VERSION 5.8 ;
BUSBITCHARS "[]" ;
DIVIDERCHAR "/" ;
UNITS
    DATABASE MICRONS 1000 ;
END UNITS

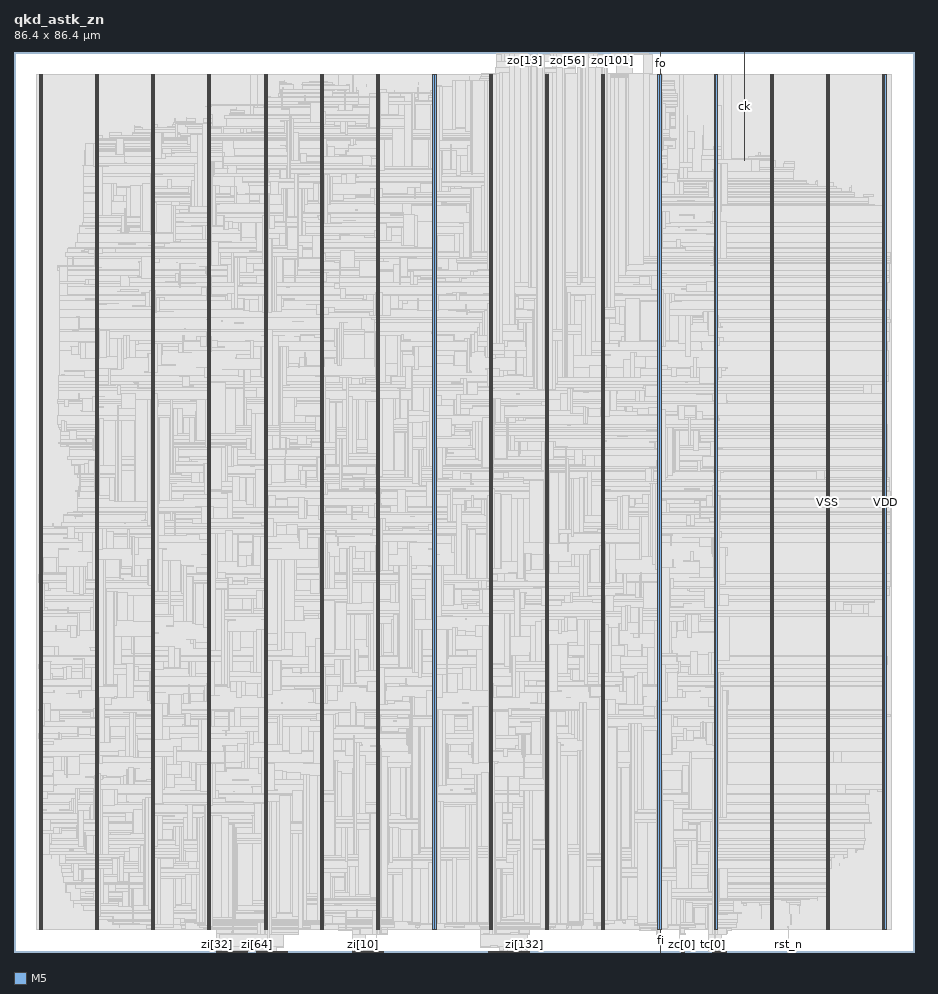
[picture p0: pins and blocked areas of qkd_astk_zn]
MACRO qkd_astk_zn
  FOREIGN qkd_astk_zn 0 0 ;
  CLASS BLOCK ;
  SIZE 86.4 BY 86.4 ;
  PIN ck
    DIRECTION INPUT ;
    USE SIGNAL ;
    PORT
      LAYER M5 ;
        RECT  70.128 86.316 70.152 86.4 ;
    END
    PORT
      LAYER M5 ;
        RECT  70.128 75.971 70.152 86.352 ;
    END
  END ck
  PIN fi
    DIRECTION INPUT ;
    USE SIGNAL ;
    PORT
      LAYER M5 ;
        RECT  62.064 0 62.088 0.084 ;
    END
    PORT
      LAYER M5 ;
        RECT  62.064 0.016 62.088 2.137 ;
    END
  END fi
  PIN fo
    DIRECTION OUTPUT ;
    USE SIGNAL ;
    PORT
      LAYER M5 ;
        RECT  62.064 86.316 62.088 86.4 ;
    END
    PORT
      LAYER M5 ;
        RECT  62.064 84.263 62.088 86.352 ;
    END
  END fo
  PIN rst_n
    DIRECTION INPUT ;
    USE SIGNAL ;
    PORT
      LAYER M5 ;
        RECT  74.352 0 74.376 0.084 ;
    END
    PORT
      LAYER M5 ;
        RECT  74.352 0.016 74.376 0.611 ;
    END
  END rst_n
  PIN tc[0]
    DIRECTION INPUT ;
    USE SIGNAL ;
    PORT
      LAYER M5 ;
        RECT  67.056 0 67.08 0.084 ;
    END
  END tc[0]
  PIN tc[10]
    DIRECTION INPUT ;
    USE SIGNAL ;
    PORT
      LAYER M5 ;
        RECT  68.016 0 68.04 0.084 ;
    END
  END tc[10]
  PIN tc[11]
    DIRECTION INPUT ;
    USE SIGNAL ;
    PORT
      LAYER M5 ;
        RECT  68.112 0 68.136 0.084 ;
    END
  END tc[11]
  PIN tc[12]
    DIRECTION INPUT ;
    USE SIGNAL ;
    PORT
      LAYER M5 ;
        RECT  68.208 0 68.232 0.084 ;
    END
  END tc[12]
  PIN tc[13]
    DIRECTION INPUT ;
    USE SIGNAL ;
    PORT
      LAYER M5 ;
        RECT  68.304 0 68.328 0.084 ;
    END
  END tc[13]
  PIN tc[14]
    DIRECTION INPUT ;
    USE SIGNAL ;
    PORT
      LAYER M5 ;
        RECT  68.4 0 68.424 0.084 ;
    END
  END tc[14]
  PIN tc[1]
    DIRECTION INPUT ;
    USE SIGNAL ;
    PORT
      LAYER M5 ;
        RECT  67.152 0 67.176 0.084 ;
    END
  END tc[1]
  PIN tc[2]
    DIRECTION INPUT ;
    USE SIGNAL ;
    PORT
      LAYER M5 ;
        RECT  67.248 0 67.272 0.084 ;
    END
  END tc[2]
  PIN tc[3]
    DIRECTION INPUT ;
    USE SIGNAL ;
    PORT
      LAYER M5 ;
        RECT  67.344 0 67.368 0.084 ;
    END
  END tc[3]
  PIN tc[4]
    DIRECTION INPUT ;
    USE SIGNAL ;
    PORT
      LAYER M5 ;
        RECT  67.44 0 67.464 0.084 ;
    END
  END tc[4]
  PIN tc[5]
    DIRECTION INPUT ;
    USE SIGNAL ;
    PORT
      LAYER M5 ;
        RECT  67.536 0 67.56 0.084 ;
    END
  END tc[5]
  PIN tc[6]
    DIRECTION INPUT ;
    USE SIGNAL ;
    PORT
      LAYER M5 ;
        RECT  67.632 0 67.656 0.084 ;
    END
  END tc[6]
  PIN tc[7]
    DIRECTION INPUT ;
    USE SIGNAL ;
    PORT
      LAYER M5 ;
        RECT  67.728 0 67.752 0.084 ;
    END
  END tc[7]
  PIN tc[8]
    DIRECTION INPUT ;
    USE SIGNAL ;
    PORT
      LAYER M5 ;
        RECT  67.824 0 67.848 0.084 ;
    END
  END tc[8]
  PIN tc[9]
    DIRECTION INPUT ;
    USE SIGNAL ;
    PORT
      LAYER M5 ;
        RECT  67.92 0 67.944 0.084 ;
    END
  END tc[9]
  PIN zc[0]
    DIRECTION INPUT ;
    USE SIGNAL ;
    PORT
      LAYER M5 ;
        RECT  64.08 0 64.104 0.084 ;
    END
  END zc[0]
  PIN zc[1]
    DIRECTION INPUT ;
    USE SIGNAL ;
    PORT
      LAYER M5 ;
        RECT  64.176 0 64.2 0.084 ;
    END
  END zc[1]
  PIN zc[2]
    DIRECTION INPUT ;
    USE SIGNAL ;
    PORT
      LAYER M5 ;
        RECT  64.272 0 64.296 0.084 ;
    END
  END zc[2]
  PIN zc[3]
    DIRECTION INPUT ;
    USE SIGNAL ;
    PORT
      LAYER M5 ;
        RECT  64.368 0 64.392 0.084 ;
    END
  END zc[3]
  PIN zi[0]
    DIRECTION INPUT ;
    USE SIGNAL ;
    PORT
      LAYER M5 ;
        RECT  32.496 0 32.52 0.084 ;
    END
  END zi[0]
  PIN zi[100]
    DIRECTION INPUT ;
    USE SIGNAL ;
    PORT
      LAYER M5 ;
        RECT  45.936 0 45.96 0.084 ;
    END
  END zi[100]
  PIN zi[101]
    DIRECTION INPUT ;
    USE SIGNAL ;
    PORT
      LAYER M5 ;
        RECT  46.032 0 46.056 0.084 ;
    END
  END zi[101]
  PIN zi[102]
    DIRECTION INPUT ;
    USE SIGNAL ;
    PORT
      LAYER M5 ;
        RECT  46.128 0 46.152 0.084 ;
    END
  END zi[102]
  PIN zi[103]
    DIRECTION INPUT ;
    USE SIGNAL ;
    PORT
      LAYER M5 ;
        RECT  46.224 0 46.248 0.084 ;
    END
  END zi[103]
  PIN zi[104]
    DIRECTION INPUT ;
    USE SIGNAL ;
    PORT
      LAYER M5 ;
        RECT  46.32 0 46.344 0.084 ;
    END
  END zi[104]
  PIN zi[105]
    DIRECTION INPUT ;
    USE SIGNAL ;
    PORT
      LAYER M5 ;
        RECT  46.416 0 46.44 0.084 ;
    END
  END zi[105]
  PIN zi[106]
    DIRECTION INPUT ;
    USE SIGNAL ;
    PORT
      LAYER M5 ;
        RECT  46.512 0 46.536 0.084 ;
    END
  END zi[106]
  PIN zi[107]
    DIRECTION INPUT ;
    USE SIGNAL ;
    PORT
      LAYER M5 ;
        RECT  46.608 0 46.632 0.084 ;
    END
  END zi[107]
  PIN zi[108]
    DIRECTION INPUT ;
    USE SIGNAL ;
    PORT
      LAYER M5 ;
        RECT  46.704 0 46.728 0.084 ;
    END
  END zi[108]
  PIN zi[109]
    DIRECTION INPUT ;
    USE SIGNAL ;
    PORT
      LAYER M5 ;
        RECT  46.8 0 46.824 0.084 ;
    END
  END zi[109]
  PIN zi[10]
    DIRECTION INPUT ;
    USE SIGNAL ;
    PORT
      LAYER M5 ;
        RECT  33.456 0 33.48 0.084 ;
    END
  END zi[10]
  PIN zi[110]
    DIRECTION INPUT ;
    USE SIGNAL ;
    PORT
      LAYER M5 ;
        RECT  46.896 0 46.92 0.084 ;
    END
  END zi[110]
  PIN zi[111]
    DIRECTION INPUT ;
    USE SIGNAL ;
    PORT
      LAYER M5 ;
        RECT  46.992 0 47.016 0.084 ;
    END
  END zi[111]
  PIN zi[112]
    DIRECTION INPUT ;
    USE SIGNAL ;
    PORT
      LAYER M5 ;
        RECT  47.088 0 47.112 0.084 ;
    END
  END zi[112]
  PIN zi[113]
    DIRECTION INPUT ;
    USE SIGNAL ;
    PORT
      LAYER M5 ;
        RECT  47.184 0 47.208 0.084 ;
    END
  END zi[113]
  PIN zi[114]
    DIRECTION INPUT ;
    USE SIGNAL ;
    PORT
      LAYER M5 ;
        RECT  47.28 0 47.304 0.084 ;
    END
  END zi[114]
  PIN zi[115]
    DIRECTION INPUT ;
    USE SIGNAL ;
    PORT
      LAYER M5 ;
        RECT  47.376 0 47.4 0.084 ;
    END
  END zi[115]
  PIN zi[116]
    DIRECTION INPUT ;
    USE SIGNAL ;
    PORT
      LAYER M5 ;
        RECT  47.472 0 47.496 0.084 ;
    END
  END zi[116]
  PIN zi[117]
    DIRECTION INPUT ;
    USE SIGNAL ;
    PORT
      LAYER M5 ;
        RECT  47.568 0 47.592 0.084 ;
    END
  END zi[117]
  PIN zi[118]
    DIRECTION INPUT ;
    USE SIGNAL ;
    PORT
      LAYER M5 ;
        RECT  47.664 0 47.688 0.084 ;
    END
  END zi[118]
  PIN zi[119]
    DIRECTION INPUT ;
    USE SIGNAL ;
    PORT
      LAYER M5 ;
        RECT  47.76 0 47.784 0.084 ;
    END
  END zi[119]
  PIN zi[11]
    DIRECTION INPUT ;
    USE SIGNAL ;
    PORT
      LAYER M5 ;
        RECT  33.552 0 33.576 0.084 ;
    END
  END zi[11]
  PIN zi[120]
    DIRECTION INPUT ;
    USE SIGNAL ;
    PORT
      LAYER M5 ;
        RECT  47.856 0 47.88 0.084 ;
    END
  END zi[120]
  PIN zi[121]
    DIRECTION INPUT ;
    USE SIGNAL ;
    PORT
      LAYER M5 ;
        RECT  47.952 0 47.976 0.084 ;
    END
  END zi[121]
  PIN zi[122]
    DIRECTION INPUT ;
    USE SIGNAL ;
    PORT
      LAYER M5 ;
        RECT  48.048 0 48.072 0.084 ;
    END
  END zi[122]
  PIN zi[123]
    DIRECTION INPUT ;
    USE SIGNAL ;
    PORT
      LAYER M5 ;
        RECT  48.144 0 48.168 0.084 ;
    END
  END zi[123]
  PIN zi[124]
    DIRECTION INPUT ;
    USE SIGNAL ;
    PORT
      LAYER M5 ;
        RECT  48.24 0 48.264 0.084 ;
    END
  END zi[124]
  PIN zi[125]
    DIRECTION INPUT ;
    USE SIGNAL ;
    PORT
      LAYER M5 ;
        RECT  48.336 0 48.36 0.084 ;
    END
  END zi[125]
  PIN zi[126]
    DIRECTION INPUT ;
    USE SIGNAL ;
    PORT
      LAYER M5 ;
        RECT  48.432 0 48.456 0.084 ;
    END
  END zi[126]
  PIN zi[127]
    DIRECTION INPUT ;
    USE SIGNAL ;
    PORT
      LAYER M5 ;
        RECT  48.528 0 48.552 0.084 ;
    END
  END zi[127]
  PIN zi[128]
    DIRECTION INPUT ;
    USE SIGNAL ;
    PORT
      LAYER M5 ;
        RECT  48.624 0 48.648 0.084 ;
    END
  END zi[128]
  PIN zi[129]
    DIRECTION INPUT ;
    USE SIGNAL ;
    PORT
      LAYER M5 ;
        RECT  48.72 0 48.744 0.084 ;
    END
  END zi[129]
  PIN zi[12]
    DIRECTION INPUT ;
    USE SIGNAL ;
    PORT
      LAYER M5 ;
        RECT  33.648 0 33.672 0.084 ;
    END
  END zi[12]
  PIN zi[130]
    DIRECTION INPUT ;
    USE SIGNAL ;
    PORT
      LAYER M5 ;
        RECT  48.816 0 48.84 0.084 ;
    END
  END zi[130]
  PIN zi[131]
    DIRECTION INPUT ;
    USE SIGNAL ;
    PORT
      LAYER M5 ;
        RECT  48.912 0 48.936 0.084 ;
    END
  END zi[131]
  PIN zi[132]
    DIRECTION INPUT ;
    USE SIGNAL ;
    PORT
      LAYER M5 ;
        RECT  49.008 0 49.032 0.084 ;
    END
  END zi[132]
  PIN zi[133]
    DIRECTION INPUT ;
    USE SIGNAL ;
    PORT
      LAYER M5 ;
        RECT  49.104 0 49.128 0.084 ;
    END
  END zi[133]
  PIN zi[134]
    DIRECTION INPUT ;
    USE SIGNAL ;
    PORT
      LAYER M5 ;
        RECT  49.2 0 49.224 0.084 ;
    END
  END zi[134]
  PIN zi[135]
    DIRECTION INPUT ;
    USE SIGNAL ;
    PORT
      LAYER M5 ;
        RECT  49.296 0 49.32 0.084 ;
    END
  END zi[135]
  PIN zi[136]
    DIRECTION INPUT ;
    USE SIGNAL ;
    PORT
      LAYER M5 ;
        RECT  49.392 0 49.416 0.084 ;
    END
  END zi[136]
  PIN zi[137]
    DIRECTION INPUT ;
    USE SIGNAL ;
    PORT
      LAYER M5 ;
        RECT  49.488 0 49.512 0.084 ;
    END
  END zi[137]
  PIN zi[13]
    DIRECTION INPUT ;
    USE SIGNAL ;
    PORT
      LAYER M5 ;
        RECT  33.744 0 33.768 0.084 ;
    END
  END zi[13]
  PIN zi[14]
    DIRECTION INPUT ;
    USE SIGNAL ;
    PORT
      LAYER M5 ;
        RECT  33.84 0 33.864 0.084 ;
    END
  END zi[14]
  PIN zi[15]
    DIRECTION INPUT ;
    USE SIGNAL ;
    PORT
      LAYER M5 ;
        RECT  33.936 0 33.96 0.084 ;
    END
  END zi[15]
  PIN zi[16]
    DIRECTION INPUT ;
    USE SIGNAL ;
    PORT
      LAYER M5 ;
        RECT  34.032 0 34.056 0.084 ;
    END
  END zi[16]
  PIN zi[17]
    DIRECTION INPUT ;
    USE SIGNAL ;
    PORT
      LAYER M5 ;
        RECT  34.128 0 34.152 0.084 ;
    END
  END zi[17]
  PIN zi[18]
    DIRECTION INPUT ;
    USE SIGNAL ;
    PORT
      LAYER M5 ;
        RECT  34.224 0 34.248 0.084 ;
    END
  END zi[18]
  PIN zi[19]
    DIRECTION INPUT ;
    USE SIGNAL ;
    PORT
      LAYER M5 ;
        RECT  34.32 0 34.344 0.084 ;
    END
  END zi[19]
  PIN zi[1]
    DIRECTION INPUT ;
    USE SIGNAL ;
    PORT
      LAYER M5 ;
        RECT  32.592 0 32.616 0.084 ;
    END
  END zi[1]
  PIN zi[20]
    DIRECTION INPUT ;
    USE SIGNAL ;
    PORT
      LAYER M5 ;
        RECT  34.416 0 34.44 0.084 ;
    END
  END zi[20]
  PIN zi[21]
    DIRECTION INPUT ;
    USE SIGNAL ;
    PORT
      LAYER M5 ;
        RECT  34.512 0 34.536 0.084 ;
    END
  END zi[21]
  PIN zi[22]
    DIRECTION INPUT ;
    USE SIGNAL ;
    PORT
      LAYER M5 ;
        RECT  34.608 0 34.632 0.084 ;
    END
  END zi[22]
  PIN zi[23]
    DIRECTION INPUT ;
    USE SIGNAL ;
    PORT
      LAYER M5 ;
        RECT  34.704 0 34.728 0.084 ;
    END
  END zi[23]
  PIN zi[24]
    DIRECTION INPUT ;
    USE SIGNAL ;
    PORT
      LAYER M5 ;
        RECT  34.8 0 34.824 0.084 ;
    END
  END zi[24]
  PIN zi[25]
    DIRECTION INPUT ;
    USE SIGNAL ;
    PORT
      LAYER M5 ;
        RECT  34.896 0 34.92 0.084 ;
    END
  END zi[25]
  PIN zi[26]
    DIRECTION INPUT ;
    USE SIGNAL ;
    PORT
      LAYER M5 ;
        RECT  34.992 0 35.016 0.084 ;
    END
  END zi[26]
  PIN zi[27]
    DIRECTION INPUT ;
    USE SIGNAL ;
    PORT
      LAYER M5 ;
        RECT  35.088 0 35.112 0.084 ;
    END
  END zi[27]
  PIN zi[28]
    DIRECTION INPUT ;
    USE SIGNAL ;
    PORT
      LAYER M5 ;
        RECT  35.184 0 35.208 0.084 ;
    END
  END zi[28]
  PIN zi[29]
    DIRECTION INPUT ;
    USE SIGNAL ;
    PORT
      LAYER M5 ;
        RECT  35.28 0 35.304 0.084 ;
    END
  END zi[29]
  PIN zi[2]
    DIRECTION INPUT ;
    USE SIGNAL ;
    PORT
      LAYER M5 ;
        RECT  32.688 0 32.712 0.084 ;
    END
  END zi[2]
  PIN zi[30]
    DIRECTION INPUT ;
    USE SIGNAL ;
    PORT
      LAYER M5 ;
        RECT  35.376 0 35.4 0.084 ;
    END
  END zi[30]
  PIN zi[31]
    DIRECTION INPUT ;
    USE SIGNAL ;
    PORT
      LAYER M5 ;
        RECT  35.472 0 35.496 0.084 ;
    END
  END zi[31]
  PIN zi[32]
    DIRECTION INPUT ;
    USE SIGNAL ;
    PORT
      LAYER M5 ;
        RECT  19.44 0 19.464 0.084 ;
    END
  END zi[32]
  PIN zi[33]
    DIRECTION INPUT ;
    USE SIGNAL ;
    PORT
      LAYER M5 ;
        RECT  19.536 0 19.56 0.084 ;
    END
  END zi[33]
  PIN zi[34]
    DIRECTION INPUT ;
    USE SIGNAL ;
    PORT
      LAYER M5 ;
        RECT  19.632 0 19.656 0.084 ;
    END
  END zi[34]
  PIN zi[35]
    DIRECTION INPUT ;
    USE SIGNAL ;
    PORT
      LAYER M5 ;
        RECT  19.728 0 19.752 0.084 ;
    END
  END zi[35]
  PIN zi[36]
    DIRECTION INPUT ;
    USE SIGNAL ;
    PORT
      LAYER M5 ;
        RECT  19.824 0 19.848 0.084 ;
    END
  END zi[36]
  PIN zi[37]
    DIRECTION INPUT ;
    USE SIGNAL ;
    PORT
      LAYER M5 ;
        RECT  19.92 0 19.944 0.084 ;
    END
  END zi[37]
  PIN zi[38]
    DIRECTION INPUT ;
    USE SIGNAL ;
    PORT
      LAYER M5 ;
        RECT  20.016 0 20.04 0.084 ;
    END
  END zi[38]
  PIN zi[39]
    DIRECTION INPUT ;
    USE SIGNAL ;
    PORT
      LAYER M5 ;
        RECT  20.112 0 20.136 0.084 ;
    END
  END zi[39]
  PIN zi[3]
    DIRECTION INPUT ;
    USE SIGNAL ;
    PORT
      LAYER M5 ;
        RECT  32.784 0 32.808 0.084 ;
    END
  END zi[3]
  PIN zi[40]
    DIRECTION INPUT ;
    USE SIGNAL ;
    PORT
      LAYER M5 ;
        RECT  20.208 0 20.232 0.084 ;
    END
  END zi[40]
  PIN zi[41]
    DIRECTION INPUT ;
    USE SIGNAL ;
    PORT
      LAYER M5 ;
        RECT  20.304 0 20.328 0.084 ;
    END
  END zi[41]
  PIN zi[42]
    DIRECTION INPUT ;
    USE SIGNAL ;
    PORT
      LAYER M5 ;
        RECT  20.4 0 20.424 0.084 ;
    END
  END zi[42]
  PIN zi[43]
    DIRECTION INPUT ;
    USE SIGNAL ;
    PORT
      LAYER M5 ;
        RECT  20.496 0 20.52 0.084 ;
    END
  END zi[43]
  PIN zi[44]
    DIRECTION INPUT ;
    USE SIGNAL ;
    PORT
      LAYER M5 ;
        RECT  20.592 0 20.616 0.084 ;
    END
  END zi[44]
  PIN zi[45]
    DIRECTION INPUT ;
    USE SIGNAL ;
    PORT
      LAYER M5 ;
        RECT  20.688 0 20.712 0.084 ;
    END
  END zi[45]
  PIN zi[46]
    DIRECTION INPUT ;
    USE SIGNAL ;
    PORT
      LAYER M5 ;
        RECT  20.784 0 20.808 0.084 ;
    END
  END zi[46]
  PIN zi[47]
    DIRECTION INPUT ;
    USE SIGNAL ;
    PORT
      LAYER M5 ;
        RECT  20.88 0 20.904 0.084 ;
    END
  END zi[47]
  PIN zi[48]
    DIRECTION INPUT ;
    USE SIGNAL ;
    PORT
      LAYER M5 ;
        RECT  20.976 0 21 0.084 ;
    END
  END zi[48]
  PIN zi[49]
    DIRECTION INPUT ;
    USE SIGNAL ;
    PORT
      LAYER M5 ;
        RECT  21.072 0 21.096 0.084 ;
    END
  END zi[49]
  PIN zi[4]
    DIRECTION INPUT ;
    USE SIGNAL ;
    PORT
      LAYER M5 ;
        RECT  32.88 0 32.904 0.084 ;
    END
  END zi[4]
  PIN zi[50]
    DIRECTION INPUT ;
    USE SIGNAL ;
    PORT
      LAYER M5 ;
        RECT  21.168 0 21.192 0.084 ;
    END
  END zi[50]
  PIN zi[51]
    DIRECTION INPUT ;
    USE SIGNAL ;
    PORT
      LAYER M5 ;
        RECT  21.264 0 21.288 0.084 ;
    END
  END zi[51]
  PIN zi[52]
    DIRECTION INPUT ;
    USE SIGNAL ;
    PORT
      LAYER M5 ;
        RECT  21.36 0 21.384 0.084 ;
    END
  END zi[52]
  PIN zi[53]
    DIRECTION INPUT ;
    USE SIGNAL ;
    PORT
      LAYER M5 ;
        RECT  21.456 0 21.48 0.084 ;
    END
  END zi[53]
  PIN zi[54]
    DIRECTION INPUT ;
    USE SIGNAL ;
    PORT
      LAYER M5 ;
        RECT  21.552 0 21.576 0.084 ;
    END
  END zi[54]
  PIN zi[55]
    DIRECTION INPUT ;
    USE SIGNAL ;
    PORT
      LAYER M5 ;
        RECT  21.648 0 21.672 0.084 ;
    END
  END zi[55]
  PIN zi[56]
    DIRECTION INPUT ;
    USE SIGNAL ;
    PORT
      LAYER M5 ;
        RECT  21.744 0 21.768 0.084 ;
    END
  END zi[56]
  PIN zi[57]
    DIRECTION INPUT ;
    USE SIGNAL ;
    PORT
      LAYER M5 ;
        RECT  21.84 0 21.864 0.084 ;
    END
  END zi[57]
  PIN zi[58]
    DIRECTION INPUT ;
    USE SIGNAL ;
    PORT
      LAYER M5 ;
        RECT  21.936 0 21.96 0.084 ;
    END
  END zi[58]
  PIN zi[59]
    DIRECTION INPUT ;
    USE SIGNAL ;
    PORT
      LAYER M5 ;
        RECT  22.032 0 22.056 0.084 ;
    END
  END zi[59]
  PIN zi[5]
    DIRECTION INPUT ;
    USE SIGNAL ;
    PORT
      LAYER M5 ;
        RECT  32.976 0 33 0.084 ;
    END
  END zi[5]
  PIN zi[60]
    DIRECTION INPUT ;
    USE SIGNAL ;
    PORT
      LAYER M5 ;
        RECT  22.128 0 22.152 0.084 ;
    END
  END zi[60]
  PIN zi[61]
    DIRECTION INPUT ;
    USE SIGNAL ;
    PORT
      LAYER M5 ;
        RECT  22.224 0 22.248 0.084 ;
    END
  END zi[61]
  PIN zi[62]
    DIRECTION INPUT ;
    USE SIGNAL ;
    PORT
      LAYER M5 ;
        RECT  22.32 0 22.344 0.084 ;
    END
  END zi[62]
  PIN zi[63]
    DIRECTION INPUT ;
    USE SIGNAL ;
    PORT
      LAYER M5 ;
        RECT  22.416 0 22.44 0.084 ;
    END
  END zi[63]
  PIN zi[64]
    DIRECTION INPUT ;
    USE SIGNAL ;
    PORT
      LAYER M5 ;
        RECT  23.28 0 23.304 0.084 ;
    END
  END zi[64]
  PIN zi[65]
    DIRECTION INPUT ;
    USE SIGNAL ;
    PORT
      LAYER M5 ;
        RECT  23.376 0 23.4 0.084 ;
    END
  END zi[65]
  PIN zi[66]
    DIRECTION INPUT ;
    USE SIGNAL ;
    PORT
      LAYER M5 ;
        RECT  23.472 0 23.496 0.084 ;
    END
  END zi[66]
  PIN zi[67]
    DIRECTION INPUT ;
    USE SIGNAL ;
    PORT
      LAYER M5 ;
        RECT  23.568 0 23.592 0.084 ;
    END
  END zi[67]
  PIN zi[68]
    DIRECTION INPUT ;
    USE SIGNAL ;
    PORT
      LAYER M5 ;
        RECT  23.664 0 23.688 0.084 ;
    END
  END zi[68]
  PIN zi[69]
    DIRECTION INPUT ;
    USE SIGNAL ;
    PORT
      LAYER M5 ;
        RECT  23.76 0 23.784 0.084 ;
    END
  END zi[69]
  PIN zi[6]
    DIRECTION INPUT ;
    USE SIGNAL ;
    PORT
      LAYER M5 ;
        RECT  33.072 0 33.096 0.084 ;
    END
  END zi[6]
  PIN zi[70]
    DIRECTION INPUT ;
    USE SIGNAL ;
    PORT
      LAYER M5 ;
        RECT  23.856 0 23.88 0.084 ;
    END
  END zi[70]
  PIN zi[71]
    DIRECTION INPUT ;
    USE SIGNAL ;
    PORT
      LAYER M5 ;
        RECT  23.952 0 23.976 0.084 ;
    END
  END zi[71]
  PIN zi[72]
    DIRECTION INPUT ;
    USE SIGNAL ;
    PORT
      LAYER M5 ;
        RECT  24.048 0 24.072 0.084 ;
    END
  END zi[72]
  PIN zi[73]
    DIRECTION INPUT ;
    USE SIGNAL ;
    PORT
      LAYER M5 ;
        RECT  24.144 0 24.168 0.084 ;
    END
  END zi[73]
  PIN zi[74]
    DIRECTION INPUT ;
    USE SIGNAL ;
    PORT
      LAYER M5 ;
        RECT  24.24 0 24.264 0.084 ;
    END
  END zi[74]
  PIN zi[75]
    DIRECTION INPUT ;
    USE SIGNAL ;
    PORT
      LAYER M5 ;
        RECT  24.336 0 24.36 0.084 ;
    END
  END zi[75]
  PIN zi[76]
    DIRECTION INPUT ;
    USE SIGNAL ;
    PORT
      LAYER M5 ;
        RECT  24.432 0 24.456 0.084 ;
    END
  END zi[76]
  PIN zi[77]
    DIRECTION INPUT ;
    USE SIGNAL ;
    PORT
      LAYER M5 ;
        RECT  24.528 0 24.552 0.084 ;
    END
  END zi[77]
  PIN zi[78]
    DIRECTION INPUT ;
    USE SIGNAL ;
    PORT
      LAYER M5 ;
        RECT  24.624 0 24.648 0.084 ;
    END
  END zi[78]
  PIN zi[79]
    DIRECTION INPUT ;
    USE SIGNAL ;
    PORT
      LAYER M5 ;
        RECT  24.72 0 24.744 0.084 ;
    END
  END zi[79]
  PIN zi[7]
    DIRECTION INPUT ;
    USE SIGNAL ;
    PORT
      LAYER M5 ;
        RECT  33.168 0 33.192 0.084 ;
    END
  END zi[7]
  PIN zi[80]
    DIRECTION INPUT ;
    USE SIGNAL ;
    PORT
      LAYER M5 ;
        RECT  24.816 0 24.84 0.084 ;
    END
  END zi[80]
  PIN zi[81]
    DIRECTION INPUT ;
    USE SIGNAL ;
    PORT
      LAYER M5 ;
        RECT  24.912 0 24.936 0.084 ;
    END
  END zi[81]
  PIN zi[82]
    DIRECTION INPUT ;
    USE SIGNAL ;
    PORT
      LAYER M5 ;
        RECT  25.008 0 25.032 0.084 ;
    END
  END zi[82]
  PIN zi[83]
    DIRECTION INPUT ;
    USE SIGNAL ;
    PORT
      LAYER M5 ;
        RECT  25.104 0 25.128 0.084 ;
    END
  END zi[83]
  PIN zi[84]
    DIRECTION INPUT ;
    USE SIGNAL ;
    PORT
      LAYER M5 ;
        RECT  25.2 0 25.224 0.084 ;
    END
  END zi[84]
  PIN zi[85]
    DIRECTION INPUT ;
    USE SIGNAL ;
    PORT
      LAYER M5 ;
        RECT  25.296 0 25.32 0.084 ;
    END
  END zi[85]
  PIN zi[86]
    DIRECTION INPUT ;
    USE SIGNAL ;
    PORT
      LAYER M5 ;
        RECT  25.392 0 25.416 0.084 ;
    END
  END zi[86]
  PIN zi[87]
    DIRECTION INPUT ;
    USE SIGNAL ;
    PORT
      LAYER M5 ;
        RECT  25.488 0 25.512 0.084 ;
    END
  END zi[87]
  PIN zi[88]
    DIRECTION INPUT ;
    USE SIGNAL ;
    PORT
      LAYER M5 ;
        RECT  25.584 0 25.608 0.084 ;
    END
  END zi[88]
  PIN zi[89]
    DIRECTION INPUT ;
    USE SIGNAL ;
    PORT
      LAYER M5 ;
        RECT  25.68 0 25.704 0.084 ;
    END
  END zi[89]
  PIN zi[8]
    DIRECTION INPUT ;
    USE SIGNAL ;
    PORT
      LAYER M5 ;
        RECT  33.264 0 33.288 0.084 ;
    END
  END zi[8]
  PIN zi[90]
    DIRECTION INPUT ;
    USE SIGNAL ;
    PORT
      LAYER M5 ;
        RECT  25.776 0 25.8 0.084 ;
    END
  END zi[90]
  PIN zi[91]
    DIRECTION INPUT ;
    USE SIGNAL ;
    PORT
      LAYER M5 ;
        RECT  25.872 0 25.896 0.084 ;
    END
  END zi[91]
  PIN zi[92]
    DIRECTION INPUT ;
    USE SIGNAL ;
    PORT
      LAYER M5 ;
        RECT  25.968 0 25.992 0.084 ;
    END
  END zi[92]
  PIN zi[93]
    DIRECTION INPUT ;
    USE SIGNAL ;
    PORT
      LAYER M5 ;
        RECT  26.064 0 26.088 0.084 ;
    END
  END zi[93]
  PIN zi[94]
    DIRECTION INPUT ;
    USE SIGNAL ;
    PORT
      LAYER M5 ;
        RECT  26.16 0 26.184 0.084 ;
    END
  END zi[94]
  PIN zi[95]
    DIRECTION INPUT ;
    USE SIGNAL ;
    PORT
      LAYER M5 ;
        RECT  26.256 0 26.28 0.084 ;
    END
  END zi[95]
  PIN zi[96]
    DIRECTION INPUT ;
    USE SIGNAL ;
    PORT
      LAYER M5 ;
        RECT  45.552 0 45.576 0.084 ;
    END
  END zi[96]
  PIN zi[97]
    DIRECTION INPUT ;
    USE SIGNAL ;
    PORT
      LAYER M5 ;
        RECT  45.648 0 45.672 0.084 ;
    END
  END zi[97]
  PIN zi[98]
    DIRECTION INPUT ;
    USE SIGNAL ;
    PORT
      LAYER M5 ;
        RECT  45.744 0 45.768 0.084 ;
    END
  END zi[98]
  PIN zi[99]
    DIRECTION INPUT ;
    USE SIGNAL ;
    PORT
      LAYER M5 ;
        RECT  45.84 0 45.864 0.084 ;
    END
  END zi[99]
  PIN zi[9]
    DIRECTION INPUT ;
    USE SIGNAL ;
    PORT
      LAYER M5 ;
        RECT  33.36 0 33.384 0.084 ;
    END
  END zi[9]
  PIN zo[0]
    DIRECTION OUTPUT ;
    USE SIGNAL ;
    PORT
      LAYER M5 ;
        RECT  47.76 86.316 47.784 86.4 ;
    END
  END zo[0]
  PIN zo[100]
    DIRECTION OUTPUT ;
    USE SIGNAL ;
    PORT
      LAYER M5 ;
        RECT  57.36 86.316 57.384 86.4 ;
    END
  END zo[100]
  PIN zo[101]
    DIRECTION OUTPUT ;
    USE SIGNAL ;
    PORT
      LAYER M5 ;
        RECT  57.456 86.316 57.48 86.4 ;
    END
  END zo[101]
  PIN zo[102]
    DIRECTION OUTPUT ;
    USE SIGNAL ;
    PORT
      LAYER M5 ;
        RECT  57.552 86.316 57.576 86.4 ;
    END
  END zo[102]
  PIN zo[103]
    DIRECTION OUTPUT ;
    USE SIGNAL ;
    PORT
      LAYER M5 ;
        RECT  57.648 86.316 57.672 86.4 ;
    END
  END zo[103]
  PIN zo[104]
    DIRECTION OUTPUT ;
    USE SIGNAL ;
    PORT
      LAYER M5 ;
        RECT  57.744 86.316 57.768 86.4 ;
    END
  END zo[104]
  PIN zo[105]
    DIRECTION OUTPUT ;
    USE SIGNAL ;
    PORT
      LAYER M5 ;
        RECT  57.84 86.316 57.864 86.4 ;
    END
  END zo[105]
  PIN zo[106]
    DIRECTION OUTPUT ;
    USE SIGNAL ;
    PORT
      LAYER M5 ;
        RECT  57.936 86.316 57.96 86.4 ;
    END
  END zo[106]
  PIN zo[107]
    DIRECTION OUTPUT ;
    USE SIGNAL ;
    PORT
      LAYER M5 ;
        RECT  58.032 86.316 58.056 86.4 ;
    END
  END zo[107]
  PIN zo[108]
    DIRECTION OUTPUT ;
    USE SIGNAL ;
    PORT
      LAYER M5 ;
        RECT  58.128 86.316 58.152 86.4 ;
    END
  END zo[108]
  PIN zo[109]
    DIRECTION OUTPUT ;
    USE SIGNAL ;
    PORT
      LAYER M5 ;
        RECT  58.224 86.316 58.248 86.4 ;
    END
  END zo[109]
  PIN zo[10]
    DIRECTION OUTPUT ;
    USE SIGNAL ;
    PORT
      LAYER M5 ;
        RECT  48.72 86.316 48.744 86.4 ;
    END
  END zo[10]
  PIN zo[110]
    DIRECTION OUTPUT ;
    USE SIGNAL ;
    PORT
      LAYER M5 ;
        RECT  58.32 86.316 58.344 86.4 ;
    END
  END zo[110]
  PIN zo[111]
    DIRECTION OUTPUT ;
    USE SIGNAL ;
    PORT
      LAYER M5 ;
        RECT  58.416 86.316 58.44 86.4 ;
    END
  END zo[111]
  PIN zo[112]
    DIRECTION OUTPUT ;
    USE SIGNAL ;
    PORT
      LAYER M5 ;
        RECT  58.512 86.316 58.536 86.4 ;
    END
  END zo[112]
  PIN zo[113]
    DIRECTION OUTPUT ;
    USE SIGNAL ;
    PORT
      LAYER M5 ;
        RECT  58.608 86.316 58.632 86.4 ;
    END
  END zo[113]
  PIN zo[114]
    DIRECTION OUTPUT ;
    USE SIGNAL ;
    PORT
      LAYER M5 ;
        RECT  58.704 86.316 58.728 86.4 ;
    END
  END zo[114]
  PIN zo[115]
    DIRECTION OUTPUT ;
    USE SIGNAL ;
    PORT
      LAYER M5 ;
        RECT  58.8 86.316 58.824 86.4 ;
    END
  END zo[115]
  PIN zo[116]
    DIRECTION OUTPUT ;
    USE SIGNAL ;
    PORT
      LAYER M5 ;
        RECT  58.896 86.316 58.92 86.4 ;
    END
  END zo[116]
  PIN zo[117]
    DIRECTION OUTPUT ;
    USE SIGNAL ;
    PORT
      LAYER M5 ;
        RECT  58.992 86.316 59.016 86.4 ;
    END
  END zo[117]
  PIN zo[118]
    DIRECTION OUTPUT ;
    USE SIGNAL ;
    PORT
      LAYER M5 ;
        RECT  59.088 86.316 59.112 86.4 ;
    END
  END zo[118]
  PIN zo[119]
    DIRECTION OUTPUT ;
    USE SIGNAL ;
    PORT
      LAYER M5 ;
        RECT  59.184 86.316 59.208 86.4 ;
    END
  END zo[119]
  PIN zo[11]
    DIRECTION OUTPUT ;
    USE SIGNAL ;
    PORT
      LAYER M5 ;
        RECT  48.816 86.316 48.84 86.4 ;
    END
  END zo[11]
  PIN zo[120]
    DIRECTION OUTPUT ;
    USE SIGNAL ;
    PORT
      LAYER M5 ;
        RECT  59.28 86.316 59.304 86.4 ;
    END
  END zo[120]
  PIN zo[121]
    DIRECTION OUTPUT ;
    USE SIGNAL ;
    PORT
      LAYER M5 ;
        RECT  59.376 86.316 59.4 86.4 ;
    END
  END zo[121]
  PIN zo[122]
    DIRECTION OUTPUT ;
    USE SIGNAL ;
    PORT
      LAYER M5 ;
        RECT  59.472 86.316 59.496 86.4 ;
    END
  END zo[122]
  PIN zo[123]
    DIRECTION OUTPUT ;
    USE SIGNAL ;
    PORT
      LAYER M5 ;
        RECT  59.568 86.316 59.592 86.4 ;
    END
  END zo[123]
  PIN zo[124]
    DIRECTION OUTPUT ;
    USE SIGNAL ;
    PORT
      LAYER M5 ;
        RECT  59.664 86.316 59.688 86.4 ;
    END
  END zo[124]
  PIN zo[125]
    DIRECTION OUTPUT ;
    USE SIGNAL ;
    PORT
      LAYER M5 ;
        RECT  59.76 86.316 59.784 86.4 ;
    END
  END zo[125]
  PIN zo[126]
    DIRECTION OUTPUT ;
    USE SIGNAL ;
    PORT
      LAYER M5 ;
        RECT  59.856 86.316 59.88 86.4 ;
    END
  END zo[126]
  PIN zo[127]
    DIRECTION OUTPUT ;
    USE SIGNAL ;
    PORT
      LAYER M5 ;
        RECT  59.952 86.316 59.976 86.4 ;
    END
  END zo[127]
  PIN zo[128]
    DIRECTION OUTPUT ;
    USE SIGNAL ;
    PORT
      LAYER M5 ;
        RECT  46.8 86.316 46.824 86.4 ;
    END
  END zo[128]
  PIN zo[129]
    DIRECTION OUTPUT ;
    USE SIGNAL ;
    PORT
      LAYER M5 ;
        RECT  46.896 86.316 46.92 86.4 ;
    END
  END zo[129]
  PIN zo[12]
    DIRECTION OUTPUT ;
    USE SIGNAL ;
    PORT
      LAYER M5 ;
        RECT  48.912 86.316 48.936 86.4 ;
    END
  END zo[12]
  PIN zo[130]
    DIRECTION OUTPUT ;
    USE SIGNAL ;
    PORT
      LAYER M5 ;
        RECT  46.992 86.316 47.016 86.4 ;
    END
  END zo[130]
  PIN zo[131]
    DIRECTION OUTPUT ;
    USE SIGNAL ;
    PORT
      LAYER M5 ;
        RECT  47.088 86.316 47.112 86.4 ;
    END
  END zo[131]
  PIN zo[132]
    DIRECTION OUTPUT ;
    USE SIGNAL ;
    PORT
      LAYER M5 ;
        RECT  47.184 86.316 47.208 86.4 ;
    END
  END zo[132]
  PIN zo[133]
    DIRECTION OUTPUT ;
    USE SIGNAL ;
    PORT
      LAYER M5 ;
        RECT  47.28 86.316 47.304 86.4 ;
    END
  END zo[133]
  PIN zo[134]
    DIRECTION OUTPUT ;
    USE SIGNAL ;
    PORT
      LAYER M5 ;
        RECT  47.376 86.316 47.4 86.4 ;
    END
  END zo[134]
  PIN zo[135]
    DIRECTION OUTPUT ;
    USE SIGNAL ;
    PORT
      LAYER M5 ;
        RECT  47.472 86.316 47.496 86.4 ;
    END
  END zo[135]
  PIN zo[136]
    DIRECTION OUTPUT ;
    USE SIGNAL ;
    PORT
      LAYER M5 ;
        RECT  47.568 86.316 47.592 86.4 ;
    END
  END zo[136]
  PIN zo[137]
    DIRECTION OUTPUT ;
    USE SIGNAL ;
    PORT
      LAYER M5 ;
        RECT  47.664 86.316 47.688 86.4 ;
    END
  END zo[137]
  PIN zo[13]
    DIRECTION OUTPUT ;
    USE SIGNAL ;
    PORT
      LAYER M5 ;
        RECT  49.008 86.316 49.032 86.4 ;
    END
  END zo[13]
  PIN zo[14]
    DIRECTION OUTPUT ;
    USE SIGNAL ;
    PORT
      LAYER M5 ;
        RECT  49.104 86.316 49.128 86.4 ;
    END
  END zo[14]
  PIN zo[15]
    DIRECTION OUTPUT ;
    USE SIGNAL ;
    PORT
      LAYER M5 ;
        RECT  49.2 86.316 49.224 86.4 ;
    END
  END zo[15]
  PIN zo[16]
    DIRECTION OUTPUT ;
    USE SIGNAL ;
    PORT
      LAYER M5 ;
        RECT  49.296 86.316 49.32 86.4 ;
    END
  END zo[16]
  PIN zo[17]
    DIRECTION OUTPUT ;
    USE SIGNAL ;
    PORT
      LAYER M5 ;
        RECT  49.392 86.316 49.416 86.4 ;
    END
  END zo[17]
  PIN zo[18]
    DIRECTION OUTPUT ;
    USE SIGNAL ;
    PORT
      LAYER M5 ;
        RECT  49.488 86.316 49.512 86.4 ;
    END
  END zo[18]
  PIN zo[19]
    DIRECTION OUTPUT ;
    USE SIGNAL ;
    PORT
      LAYER M5 ;
        RECT  49.584 86.316 49.608 86.4 ;
    END
  END zo[19]
  PIN zo[1]
    DIRECTION OUTPUT ;
    USE SIGNAL ;
    PORT
      LAYER M5 ;
        RECT  47.856 86.316 47.88 86.4 ;
    END
  END zo[1]
  PIN zo[20]
    DIRECTION OUTPUT ;
    USE SIGNAL ;
    PORT
      LAYER M5 ;
        RECT  49.68 86.316 49.704 86.4 ;
    END
  END zo[20]
  PIN zo[21]
    DIRECTION OUTPUT ;
    USE SIGNAL ;
    PORT
      LAYER M5 ;
        RECT  49.776 86.316 49.8 86.4 ;
    END
  END zo[21]
  PIN zo[22]
    DIRECTION OUTPUT ;
    USE SIGNAL ;
    PORT
      LAYER M5 ;
        RECT  49.872 86.316 49.896 86.4 ;
    END
  END zo[22]
  PIN zo[23]
    DIRECTION OUTPUT ;
    USE SIGNAL ;
    PORT
      LAYER M5 ;
        RECT  49.968 86.316 49.992 86.4 ;
    END
  END zo[23]
  PIN zo[24]
    DIRECTION OUTPUT ;
    USE SIGNAL ;
    PORT
      LAYER M5 ;
        RECT  50.064 86.316 50.088 86.4 ;
    END
  END zo[24]
  PIN zo[25]
    DIRECTION OUTPUT ;
    USE SIGNAL ;
    PORT
      LAYER M5 ;
        RECT  50.16 86.316 50.184 86.4 ;
    END
  END zo[25]
  PIN zo[26]
    DIRECTION OUTPUT ;
    USE SIGNAL ;
    PORT
      LAYER M5 ;
        RECT  50.256 86.316 50.28 86.4 ;
    END
  END zo[26]
  PIN zo[27]
    DIRECTION OUTPUT ;
    USE SIGNAL ;
    PORT
      LAYER M5 ;
        RECT  50.352 86.316 50.376 86.4 ;
    END
  END zo[27]
  PIN zo[28]
    DIRECTION OUTPUT ;
    USE SIGNAL ;
    PORT
      LAYER M5 ;
        RECT  50.448 86.316 50.472 86.4 ;
    END
  END zo[28]
  PIN zo[29]
    DIRECTION OUTPUT ;
    USE SIGNAL ;
    PORT
      LAYER M5 ;
        RECT  50.544 86.316 50.568 86.4 ;
    END
  END zo[29]
  PIN zo[2]
    DIRECTION OUTPUT ;
    USE SIGNAL ;
    PORT
      LAYER M5 ;
        RECT  47.952 86.316 47.976 86.4 ;
    END
  END zo[2]
  PIN zo[30]
    DIRECTION OUTPUT ;
    USE SIGNAL ;
    PORT
      LAYER M5 ;
        RECT  50.64 86.316 50.664 86.4 ;
    END
  END zo[30]
  PIN zo[31]
    DIRECTION OUTPUT ;
    USE SIGNAL ;
    PORT
      LAYER M5 ;
        RECT  50.736 86.316 50.76 86.4 ;
    END
  END zo[31]
  PIN zo[32]
    DIRECTION OUTPUT ;
    USE SIGNAL ;
    PORT
      LAYER M5 ;
        RECT  50.832 86.316 50.856 86.4 ;
    END
  END zo[32]
  PIN zo[33]
    DIRECTION OUTPUT ;
    USE SIGNAL ;
    PORT
      LAYER M5 ;
        RECT  50.928 86.316 50.952 86.4 ;
    END
  END zo[33]
  PIN zo[34]
    DIRECTION OUTPUT ;
    USE SIGNAL ;
    PORT
      LAYER M5 ;
        RECT  51.024 86.316 51.048 86.4 ;
    END
  END zo[34]
  PIN zo[35]
    DIRECTION OUTPUT ;
    USE SIGNAL ;
    PORT
      LAYER M5 ;
        RECT  51.12 86.316 51.144 86.4 ;
    END
  END zo[35]
  PIN zo[36]
    DIRECTION OUTPUT ;
    USE SIGNAL ;
    PORT
      LAYER M5 ;
        RECT  51.216 86.316 51.24 86.4 ;
    END
  END zo[36]
  PIN zo[37]
    DIRECTION OUTPUT ;
    USE SIGNAL ;
    PORT
      LAYER M5 ;
        RECT  51.312 86.316 51.336 86.4 ;
    END
  END zo[37]
  PIN zo[38]
    DIRECTION OUTPUT ;
    USE SIGNAL ;
    PORT
      LAYER M5 ;
        RECT  51.408 86.316 51.432 86.4 ;
    END
  END zo[38]
  PIN zo[39]
    DIRECTION OUTPUT ;
    USE SIGNAL ;
    PORT
      LAYER M5 ;
        RECT  51.504 86.316 51.528 86.4 ;
    END
  END zo[39]
  PIN zo[3]
    DIRECTION OUTPUT ;
    USE SIGNAL ;
    PORT
      LAYER M5 ;
        RECT  48.048 86.316 48.072 86.4 ;
    END
  END zo[3]
  PIN zo[40]
    DIRECTION OUTPUT ;
    USE SIGNAL ;
    PORT
      LAYER M5 ;
        RECT  51.6 86.316 51.624 86.4 ;
    END
  END zo[40]
  PIN zo[41]
    DIRECTION OUTPUT ;
    USE SIGNAL ;
    PORT
      LAYER M5 ;
        RECT  51.696 86.316 51.72 86.4 ;
    END
  END zo[41]
  PIN zo[42]
    DIRECTION OUTPUT ;
    USE SIGNAL ;
    PORT
      LAYER M5 ;
        RECT  51.792 86.316 51.816 86.4 ;
    END
  END zo[42]
  PIN zo[43]
    DIRECTION OUTPUT ;
    USE SIGNAL ;
    PORT
      LAYER M5 ;
        RECT  51.888 86.316 51.912 86.4 ;
    END
  END zo[43]
  PIN zo[44]
    DIRECTION OUTPUT ;
    USE SIGNAL ;
    PORT
      LAYER M5 ;
        RECT  51.984 86.316 52.008 86.4 ;
    END
  END zo[44]
  PIN zo[45]
    DIRECTION OUTPUT ;
    USE SIGNAL ;
    PORT
      LAYER M5 ;
        RECT  52.08 86.316 52.104 86.4 ;
    END
  END zo[45]
  PIN zo[46]
    DIRECTION OUTPUT ;
    USE SIGNAL ;
    PORT
      LAYER M5 ;
        RECT  52.176 86.316 52.2 86.4 ;
    END
  END zo[46]
  PIN zo[47]
    DIRECTION OUTPUT ;
    USE SIGNAL ;
    PORT
      LAYER M5 ;
        RECT  52.272 86.316 52.296 86.4 ;
    END
  END zo[47]
  PIN zo[48]
    DIRECTION OUTPUT ;
    USE SIGNAL ;
    PORT
      LAYER M5 ;
        RECT  52.368 86.316 52.392 86.4 ;
    END
  END zo[48]
  PIN zo[49]
    DIRECTION OUTPUT ;
    USE SIGNAL ;
    PORT
      LAYER M5 ;
        RECT  52.464 86.316 52.488 86.4 ;
    END
  END zo[49]
  PIN zo[4]
    DIRECTION OUTPUT ;
    USE SIGNAL ;
    PORT
      LAYER M5 ;
        RECT  48.144 86.316 48.168 86.4 ;
    END
  END zo[4]
  PIN zo[50]
    DIRECTION OUTPUT ;
    USE SIGNAL ;
    PORT
      LAYER M5 ;
        RECT  52.56 86.316 52.584 86.4 ;
    END
  END zo[50]
  PIN zo[51]
    DIRECTION OUTPUT ;
    USE SIGNAL ;
    PORT
      LAYER M5 ;
        RECT  52.656 86.316 52.68 86.4 ;
    END
  END zo[51]
  PIN zo[52]
    DIRECTION OUTPUT ;
    USE SIGNAL ;
    PORT
      LAYER M5 ;
        RECT  52.752 86.316 52.776 86.4 ;
    END
  END zo[52]
  PIN zo[53]
    DIRECTION OUTPUT ;
    USE SIGNAL ;
    PORT
      LAYER M5 ;
        RECT  52.848 86.316 52.872 86.4 ;
    END
  END zo[53]
  PIN zo[54]
    DIRECTION OUTPUT ;
    USE SIGNAL ;
    PORT
      LAYER M5 ;
        RECT  52.944 86.316 52.968 86.4 ;
    END
  END zo[54]
  PIN zo[55]
    DIRECTION OUTPUT ;
    USE SIGNAL ;
    PORT
      LAYER M5 ;
        RECT  53.04 86.316 53.064 86.4 ;
    END
  END zo[55]
  PIN zo[56]
    DIRECTION OUTPUT ;
    USE SIGNAL ;
    PORT
      LAYER M5 ;
        RECT  53.136 86.316 53.16 86.4 ;
    END
  END zo[56]
  PIN zo[57]
    DIRECTION OUTPUT ;
    USE SIGNAL ;
    PORT
      LAYER M5 ;
        RECT  53.232 86.316 53.256 86.4 ;
    END
  END zo[57]
  PIN zo[58]
    DIRECTION OUTPUT ;
    USE SIGNAL ;
    PORT
      LAYER M5 ;
        RECT  53.328 86.316 53.352 86.4 ;
    END
  END zo[58]
  PIN zo[59]
    DIRECTION OUTPUT ;
    USE SIGNAL ;
    PORT
      LAYER M5 ;
        RECT  53.424 86.316 53.448 86.4 ;
    END
  END zo[59]
  PIN zo[5]
    DIRECTION OUTPUT ;
    USE SIGNAL ;
    PORT
      LAYER M5 ;
        RECT  48.24 86.316 48.264 86.4 ;
    END
  END zo[5]
  PIN zo[60]
    DIRECTION OUTPUT ;
    USE SIGNAL ;
    PORT
      LAYER M5 ;
        RECT  53.52 86.316 53.544 86.4 ;
    END
  END zo[60]
  PIN zo[61]
    DIRECTION OUTPUT ;
    USE SIGNAL ;
    PORT
      LAYER M5 ;
        RECT  53.616 86.316 53.64 86.4 ;
    END
  END zo[61]
  PIN zo[62]
    DIRECTION OUTPUT ;
    USE SIGNAL ;
    PORT
      LAYER M5 ;
        RECT  53.712 86.316 53.736 86.4 ;
    END
  END zo[62]
  PIN zo[63]
    DIRECTION OUTPUT ;
    USE SIGNAL ;
    PORT
      LAYER M5 ;
        RECT  53.808 86.316 53.832 86.4 ;
    END
  END zo[63]
  PIN zo[64]
    DIRECTION OUTPUT ;
    USE SIGNAL ;
    PORT
      LAYER M5 ;
        RECT  53.904 86.316 53.928 86.4 ;
    END
  END zo[64]
  PIN zo[65]
    DIRECTION OUTPUT ;
    USE SIGNAL ;
    PORT
      LAYER M5 ;
        RECT  54 86.316 54.024 86.4 ;
    END
  END zo[65]
  PIN zo[66]
    DIRECTION OUTPUT ;
    USE SIGNAL ;
    PORT
      LAYER M5 ;
        RECT  54.096 86.316 54.12 86.4 ;
    END
  END zo[66]
  PIN zo[67]
    DIRECTION OUTPUT ;
    USE SIGNAL ;
    PORT
      LAYER M5 ;
        RECT  54.192 86.316 54.216 86.4 ;
    END
  END zo[67]
  PIN zo[68]
    DIRECTION OUTPUT ;
    USE SIGNAL ;
    PORT
      LAYER M5 ;
        RECT  54.288 86.316 54.312 86.4 ;
    END
  END zo[68]
  PIN zo[69]
    DIRECTION OUTPUT ;
    USE SIGNAL ;
    PORT
      LAYER M5 ;
        RECT  54.384 86.316 54.408 86.4 ;
    END
  END zo[69]
  PIN zo[6]
    DIRECTION OUTPUT ;
    USE SIGNAL ;
    PORT
      LAYER M5 ;
        RECT  48.336 86.316 48.36 86.4 ;
    END
  END zo[6]
  PIN zo[70]
    DIRECTION OUTPUT ;
    USE SIGNAL ;
    PORT
      LAYER M5 ;
        RECT  54.48 86.316 54.504 86.4 ;
    END
  END zo[70]
  PIN zo[71]
    DIRECTION OUTPUT ;
    USE SIGNAL ;
    PORT
      LAYER M5 ;
        RECT  54.576 86.316 54.6 86.4 ;
    END
  END zo[71]
  PIN zo[72]
    DIRECTION OUTPUT ;
    USE SIGNAL ;
    PORT
      LAYER M5 ;
        RECT  54.672 86.316 54.696 86.4 ;
    END
  END zo[72]
  PIN zo[73]
    DIRECTION OUTPUT ;
    USE SIGNAL ;
    PORT
      LAYER M5 ;
        RECT  54.768 86.316 54.792 86.4 ;
    END
  END zo[73]
  PIN zo[74]
    DIRECTION OUTPUT ;
    USE SIGNAL ;
    PORT
      LAYER M5 ;
        RECT  54.864 86.316 54.888 86.4 ;
    END
  END zo[74]
  PIN zo[75]
    DIRECTION OUTPUT ;
    USE SIGNAL ;
    PORT
      LAYER M5 ;
        RECT  54.96 86.316 54.984 86.4 ;
    END
  END zo[75]
  PIN zo[76]
    DIRECTION OUTPUT ;
    USE SIGNAL ;
    PORT
      LAYER M5 ;
        RECT  55.056 86.316 55.08 86.4 ;
    END
  END zo[76]
  PIN zo[77]
    DIRECTION OUTPUT ;
    USE SIGNAL ;
    PORT
      LAYER M5 ;
        RECT  55.152 86.316 55.176 86.4 ;
    END
  END zo[77]
  PIN zo[78]
    DIRECTION OUTPUT ;
    USE SIGNAL ;
    PORT
      LAYER M5 ;
        RECT  55.248 86.316 55.272 86.4 ;
    END
  END zo[78]
  PIN zo[79]
    DIRECTION OUTPUT ;
    USE SIGNAL ;
    PORT
      LAYER M5 ;
        RECT  55.344 86.316 55.368 86.4 ;
    END
  END zo[79]
  PIN zo[7]
    DIRECTION OUTPUT ;
    USE SIGNAL ;
    PORT
      LAYER M5 ;
        RECT  48.432 86.316 48.456 86.4 ;
    END
  END zo[7]
  PIN zo[80]
    DIRECTION OUTPUT ;
    USE SIGNAL ;
    PORT
      LAYER M5 ;
        RECT  55.44 86.316 55.464 86.4 ;
    END
  END zo[80]
  PIN zo[81]
    DIRECTION OUTPUT ;
    USE SIGNAL ;
    PORT
      LAYER M5 ;
        RECT  55.536 86.316 55.56 86.4 ;
    END
  END zo[81]
  PIN zo[82]
    DIRECTION OUTPUT ;
    USE SIGNAL ;
    PORT
      LAYER M5 ;
        RECT  55.632 86.316 55.656 86.4 ;
    END
  END zo[82]
  PIN zo[83]
    DIRECTION OUTPUT ;
    USE SIGNAL ;
    PORT
      LAYER M5 ;
        RECT  55.728 86.316 55.752 86.4 ;
    END
  END zo[83]
  PIN zo[84]
    DIRECTION OUTPUT ;
    USE SIGNAL ;
    PORT
      LAYER M5 ;
        RECT  55.824 86.316 55.848 86.4 ;
    END
  END zo[84]
  PIN zo[85]
    DIRECTION OUTPUT ;
    USE SIGNAL ;
    PORT
      LAYER M5 ;
        RECT  55.92 86.316 55.944 86.4 ;
    END
  END zo[85]
  PIN zo[86]
    DIRECTION OUTPUT ;
    USE SIGNAL ;
    PORT
      LAYER M5 ;
        RECT  56.016 86.316 56.04 86.4 ;
    END
  END zo[86]
  PIN zo[87]
    DIRECTION OUTPUT ;
    USE SIGNAL ;
    PORT
      LAYER M5 ;
        RECT  56.112 86.316 56.136 86.4 ;
    END
  END zo[87]
  PIN zo[88]
    DIRECTION OUTPUT ;
    USE SIGNAL ;
    PORT
      LAYER M5 ;
        RECT  56.208 86.316 56.232 86.4 ;
    END
  END zo[88]
  PIN zo[89]
    DIRECTION OUTPUT ;
    USE SIGNAL ;
    PORT
      LAYER M5 ;
        RECT  56.304 86.316 56.328 86.4 ;
    END
  END zo[89]
  PIN zo[8]
    DIRECTION OUTPUT ;
    USE SIGNAL ;
    PORT
      LAYER M5 ;
        RECT  48.528 86.316 48.552 86.4 ;
    END
  END zo[8]
  PIN zo[90]
    DIRECTION OUTPUT ;
    USE SIGNAL ;
    PORT
      LAYER M5 ;
        RECT  56.4 86.316 56.424 86.4 ;
    END
  END zo[90]
  PIN zo[91]
    DIRECTION OUTPUT ;
    USE SIGNAL ;
    PORT
      LAYER M5 ;
        RECT  56.496 86.316 56.52 86.4 ;
    END
  END zo[91]
  PIN zo[92]
    DIRECTION OUTPUT ;
    USE SIGNAL ;
    PORT
      LAYER M5 ;
        RECT  56.592 86.316 56.616 86.4 ;
    END
  END zo[92]
  PIN zo[93]
    DIRECTION OUTPUT ;
    USE SIGNAL ;
    PORT
      LAYER M5 ;
        RECT  56.688 86.316 56.712 86.4 ;
    END
  END zo[93]
  PIN zo[94]
    DIRECTION OUTPUT ;
    USE SIGNAL ;
    PORT
      LAYER M5 ;
        RECT  56.784 86.316 56.808 86.4 ;
    END
  END zo[94]
  PIN zo[95]
    DIRECTION OUTPUT ;
    USE SIGNAL ;
    PORT
      LAYER M5 ;
        RECT  56.88 86.316 56.904 86.4 ;
    END
  END zo[95]
  PIN zo[96]
    DIRECTION OUTPUT ;
    USE SIGNAL ;
    PORT
      LAYER M5 ;
        RECT  56.976 86.316 57 86.4 ;
    END
  END zo[96]
  PIN zo[97]
    DIRECTION OUTPUT ;
    USE SIGNAL ;
    PORT
      LAYER M5 ;
        RECT  57.072 86.316 57.096 86.4 ;
    END
  END zo[97]
  PIN zo[98]
    DIRECTION OUTPUT ;
    USE SIGNAL ;
    PORT
      LAYER M5 ;
        RECT  57.168 86.316 57.192 86.4 ;
    END
  END zo[98]
  PIN zo[99]
    DIRECTION OUTPUT ;
    USE SIGNAL ;
    PORT
      LAYER M5 ;
        RECT  57.264 86.316 57.288 86.4 ;
    END
  END zo[99]
  PIN zo[9]
    DIRECTION OUTPUT ;
    USE SIGNAL ;
    PORT
      LAYER M5 ;
        RECT  48.624 86.316 48.648 86.4 ;
    END
  END zo[9]
  PIN VDD
    DIRECTION INOUT ;
    USE POWER ;
    PORT
      LAYER M5 ;
        RECT  83.592 2.151 83.712 84.249 ;
        RECT  78.192 2.151 78.312 84.249 ;
        RECT  72.792 2.151 72.912 84.249 ;
        RECT  67.392 2.151 67.512 84.249 ;
        RECT  61.992 2.151 62.112 84.249 ;
        RECT  56.592 2.151 56.712 84.249 ;
        RECT  51.192 2.151 51.312 84.249 ;
        RECT  45.792 2.151 45.912 84.249 ;
        RECT  40.392 2.151 40.512 84.249 ;
        RECT  34.992 2.151 35.112 84.249 ;
        RECT  29.592 2.151 29.712 84.249 ;
        RECT  24.192 2.151 24.312 84.249 ;
        RECT  18.792 2.151 18.912 84.249 ;
        RECT  13.392 2.151 13.512 84.249 ;
        RECT  7.992 2.151 8.112 84.249 ;
        RECT  2.592 2.151 2.712 84.249 ;
    END
  END VDD
  PIN VSS
    DIRECTION INOUT ;
    USE GROUND ;
    PORT
      LAYER M5 ;
        RECT  83.4 2.137 83.52 84.263 ;
        RECT  78 2.137 78.12 84.263 ;
        RECT  72.6 2.137 72.72 84.263 ;
        RECT  67.2 2.137 67.32 84.263 ;
        RECT  61.8 2.137 61.92 84.263 ;
        RECT  56.4 2.137 56.52 84.263 ;
        RECT  51 2.137 51.12 84.263 ;
        RECT  45.6 2.137 45.72 84.263 ;
        RECT  40.2 2.137 40.32 84.263 ;
        RECT  34.8 2.137 34.92 84.263 ;
        RECT  29.4 2.137 29.52 84.263 ;
        RECT  24 2.137 24.12 84.263 ;
        RECT  18.6 2.137 18.72 84.263 ;
        RECT  13.2 2.137 13.32 84.263 ;
        RECT  7.8 2.137 7.92 84.263 ;
        RECT  2.4 2.137 2.52 84.263 ;
    END
  END VSS
  # OT_OBS_CLOSED layer=M5 d_um=1.536 added=495
  OBS
    LAYER RVTN ;
     RECT  2.16 2.16 84.24 2.295 ;
     RECT  2.16 2.565 84.24 2.835 ;
     RECT  2.16 3.105 84.24 3.375 ;
     RECT  2.16 3.645 84.24 3.915 ;
     RECT  2.16 4.185 84.24 4.455 ;
     RECT  2.16 4.725 84.24 4.995 ;
     RECT  2.16 5.265 84.24 5.535 ;
     RECT  2.16 5.805 84.24 6.075 ;
     RECT  2.16 6.345 84.24 6.615 ;
     RECT  2.16 6.885 84.24 7.155 ;
     RECT  2.16 7.425 84.24 7.695 ;
     RECT  2.16 7.965 84.24 8.235 ;
     RECT  2.16 8.505 84.24 8.775 ;
     RECT  2.16 9.045 84.24 9.315 ;
     RECT  2.16 9.585 84.24 9.855 ;
     RECT  2.16 10.125 84.24 10.395 ;
     RECT  2.16 10.665 84.24 10.935 ;
     RECT  2.16 11.205 84.24 11.475 ;
     RECT  2.16 11.745 84.24 12.015 ;
     RECT  2.16 12.285 84.24 12.555 ;
     RECT  2.16 12.825 84.24 13.095 ;
     RECT  2.16 13.365 84.24 13.635 ;
     RECT  2.16 13.905 84.24 14.175 ;
     RECT  2.16 14.445 84.24 14.715 ;
     RECT  2.16 14.985 84.24 15.255 ;
     RECT  2.16 15.525 84.24 15.795 ;
     RECT  2.16 16.065 84.24 16.335 ;
     RECT  2.16 16.605 84.24 16.875 ;
     RECT  2.16 17.145 84.24 17.415 ;
     RECT  2.16 17.685 84.24 17.955 ;
     RECT  2.16 18.225 84.24 18.495 ;
     RECT  2.16 18.765 84.24 19.035 ;
     RECT  2.16 19.305 84.24 19.575 ;
     RECT  2.16 19.845 84.24 20.115 ;
     RECT  2.16 20.385 84.24 20.655 ;
     RECT  2.16 20.925 84.24 21.195 ;
     RECT  2.16 21.465 84.24 21.735 ;
     RECT  2.16 22.005 84.24 22.275 ;
     RECT  2.16 22.545 84.24 22.815 ;
     RECT  2.16 23.085 84.24 23.355 ;
     RECT  2.16 23.625 84.24 23.895 ;
     RECT  2.16 24.165 84.24 24.435 ;
     RECT  2.16 24.705 84.24 24.975 ;
     RECT  2.16 25.245 84.24 25.515 ;
     RECT  2.16 25.785 84.24 26.055 ;
     RECT  2.16 26.325 84.24 26.595 ;
     RECT  2.16 26.865 84.24 27.135 ;
     RECT  2.16 27.405 84.24 27.675 ;
     RECT  2.16 27.945 84.24 28.215 ;
     RECT  2.16 28.485 84.24 28.755 ;
     RECT  2.16 29.025 84.24 29.295 ;
     RECT  2.16 29.565 84.24 29.835 ;
     RECT  2.16 30.105 84.24 30.375 ;
     RECT  2.16 30.645 84.24 30.915 ;
     RECT  2.16 31.185 84.24 31.455 ;
     RECT  2.16 31.725 84.24 31.995 ;
     RECT  2.16 32.265 84.24 32.535 ;
     RECT  2.16 32.805 84.24 33.075 ;
     RECT  2.16 33.345 84.24 33.615 ;
     RECT  2.16 33.885 84.24 34.155 ;
     RECT  2.16 34.425 84.24 34.695 ;
     RECT  2.16 34.965 84.24 35.235 ;
     RECT  2.16 35.505 84.24 35.775 ;
     RECT  2.16 36.045 84.24 36.315 ;
     RECT  2.16 36.585 84.24 36.855 ;
     RECT  2.16 37.125 84.24 37.395 ;
     RECT  2.16 37.665 84.24 37.935 ;
     RECT  2.16 38.205 84.24 38.475 ;
     RECT  2.16 38.745 84.24 39.015 ;
     RECT  2.16 39.285 84.24 39.555 ;
     RECT  2.16 39.825 84.24 40.095 ;
     RECT  2.16 40.365 84.24 40.635 ;
     RECT  2.16 40.905 84.24 41.175 ;
     RECT  2.16 41.445 84.24 41.715 ;
     RECT  2.16 41.985 84.24 42.255 ;
     RECT  2.16 42.525 84.24 42.795 ;
     RECT  2.16 43.065 84.24 43.335 ;
     RECT  2.16 43.605 84.24 43.875 ;
     RECT  2.16 44.145 84.24 44.415 ;
     RECT  2.16 44.685 84.24 44.955 ;
     RECT  2.16 45.225 84.24 45.495 ;
     RECT  2.16 45.765 84.24 46.035 ;
     RECT  2.16 46.305 84.24 46.575 ;
     RECT  2.16 46.845 84.24 47.115 ;
     RECT  2.16 47.385 84.24 47.655 ;
     RECT  2.16 47.925 84.24 48.195 ;
     RECT  2.16 48.465 84.24 48.735 ;
     RECT  2.16 49.005 84.24 49.275 ;
     RECT  2.16 49.545 84.24 49.815 ;
     RECT  2.16 50.085 84.24 50.355 ;
     RECT  2.16 50.625 84.24 50.895 ;
     RECT  2.16 51.165 84.24 51.435 ;
     RECT  2.16 51.705 84.24 51.975 ;
     RECT  2.16 52.245 84.24 52.515 ;
     RECT  2.16 52.785 84.24 53.055 ;
     RECT  2.16 53.325 84.24 53.595 ;
     RECT  2.16 53.865 84.24 54.135 ;
     RECT  2.16 54.405 84.24 54.675 ;
     RECT  2.16 54.945 84.24 55.215 ;
     RECT  2.16 55.485 84.24 55.755 ;
     RECT  2.16 56.025 84.24 56.295 ;
     RECT  2.16 56.565 84.24 56.835 ;
     RECT  2.16 57.105 84.24 57.375 ;
     RECT  2.16 57.645 84.24 57.915 ;
     RECT  2.16 58.185 84.24 58.455 ;
     RECT  2.16 58.725 84.24 58.995 ;
     RECT  2.16 59.265 84.24 59.535 ;
     RECT  2.16 59.805 84.24 60.075 ;
     RECT  2.16 60.345 84.24 60.615 ;
     RECT  2.16 60.885 84.24 61.155 ;
     RECT  2.16 61.425 84.24 61.695 ;
     RECT  2.16 61.965 84.24 62.235 ;
     RECT  2.16 62.505 84.24 62.775 ;
     RECT  2.16 63.045 84.24 63.315 ;
     RECT  2.16 63.585 84.24 63.855 ;
     RECT  2.16 64.125 84.24 64.395 ;
     RECT  2.16 64.665 84.24 64.935 ;
     RECT  2.16 65.205 84.24 65.475 ;
     RECT  2.16 65.745 84.24 66.015 ;
     RECT  2.16 66.285 84.24 66.555 ;
     RECT  2.16 66.825 84.24 67.095 ;
     RECT  2.16 67.365 84.24 67.635 ;
     RECT  2.16 67.905 84.24 68.175 ;
     RECT  2.16 68.445 84.24 68.715 ;
     RECT  2.16 68.985 84.24 69.255 ;
     RECT  2.16 69.525 84.24 69.795 ;
     RECT  2.16 70.065 84.24 70.335 ;
     RECT  2.16 70.605 84.24 70.875 ;
     RECT  2.16 71.145 84.24 71.415 ;
     RECT  2.16 71.685 84.24 71.955 ;
     RECT  2.16 72.225 84.24 72.495 ;
     RECT  2.16 72.765 84.24 73.035 ;
     RECT  2.16 73.305 84.24 73.575 ;
     RECT  2.16 73.845 84.24 74.115 ;
     RECT  2.16 74.385 84.24 74.655 ;
     RECT  2.16 74.925 84.24 75.195 ;
     RECT  2.16 75.465 84.24 75.735 ;
     RECT  2.16 76.005 84.24 76.275 ;
     RECT  2.16 76.545 84.24 76.815 ;
     RECT  2.16 77.085 84.24 77.355 ;
     RECT  2.16 77.625 84.24 77.895 ;
     RECT  2.16 78.165 84.24 78.435 ;
     RECT  2.16 78.705 84.24 78.975 ;
     RECT  2.16 79.245 84.24 79.515 ;
     RECT  2.16 79.785 84.24 80.055 ;
     RECT  2.16 80.325 84.24 80.595 ;
     RECT  2.16 80.865 84.24 81.135 ;
     RECT  2.16 81.405 84.24 81.675 ;
     RECT  2.16 81.945 84.24 82.215 ;
     RECT  2.16 82.485 84.24 82.755 ;
     RECT  2.16 83.025 84.24 83.295 ;
     RECT  2.16 83.565 84.24 83.835 ;
     RECT  2.16 84.105 84.24 84.24 ;
    LAYER RVTP ;
     RECT  2.16 2.295 84.24 2.565 ;
     RECT  2.16 2.835 84.24 3.105 ;
     RECT  2.16 3.375 84.24 3.645 ;
     RECT  2.16 3.915 84.24 4.185 ;
     RECT  2.16 4.455 84.24 4.725 ;
     RECT  2.16 4.995 84.24 5.265 ;
     RECT  2.16 5.535 84.24 5.805 ;
     RECT  2.16 6.075 84.24 6.345 ;
     RECT  2.16 6.615 84.24 6.885 ;
     RECT  2.16 7.155 84.24 7.425 ;
     RECT  2.16 7.695 84.24 7.965 ;
     RECT  2.16 8.235 84.24 8.505 ;
     RECT  2.16 8.775 84.24 9.045 ;
     RECT  2.16 9.315 84.24 9.585 ;
     RECT  2.16 9.855 84.24 10.125 ;
     RECT  2.16 10.395 84.24 10.665 ;
     RECT  2.16 10.935 84.24 11.205 ;
     RECT  2.16 11.475 84.24 11.745 ;
     RECT  2.16 12.015 84.24 12.285 ;
     RECT  2.16 12.555 84.24 12.825 ;
     RECT  2.16 13.095 84.24 13.365 ;
     RECT  2.16 13.635 84.24 13.905 ;
     RECT  2.16 14.175 84.24 14.445 ;
     RECT  2.16 14.715 84.24 14.985 ;
     RECT  2.16 15.255 84.24 15.525 ;
     RECT  2.16 15.795 84.24 16.065 ;
     RECT  2.16 16.335 84.24 16.605 ;
     RECT  2.16 16.875 84.24 17.145 ;
     RECT  2.16 17.415 84.24 17.685 ;
     RECT  2.16 17.955 84.24 18.225 ;
     RECT  2.16 18.495 84.24 18.765 ;
     RECT  2.16 19.035 84.24 19.305 ;
     RECT  2.16 19.575 84.24 19.845 ;
     RECT  2.16 20.115 84.24 20.385 ;
     RECT  2.16 20.655 84.24 20.925 ;
     RECT  2.16 21.195 84.24 21.465 ;
     RECT  2.16 21.735 84.24 22.005 ;
     RECT  2.16 22.275 84.24 22.545 ;
     RECT  2.16 22.815 84.24 23.085 ;
     RECT  2.16 23.355 84.24 23.625 ;
     RECT  2.16 23.895 84.24 24.165 ;
     RECT  2.16 24.435 84.24 24.705 ;
     RECT  2.16 24.975 84.24 25.245 ;
     RECT  2.16 25.515 84.24 25.785 ;
     RECT  2.16 26.055 84.24 26.325 ;
     RECT  2.16 26.595 84.24 26.865 ;
     RECT  2.16 27.135 84.24 27.405 ;
     RECT  2.16 27.675 84.24 27.945 ;
     RECT  2.16 28.215 84.24 28.485 ;
     RECT  2.16 28.755 84.24 29.025 ;
     RECT  2.16 29.295 84.24 29.565 ;
     RECT  2.16 29.835 84.24 30.105 ;
     RECT  2.16 30.375 84.24 30.645 ;
     RECT  2.16 30.915 84.24 31.185 ;
     RECT  2.16 31.455 84.24 31.725 ;
     RECT  2.16 31.995 84.24 32.265 ;
     RECT  2.16 32.535 84.24 32.805 ;
     RECT  2.16 33.075 84.24 33.345 ;
     RECT  2.16 33.615 84.24 33.885 ;
     RECT  2.16 34.155 84.24 34.425 ;
     RECT  2.16 34.695 84.24 34.965 ;
     RECT  2.16 35.235 84.24 35.505 ;
     RECT  2.16 35.775 84.24 36.045 ;
     RECT  2.16 36.315 84.24 36.585 ;
     RECT  2.16 36.855 84.24 37.125 ;
     RECT  2.16 37.395 84.24 37.665 ;
     RECT  2.16 37.935 84.24 38.205 ;
     RECT  2.16 38.475 84.24 38.745 ;
     RECT  2.16 39.015 84.24 39.285 ;
     RECT  2.16 39.555 84.24 39.825 ;
     RECT  2.16 40.095 84.24 40.365 ;
     RECT  2.16 40.635 84.24 40.905 ;
     RECT  2.16 41.175 84.24 41.445 ;
     RECT  2.16 41.715 84.24 41.985 ;
     RECT  2.16 42.255 84.24 42.525 ;
     RECT  2.16 42.795 84.24 43.065 ;
     RECT  2.16 43.335 84.24 43.605 ;
     RECT  2.16 43.875 84.24 44.145 ;
     RECT  2.16 44.415 84.24 44.685 ;
     RECT  2.16 44.955 84.24 45.225 ;
     RECT  2.16 45.495 84.24 45.765 ;
     RECT  2.16 46.035 84.24 46.305 ;
     RECT  2.16 46.575 84.24 46.845 ;
     RECT  2.16 47.115 84.24 47.385 ;
     RECT  2.16 47.655 84.24 47.925 ;
     RECT  2.16 48.195 84.24 48.465 ;
     RECT  2.16 48.735 84.24 49.005 ;
     RECT  2.16 49.275 84.24 49.545 ;
     RECT  2.16 49.815 84.24 50.085 ;
     RECT  2.16 50.355 84.24 50.625 ;
     RECT  2.16 50.895 84.24 51.165 ;
     RECT  2.16 51.435 84.24 51.705 ;
     RECT  2.16 51.975 84.24 52.245 ;
     RECT  2.16 52.515 84.24 52.785 ;
     RECT  2.16 53.055 84.24 53.325 ;
     RECT  2.16 53.595 84.24 53.865 ;
     RECT  2.16 54.135 84.24 54.405 ;
     RECT  2.16 54.675 84.24 54.945 ;
     RECT  2.16 55.215 84.24 55.485 ;
     RECT  2.16 55.755 84.24 56.025 ;
     RECT  2.16 56.295 84.24 56.565 ;
     RECT  2.16 56.835 84.24 57.105 ;
     RECT  2.16 57.375 84.24 57.645 ;
     RECT  2.16 57.915 84.24 58.185 ;
     RECT  2.16 58.455 84.24 58.725 ;
     RECT  2.16 58.995 84.24 59.265 ;
     RECT  2.16 59.535 84.24 59.805 ;
     RECT  2.16 60.075 84.24 60.345 ;
     RECT  2.16 60.615 84.24 60.885 ;
     RECT  2.16 61.155 84.24 61.425 ;
     RECT  2.16 61.695 84.24 61.965 ;
     RECT  2.16 62.235 84.24 62.505 ;
     RECT  2.16 62.775 84.24 63.045 ;
     RECT  2.16 63.315 84.24 63.585 ;
     RECT  2.16 63.855 84.24 64.125 ;
     RECT  2.16 64.395 84.24 64.665 ;
     RECT  2.16 64.935 84.24 65.205 ;
     RECT  2.16 65.475 84.24 65.745 ;
     RECT  2.16 66.015 84.24 66.285 ;
     RECT  2.16 66.555 84.24 66.825 ;
     RECT  2.16 67.095 84.24 67.365 ;
     RECT  2.16 67.635 84.24 67.905 ;
     RECT  2.16 68.175 84.24 68.445 ;
     RECT  2.16 68.715 84.24 68.985 ;
     RECT  2.16 69.255 84.24 69.525 ;
     RECT  2.16 69.795 84.24 70.065 ;
     RECT  2.16 70.335 84.24 70.605 ;
     RECT  2.16 70.875 84.24 71.145 ;
     RECT  2.16 71.415 84.24 71.685 ;
     RECT  2.16 71.955 84.24 72.225 ;
     RECT  2.16 72.495 84.24 72.765 ;
     RECT  2.16 73.035 84.24 73.305 ;
     RECT  2.16 73.575 84.24 73.845 ;
     RECT  2.16 74.115 84.24 74.385 ;
     RECT  2.16 74.655 84.24 74.925 ;
     RECT  2.16 75.195 84.24 75.465 ;
     RECT  2.16 75.735 84.24 76.005 ;
     RECT  2.16 76.275 84.24 76.545 ;
     RECT  2.16 76.815 84.24 77.085 ;
     RECT  2.16 77.355 84.24 77.625 ;
     RECT  2.16 77.895 84.24 78.165 ;
     RECT  2.16 78.435 84.24 78.705 ;
     RECT  2.16 78.975 84.24 79.245 ;
     RECT  2.16 79.515 84.24 79.785 ;
     RECT  2.16 80.055 84.24 80.325 ;
     RECT  2.16 80.595 84.24 80.865 ;
     RECT  2.16 81.135 84.24 81.405 ;
     RECT  2.16 81.675 84.24 81.945 ;
     RECT  2.16 82.215 84.24 82.485 ;
     RECT  2.16 82.755 84.24 83.025 ;
     RECT  2.16 83.295 84.24 83.565 ;
     RECT  2.16 83.835 84.24 84.105 ;
    LAYER M1 ;
     RECT  2.16 2.151 84.24 84.249 ;
    LAYER M2 ;
     RECT  19.687 1.152 20.039 1.17 ;
     RECT  2.16 2.151 22.711 84.249 ;
     RECT  22.711 2.106 23.387 84.249 ;
     RECT  23.935 1.152 24.179 1.17 ;
     RECT  25.699 1.152 25.835 1.17 ;
     RECT  23.387 2.151 31.135 84.249 ;
     RECT  31.135 2.034 32.495 84.249 ;
     RECT  32.495 2.106 32.567 84.249 ;
     RECT  32.567 2.151 44.923 84.249 ;
     RECT  44.923 2.151 45.859 84.366 ;
     RECT  45.859 2.106 46.219 84.366 ;
     RECT  46.219 2.106 46.319 84.906 ;
     RECT  46.319 2.106 47.335 84.366 ;
     RECT  47.335 2.106 47.399 84.906 ;
     RECT  47.399 2.151 47.507 84.906 ;
     RECT  49.171 1.224 49.207 1.242 ;
     RECT  49.207 1.152 49.307 1.242 ;
     RECT  47.507 2.151 50.719 84.249 ;
     RECT  50.719 2.151 50.827 84.294 ;
     RECT  50.827 2.151 51.755 84.906 ;
     RECT  51.755 2.151 53.131 84.249 ;
     RECT  53.131 2.151 53.519 84.906 ;
     RECT  53.519 2.151 55.939 84.249 ;
     RECT  55.939 2.151 56.039 84.906 ;
     RECT  56.039 2.151 60.079 84.249 ;
     RECT  60.079 2.106 61.223 84.249 ;
     RECT  61.223 2.151 63.931 84.249 ;
     RECT  63.931 2.106 64.283 84.249 ;
     RECT  64.283 2.151 68.143 84.249 ;
     RECT  68.143 2.106 68.855 84.249 ;
     RECT  68.855 2.151 84.24 84.249 ;
    LAYER M3 ;
     RECT  32.58 0.091 33.03 0.139 ;
     RECT  49.176 0.091 49.194 0.139 ;
     RECT  66.672 0.091 66.69 0.139 ;
     RECT  67.5 0.091 67.95 0.139 ;
     RECT  20.808 0.091 22.842 0.187 ;
     RECT  49.068 0.139 49.194 0.187 ;
     RECT  66.672 0.139 67.95 0.221 ;
     RECT  19.476 0.091 19.89 0.427 ;
     RECT  24.66 0.091 25.182 0.475 ;
     RECT  44.784 0.427 44.802 0.475 ;
     RECT  24.66 0.475 25.83 0.523 ;
     RECT  44.784 0.475 45.522 0.523 ;
     RECT  46.656 0.139 46.674 0.523 ;
     RECT  47.448 0.091 48.186 0.523 ;
     RECT  19.476 0.427 20.07 0.571 ;
     RECT  20.808 0.187 22.878 0.571 ;
     RECT  23.94 0.523 25.83 0.571 ;
     RECT  32.58 0.139 33.642 0.571 ;
     RECT  44.784 0.523 45.594 0.571 ;
     RECT  46.656 0.523 48.186 0.571 ;
     RECT  49.068 0.187 49.302 0.571 ;
     RECT  32.544 0.571 33.714 0.619 ;
     RECT  66.672 0.221 67.122 1.099 ;
     RECT  67.932 0.221 67.95 1.099 ;
     RECT  32.472 0.619 33.714 1.723 ;
     RECT  34.776 0.571 34.794 1.723 ;
     RECT  44.784 0.571 49.302 1.723 ;
     RECT  63.864 0.571 63.882 1.723 ;
     RECT  66.672 1.099 67.95 1.723 ;
     RECT  19.476 0.571 25.83 1.771 ;
     RECT  66.672 1.723 68.382 1.771 ;
     RECT  19.476 1.771 26.226 1.819 ;
     RECT  27.252 1.723 27.27 1.819 ;
     RECT  31.14 2.029 31.158 2.101 ;
     RECT  61.704 1.723 61.722 2.101 ;
     RECT  66.672 1.771 68.454 2.101 ;
     RECT  61.2 2.101 61.722 2.143 ;
     RECT  18.615 2.143 18.705 2.191 ;
     RECT  19.476 1.819 27.27 2.191 ;
     RECT  31.14 2.101 31.518 2.191 ;
     RECT  32.472 1.723 35.838 2.191 ;
     RECT  44.784 1.723 49.518 2.191 ;
     RECT  61.2 2.143 61.905 2.191 ;
     RECT  13.215 2.143 13.305 2.227 ;
     RECT  19.44 2.191 27.27 2.227 ;
     RECT  60.084 2.101 60.102 2.227 ;
     RECT  61.2 2.191 62.298 2.227 ;
     RECT  13.215 2.227 13.374 2.251 ;
     RECT  44.748 2.191 50.058 2.251 ;
     RECT  51.015 2.143 51.105 2.251 ;
     RECT  66.672 2.101 68.85 2.251 ;
     RECT  16.056 2.227 16.074 2.263 ;
     RECT  18.18 2.191 18.705 2.263 ;
     RECT  19.44 2.227 27.702 2.263 ;
     RECT  28.44 2.191 28.458 2.263 ;
     RECT  63.864 1.723 64.386 2.263 ;
     RECT  16.056 2.263 16.398 2.299 ;
     RECT  44.748 2.251 51.105 2.299 ;
     RECT  60.084 2.227 62.298 2.299 ;
     RECT  53.064 2.263 53.082 2.335 ;
     RECT  54.468 2.191 54.486 2.335 ;
     RECT  60.084 2.299 62.766 2.335 ;
     RECT  12.708 2.251 13.374 2.371 ;
     RECT  15.264 2.335 15.282 2.371 ;
     RECT  18.18 2.263 28.458 2.371 ;
     RECT  31.14 2.191 35.838 2.371 ;
     RECT  38.7 2.263 38.718 2.371 ;
     RECT  42.156 2.335 42.174 2.371 ;
     RECT  44.748 2.299 51.498 2.371 ;
     RECT  63.864 2.263 64.782 2.371 ;
     RECT  66.384 2.251 68.85 2.371 ;
     RECT  74.34 0.571 74.358 2.371 ;
     RECT  2.415 2.143 2.505 2.413 ;
     RECT  7.815 2.143 7.905 2.413 ;
     RECT  29.415 2.143 29.505 2.413 ;
     RECT  40.215 2.143 40.305 2.413 ;
     RECT  56.415 2.143 56.505 2.413 ;
     RECT  72.615 2.143 72.705 2.413 ;
     RECT  78.015 2.143 78.105 2.413 ;
     RECT  83.415 2.143 83.505 2.413 ;
     RECT  41.364 2.371 41.382 2.461 ;
     RECT  42.156 2.371 43.254 2.461 ;
     RECT  44.748 2.371 52.002 2.461 ;
     RECT  74.268 2.371 74.358 2.489 ;
     RECT  53.064 2.335 53.226 2.497 ;
     RECT  54.432 2.335 54.486 2.497 ;
     RECT  56.415 2.413 56.697 2.497 ;
     RECT  60.084 2.335 62.838 2.497 ;
     RECT  63.864 2.371 65.394 2.497 ;
     RECT  16.056 2.299 16.47 2.533 ;
     RECT  17.82 2.371 28.458 2.533 ;
     RECT  29.415 2.413 29.697 2.569 ;
     RECT  38.592 2.371 38.97 2.569 ;
     RECT  53.064 2.497 54.486 2.569 ;
     RECT  10.116 2.371 10.134 2.605 ;
     RECT  12.708 2.371 15.282 2.605 ;
     RECT  17.64 2.533 28.458 2.605 ;
     RECT  29.415 2.569 29.898 2.605 ;
     RECT  31.14 2.371 36.486 2.605 ;
     RECT  38.592 2.569 39.006 2.605 ;
     RECT  44.64 2.461 52.002 2.605 ;
     RECT  53.064 2.569 54.594 2.605 ;
     RECT  55.656 2.497 56.697 2.605 ;
     RECT  9.54 2.605 10.134 2.641 ;
     RECT  12.06 2.605 15.282 2.641 ;
     RECT  16.02 2.533 16.47 2.641 ;
     RECT  17.64 2.605 29.898 2.641 ;
     RECT  30.924 2.605 36.486 2.641 ;
     RECT  38.052 2.605 39.006 2.641 ;
     RECT  40.215 2.413 40.497 2.641 ;
     RECT  41.364 2.461 43.254 2.641 ;
     RECT  43.992 2.605 54.594 2.641 ;
     RECT  55.656 2.605 57.006 2.641 ;
     RECT  59.544 2.497 65.394 2.641 ;
     RECT  66.384 2.371 69.39 2.641 ;
     RECT  37.836 2.641 40.497 2.711 ;
     RECT  17.64 2.641 36.486 2.731 ;
     RECT  37.836 2.711 40.554 2.731 ;
     RECT  41.364 2.641 54.63 2.731 ;
     RECT  55.656 2.641 57.078 2.731 ;
     RECT  55.656 2.731 57.114 2.767 ;
     RECT  58.5 2.767 58.662 2.803 ;
     RECT  17.316 2.731 36.486 2.827 ;
     RECT  17.28 2.827 36.486 2.875 ;
     RECT  37.836 2.731 54.702 2.875 ;
     RECT  59.544 2.641 69.39 2.875 ;
     RECT  9.54 2.641 16.47 2.911 ;
     RECT  17.208 2.875 36.486 2.911 ;
     RECT  9.036 2.911 36.846 3.001 ;
     RECT  37.8 2.875 54.702 3.037 ;
     RECT  55.656 2.767 57.654 3.064 ;
     RECT  58.428 2.803 58.734 3.064 ;
     RECT  55.656 3.064 58.734 3.073 ;
     RECT  59.544 2.875 69.462 3.073 ;
     RECT  7.815 2.413 8.097 3.109 ;
     RECT  8.928 3.001 36.846 3.109 ;
     RECT  37.62 3.037 54.702 3.109 ;
     RECT  55.656 3.073 69.462 3.109 ;
     RECT  74.592 2.641 74.61 3.569 ;
     RECT  7.815 3.109 69.462 3.685 ;
     RECT  74.448 3.685 74.466 3.691 ;
     RECT  7.815 3.685 69.858 3.839 ;
     RECT  6.66 3.955 6.678 3.991 ;
     RECT  7.815 3.839 69.03 3.991 ;
     RECT  75.384 3.721 75.402 4.423 ;
     RECT  6.66 3.991 69.03 4.459 ;
     RECT  75.384 4.423 75.51 4.459 ;
     RECT  70.056 4.459 70.074 4.495 ;
     RECT  71.712 3.181 71.73 4.495 ;
     RECT  71.532 4.495 71.73 4.531 ;
     RECT  72.615 2.413 72.897 4.531 ;
     RECT  74.412 3.691 74.466 4.531 ;
     RECT  75.24 4.459 75.51 4.531 ;
     RECT  5.688 4.261 5.706 4.621 ;
     RECT  6.516 4.459 69.03 4.621 ;
     RECT  70.056 4.495 70.362 4.651 ;
     RECT  69.804 4.651 70.362 4.765 ;
     RECT  71.532 4.531 72.897 4.765 ;
     RECT  74.412 4.531 75.51 4.765 ;
     RECT  5.688 4.621 69.03 4.927 ;
     RECT  69.804 4.765 72.897 4.927 ;
     RECT  5.4 4.927 72.897 4.955 ;
     RECT  74.124 4.765 75.51 4.963 ;
     RECT  73.656 4.963 75.51 4.999 ;
     RECT  6.408 4.955 72.897 5.071 ;
     RECT  73.656 4.999 76.338 5.071 ;
     RECT  6.408 5.071 76.338 5.179 ;
     RECT  77.112 4.927 77.13 5.179 ;
     RECT  6.408 5.179 77.13 5.341 ;
     RECT  78.015 2.413 78.297 5.341 ;
     RECT  5.4 4.955 5.418 5.701 ;
     RECT  6.408 5.341 78.297 5.701 ;
     RECT  4.968 5.701 5.418 5.729 ;
     RECT  6.336 5.701 78.297 6.115 ;
     RECT  4.968 5.729 5.058 6.511 ;
     RECT  5.904 6.115 78.297 6.511 ;
     RECT  4.968 6.511 78.297 6.619 ;
     RECT  4.896 6.619 78.297 6.655 ;
     RECT  4.824 6.655 78.297 6.691 ;
     RECT  4.716 6.691 78.297 7.231 ;
     RECT  4.68 7.231 78.297 7.663 ;
     RECT  4.608 7.663 78.297 7.969 ;
     RECT  4.572 7.969 78.297 7.997 ;
     RECT  17.532 7.997 78.297 8.041 ;
     RECT  4.572 7.997 16.758 8.275 ;
     RECT  79.236 8.311 79.254 8.501 ;
     RECT  4.356 8.275 16.758 8.525 ;
     RECT  4.572 8.525 16.758 8.779 ;
     RECT  17.532 8.041 78.462 8.779 ;
     RECT  4.572 8.779 78.462 8.851 ;
     RECT  4.572 8.851 78.498 9.049 ;
     RECT  79.668 8.941 79.686 9.049 ;
     RECT  79.668 9.049 79.758 9.085 ;
     RECT  3.564 8.977 3.582 9.352 ;
     RECT  3.42 9.352 3.582 9.391 ;
     RECT  4.572 9.049 78.786 9.391 ;
     RECT  79.668 9.085 79.974 9.391 ;
     RECT  2.415 2.413 2.697 9.643 ;
     RECT  3.42 9.391 79.974 9.643 ;
     RECT  80.82 9.553 80.838 9.787 ;
     RECT  80.82 9.787 80.982 9.823 ;
     RECT  80.82 9.823 81.522 9.859 ;
     RECT  2.415 9.643 79.974 9.895 ;
     RECT  80.784 9.859 81.558 9.895 ;
     RECT  2.415 9.895 81.558 10.327 ;
     RECT  2.415 10.327 81.666 10.741 ;
     RECT  2.415 10.741 81.738 10.931 ;
     RECT  2.415 10.931 81.666 11.705 ;
     RECT  3.528 11.705 81.666 12.325 ;
     RECT  3.528 12.325 82.278 12.451 ;
     RECT  3.492 12.451 82.278 12.479 ;
     RECT  2.415 11.705 2.697 12.757 ;
     RECT  3.492 12.479 82.17 12.757 ;
     RECT  2.415 12.757 82.17 13.325 ;
     RECT  2.415 13.325 82.134 13.397 ;
     RECT  2.415 13.397 82.062 14.135 ;
     RECT  2.415 14.135 81.774 14.171 ;
     RECT  2.415 14.171 81.738 14.369 ;
     RECT  2.415 14.369 81.702 15.151 ;
     RECT  2.415 15.151 82.17 15.251 ;
     RECT  83.415 2.413 83.697 15.421 ;
     RECT  79.848 15.251 82.17 15.565 ;
     RECT  82.908 15.421 83.697 15.565 ;
     RECT  79.848 15.565 83.697 16.033 ;
     RECT  2.415 15.251 79.002 16.105 ;
     RECT  79.812 16.033 83.697 16.105 ;
     RECT  2.415 16.105 83.697 18.221 ;
     RECT  2.415 18.221 78.678 19.201 ;
     RECT  79.416 18.221 83.697 19.201 ;
     RECT  2.415 19.201 83.697 20.461 ;
     RECT  2.376 20.461 83.697 20.993 ;
     RECT  2.415 20.993 83.697 21.659 ;
     RECT  2.415 21.659 8.19 22.441 ;
     RECT  8.928 21.659 83.697 22.441 ;
     RECT  2.415 22.441 83.697 22.621 ;
     RECT  2.415 22.621 84.114 22.811 ;
     RECT  2.415 22.811 83.697 23.161 ;
     RECT  2.376 23.161 83.697 23.315 ;
     RECT  2.415 23.315 83.697 25.519 ;
     RECT  2.415 25.519 83.754 25.619 ;
     RECT  50.148 25.619 83.754 25.979 ;
     RECT  2.415 25.619 49.374 26.401 ;
     RECT  50.148 25.979 83.697 26.401 ;
     RECT  2.415 26.401 83.697 27.211 ;
     RECT  2.376 27.211 83.697 27.571 ;
     RECT  2.376 27.571 83.862 27.635 ;
     RECT  2.415 27.635 83.862 28.409 ;
     RECT  2.415 28.409 83.754 28.445 ;
     RECT  2.415 28.445 83.697 32.225 ;
     RECT  2.415 32.225 82.062 32.495 ;
     RECT  2.415 32.495 80.442 32.801 ;
     RECT  79.596 32.801 80.442 33.385 ;
     RECT  81.576 32.495 82.062 33.385 ;
     RECT  79.596 33.385 82.062 33.547 ;
     RECT  2.415 32.801 78.822 33.643 ;
     RECT  79.596 33.547 82.566 33.643 ;
     RECT  2.415 33.643 82.566 33.853 ;
     RECT  83.415 32.225 83.697 33.853 ;
     RECT  2.415 33.853 83.697 34.231 ;
     RECT  2.415 34.231 84.042 34.925 ;
     RECT  45.324 34.925 84.042 35.041 ;
     RECT  2.415 34.925 44.55 35.509 ;
     RECT  45.324 35.041 84.114 35.609 ;
     RECT  2.376 35.509 44.55 35.671 ;
     RECT  45.324 35.609 46.386 35.671 ;
     RECT  2.376 35.671 46.386 36.275 ;
     RECT  2.415 36.275 46.386 36.355 ;
     RECT  47.124 35.609 84.114 36.355 ;
     RECT  2.415 36.355 84.114 39.341 ;
     RECT  2.415 39.341 52.398 40.099 ;
     RECT  2.415 40.099 52.47 40.171 ;
     RECT  53.208 39.341 84.114 40.171 ;
     RECT  2.415 40.171 84.114 40.685 ;
     RECT  2.415 40.685 2.97 40.829 ;
     RECT  2.415 40.829 2.826 40.835 ;
     RECT  3.708 40.685 84.114 40.865 ;
     RECT  3.708 40.865 3.798 41.099 ;
     RECT  3.708 41.099 3.726 41.135 ;
     RECT  4.572 40.865 84.114 41.207 ;
     RECT  4.752 41.207 84.114 42.017 ;
     RECT  5.148 42.017 84.114 42.179 ;
     RECT  5.724 42.179 84.114 42.251 ;
     RECT  6.084 42.251 84.114 42.719 ;
     RECT  59.148 42.719 84.114 43.483 ;
     RECT  6.084 42.719 58.194 43.573 ;
     RECT  59.076 43.483 84.114 43.573 ;
     RECT  6.084 43.573 84.114 44.221 ;
     RECT  5.94 44.221 84.114 44.249 ;
     RECT  5.94 44.249 84.078 44.285 ;
     RECT  6.192 44.285 84.078 44.717 ;
     RECT  6.3 44.717 84.078 45.185 ;
     RECT  6.3 45.185 60.606 45.329 ;
     RECT  61.38 45.185 84.078 45.329 ;
     RECT  77.832 45.329 84.078 45.527 ;
     RECT  6.3 45.329 42.138 45.571 ;
     RECT  6.084 45.571 42.138 45.797 ;
     RECT  6.084 45.797 33.858 45.841 ;
     RECT  5.796 45.841 33.858 45.959 ;
     RECT  42.912 45.329 60.606 46.111 ;
     RECT  61.38 45.329 77.022 46.111 ;
     RECT  34.668 45.797 42.138 46.201 ;
     RECT  42.912 46.111 60.642 46.201 ;
     RECT  61.38 46.111 77.058 46.201 ;
     RECT  77.832 45.527 83.898 46.201 ;
     RECT  34.668 46.201 60.642 46.381 ;
     RECT  61.38 46.201 83.898 46.381 ;
     RECT  34.668 46.381 83.898 46.571 ;
     RECT  27.684 45.959 33.858 46.651 ;
     RECT  34.668 46.571 54.882 46.651 ;
     RECT  5.796 45.959 26.802 46.741 ;
     RECT  5.508 46.741 26.802 46.747 ;
     RECT  27.684 46.651 54.882 46.747 ;
     RECT  5.508 46.747 54.882 46.805 ;
     RECT  5.508 46.805 53.802 47.281 ;
     RECT  54.54 46.805 54.882 47.309 ;
     RECT  5.112 47.281 53.802 47.615 ;
     RECT  54.612 47.309 54.882 47.623 ;
     RECT  54.612 47.623 54.954 47.695 ;
     RECT  55.764 46.571 83.898 47.695 ;
     RECT  5.364 47.615 53.802 48.199 ;
     RECT  5.364 48.199 53.874 48.271 ;
     RECT  54.612 47.695 83.898 48.271 ;
     RECT  5.364 48.271 83.898 48.425 ;
     RECT  5.364 48.425 28.566 48.505 ;
     RECT  4.824 48.505 28.566 48.541 ;
     RECT  4.5 48.541 28.566 48.703 ;
     RECT  4.464 48.703 28.566 48.767 ;
     RECT  4.464 48.767 27.234 48.811 ;
     RECT  4.284 48.811 27.234 48.929 ;
     RECT  4.464 48.929 27.234 49.235 ;
     RECT  28.044 48.767 28.566 49.315 ;
     RECT  29.415 48.425 83.898 49.315 ;
     RECT  4.5 49.235 27.234 49.549 ;
     RECT  28.044 49.315 83.898 49.549 ;
     RECT  4.5 49.549 83.898 50.008 ;
     RECT  4.428 50.008 83.898 50.161 ;
     RECT  4.356 50.161 83.898 50.323 ;
     RECT  4.248 50.323 83.898 50.621 ;
     RECT  4.248 50.621 83.79 50.665 ;
     RECT  4.176 50.665 83.79 51.539 ;
     RECT  4.248 51.539 83.79 52.681 ;
     RECT  4.14 52.681 83.79 52.889 ;
     RECT  4.14 52.889 59.706 53.015 ;
     RECT  60.516 52.889 83.697 53.663 ;
     RECT  4.284 53.015 59.706 53.869 ;
     RECT  60.516 53.663 81.558 53.869 ;
     RECT  4.284 53.869 81.558 54.211 ;
     RECT  4.248 54.211 81.558 54.445 ;
     RECT  82.296 53.663 83.697 54.445 ;
     RECT  4.248 54.445 83.697 54.473 ;
     RECT  4.284 54.473 83.697 54.751 ;
     RECT  4.284 54.751 83.934 55.319 ;
     RECT  4.32 55.319 83.934 57.713 ;
     RECT  4.32 57.713 83.862 58.621 ;
     RECT  4.32 58.621 84.078 59.603 ;
     RECT  4.32 59.603 33.678 59.729 ;
     RECT  34.56 59.603 84.078 60.385 ;
     RECT  34.56 60.385 84.114 60.683 ;
     RECT  34.56 60.683 84.078 60.691 ;
     RECT  4.32 59.729 33.318 60.889 ;
     RECT  34.344 60.691 84.078 60.889 ;
     RECT  4.32 60.889 84.078 61.727 ;
     RECT  4.32 61.727 83.79 62.581 ;
     RECT  4.32 62.581 83.898 63.005 ;
     RECT  5.112 63.005 83.898 63.113 ;
     RECT  5.148 63.113 83.898 63.887 ;
     RECT  4.32 63.005 4.374 64.201 ;
     RECT  5.148 63.887 10.242 64.201 ;
     RECT  11.052 63.887 83.898 64.291 ;
     RECT  4.32 64.201 10.242 64.355 ;
     RECT  11.052 64.291 84.042 64.705 ;
     RECT  5.148 64.355 10.242 64.903 ;
     RECT  10.98 64.705 84.042 64.903 ;
     RECT  4.32 64.355 4.374 65.407 ;
     RECT  5.148 64.903 84.042 65.435 ;
     RECT  5.148 65.435 41.706 65.551 ;
     RECT  4.212 65.407 4.374 65.669 ;
     RECT  4.212 65.669 4.23 65.885 ;
     RECT  42.552 65.435 84.042 66.091 ;
     RECT  42.552 66.091 84.114 66.217 ;
     RECT  42.516 66.217 84.114 66.361 ;
     RECT  5.112 65.551 41.706 66.595 ;
     RECT  42.48 66.361 84.114 66.595 ;
     RECT  5.112 66.595 84.114 66.793 ;
     RECT  4.896 66.793 84.114 67.163 ;
     RECT  5.148 67.163 83.697 67.559 ;
     RECT  5.256 67.559 83.697 67.667 ;
     RECT  5.868 67.667 83.697 68.135 ;
     RECT  6.12 68.135 83.697 68.945 ;
     RECT  6.3 68.945 83.697 69.629 ;
     RECT  6.3 69.629 12.294 69.755 ;
     RECT  13.032 69.629 83.697 70.025 ;
     RECT  6.588 69.755 12.294 70.061 ;
     RECT  6.66 70.061 12.294 70.501 ;
     RECT  13.032 70.025 37.386 70.501 ;
     RECT  6.66 70.501 37.386 70.871 ;
     RECT  15.876 70.871 37.386 70.979 ;
     RECT  38.124 70.025 83.697 71.645 ;
     RECT  38.124 71.645 82.602 71.789 ;
     RECT  15.876 70.979 37.278 71.887 ;
     RECT  38.124 71.789 82.062 71.887 ;
     RECT  6.66 70.871 15.138 72.031 ;
     RECT  15.876 71.887 82.062 72.031 ;
     RECT  6.66 72.031 82.062 72.059 ;
     RECT  11.448 72.059 82.062 72.413 ;
     RECT  11.448 72.413 80.694 72.527 ;
     RECT  81.54 72.413 82.062 72.571 ;
     RECT  25.344 72.527 80.694 72.689 ;
     RECT  81.54 72.571 82.494 72.689 ;
     RECT  11.448 72.527 24.606 72.725 ;
     RECT  6.66 72.059 10.494 72.805 ;
     RECT  11.448 72.725 21.438 72.805 ;
     RECT  22.248 72.725 24.606 72.833 ;
     RECT  6.66 72.805 21.438 72.959 ;
     RECT  64.296 72.689 80.694 72.959 ;
     RECT  64.296 72.959 80.37 72.995 ;
     RECT  64.296 72.995 79.434 73.277 ;
     RECT  64.296 73.277 78.966 73.301 ;
     RECT  80.208 72.995 80.37 73.373 ;
     RECT  64.296 73.301 78.93 73.499 ;
     RECT  6.66 72.959 21.366 73.535 ;
     RECT  64.296 73.499 78.642 73.535 ;
     RECT  80.352 73.373 80.37 73.571 ;
     RECT  22.608 72.833 24.606 73.615 ;
     RECT  64.296 73.535 77.094 73.679 ;
     RECT  64.296 73.679 76.23 73.769 ;
     RECT  22.536 73.615 24.606 73.885 ;
     RECT  25.344 72.689 63.378 73.913 ;
     RECT  78.015 73.535 78.642 73.913 ;
     RECT  21.96 73.885 24.606 73.921 ;
     RECT  25.344 73.913 62.766 73.921 ;
     RECT  64.296 73.769 76.122 73.921 ;
     RECT  76.968 73.679 77.094 73.949 ;
     RECT  77.076 73.949 77.094 74.039 ;
     RECT  63.648 73.921 76.122 74.045 ;
     RECT  63.648 74.045 75.402 74.075 ;
     RECT  63.648 74.075 74.826 74.219 ;
     RECT  6.66 73.535 21.186 74.461 ;
     RECT  21.96 73.921 62.766 74.461 ;
     RECT  6.66 74.461 62.766 74.731 ;
     RECT  63.648 74.219 63.774 74.731 ;
     RECT  6.66 74.731 63.774 74.759 ;
     RECT  64.656 74.219 74.826 74.885 ;
     RECT  71.532 74.885 74.826 74.929 ;
     RECT  71.532 74.929 74.862 75.127 ;
     RECT  21.384 74.759 63.774 75.155 ;
     RECT  21.384 75.155 62.766 75.227 ;
     RECT  64.656 74.885 65.178 75.271 ;
     RECT  71.532 75.127 74.898 75.299 ;
     RECT  6.66 74.759 20.538 75.496 ;
     RECT  6.624 75.496 20.538 75.533 ;
     RECT  21.384 75.227 42.534 75.533 ;
     RECT  6.84 75.533 20.538 75.541 ;
     RECT  21.384 75.533 33.462 75.541 ;
     RECT  73.872 75.299 74.898 75.659 ;
     RECT  6.84 75.541 33.462 75.695 ;
     RECT  63.864 75.271 65.178 75.767 ;
     RECT  73.98 75.659 74.898 75.929 ;
     RECT  71.532 75.299 73.134 76.001 ;
     RECT  66.024 74.885 70.794 76.045 ;
     RECT  71.532 76.001 72.897 76.045 ;
     RECT  66.024 76.045 72.897 76.073 ;
     RECT  63.864 75.767 63.882 76.109 ;
     RECT  68.904 76.073 72.897 76.199 ;
     RECT  34.344 75.533 42.534 76.219 ;
     RECT  43.272 75.227 62.766 76.219 ;
     RECT  6.84 75.695 33.426 76.343 ;
     RECT  70.524 76.199 72.897 76.343 ;
     RECT  34.344 76.219 62.766 76.351 ;
     RECT  6.84 76.343 14.238 76.363 ;
     RECT  15.12 76.343 33.426 76.397 ;
     RECT  21.132 76.397 33.426 76.441 ;
     RECT  34.236 76.351 62.766 76.441 ;
     RECT  71.172 76.343 72.897 76.469 ;
     RECT  66.024 76.073 67.878 76.505 ;
     RECT  71.172 76.469 71.622 76.505 ;
     RECT  15.12 76.397 20.178 76.739 ;
     RECT  71.46 76.505 71.622 76.739 ;
     RECT  71.604 76.739 71.622 76.775 ;
     RECT  6.804 76.363 14.238 76.855 ;
     RECT  68.904 76.199 68.922 76.883 ;
     RECT  6.732 76.855 14.238 76.925 ;
     RECT  15.12 76.739 20.034 76.973 ;
     RECT  6.912 76.925 14.238 77.009 ;
     RECT  66.132 76.505 67.878 77.045 ;
     RECT  7.668 77.009 14.238 77.089 ;
     RECT  21.132 76.441 62.766 77.125 ;
     RECT  21.096 77.125 62.766 77.131 ;
     RECT  7.668 77.089 14.346 77.161 ;
     RECT  15.12 76.973 19.998 77.161 ;
     RECT  21.096 77.131 62.802 77.161 ;
     RECT  64.656 75.767 65.178 77.161 ;
     RECT  7.668 77.161 19.998 77.315 ;
     RECT  67.176 77.045 67.878 77.315 ;
     RECT  7.74 77.315 19.998 77.585 ;
     RECT  6.912 77.009 6.93 77.597 ;
     RECT  7.815 77.585 19.998 77.899 ;
     RECT  21.096 77.161 63.522 77.899 ;
     RECT  7.815 77.899 63.522 77.971 ;
     RECT  7.815 77.971 63.594 78.089 ;
     RECT  7.815 78.089 63.018 78.125 ;
     RECT  9.216 78.125 63.018 78.233 ;
     RECT  9.216 78.233 62.91 78.359 ;
     RECT  66.132 77.045 66.186 78.359 ;
     RECT  7.815 78.125 8.478 78.395 ;
     RECT  11.376 78.359 62.91 78.539 ;
     RECT  9.216 78.359 10.35 78.629 ;
     RECT  11.376 78.539 15.858 78.629 ;
     RECT  9.216 78.629 9.234 78.665 ;
     RECT  11.376 78.629 15.714 78.665 ;
     RECT  64.656 77.161 65.286 78.737 ;
     RECT  11.52 78.665 15.642 79.007 ;
     RECT  16.632 78.539 62.91 79.015 ;
     RECT  16.632 79.015 62.982 79.051 ;
     RECT  11.52 79.007 12.366 79.169 ;
     RECT  13.215 79.007 15.642 79.169 ;
     RECT  14.724 79.169 15.642 79.205 ;
     RECT  16.632 79.051 63.522 79.229 ;
     RECT  11.52 79.169 12.114 79.241 ;
     RECT  16.632 79.229 63.486 79.277 ;
     RECT  16.632 79.277 19.098 79.285 ;
     RECT  11.52 79.241 11.538 79.349 ;
     RECT  66.168 78.359 66.186 79.349 ;
     RECT  13.215 79.169 13.806 79.439 ;
     RECT  15.264 79.205 15.642 79.439 ;
     RECT  13.215 79.439 13.59 79.475 ;
     RECT  16.452 79.285 19.098 79.517 ;
     RECT  15.336 79.439 15.642 79.591 ;
     RECT  16.452 79.517 17.406 79.591 ;
     RECT  15.336 79.591 17.406 79.619 ;
     RECT  18.18 79.517 19.098 79.619 ;
     RECT  15.444 79.619 17.406 79.709 ;
     RECT  16.524 79.709 17.406 79.979 ;
     RECT  18.18 79.619 19.026 79.979 ;
     RECT  15.444 79.709 15.462 80.015 ;
     RECT  17.388 79.979 17.406 80.015 ;
     RECT  20.376 79.277 63.486 80.023 ;
     RECT  18.576 79.979 19.026 80.051 ;
     RECT  16.524 79.979 16.542 80.159 ;
     RECT  64.656 78.737 64.674 80.285 ;
     RECT  20.16 80.023 63.486 80.321 ;
     RECT  18.615 80.051 19.026 80.357 ;
     RECT  20.664 80.321 63.486 80.357 ;
     RECT  20.664 80.357 22.23 80.429 ;
     RECT  20.664 80.429 22.158 80.519 ;
     RECT  20.772 80.519 22.158 80.591 ;
     RECT  20.772 80.591 22.086 80.825 ;
     RECT  20.772 80.825 21.402 80.897 ;
     RECT  21.384 80.897 21.402 81.059 ;
     RECT  23.04 80.357 63.486 81.059 ;
     RECT  18.615 80.357 18.897 81.163 ;
     RECT  23.94 81.059 63.486 81.175 ;
     RECT  23.04 81.059 23.058 81.203 ;
     RECT  67.215 77.315 67.878 81.239 ;
     RECT  18.615 81.163 18.99 81.341 ;
     RECT  23.94 81.175 63.702 81.341 ;
     RECT  24.015 81.341 63.702 81.677 ;
     RECT  38.268 81.677 63.702 81.707 ;
     RECT  38.484 81.707 63.702 81.743 ;
     RECT  38.484 81.743 38.79 81.869 ;
     RECT  24.015 81.677 37.53 82.013 ;
     RECT  38.592 81.869 38.79 82.013 ;
     RECT  39.744 81.743 63.702 82.049 ;
     RECT  24.015 82.013 24.606 82.139 ;
     RECT  25.344 82.013 37.53 82.139 ;
     RECT  24.015 82.139 24.462 82.175 ;
     RECT  25.344 82.139 37.134 82.175 ;
     RECT  39.78 82.049 63.702 82.247 ;
     RECT  34.092 82.175 37.134 82.409 ;
     RECT  39.996 82.247 63.702 82.409 ;
     RECT  25.38 82.175 33.066 82.445 ;
     RECT  25.524 82.445 33.066 82.481 ;
     RECT  34.776 82.409 36.558 82.553 ;
     RECT  32.904 82.481 33.066 82.679 ;
     RECT  39.996 82.409 63.522 82.679 ;
     RECT  36.54 82.553 36.558 82.715 ;
     RECT  25.524 82.481 32.166 82.787 ;
     RECT  34.815 82.553 35.802 82.787 ;
     RECT  42.084 82.679 63.522 82.823 ;
     RECT  32.904 82.679 32.922 82.985 ;
     RECT  38.772 82.013 38.79 82.985 ;
     RECT  42.084 82.823 63.414 83.213 ;
     RECT  27.648 82.787 32.166 83.219 ;
     RECT  40.215 82.679 41.022 83.219 ;
     RECT  42.66 83.213 63.414 83.219 ;
     RECT  25.524 82.787 26.874 83.255 ;
     RECT  27.648 83.219 30.762 83.255 ;
     RECT  31.932 83.219 32.166 83.255 ;
     RECT  32.148 83.255 32.166 83.291 ;
     RECT  25.524 83.255 26.766 83.327 ;
     RECT  33.804 83.101 33.822 83.327 ;
     RECT  25.524 83.327 26.622 83.363 ;
     RECT  42.912 83.219 63.414 83.399 ;
     RECT  25.524 83.363 26.154 83.489 ;
     RECT  27.648 83.255 30.546 83.489 ;
     RECT  38.808 83.263 38.826 83.489 ;
     RECT  42.912 83.399 42.93 83.489 ;
     RECT  25.524 83.489 26.01 83.525 ;
     RECT  28.368 83.489 30.114 83.525 ;
     RECT  25.596 83.525 25.938 83.561 ;
     RECT  28.584 83.525 28.602 83.561 ;
     RECT  29.415 83.525 30.114 83.561 ;
     RECT  43.74 83.399 63.414 83.561 ;
     RECT  25.92 83.561 25.938 83.633 ;
     RECT  44.64 83.561 63.414 83.669 ;
     RECT  44.64 83.669 62.298 83.867 ;
     RECT  2.415 40.835 2.697 83.987 ;
     RECT  7.815 78.395 8.097 83.987 ;
     RECT  13.215 79.475 13.497 83.987 ;
     RECT  18.615 81.341 18.897 83.987 ;
     RECT  24.015 82.175 24.297 83.987 ;
     RECT  29.415 83.561 29.697 83.987 ;
     RECT  34.815 82.787 35.097 83.987 ;
     RECT  40.215 83.219 40.497 83.987 ;
     RECT  67.215 81.239 67.497 83.987 ;
     RECT  72.615 76.469 72.897 83.987 ;
     RECT  78.015 73.913 78.297 83.987 ;
     RECT  83.415 71.645 83.697 83.987 ;
     RECT  43.74 83.561 43.758 84.029 ;
     RECT  44.748 83.867 62.298 84.035 ;
     RECT  44.748 84.035 55.17 84.065 ;
     RECT  56.016 84.035 62.298 84.065 ;
     RECT  44.928 84.065 55.17 84.077 ;
     RECT  50.724 84.077 55.17 84.173 ;
     RECT  56.016 84.065 62.262 84.173 ;
     RECT  50.724 84.173 55.134 84.209 ;
     RECT  54.684 84.209 55.134 84.221 ;
     RECT  2.415 83.987 2.505 84.257 ;
     RECT  7.815 83.987 7.905 84.257 ;
     RECT  13.215 83.987 13.305 84.257 ;
     RECT  18.615 83.987 18.705 84.257 ;
     RECT  24.015 83.987 24.105 84.257 ;
     RECT  29.415 83.987 29.505 84.257 ;
     RECT  34.815 83.987 34.905 84.257 ;
     RECT  40.215 83.987 40.305 84.257 ;
     RECT  44.928 84.077 49.734 84.257 ;
     RECT  56.016 84.173 62.118 84.257 ;
     RECT  67.215 83.987 67.305 84.257 ;
     RECT  72.615 83.987 72.705 84.257 ;
     RECT  78.015 83.987 78.105 84.257 ;
     RECT  83.415 83.987 83.505 84.257 ;
     RECT  44.928 84.257 45.09 84.299 ;
     RECT  56.988 84.257 61.29 84.317 ;
     RECT  56.988 84.317 59.382 84.365 ;
     RECT  62.1 84.257 62.118 84.365 ;
     RECT  44.928 84.299 44.946 84.371 ;
     RECT  50.724 84.209 53.91 84.859 ;
     RECT  56.016 84.257 56.034 84.883 ;
     RECT  46.224 84.257 49.734 84.911 ;
     RECT  50.544 84.859 53.91 84.911 ;
     RECT  55.944 84.883 56.034 84.911 ;
     RECT  51.732 84.911 53.91 84.941 ;
     RECT  50.544 84.911 50.922 84.989 ;
     RECT  46.296 84.911 49.734 85.517 ;
     RECT  51.732 84.941 52.074 85.517 ;
     RECT  55.116 84.221 55.134 85.517 ;
     RECT  50.724 84.989 50.922 85.565 ;
     RECT  50.724 85.565 50.742 85.613 ;
     RECT  49.284 85.517 49.734 85.963 ;
     RECT  52.056 85.517 52.074 85.963 ;
     RECT  53.064 84.941 53.91 85.963 ;
     RECT  52.056 85.963 53.91 86.059 ;
     RECT  55.944 84.911 55.962 86.059 ;
     RECT  57.852 84.365 59.382 86.093 ;
     RECT  46.296 85.517 47.358 86.141 ;
     RECT  46.296 86.141 47.322 86.189 ;
     RECT  49.284 85.963 50.382 86.189 ;
     RECT  60.48 84.317 61.29 86.189 ;
     RECT  46.296 86.189 46.314 86.237 ;
     RECT  52.056 86.059 54.09 86.237 ;
     RECT  60.48 86.189 60.93 86.237 ;
     RECT  47.124 86.189 47.322 86.285 ;
     RECT  48.132 85.517 48.51 86.285 ;
     RECT  49.284 86.189 49.302 86.285 ;
     RECT  50.364 86.189 50.382 86.285 ;
     RECT  52.056 86.237 53.082 86.285 ;
     RECT  53.892 86.237 54.09 86.285 ;
     RECT  55.692 86.059 55.962 86.285 ;
     RECT  57.996 86.093 58.014 86.285 ;
     RECT  59.076 86.093 59.382 86.285 ;
     RECT  60.48 86.237 60.498 86.285 ;
    LAYER M4 ;
     RECT  2.408 2.148 2.512 84.252 ;
     RECT  2.512 2.418 2.704 83.982 ;
     RECT  2.704 36.336 2.819 37.896 ;
     RECT  2.704 21.792 2.909 23.88 ;
     RECT  2.704 32.832 2.917 35.352 ;
     RECT  2.704 13.632 3.148 13.656 ;
     RECT  2.704 14.784 3.197 15.432 ;
     RECT  2.917 32.832 3.197 33.096 ;
     RECT  2.917 34.704 3.305 35.352 ;
     RECT  2.704 9.36 3.449 11.4 ;
     RECT  3.305 34.704 3.521 34.92 ;
     RECT  2.909 22.176 3.539 23.88 ;
     RECT  2.704 26.208 3.539 27.912 ;
     RECT  3.539 27.888 3.557 27.912 ;
     RECT  3.449 10.416 3.629 11.4 ;
     RECT  3.539 26.208 3.737 26.76 ;
     RECT  2.704 16.896 3.74 16.92 ;
     RECT  3.629 11.376 3.769 11.4 ;
     RECT  3.74 16.896 3.781 17.112 ;
     RECT  2.704 24.912 3.781 24.936 ;
     RECT  3.197 15.408 3.805 15.432 ;
     RECT  3.781 16.896 3.805 17.688 ;
     RECT  2.704 18.72 3.805 18.744 ;
     RECT  3.805 15.408 3.809 18.744 ;
     RECT  2.704 19.968 3.809 20.184 ;
     RECT  3.809 17.088 3.827 18.744 ;
     RECT  3.781 24.912 3.845 25.08 ;
     RECT  2.704 40.656 3.845 40.824 ;
     RECT  3.845 25.056 3.868 25.08 ;
     RECT  2.704 29.328 3.913 29.352 ;
     RECT  2.704 30.768 3.973 30.792 ;
     RECT  2.819 36.48 4.057 37.896 ;
     RECT  3.809 15.984 4.061 16.008 ;
     RECT  3.973 30.768 4.061 31.368 ;
     RECT  4.057 36.432 4.261 37.896 ;
     RECT  3.913 28.464 4.277 29.352 ;
     RECT  4.261 36.432 4.307 38.712 ;
     RECT  3.877 20.4 4.309 20.424 ;
     RECT  3.449 9.36 4.345 9.384 ;
     RECT  3.769 11.376 4.385 11.976 ;
     RECT  3.539 22.176 4.385 23.16 ;
     RECT  4.309 20.4 4.393 21.096 ;
     RECT  3.827 17.424 4.525 18.744 ;
     RECT  4.417 50.016 4.525 50.04 ;
     RECT  4.393 20.4 4.529 20.952 ;
     RECT  4.385 11.376 4.565 11.928 ;
     RECT  3.737 26.208 4.777 26.28 ;
     RECT  4.669 27.312 4.777 27.336 ;
     RECT  4.385 22.176 4.817 22.2 ;
     RECT  4.561 55.44 4.817 55.464 ;
     RECT  4.525 17.424 4.885 18.792 ;
     RECT  4.813 52.416 4.885 52.44 ;
     RECT  4.525 50.016 4.889 51 ;
     RECT  4.345 8.496 4.961 9.384 ;
     RECT  3.521 34.896 4.993 34.92 ;
     RECT  4.307 36.432 4.993 37.032 ;
     RECT  4.885 17.088 5.029 18.792 ;
     RECT  4.993 34.896 5.029 37.032 ;
     RECT  4.889 50.016 5.033 50.904 ;
     RECT  4.777 26.208 5.065 27.336 ;
     RECT  5.065 26.208 5.069 27.384 ;
     RECT  4.061 30.768 5.101 30.936 ;
     RECT  3.197 32.832 5.101 32.856 ;
     RECT  4.777 39.744 5.137 39.768 ;
     RECT  3.845 40.8 5.137 40.824 ;
     RECT  5.029 16.752 5.141 18.792 ;
     RECT  5.101 32.592 5.213 33.096 ;
     RECT  4.885 52.416 5.213 53.016 ;
     RECT  4.307 38.688 5.249 38.712 ;
     RECT  5.029 48.672 5.249 48.696 ;
     RECT  4.345 13.632 5.281 13.656 ;
     RECT  5.033 50.016 5.353 50.04 ;
     RECT  5.101 30.768 5.389 31.32 ;
     RECT  4.277 28.464 5.465 28.488 ;
     RECT  5.464 58.128 5.509 58.152 ;
     RECT  4.961 8.496 5.533 8.52 ;
     RECT  5.281 13.632 5.533 14.472 ;
     RECT  5.509 57.552 5.533 58.152 ;
     RECT  5.069 26.256 5.537 27.384 ;
     RECT  4.201 65.856 5.569 65.88 ;
     RECT  5.533 7.776 5.677 8.52 ;
     RECT  5.029 34.608 5.677 37.032 ;
     RECT  5.569 65.856 5.681 66.696 ;
     RECT  5.533 13.632 5.713 14.712 ;
     RECT  5.317 9.792 5.753 9.816 ;
     RECT  5.213 52.992 5.785 53.016 ;
     RECT  4.777 41.904 5.821 41.928 ;
     RECT  5.137 39.744 5.825 40.824 ;
     RECT  5.713 13.344 5.857 14.712 ;
     RECT  5.821 41.808 5.857 41.928 ;
     RECT  5.857 41.616 5.941 41.928 ;
     RECT  5.353 49.248 5.969 50.04 ;
     RECT  4.565 11.904 5.996 11.928 ;
     RECT  5.389 30.192 6.005 31.32 ;
     RECT  5.893 10.896 6.037 10.92 ;
     RECT  5.996 11.904 6.037 12.168 ;
     RECT  6.037 10.896 6.073 12.168 ;
     RECT  5.857 13.344 6.073 15.672 ;
     RECT  6.005 30.384 6.073 31.32 ;
     RECT  5.213 32.592 6.073 32.616 ;
     RECT  6.073 10.896 6.077 15.672 ;
     RECT  4.529 20.736 6.109 20.952 ;
     RECT  6.077 10.896 6.145 13.608 ;
     RECT  4.993 24.816 6.145 24.84 ;
     RECT  5.497 46.752 6.145 46.776 ;
     RECT  6.109 20.736 6.149 21.672 ;
     RECT  5.825 39.744 6.181 40.296 ;
     RECT  5.785 52.992 6.181 53.064 ;
     RECT  5.569 59.712 6.185 59.736 ;
     RECT  6.149 20.928 6.193 21.672 ;
     RECT  6.037 61.008 6.217 61.032 ;
     RECT  5.677 6.864 6.221 8.52 ;
     RECT  5.533 57.408 6.229 58.152 ;
     RECT  5.929 44.256 6.236 44.28 ;
     RECT  5.677 34.416 6.253 37.032 ;
     RECT  6.145 45.984 6.253 46.776 ;
     RECT  6.217 59.808 6.257 61.032 ;
     RECT  5.141 17.04 6.289 18.792 ;
     RECT  6.145 24.816 6.289 25.128 ;
     RECT  6.077 14.688 6.293 15.672 ;
     RECT  6.289 17.04 6.293 18.984 ;
     RECT  6.257 59.808 6.301 60.456 ;
     RECT  6.236 43.728 6.323 44.28 ;
     RECT  6.323 44.208 6.325 44.28 ;
     RECT  6.253 45.6 6.325 46.776 ;
     RECT  6.073 30.384 6.329 32.616 ;
     RECT  6.181 52.992 6.329 53.592 ;
     RECT  6.325 44.208 6.337 46.776 ;
     RECT  6.229 57.408 6.361 58.488 ;
     RECT  6.361 51.984 6.433 52.008 ;
     RECT  6.289 24.432 6.437 25.128 ;
     RECT  6.221 6.864 6.469 7.944 ;
     RECT  5.317 23.28 6.577 23.304 ;
     RECT  5.537 26.256 6.577 26.904 ;
     RECT  5.677 28.128 6.577 28.152 ;
     RECT  6.217 38.448 6.577 38.472 ;
     RECT  6.181 39.504 6.577 40.296 ;
     RECT  5.941 41.808 6.577 41.928 ;
     RECT  6.433 51.936 6.613 52.008 ;
     RECT  6.329 52.992 6.613 53.112 ;
     RECT  6.469 6.768 6.617 7.944 ;
     RECT  6.577 23.04 6.617 23.304 ;
     RECT  6.577 41.808 6.617 42.168 ;
     RECT  6.617 6.864 6.653 7.944 ;
     RECT  6.253 34.32 6.653 37.032 ;
     RECT  6.145 10.128 6.707 13.608 ;
     RECT  6.707 10.128 6.721 11.448 ;
     RECT  6.337 45.984 6.721 46.776 ;
     RECT  6.577 26.256 6.761 28.152 ;
     RECT  6.613 75.504 6.792 75.528 ;
     RECT  6.721 76.896 6.792 76.92 ;
     RECT  4.885 55.776 6.793 55.8 ;
     RECT  6.505 67.296 6.793 67.32 ;
     RECT  6.661 5.712 6.829 5.736 ;
     RECT  6.757 64.128 6.829 64.152 ;
     RECT  6.721 9.888 6.833 11.448 ;
     RECT  6.653 34.464 6.833 37.032 ;
     RECT  6.361 56.976 6.833 58.488 ;
     RECT  6.829 5.712 6.865 5.832 ;
     RECT  5.969 49.248 6.901 49.272 ;
     RECT  6.792 75.504 6.901 76.92 ;
     RECT  6.833 9.888 6.937 11.16 ;
     RECT  6.901 49.104 6.973 49.272 ;
     RECT  6.833 35.808 7.045 37.032 ;
     RECT  6.721 45.984 7.117 46.92 ;
     RECT  6.829 64.128 7.117 64.584 ;
     RECT  6.793 67.296 7.189 67.464 ;
     RECT  6.707 12.768 7.225 13.608 ;
     RECT  7.225 12.768 7.297 13.896 ;
     RECT  6.193 20.928 7.297 21.528 ;
     RECT  7.261 29.232 7.333 29.256 ;
     RECT  6.617 23.04 7.369 23.064 ;
     RECT  6.329 30.912 7.369 32.616 ;
     RECT  6.437 25.104 7.477 25.128 ;
     RECT  6.761 26.256 7.477 27.336 ;
     RECT  6.973 48.96 7.549 49.272 ;
     RECT  6.613 51.936 7.549 53.112 ;
     RECT  7.045 35.808 7.573 37.368 ;
     RECT  6.577 38.448 7.573 40.296 ;
     RECT  7.369 22.512 7.585 23.064 ;
     RECT  6.833 34.464 7.621 34.776 ;
     RECT  7.549 48.24 7.621 49.272 ;
     RECT  6.901 75.504 7.621 77.592 ;
     RECT  6.865 5.616 7.628 5.832 ;
     RECT  7.628 5.088 7.657 5.832 ;
     RECT  7.297 12.768 7.657 14.184 ;
     RECT  6.293 15.408 7.657 15.672 ;
     RECT  6.865 16.8 7.657 16.824 ;
     RECT  6.937 9.504 7.669 11.16 ;
     RECT  7.369 30.912 7.669 33.048 ;
     RECT  7.621 34.128 7.669 34.776 ;
     RECT  7.657 12.768 7.693 15.672 ;
     RECT  7.657 16.656 7.693 16.824 ;
     RECT  7.621 48.144 7.729 49.272 ;
     RECT  7.693 12.768 7.765 16.824 ;
     RECT  6.337 44.208 7.765 44.712 ;
     RECT  7.117 45.984 7.765 47.16 ;
     RECT  5.681 65.856 7.765 65.88 ;
     RECT  7.189 67.056 7.765 67.464 ;
     RECT  7.765 44.208 7.801 47.16 ;
     RECT  7.765 65.856 7.801 67.464 ;
     RECT  7.657 4.944 7.808 5.832 ;
     RECT  6.653 7.056 7.808 7.944 ;
     RECT  7.669 9.36 7.808 11.16 ;
     RECT  7.765 12.768 7.808 16.92 ;
     RECT  6.293 18.096 7.808 18.984 ;
     RECT  7.297 20.784 7.808 21.528 ;
     RECT  7.585 22.512 7.808 23.352 ;
     RECT  7.477 25.104 7.808 27.336 ;
     RECT  7.333 28.992 7.808 29.256 ;
     RECT  7.669 30.912 7.808 34.776 ;
     RECT  7.573 35.808 7.808 40.296 ;
     RECT  6.617 42 7.808 42.168 ;
     RECT  7.801 43.92 7.808 47.16 ;
     RECT  7.729 48.144 7.808 49.56 ;
     RECT  7.549 51.936 7.808 53.352 ;
     RECT  6.793 55.2 7.808 55.8 ;
     RECT  6.833 57.024 7.808 58.488 ;
     RECT  6.301 59.808 7.808 59.832 ;
     RECT  6.865 62.688 7.808 62.712 ;
     RECT  7.117 64.08 7.808 64.584 ;
     RECT  7.801 65.712 7.808 67.464 ;
     RECT  6.853 69.456 7.808 69.48 ;
     RECT  7.009 72.816 7.808 72.84 ;
     RECT  7.621 75.408 7.808 77.592 ;
     RECT  7.808 2.148 7.912 84.252 ;
     RECT  7.912 2.418 8.104 83.982 ;
     RECT  8.104 43.872 8.237 51.24 ;
     RECT  8.104 57.024 8.237 59.832 ;
     RECT  8.104 18.144 8.243 24.408 ;
     RECT  8.104 9.36 8.273 17.16 ;
     RECT  8.104 3.408 8.281 7.992 ;
     RECT  8.104 77.52 8.309 77.592 ;
     RECT  8.273 9.36 8.345 16.92 ;
     RECT  8.104 65.712 8.381 65.736 ;
     RECT  8.345 16.56 8.453 16.92 ;
     RECT  8.104 38.688 8.483 40.68 ;
     RECT  8.104 70.704 8.489 75.432 ;
     RECT  8.104 67.104 8.525 67.56 ;
     RECT  8.345 9.36 8.531 15.576 ;
     RECT  8.243 18.144 8.531 18.84 ;
     RECT  8.489 75.12 8.531 75.432 ;
     RECT  8.104 25.536 8.561 37.656 ;
     RECT  8.281 4.656 8.579 7.992 ;
     RECT  8.453 16.656 8.597 16.92 ;
     RECT  8.237 46.704 8.597 51.24 ;
     RECT  8.104 52.32 8.633 52.344 ;
     RECT  8.243 20.16 8.705 24.408 ;
     RECT  8.104 53.328 8.705 53.352 ;
     RECT  8.561 25.728 8.819 37.656 ;
     RECT  8.819 25.728 8.867 34.824 ;
     RECT  8.237 57.12 8.867 59.64 ;
     RECT  8.104 62.208 8.885 62.28 ;
     RECT  8.597 16.8 8.921 16.92 ;
     RECT  8.483 38.736 8.921 40.68 ;
     RECT  8.531 9.36 9.029 13.032 ;
     RECT  8.531 75.408 9.029 75.432 ;
     RECT  8.104 54.432 9.097 54.456 ;
     RECT  8.104 56.016 9.097 56.04 ;
     RECT  8.579 4.656 9.101 6.456 ;
     RECT  9.029 9.36 9.101 10.152 ;
     RECT  8.237 43.872 9.133 45.576 ;
     RECT  8.705 20.16 9.137 22.536 ;
     RECT  8.867 57.168 9.173 59.64 ;
     RECT  9.101 10.128 9.209 10.152 ;
     RECT  9.137 20.16 9.245 21.672 ;
     RECT  9.029 11.328 9.281 11.496 ;
     RECT  9.097 54.432 9.281 56.04 ;
     RECT  8.489 70.704 9.317 73.8 ;
     RECT  8.705 23.808 9.353 24.408 ;
     RECT  8.579 7.44 9.421 7.992 ;
     RECT  9.313 8.976 9.421 9 ;
     RECT  8.281 3.408 9.465 3.432 ;
     RECT  9.317 72.192 9.533 73.8 ;
     RECT  9.465 2.688 9.539 3.432 ;
     RECT  8.867 25.728 9.569 34.632 ;
     RECT  8.921 38.736 9.569 40.344 ;
     RECT  9.133 43.392 9.601 45.576 ;
     RECT  8.531 14.112 9.605 15.576 ;
     RECT  9.353 24.384 9.673 24.408 ;
     RECT  9.569 27.648 9.683 34.632 ;
     RECT  9.601 43.296 9.709 45.576 ;
     RECT  8.597 46.704 9.709 51.048 ;
     RECT  9.101 5.808 9.713 6.456 ;
     RECT  8.309 77.52 9.781 77.544 ;
     RECT  9.281 54.432 9.785 54.456 ;
     RECT  8.525 67.152 9.785 67.56 ;
     RECT  9.781 76.56 9.817 77.544 ;
     RECT  9.683 31.344 9.821 34.632 ;
     RECT  9.533 72.672 9.821 73.8 ;
     RECT  9.673 24.384 9.857 24.504 ;
     RECT  9.709 43.296 9.889 51.048 ;
     RECT  9.281 55.968 9.889 56.04 ;
     RECT  9.173 57.168 9.889 58.92 ;
     RECT  9.857 24.48 9.925 24.504 ;
     RECT  9.569 25.728 9.925 26.664 ;
     RECT  9.889 43.296 9.925 51.96 ;
     RECT  9.605 14.16 9.929 15.576 ;
     RECT  9.421 7.44 9.961 9 ;
     RECT  9.929 14.16 9.965 15.096 ;
     RECT  9.821 31.872 9.965 34.632 ;
     RECT  8.531 18.816 9.997 18.84 ;
     RECT  9.925 43.296 10.001 52.488 ;
     RECT  8.885 62.256 10.001 62.28 ;
     RECT  9.101 4.656 10.069 4.824 ;
     RECT  9.961 6.816 10.105 9 ;
     RECT  8.819 36 10.141 37.656 ;
     RECT  9.961 69.264 10.177 69.288 ;
     RECT  8.921 16.8 10.213 16.824 ;
     RECT  10.141 35.856 10.217 37.656 ;
     RECT  9.925 63.408 10.249 63.432 ;
     RECT  10.177 69.072 10.249 69.288 ;
     RECT  9.925 53.568 10.259 54.36 ;
     RECT  10.001 52.224 10.285 52.488 ;
     RECT  10.259 53.568 10.285 53.592 ;
     RECT  9.683 27.648 10.289 30.264 ;
     RECT  10.249 69.072 10.321 69.432 ;
     RECT  9.317 70.704 10.321 70.728 ;
     RECT  10.217 36.864 10.325 37.656 ;
     RECT  10.001 43.296 10.325 51.048 ;
     RECT  9.889 55.968 10.361 58.92 ;
     RECT  10.217 35.856 10.393 35.88 ;
     RECT  10.069 4.416 10.429 4.824 ;
     RECT  9.713 5.808 10.429 5.832 ;
     RECT  10.361 56.064 10.465 58.92 ;
     RECT  10.105 6.816 10.469 9.144 ;
     RECT  10.213 16.08 10.501 16.824 ;
     RECT  10.393 35.76 10.505 35.88 ;
     RECT  10.465 56.064 10.505 59.16 ;
     RECT  10.505 35.856 10.541 35.88 ;
     RECT  9.817 76.56 10.541 78.12 ;
     RECT  10.469 8.736 10.573 9.144 ;
     RECT  10.541 76.56 10.573 77.544 ;
     RECT  10.573 75.696 10.577 77.544 ;
     RECT  10.577 75.696 10.613 76.584 ;
     RECT  10.321 69.072 10.645 70.728 ;
     RECT  9.029 12.528 10.681 13.032 ;
     RECT  10.645 69.072 10.681 71.4 ;
     RECT  10.573 41.184 10.685 41.208 ;
     RECT  9.997 18.816 10.748 19.368 ;
     RECT  9.245 20.688 10.748 21.672 ;
     RECT  9.925 24.48 10.753 26.664 ;
     RECT  10.289 27.648 10.753 27.672 ;
     RECT  10.505 57.024 10.757 59.16 ;
     RECT  10.681 69.024 10.757 71.4 ;
     RECT  10.501 16.08 10.789 16.92 ;
     RECT  10.757 70.608 10.789 71.4 ;
     RECT  9.821 72.672 10.789 73.416 ;
     RECT  9.965 14.4 10.828 15.096 ;
     RECT  10.613 75.696 10.829 75.816 ;
     RECT  9.569 38.736 10.861 39.864 ;
     RECT  10.829 75.696 10.865 75.72 ;
     RECT  9.965 31.872 10.901 34.488 ;
     RECT  10.757 69.024 10.901 69.576 ;
     RECT  10.789 16.08 10.937 17.496 ;
     RECT  10.937 16.128 10.969 17.496 ;
     RECT  10.901 69.072 10.973 69.576 ;
     RECT  10.429 4.416 11.005 5.832 ;
     RECT  10.469 6.816 11.005 7.656 ;
     RECT  10.828 14.4 11.009 14.472 ;
     RECT  10.757 57.072 11.045 59.16 ;
     RECT  10.973 69.216 11.045 69.576 ;
     RECT  10.573 8.736 11.077 9.672 ;
     RECT  10.748 18.816 11.077 21.672 ;
     RECT  10.465 22.992 11.077 23.016 ;
     RECT  10.861 38.736 11.081 40.584 ;
     RECT  9.817 42.192 11.081 42.216 ;
     RECT  11.005 4.416 11.117 7.656 ;
     RECT  11.081 38.736 11.117 40.488 ;
     RECT  10.789 70.608 11.149 73.416 ;
     RECT  9.281 11.328 11.189 11.448 ;
     RECT  9.539 2.688 11.257 2.712 ;
     RECT  10.289 29.088 11.257 30.264 ;
     RECT  10.325 36.864 11.257 37.032 ;
     RECT  11.117 38.736 11.257 39.864 ;
     RECT  11.117 4.416 11.324 6.072 ;
     RECT  11.189 11.376 11.329 11.448 ;
     RECT  10.681 12.528 11.329 13.368 ;
     RECT  11.257 2.688 11.365 2.76 ;
     RECT  11.324 4.272 11.365 6.072 ;
     RECT  11.257 36.096 11.401 37.032 ;
     RECT  11.257 38.16 11.401 39.864 ;
     RECT  11.329 11.376 11.437 13.368 ;
     RECT  10.753 24.48 11.437 27.672 ;
     RECT  11.257 28.656 11.437 30.264 ;
     RECT  11.437 24.48 11.441 30.264 ;
     RECT  10.969 16.128 11.477 17.736 ;
     RECT  11.077 18.816 11.509 23.016 ;
     RECT  10.901 31.872 11.509 34.248 ;
     RECT  11.365 2.688 11.513 6.072 ;
     RECT  11.401 36.096 11.548 39.864 ;
     RECT  11.477 16.128 11.549 17.64 ;
     RECT  11.441 26.112 11.549 30.264 ;
     RECT  11.548 38.16 11.549 39.864 ;
     RECT  11.509 54.672 11.581 54.696 ;
     RECT  11.513 2.688 11.585 2.76 ;
     RECT  10.325 43.296 11.612 46.248 ;
     RECT  10.325 47.616 11.612 51.048 ;
     RECT  11.509 18.72 11.621 23.016 ;
     RECT  10.285 52.224 11.621 53.592 ;
     RECT  10.069 67.968 11.621 67.992 ;
     RECT  11.549 16.416 11.657 17.64 ;
     RECT  11.612 43.296 11.689 51.048 ;
     RECT  11.621 52.224 11.689 53.016 ;
     RECT  11.621 22.512 11.693 23.016 ;
     RECT  11.045 57.072 11.693 58.68 ;
     RECT  11.693 22.752 11.765 23.016 ;
     RECT  11.621 18.72 11.837 20.808 ;
     RECT  11.581 54.624 11.869 54.696 ;
     RECT  11.117 7.632 11.905 7.656 ;
     RECT  11.077 8.736 11.905 10.056 ;
     RECT  11.549 26.112 11.945 27.432 ;
     RECT  11.549 38.16 11.945 39.768 ;
     RECT  11.869 54.144 11.945 54.696 ;
     RECT  11.837 18.72 11.981 19.368 ;
     RECT  11.945 26.112 11.981 27.336 ;
     RECT  11.693 58.368 11.981 58.68 ;
     RECT  10.249 63.408 11.981 63.624 ;
     RECT  11.657 17.616 12.017 17.64 ;
     RECT  11.869 64.896 12.085 64.92 ;
     RECT  11.905 66.24 12.085 66.264 ;
     RECT  11.585 2.688 12.089 2.712 ;
     RECT  11.548 36.096 12.121 37.128 ;
     RECT  11.905 7.632 12.157 10.056 ;
     RECT  11.045 69.216 12.188 69.528 ;
     RECT  11.149 70.608 12.188 73.56 ;
     RECT  12.085 64.896 12.193 66.264 ;
     RECT  12.188 69.216 12.301 73.56 ;
     RECT  11.437 11.376 12.325 13.704 ;
     RECT  11.513 4.464 12.445 6.072 ;
     RECT  12.157 7.632 12.445 10.2 ;
     RECT  12.229 41.424 12.553 41.448 ;
     RECT  12.445 4.464 12.565 10.2 ;
     RECT  12.325 11.376 12.565 14.664 ;
     RECT  12.553 41.424 12.589 41.496 ;
     RECT  11.329 62.016 12.625 62.04 ;
     RECT  12.193 63.264 12.625 63.288 ;
     RECT  12.565 4.464 12.661 14.664 ;
     RECT  11.657 16.416 12.697 16.44 ;
     RECT  11.441 25.008 12.769 25.032 ;
     RECT  12.121 36.048 12.769 37.128 ;
     RECT  11.693 57.072 12.769 57.096 ;
     RECT  12.589 41.424 12.841 42.216 ;
     RECT  11.689 43.296 12.841 53.016 ;
     RECT  12.769 35.28 12.877 37.656 ;
     RECT  12.661 4.464 12.901 14.856 ;
     RECT  12.553 55.68 12.913 55.704 ;
     RECT  12.769 57.072 12.913 57.432 ;
     RECT  12.769 24.192 12.985 25.032 ;
     RECT  11.981 26.112 12.985 26.904 ;
     RECT  12.625 62.016 13.021 63.288 ;
     RECT  12.301 69.216 13.057 73.752 ;
     RECT  12.985 24.192 13.093 26.904 ;
     RECT  12.841 40.944 13.093 53.016 ;
     RECT  13.057 69.216 13.093 74.664 ;
     RECT  12.985 77.136 13.093 77.16 ;
     RECT  12.229 78.624 13.093 78.648 ;
     RECT  11.765 22.752 13.165 22.776 ;
     RECT  13.093 23.856 13.165 26.904 ;
     RECT  11.549 28.656 13.165 30.264 ;
     RECT  13.093 40.848 13.165 53.016 ;
     RECT  11.945 54.144 13.165 54.168 ;
     RECT  12.697 2.256 13.208 2.568 ;
     RECT  12.901 4.08 13.208 14.856 ;
     RECT  12.697 16.416 13.208 16.536 ;
     RECT  13.057 17.616 13.208 17.64 ;
     RECT  11.981 18.72 13.208 19.272 ;
     RECT  11.837 20.4 13.208 20.424 ;
     RECT  13.165 22.752 13.208 26.904 ;
     RECT  13.165 28.656 13.208 30.648 ;
     RECT  11.509 31.776 13.208 34.248 ;
     RECT  12.877 35.232 13.208 37.656 ;
     RECT  11.945 38.784 13.208 39.768 ;
     RECT  13.165 40.848 13.208 54.168 ;
     RECT  12.913 55.68 13.208 57.432 ;
     RECT  11.981 58.464 13.208 58.68 ;
     RECT  13.021 62.016 13.208 63.528 ;
     RECT  12.193 64.704 13.208 66.744 ;
     RECT  12.877 67.824 13.208 67.848 ;
     RECT  13.093 68.928 13.208 74.664 ;
     RECT  13.093 77.136 13.208 78.648 ;
     RECT  13.208 2.148 13.312 84.252 ;
     RECT  13.312 2.418 13.504 83.982 ;
     RECT  13.504 61.392 13.529 63.912 ;
     RECT  13.529 61.392 13.601 63.528 ;
     RECT  13.601 61.392 13.673 62.856 ;
     RECT  13.504 69.072 13.709 71.928 ;
     RECT  13.504 10.176 13.745 13.128 ;
     RECT  13.504 34.656 13.745 53.592 ;
     RECT  13.504 55.68 13.745 58.392 ;
     RECT  13.504 2.688 13.781 9.096 ;
     RECT  13.745 34.656 13.817 53.016 ;
     RECT  13.817 52.368 13.853 53.016 ;
     RECT  13.504 30.624 13.889 30.648 ;
     RECT  13.817 34.656 13.889 51.336 ;
     RECT  13.889 34.656 13.907 42.12 ;
     RECT  13.673 61.488 13.925 62.856 ;
     RECT  13.889 43.104 13.997 51.336 ;
     RECT  13.504 66.24 13.997 66.6 ;
     RECT  13.781 2.688 14.069 9 ;
     RECT  13.745 56.352 14.141 58.392 ;
     RECT  13.504 76.224 14.177 78.648 ;
     RECT  14.177 77.664 14.249 78.648 ;
     RECT  13.504 14.256 14.285 18.792 ;
     RECT  13.504 20.4 14.285 23.88 ;
     RECT  13.907 34.656 14.285 38.712 ;
     RECT  14.141 57.408 14.285 58.392 ;
     RECT  13.504 74.64 14.285 74.664 ;
     RECT  13.745 10.848 14.291 13.128 ;
     RECT  13.504 27.168 14.321 27.912 ;
     RECT  14.249 77.712 14.321 78.648 ;
     RECT  14.291 13.056 14.329 13.128 ;
     RECT  14.285 14.256 14.393 14.28 ;
     RECT  14.285 15.648 14.429 18.792 ;
     RECT  13.925 62.544 14.429 62.856 ;
     RECT  13.504 67.776 14.429 68.04 ;
     RECT  13.907 39.984 14.465 42.12 ;
     RECT  13.504 24.912 14.501 24.936 ;
     RECT  14.429 62.544 14.537 62.568 ;
     RECT  14.177 76.224 14.573 76.68 ;
     RECT  14.429 15.84 14.645 18.792 ;
     RECT  14.285 38.688 14.645 38.712 ;
     RECT  13.504 73.344 14.713 73.464 ;
     RECT  14.285 22.704 14.717 23.88 ;
     RECT  13.504 32.448 14.821 33.48 ;
     RECT  14.285 34.656 14.821 37.608 ;
     RECT  14.717 22.8 14.857 23.88 ;
     RECT  14.321 27.312 14.857 27.912 ;
     RECT  13.504 28.992 14.857 29.352 ;
     RECT  14.857 22.8 14.897 24.744 ;
     RECT  14.429 68.016 14.933 68.04 ;
     RECT  14.285 20.4 14.969 21.672 ;
     RECT  13.997 43.344 14.969 51.336 ;
     RECT  14.465 41.424 15.001 42.12 ;
     RECT  14.969 20.4 15.005 20.424 ;
     RECT  14.821 32.448 15.005 37.608 ;
     RECT  15.005 32.448 15.011 33.48 ;
     RECT  14.969 45.984 15.037 51.336 ;
     RECT  13.853 52.848 15.037 53.016 ;
     RECT  13.997 66.576 15.113 66.6 ;
     RECT  13.709 69.072 15.149 71.736 ;
     RECT  14.713 73.344 15.149 74.136 ;
     RECT  14.969 43.344 15.155 45 ;
     RECT  15.001 41.424 15.185 42.312 ;
     RECT  15.037 45.984 15.185 53.016 ;
     RECT  14.291 10.848 15.253 11.736 ;
     RECT  14.605 31.296 15.289 31.32 ;
     RECT  15.011 32.448 15.289 33.288 ;
     RECT  14.069 8.16 15.293 9 ;
     RECT  15.253 10.752 15.325 11.736 ;
     RECT  14.645 18 15.325 18.792 ;
     RECT  15.149 69.072 15.325 71.64 ;
     RECT  14.069 2.688 15.329 7.08 ;
     RECT  15.289 31.296 15.329 33.288 ;
     RECT  15.185 45.984 15.329 52.2 ;
     RECT  13.925 61.488 15.329 61.512 ;
     RECT  14.573 76.656 15.365 76.68 ;
     RECT  14.857 27.312 15.401 29.352 ;
     RECT  14.465 39.984 15.433 40.152 ;
     RECT  15.185 41.424 15.433 42.12 ;
     RECT  14.329 13.056 15.437 13.08 ;
     RECT  14.645 15.84 15.437 17.016 ;
     RECT  15.325 10.752 15.469 12.024 ;
     RECT  14.569 64.368 15.469 64.392 ;
     RECT  14.321 78.192 15.469 78.648 ;
     RECT  15.329 4.32 15.491 7.08 ;
     RECT  15.433 39.984 15.509 42.12 ;
     RECT  15.329 45.984 15.509 48.456 ;
     RECT  14.141 56.352 15.509 56.376 ;
     RECT  15.325 68.256 15.509 71.64 ;
     RECT  15.293 8.544 15.545 9 ;
     RECT  15.509 39.984 15.545 41.64 ;
     RECT  15.155 44.976 15.581 45 ;
     RECT  15.325 18 15.617 19.752 ;
     RECT  15.509 45.984 15.653 46.056 ;
     RECT  15.329 49.584 15.653 52.2 ;
     RECT  15.469 78.192 15.725 79.512 ;
     RECT  15.644 66.192 15.731 66.216 ;
     RECT  14.285 58.128 15.757 58.392 ;
     RECT  15.469 64.368 15.757 65.16 ;
     RECT  15.509 47.088 15.833 48.456 ;
     RECT  15.757 64.08 15.884 65.16 ;
     RECT  15.545 8.688 15.901 9 ;
     RECT  15.469 10.224 15.901 12.024 ;
     RECT  15.401 27.312 15.901 29.112 ;
     RECT  15.884 63.792 15.901 65.16 ;
     RECT  15.901 27.216 15.941 29.112 ;
     RECT  15.725 78.192 15.941 78.504 ;
     RECT  15.329 2.688 15.971 3.24 ;
     RECT  15.901 63.792 15.971 66.12 ;
     RECT  15.941 27.216 16.013 28.488 ;
     RECT  15.005 34.656 16.013 37.608 ;
     RECT  15.971 64.08 16.013 64.392 ;
     RECT  15.509 68.256 16.013 68.424 ;
     RECT  15.901 8.688 16.045 12.024 ;
     RECT  15.617 19.344 16.045 19.752 ;
     RECT  15.653 45.984 16.045 46.008 ;
     RECT  16.045 8.688 16.049 12.072 ;
     RECT  16.013 34.656 16.049 37.176 ;
     RECT  15.437 16.8 16.081 17.016 ;
     RECT  15.617 18 16.081 18.264 ;
     RECT  15.491 4.56 16.085 7.08 ;
     RECT  14.897 22.848 16.085 24.744 ;
     RECT  16.049 34.656 16.117 37.08 ;
     RECT  14.969 21.648 16.153 21.672 ;
     RECT  15.833 48.432 16.157 48.456 ;
     RECT  15.653 49.824 16.157 52.2 ;
     RECT  15.757 57.552 16.189 58.392 ;
     RECT  15.865 55.248 16.213 55.272 ;
     RECT  16.049 8.736 16.225 12.072 ;
     RECT  15.509 70.08 16.229 70.104 ;
     RECT  16.225 8.736 16.259 12.888 ;
     RECT  16.157 49.824 16.259 51.336 ;
     RECT  16.189 57.552 16.259 59.208 ;
     RECT  15.329 31.728 16.261 33.288 ;
     RECT  16.117 34.464 16.261 37.08 ;
     RECT  15.155 43.344 16.261 43.368 ;
     RECT  16.085 23.856 16.297 24.744 ;
     RECT  16.261 43.344 16.301 43.944 ;
     RECT  16.153 21.648 16.333 21.816 ;
     RECT  16.085 22.848 16.333 22.872 ;
     RECT  15.971 2.88 16.337 3.24 ;
     RECT  16.259 58.656 16.337 59.208 ;
     RECT  16.085 4.656 16.441 7.08 ;
     RECT  16.337 58.656 16.451 58.728 ;
     RECT  16.369 59.856 16.453 59.88 ;
     RECT  16.259 8.736 16.481 9.72 ;
     RECT  16.333 21.648 16.481 22.872 ;
     RECT  15.545 39.984 16.517 40.152 ;
     RECT  16.261 31.728 16.553 37.08 ;
     RECT  16.259 10.848 16.657 12.888 ;
     RECT  16.441 14.064 16.657 14.088 ;
     RECT  15.941 78.192 16.657 78.264 ;
     RECT  16.657 10.848 16.693 14.088 ;
     RECT  16.657 77.904 16.693 78.264 ;
     RECT  16.297 23.856 16.741 24.792 ;
     RECT  15.509 71.328 16.748 71.64 ;
     RECT  16.013 27.216 16.765 27.912 ;
     RECT  15.149 73.344 16.789 73.464 ;
     RECT  16.081 16.8 16.805 18.264 ;
     RECT  15.833 47.088 16.805 47.448 ;
     RECT  16.213 54.336 16.805 55.272 ;
     RECT  16.741 23.856 16.828 25.704 ;
     RECT  16.748 70.944 16.835 71.64 ;
     RECT  16.259 49.824 16.837 51.288 ;
     RECT  16.765 26.784 16.873 27.912 ;
     RECT  16.693 77.52 16.909 78.264 ;
     RECT  16.828 23.856 16.913 24.792 ;
     RECT  16.835 71.616 16.945 71.64 ;
     RECT  16.789 72.816 16.945 73.464 ;
     RECT  16.513 30 16.981 30.024 ;
     RECT  16.481 21.792 16.985 22.872 ;
     RECT  16.805 16.8 17.017 18.216 ;
     RECT  16.045 45.744 17.017 46.008 ;
     RECT  16.259 57.552 17.02 57.576 ;
     RECT  16.873 26.496 17.021 27.912 ;
     RECT  16.805 47.088 17.021 47.304 ;
     RECT  16.441 4.656 17.053 7.464 ;
     RECT  16.945 71.616 17.053 73.464 ;
     RECT  16.693 10.848 17.093 14.184 ;
     RECT  16.553 31.728 17.125 36.024 ;
     RECT  15.545 41.52 17.161 41.64 ;
     RECT  16.981 29.664 17.197 30.024 ;
     RECT  17.125 31.584 17.197 36.024 ;
     RECT  17.093 14.064 17.201 14.184 ;
     RECT  16.337 2.88 17.236 2.904 ;
     RECT  17.197 31.536 17.237 36.024 ;
     RECT  16.553 37.056 17.273 37.08 ;
     RECT  16.805 54.336 17.273 54.36 ;
     RECT  16.837 48.912 17.309 51.288 ;
     RECT  17.053 71.616 17.365 74.088 ;
     RECT  17.089 75.696 17.365 75.72 ;
     RECT  17.197 29.184 17.381 30.024 ;
     RECT  15.971 66.096 17.381 66.12 ;
     RECT  15.973 15.504 17.413 15.528 ;
     RECT  17.017 16.512 17.413 18.216 ;
     RECT  17.237 31.536 17.413 35.352 ;
     RECT  17.309 49.152 17.413 51.288 ;
     RECT  17.021 26.496 17.453 27.864 ;
     RECT  16.013 64.176 17.453 64.2 ;
     RECT  17.413 15.504 17.507 18.216 ;
     RECT  17.236 2.832 17.521 2.904 ;
     RECT  17.053 4.128 17.521 7.464 ;
     RECT  16.451 58.704 17.521 58.728 ;
     RECT  17.093 10.848 17.557 12.888 ;
     RECT  17.413 49.152 17.557 51.912 ;
     RECT  16.945 52.992 17.557 53.016 ;
     RECT  17.365 71.616 17.605 75.72 ;
     RECT  16.909 76.752 17.605 78.456 ;
     RECT  17.021 47.088 17.633 47.112 ;
     RECT  16.481 8.736 17.653 9.624 ;
     RECT  17.557 10.704 17.653 12.888 ;
     RECT  16.045 19.344 17.701 20.568 ;
     RECT  16.985 21.792 17.701 22.344 ;
     RECT  17.521 2.832 17.773 7.464 ;
     RECT  17.653 8.736 17.773 12.888 ;
     RECT  17.017 45.12 17.773 46.008 ;
     RECT  16.517 40.128 17.852 40.152 ;
     RECT  17.507 15.504 17.917 18.024 ;
     RECT  17.521 58.704 17.917 59.064 ;
     RECT  17.701 19.344 17.953 22.344 ;
     RECT  17.845 63.024 17.989 63.048 ;
     RECT  17.161 41.184 18.037 41.64 ;
     RECT  17.449 42.72 18.037 42.744 ;
     RECT  16.013 68.4 18.097 68.424 ;
     RECT  17.053 69.696 18.097 69.72 ;
     RECT  17.773 2.832 18.133 12.888 ;
     RECT  17.605 71.616 18.133 78.456 ;
     RECT  15.725 79.488 18.133 79.512 ;
     RECT  17.773 45.12 18.181 46.056 ;
     RECT  17.413 31.488 18.205 35.352 ;
     RECT  16.913 24.048 18.236 24.792 ;
     RECT  18.133 2.832 18.241 13.032 ;
     RECT  17.201 14.064 18.241 14.136 ;
     RECT  16.301 43.92 18.241 43.944 ;
     RECT  18.181 45.12 18.241 46.872 ;
     RECT  18.236 24.048 18.277 25.08 ;
     RECT  17.557 56.112 18.313 56.136 ;
     RECT  18.241 2.832 18.349 14.136 ;
     RECT  17.557 49.152 18.349 53.016 ;
     RECT  17.845 65.808 18.385 65.832 ;
     RECT  18.097 68.4 18.421 69.72 ;
     RECT  17.917 58.128 18.457 59.064 ;
     RECT  18.277 24.048 18.469 25.56 ;
     RECT  17.989 63.024 18.469 63.816 ;
     RECT  18.385 65.184 18.493 65.832 ;
     RECT  18.421 68.4 18.565 69.768 ;
     RECT  17.953 19.296 18.601 22.344 ;
     RECT  18.469 24.048 18.601 25.752 ;
     RECT  18.349 2.544 18.608 14.136 ;
     RECT  17.917 15.456 18.608 18.024 ;
     RECT  18.601 19.296 18.608 25.752 ;
     RECT  17.453 26.784 18.608 27.864 ;
     RECT  17.381 29.184 18.608 29.688 ;
     RECT  18.205 31.2 18.608 35.352 ;
     RECT  17.521 36.48 18.608 36.936 ;
     RECT  17.953 38.16 18.608 38.184 ;
     RECT  17.852 39.648 18.608 40.152 ;
     RECT  18.037 41.184 18.608 42.744 ;
     RECT  18.241 43.92 18.608 46.872 ;
     RECT  18.349 48.432 18.608 53.016 ;
     RECT  18.313 55.152 18.608 56.136 ;
     RECT  18.457 58.128 18.608 59.544 ;
     RECT  18.493 60.72 18.608 60.744 ;
     RECT  18.469 62.544 18.608 63.816 ;
     RECT  18.493 64.992 18.608 65.832 ;
     RECT  18.469 67.152 18.608 67.176 ;
     RECT  18.565 68.208 18.608 69.768 ;
     RECT  18.133 71.616 18.608 79.512 ;
     RECT  18.421 81.168 18.608 81.192 ;
     RECT  18.608 2.148 18.712 84.252 ;
     RECT  18.712 2.418 18.904 83.982 ;
     RECT  18.904 21.648 18.929 23.16 ;
     RECT  18.904 57.648 18.965 59.064 ;
     RECT  18.965 57.648 19.001 58.68 ;
     RECT  18.904 62.976 19.001 64.872 ;
     RECT  18.904 65.952 19.001 75.864 ;
     RECT  18.904 81.168 19.001 81.336 ;
     RECT  18.904 14.112 19.037 18.072 ;
     RECT  19.001 62.976 19.037 63.048 ;
     RECT  19.001 69.744 19.073 75.864 ;
     RECT  18.904 2.418 19.091 13.128 ;
     RECT  19.073 74.592 19.145 75.864 ;
     RECT  18.904 41.616 19.181 42.792 ;
     RECT  19.145 74.688 19.217 75.864 ;
     RECT  18.929 21.696 19.253 23.16 ;
     RECT  18.904 24.624 19.253 27.912 ;
     RECT  19.253 21.696 19.289 23.112 ;
     RECT  19.217 74.928 19.289 75.864 ;
     RECT  19.037 14.784 19.331 18.072 ;
     RECT  19.073 69.744 19.331 73.56 ;
     RECT  18.904 28.992 19.361 40.152 ;
     RECT  19.331 16.8 19.379 18.072 ;
     RECT  19.331 69.744 19.427 71.832 ;
     RECT  19.421 0.096 19.493 0.12 ;
     RECT  19.361 35.904 19.505 40.152 ;
     RECT  19.001 58.08 19.577 58.68 ;
     RECT  19.001 65.952 19.613 68.232 ;
     RECT  19.331 14.784 19.649 15.48 ;
     RECT  19.427 71.808 19.685 71.832 ;
     RECT  19.501 1.152 19.717 1.176 ;
     RECT  19.253 24.624 19.721 24.648 ;
     RECT  19.331 72.864 19.756 73.56 ;
     RECT  19.717 1.152 19.763 1.752 ;
     RECT  19.613 65.952 19.793 67.176 ;
     RECT  18.904 44.448 19.897 48.456 ;
     RECT  18.904 79.2 19.909 79.272 ;
     RECT  19.253 25.728 19.933 27.912 ;
     RECT  19.361 28.992 19.933 34.776 ;
     RECT  19.091 3.36 19.937 13.128 ;
     RECT  19.897 44.064 19.937 48.456 ;
     RECT  19.493 0.096 19.964 0.168 ;
     RECT  19.289 75.216 20.005 75.864 ;
     RECT  18.904 76.944 20.005 76.968 ;
     RECT  19.897 60.576 20.045 60.6 ;
     RECT  20.005 75.216 20.045 76.968 ;
     RECT  20.041 19.776 20.113 19.8 ;
     RECT  19.427 69.744 20.149 70.68 ;
     RECT  20.045 75.216 20.153 76.392 ;
     RECT  19.909 78.624 20.153 79.272 ;
     RECT  19.577 58.08 20.189 58.104 ;
     RECT  20.149 69.408 20.189 70.68 ;
     RECT  20.189 69.408 20.195 70.248 ;
     RECT  19.933 25.728 20.225 34.776 ;
     RECT  19.379 17.328 20.252 18.072 ;
     RECT  20.113 19.248 20.252 19.8 ;
     RECT  19.649 14.784 20.257 14.808 ;
     RECT  19.037 62.976 20.257 63 ;
     RECT  18.904 49.824 20.261 54.696 ;
     RECT  20.257 14.4 20.297 14.808 ;
     RECT  19.505 35.904 20.297 36.408 ;
     RECT  19.969 21.264 20.3 21.288 ;
     RECT  19.505 37.488 20.329 40.152 ;
     RECT  20.252 17.328 20.339 19.8 ;
     RECT  19.937 45.168 20.341 48.456 ;
     RECT  19.937 44.064 20.365 44.088 ;
     RECT  20.339 17.328 20.369 17.736 ;
     RECT  20.3 20.832 20.387 21.288 ;
     RECT  20.369 17.328 20.405 17.688 ;
     RECT  20.225 25.728 20.473 31.896 ;
     RECT  20.225 32.928 20.473 34.776 ;
     RECT  20.297 35.904 20.473 35.928 ;
     RECT  20.257 62.592 20.473 63 ;
     RECT  20.405 17.616 20.477 17.688 ;
     RECT  20.473 25.44 20.477 31.896 ;
     RECT  19.181 41.616 20.492 42.648 ;
     RECT  20.341 45.168 20.531 48.648 ;
     RECT  20.492 41.616 20.533 42.696 ;
     RECT  20.365 44.016 20.533 44.088 ;
     RECT  19.001 64.272 20.533 64.872 ;
     RECT  19.793 65.952 20.533 65.976 ;
     RECT  20.153 75.216 20.549 75.24 ;
     RECT  20.153 79.248 20.549 79.272 ;
     RECT  19.937 3.36 20.585 12.888 ;
     RECT  20.477 31.728 20.585 31.896 ;
     RECT  20.473 32.928 20.585 35.928 ;
     RECT  20.153 76.368 20.585 76.392 ;
     RECT  20.387 21.264 20.617 21.288 ;
     RECT  19.289 22.608 20.617 23.112 ;
     RECT  20.195 69.408 20.621 70.152 ;
     RECT  20.477 25.44 20.657 30.744 ;
     RECT  20.617 21.264 20.693 23.112 ;
     RECT  19.964 0.096 20.737 0.6 ;
     RECT  19.756 72.864 20.773 73.464 ;
     RECT  20.657 25.44 20.797 25.992 ;
     RECT  20.473 62.592 20.833 63.24 ;
     RECT  19.613 68.208 20.837 68.232 ;
     RECT  20.533 64.272 20.869 65.976 ;
     RECT  19.793 67.152 20.869 67.176 ;
     RECT  19.763 1.728 20.905 1.752 ;
     RECT  20.531 46.656 20.909 48.648 ;
     RECT  20.585 35.328 20.945 35.928 ;
     RECT  20.533 41.616 20.945 44.088 ;
     RECT  20.621 69.504 20.963 70.152 ;
     RECT  20.329 37.488 20.981 40.488 ;
     RECT  20.905 1.728 21.013 1.992 ;
     RECT  20.585 3.36 21.013 12.264 ;
     RECT  20.945 43.344 21.013 44.088 ;
     RECT  20.531 45.168 21.013 45.624 ;
     RECT  20.657 26.976 21.017 30.744 ;
     RECT  21.013 1.728 21.107 12.264 ;
     RECT  20.909 46.656 21.107 48.408 ;
     RECT  20.869 64.272 21.107 67.176 ;
     RECT  20.693 21.648 21.121 23.112 ;
     RECT  20.773 72.672 21.121 73.464 ;
     RECT  21.107 2.784 21.161 12.264 ;
     RECT  21.077 15.408 21.161 15.432 ;
     RECT  20.833 61.776 21.193 63.24 ;
     RECT  21.107 64.272 21.193 66.696 ;
     RECT  21.161 2.784 21.233 11.928 ;
     RECT  20.585 31.872 21.233 31.896 ;
     RECT  20.261 49.824 21.269 54.12 ;
     RECT  20.797 25.056 21.337 25.992 ;
     RECT  21.233 4.128 21.341 11.928 ;
     RECT  21.301 57.024 21.349 57.048 ;
     RECT  21.121 71.856 21.377 73.464 ;
     RECT  21.341 4.128 21.449 10.392 ;
     RECT  21.193 61.776 21.449 66.696 ;
     RECT  20.339 19.248 21.481 19.8 ;
     RECT  20.981 37.488 21.481 40.104 ;
     RECT  21.107 46.752 21.485 48.408 ;
     RECT  19.969 55.92 21.553 55.944 ;
     RECT  21.481 37.008 21.557 40.104 ;
     RECT  20.963 69.504 21.589 70.056 ;
     RECT  21.449 64.032 21.665 66.696 ;
     RECT  21.013 43.344 21.683 45.624 ;
     RECT  21.121 21.648 21.737 23.448 ;
     RECT  21.017 28.944 21.773 30.744 ;
     RECT  21.589 69.264 21.788 70.056 ;
     RECT  21.337 24.48 21.809 25.992 ;
     RECT  20.477 17.664 21.841 17.688 ;
     RECT  21.788 68.352 21.875 70.056 ;
     RECT  21.485 46.752 21.881 46.776 ;
     RECT  21.107 1.728 21.889 1.8 ;
     RECT  21.665 64.032 21.917 64.2 ;
     RECT  20.585 32.928 21.953 33.96 ;
     RECT  21.269 50.544 21.985 54.12 ;
     RECT  21.553 55.248 21.985 55.944 ;
     RECT  21.449 61.776 21.985 62.76 ;
     RECT  20.297 14.4 21.989 14.424 ;
     RECT  20.945 41.616 21.989 41.688 ;
     RECT  21.697 78.672 22.021 79.08 ;
     RECT  21.157 60.384 22.061 60.408 ;
     RECT  20.945 35.328 22.129 35.592 ;
     RECT  21.985 50.544 22.133 55.944 ;
     RECT  21.841 17.664 22.165 18.264 ;
     RECT  21.481 19.248 22.165 19.992 ;
     RECT  22.133 50.544 22.169 55.896 ;
     RECT  21.985 61.584 22.169 62.76 ;
     RECT  21.809 24.672 22.205 25.992 ;
     RECT  21.683 43.344 22.237 45.576 ;
     RECT  22.237 43.248 22.273 45.576 ;
     RECT  21.485 48.24 22.309 48.408 ;
     RECT  21.557 37.008 22.313 38.04 ;
     RECT  21.665 65.232 22.313 66.696 ;
     RECT  22.021 78.624 22.313 79.08 ;
     RECT  22.169 50.544 22.349 53.256 ;
     RECT  22.165 17.616 22.453 19.992 ;
     RECT  22.237 21.168 22.453 21.192 ;
     RECT  22.129 35.328 22.457 35.976 ;
     RECT  20.941 16.512 22.493 16.536 ;
     RECT  22.169 61.584 22.597 62.664 ;
     RECT  22.453 17.616 22.637 21.192 ;
     RECT  21.377 71.856 22.637 72.696 ;
     RECT  21.017 26.976 22.669 27.912 ;
     RECT  22.417 41.232 22.669 41.256 ;
     RECT  22.309 48.24 22.669 49.272 ;
     RECT  21.349 57.024 22.693 57.336 ;
     RECT  22.237 58.704 22.693 58.728 ;
     RECT  22.169 54.672 22.739 55.896 ;
     RECT  22.693 57.024 22.739 58.728 ;
     RECT  22.669 47.856 22.777 49.272 ;
     RECT  22.349 50.544 22.777 52.056 ;
     RECT  22.777 47.856 22.781 52.056 ;
     RECT  22.313 78.672 22.781 79.08 ;
     RECT  21.953 32.928 22.813 33.912 ;
     RECT  22.313 37.104 22.813 38.04 ;
     RECT  20.737 0.096 22.849 0.168 ;
     RECT  22.813 15.84 22.849 15.864 ;
     RECT  22.813 37.104 22.849 38.232 ;
     RECT  21.557 39.456 22.849 40.104 ;
     RECT  22.849 0.096 22.853 0.216 ;
     RECT  21.449 4.512 22.853 10.392 ;
     RECT  21.341 11.376 22.921 11.928 ;
     RECT  22.777 13.104 22.921 13.128 ;
     RECT  22.669 26.832 22.957 27.912 ;
     RECT  22.733 46.656 22.957 46.68 ;
     RECT  22.637 19.92 22.961 21.192 ;
     RECT  22.813 32.544 22.961 33.912 ;
     RECT  22.313 65.232 22.961 66.12 ;
     RECT  22.849 37.104 22.997 40.104 ;
     RECT  22.961 32.928 23.027 33.912 ;
     RECT  22.957 26.832 23.029 28.248 ;
     RECT  21.773 29.232 23.029 30.744 ;
     RECT  22.273 42.96 23.029 45.576 ;
     RECT  22.739 57.024 23.033 58.68 ;
     RECT  22.957 46.656 23.041 46.776 ;
     RECT  22.921 11.376 23.101 13.128 ;
     RECT  23.029 14.256 23.101 14.28 ;
     RECT  21.875 68.64 23.137 70.056 ;
     RECT  23.029 42.72 23.209 45.576 ;
     RECT  22.781 47.856 23.209 51.672 ;
     RECT  22.349 53.232 23.245 53.256 ;
     RECT  23.029 26.832 23.281 30.744 ;
     RECT  21.917 64.176 23.281 64.2 ;
     RECT  23.027 33.024 23.317 33.912 ;
     RECT  22.561 67.248 23.317 67.368 ;
     RECT  23.137 68.4 23.317 70.056 ;
     RECT  22.853 0.192 23.353 0.216 ;
     RECT  21.889 1.728 23.353 1.752 ;
     RECT  21.233 2.784 23.353 2.808 ;
     RECT  22.205 24.672 23.353 25.752 ;
     RECT  22.961 20.112 23.425 21.192 ;
     RECT  21.737 22.608 23.425 23.448 ;
     RECT  22.597 61.536 23.425 62.664 ;
     RECT  22.637 17.616 23.497 18.696 ;
     RECT  22.637 72.144 23.605 72.696 ;
     RECT  22.739 55.296 23.641 55.896 ;
     RECT  23.033 57.024 23.641 58.104 ;
     RECT  22.457 35.856 23.677 35.88 ;
     RECT  22.997 37.104 23.677 39.864 ;
     RECT  23.353 1.728 23.701 2.808 ;
     RECT  22.853 4.992 23.713 10.392 ;
     RECT  23.101 11.376 23.713 14.28 ;
     RECT  23.641 55.296 23.713 58.104 ;
     RECT  23.353 24.48 23.749 25.752 ;
     RECT  23.281 26.832 23.749 30.936 ;
     RECT  22.669 41.184 23.749 41.256 ;
     RECT  22.849 15.264 23.785 15.864 ;
     RECT  23.497 17.184 23.785 18.696 ;
     RECT  23.425 61.536 23.845 63 ;
     RECT  23.317 67.248 23.852 70.056 ;
     RECT  23.317 33.024 23.857 34.68 ;
     RECT  22.961 66.096 23.893 66.12 ;
     RECT  23.852 67.248 23.893 70.728 ;
     RECT  23.701 1.728 24.008 2.856 ;
     RECT  23.101 3.888 24.008 4.008 ;
     RECT  23.713 4.992 24.008 14.28 ;
     RECT  23.785 15.264 24.008 18.696 ;
     RECT  23.425 20.112 24.008 23.448 ;
     RECT  23.749 24.48 24.008 30.936 ;
     RECT  23.749 31.92 24.008 31.944 ;
     RECT  23.857 33.024 24.008 34.728 ;
     RECT  23.677 35.856 24.008 39.864 ;
     RECT  23.749 40.944 24.008 41.256 ;
     RECT  23.209 42.72 24.008 46.296 ;
     RECT  23.209 47.328 24.008 51.672 ;
     RECT  23.245 53.232 24.008 54.168 ;
     RECT  23.713 55.152 24.008 58.104 ;
     RECT  23.713 59.184 24.008 59.208 ;
     RECT  23.845 61.44 24.008 63 ;
     RECT  23.281 64.176 24.008 64.968 ;
     RECT  23.893 66.096 24.008 70.728 ;
     RECT  23.605 71.904 24.008 72.696 ;
     RECT  22.781 78.672 24.008 78.744 ;
     RECT  19.001 81.312 24.008 81.336 ;
     RECT  24.008 1.728 24.112 84.252 ;
     RECT  23.353 0.192 24.229 0.6 ;
     RECT  24.112 1.728 24.304 83.982 ;
     RECT  24.304 19.248 24.365 22.056 ;
     RECT  24.304 30.576 24.365 38.76 ;
     RECT  24.229 0.144 24.373 0.6 ;
     RECT  24.304 1.728 24.373 14.472 ;
     RECT  24.304 73.92 24.419 75.144 ;
     RECT  24.304 23.04 24.437 23.064 ;
     RECT  24.304 78.624 24.47 78.696 ;
     RECT  24.304 42.72 24.473 43.848 ;
     RECT  24.304 61.44 24.473 72.696 ;
     RECT  24.373 0.144 24.515 14.472 ;
     RECT  24.473 69.504 24.515 72.696 ;
     RECT  24.419 74.688 24.545 75.144 ;
     RECT  24.515 0.144 24.589 0.6 ;
     RECT  24.589 0.144 24.605 0.552 ;
     RECT  24.473 61.44 24.689 68.52 ;
     RECT  24.304 44.88 24.707 46.776 ;
     RECT  24.515 1.728 24.725 14.472 ;
     RECT  24.304 24.72 24.797 27.96 ;
     RECT  24.304 48.24 24.797 49.56 ;
     RECT  24.689 61.488 24.803 68.52 ;
     RECT  24.304 50.592 24.851 59.736 ;
     RECT  24.304 39.888 24.905 41.592 ;
     RECT  24.304 15.552 24.995 18.12 ;
     RECT  24.803 61.488 25.013 66.792 ;
     RECT  24.515 69.504 25.013 70.728 ;
     RECT  24.995 15.552 25.049 17.448 ;
     RECT  24.473 42.816 25.085 43.848 ;
     RECT  24.905 39.888 25.157 41.256 ;
     RECT  25.013 61.488 25.157 66.744 ;
     RECT  24.605 0.096 25.193 0.552 ;
     RECT  25.157 39.888 25.193 40.968 ;
     RECT  24.725 3.312 25.235 14.472 ;
     RECT  24.365 19.92 25.297 22.056 ;
     RECT  24.304 28.944 25.297 29.544 ;
     RECT  24.365 30.576 25.297 37.656 ;
     RECT  25.049 15.552 25.301 15.576 ;
     RECT  24.851 50.592 25.409 59.208 ;
     RECT  24.797 48.336 25.441 49.56 ;
     RECT  25.409 50.592 25.441 58.152 ;
     RECT  24.803 67.824 25.441 68.52 ;
     RECT  25.297 19.92 25.477 22.584 ;
     RECT  25.235 3.84 25.513 14.472 ;
     RECT  24.545 75.12 25.513 75.144 ;
     RECT  25.513 74.304 25.573 75.144 ;
     RECT  24.304 82.032 25.585 82.056 ;
     RECT  25.441 48.336 25.589 58.152 ;
     RECT  24.797 25.104 25.625 27.96 ;
     RECT  25.625 25.248 25.661 27.96 ;
     RECT  24.515 71.76 25.669 72.696 ;
     RECT  25.585 82.032 25.669 82.68 ;
     RECT  25.661 27.168 25.697 27.96 ;
     RECT  25.297 28.944 25.697 37.656 ;
     RECT  24.365 38.736 25.697 38.76 ;
     RECT  25.157 61.488 25.697 63 ;
     RECT  25.697 61.488 25.715 62.76 ;
     RECT  24.47 78.624 25.729 78.648 ;
     RECT  25.049 16.56 25.733 17.448 ;
     RECT  25.477 19.92 25.733 22.824 ;
     RECT  25.697 27.168 25.733 27.336 ;
     RECT  25.669 80.928 25.765 82.68 ;
     RECT  25.733 19.92 25.769 22.584 ;
     RECT  25.769 19.92 25.801 21.672 ;
     RECT  25.589 50.832 25.805 58.152 ;
     RECT  25.157 64.272 25.805 66.744 ;
     RECT  25.193 0.48 25.811 0.552 ;
     RECT  25.724 23.904 25.811 23.928 ;
     RECT  25.765 80.928 25.811 82.968 ;
     RECT  25.013 70.128 25.837 70.728 ;
     RECT  25.669 71.76 25.837 73.272 ;
     RECT  25.715 62.016 25.841 62.76 ;
     RECT  25.805 64.272 25.877 66.456 ;
     RECT  25.811 0.48 25.907 0.504 ;
     RECT  25.811 82.944 25.913 82.968 ;
     RECT  25.697 29.04 25.949 37.656 ;
     RECT  25.729 78.576 25.957 78.648 ;
     RECT  25.621 79.776 25.957 79.8 ;
     RECT  24.707 45.12 25.973 46.776 ;
     RECT  25.409 59.184 25.985 59.208 ;
     RECT  25.973 45.12 26.017 47.352 ;
     RECT  25.589 48.336 26.017 49.368 ;
     RECT  25.441 67.824 26.017 68.952 ;
     RECT  25.837 70.128 26.017 73.272 ;
     RECT  25.585 77.424 26.017 77.448 ;
     RECT  26.017 45.12 26.057 49.368 ;
     RECT  26.057 45.12 26.093 46.776 ;
     RECT  25.193 40.128 26.125 40.968 ;
     RECT  25.805 54.384 26.129 58.152 ;
     RECT  26.057 47.856 26.147 49.368 ;
     RECT  26.017 67.824 26.165 73.272 ;
     RECT  25.733 16.56 26.188 17.304 ;
     RECT  26.147 47.856 26.188 49.272 ;
     RECT  26.017 77.376 26.197 77.448 ;
     RECT  25.957 78.576 26.197 79.8 ;
     RECT  25.573 74.256 26.204 75.144 ;
     RECT  26.165 67.824 26.233 69.528 ;
     RECT  26.204 74.256 26.245 75.48 ;
     RECT  26.197 76.848 26.245 79.8 ;
     RECT  25.085 42.816 26.269 43.464 ;
     RECT  26.165 70.56 26.273 73.272 ;
     RECT  26.129 56.112 26.353 58.152 ;
     RECT  26.353 56.112 26.381 57.24 ;
     RECT  26.381 56.208 26.387 57.24 ;
     RECT  25.801 19.344 26.413 21.672 ;
     RECT  26.188 48.336 26.417 49.272 ;
     RECT  26.245 74.256 26.449 79.8 ;
     RECT  25.811 80.928 26.449 80.952 ;
     RECT  26.197 63.792 26.453 63.816 ;
     RECT  26.129 54.384 26.489 54.408 ;
     RECT  26.449 74.256 26.489 80.952 ;
     RECT  26.489 74.256 26.525 80.424 ;
     RECT  25.513 3.84 26.561 15.048 ;
     RECT  26.525 76.032 26.605 80.424 ;
     RECT  26.561 3.84 26.737 11.4 ;
     RECT  25.949 29.04 26.737 30.696 ;
     RECT  26.561 12.528 26.773 15.048 ;
     RECT  25.733 27.216 26.773 27.336 ;
     RECT  26.605 76.032 26.849 79.992 ;
     RECT  25.841 62.688 26.885 62.712 ;
     RECT  25.877 64.944 26.917 66.456 ;
     RECT  26.273 70.656 26.917 73.272 ;
     RECT  26.525 74.256 26.917 74.76 ;
     RECT  25.949 31.872 26.921 37.656 ;
     RECT  25.661 25.248 26.957 25.512 ;
     RECT  25.805 50.832 26.957 53.256 ;
     RECT  26.917 64.416 27.011 66.456 ;
     RECT  26.957 52.416 27.101 53.256 ;
     RECT  26.921 34.752 27.107 37.656 ;
     RECT  26.125 40.128 27.169 41.016 ;
     RECT  27.011 64.944 27.173 66.456 ;
     RECT  27.169 39.792 27.245 41.016 ;
     RECT  27.173 65.856 27.253 66.456 ;
     RECT  26.233 67.44 27.253 69.528 ;
     RECT  27.253 65.856 27.26 69.528 ;
     RECT  26.917 70.656 27.26 74.76 ;
     RECT  27.245 39.792 27.277 40.584 ;
     RECT  24.725 1.728 27.281 1.848 ;
     RECT  27.26 65.856 27.299 74.76 ;
     RECT  26.269 42.816 27.313 43.608 ;
     RECT  26.093 45.408 27.317 46.776 ;
     RECT  26.417 48.336 27.347 48.456 ;
     RECT  27.299 65.856 27.347 67.8 ;
     RECT  27.299 68.784 27.347 74.76 ;
     RECT  27.313 2.256 27.349 2.28 ;
     RECT  26.737 3.456 27.349 11.4 ;
     RECT  26.849 76.032 27.353 78.696 ;
     RECT  26.387 56.208 27.356 56.52 ;
     RECT  27.347 48.336 27.389 48.36 ;
     RECT  27.356 56.112 27.397 56.52 ;
     RECT  27.277 39.504 27.404 40.584 ;
     RECT  26.924 59.088 27.421 59.112 ;
     RECT  27.397 56.112 27.443 57.048 ;
     RECT  27.353 76.032 27.443 78.216 ;
     RECT  27.404 39.408 27.445 40.584 ;
     RECT  27.317 45.408 27.457 46.248 ;
     RECT  27.421 58.656 27.457 59.112 ;
     RECT  26.188 16.56 27.461 17.256 ;
     RECT  26.773 26.832 27.5 27.336 ;
     RECT  27.443 76.032 27.529 76.632 ;
     RECT  27.457 58.656 27.539 59.256 ;
     RECT  27.5 26.736 27.587 27.336 ;
     RECT  26.413 19.104 27.605 21.672 ;
     RECT  27.347 68.784 27.641 73.32 ;
     RECT  27.349 2.256 27.673 11.4 ;
     RECT  26.773 12.528 27.673 15.48 ;
     RECT  27.347 66.72 27.677 67.8 ;
     RECT  27.673 2.256 27.713 15.48 ;
     RECT  27.641 68.784 27.731 73.272 ;
     RECT  26.773 60.528 27.749 60.552 ;
     RECT  27.443 78.192 27.749 78.216 ;
     RECT  27.713 3.024 27.817 15.48 ;
     RECT  27.461 16.56 27.817 17.064 ;
     RECT  26.921 31.872 27.821 33.144 ;
     RECT  27.821 31.872 27.857 32.328 ;
     RECT  27.313 41.616 27.857 43.608 ;
     RECT  27.313 81.504 27.884 81.528 ;
     RECT  27.731 71.088 27.923 73.272 ;
     RECT  27.443 56.256 27.925 57.048 ;
     RECT  26.737 28.416 27.965 30.696 ;
     RECT  27.731 68.784 27.965 70.104 ;
     RECT  27.884 81.504 27.971 82.2 ;
     RECT  27.457 44.88 27.98 46.248 ;
     RECT  26.957 50.832 27.997 50.856 ;
     RECT  27.965 30.336 28.001 30.36 ;
     RECT  27.925 56.256 28.012 57.576 ;
     RECT  27.857 41.616 28.06 43.32 ;
     RECT  27.98 44.592 28.067 46.248 ;
     RECT  27.817 3.024 28.073 17.064 ;
     RECT  28.012 56.256 28.073 57.048 ;
     RECT  27.529 75.84 28.073 76.632 ;
     RECT  27.445 38.736 28.145 40.584 ;
     RECT  28.06 41.952 28.145 43.32 ;
     RECT  27.923 71.808 28.217 73.272 ;
     RECT  27.605 19.344 28.253 21.672 ;
     RECT  27.587 26.832 28.285 27.336 ;
     RECT  27.965 28.416 28.285 29.352 ;
     RECT  27.637 83.28 28.321 83.304 ;
     RECT  28.073 5.616 28.325 17.064 ;
     RECT  27.347 74.64 28.325 74.76 ;
     RECT  28.321 83.184 28.361 83.304 ;
     RECT  27.107 34.752 28.429 35.736 ;
     RECT  26.849 79.68 28.501 79.992 ;
     RECT  27.971 81.504 28.501 81.528 ;
     RECT  26.957 25.248 28.645 25.32 ;
     RECT  27.677 66.72 28.645 67.464 ;
     RECT  27.965 68.784 28.645 68.808 ;
     RECT  28.285 23.952 28.753 23.976 ;
     RECT  28.645 25.056 28.753 25.32 ;
     RECT  28.217 72.144 28.753 73.272 ;
     RECT  27.817 18.144 28.789 18.168 ;
     RECT  28.253 19.344 28.789 21.192 ;
     RECT  27.539 59.232 28.861 59.256 ;
     RECT  28.285 26.832 28.969 29.352 ;
     RECT  27.997 50.832 28.969 51.384 ;
     RECT  28.753 23.952 28.991 25.32 ;
     RECT  28.465 22.224 29.041 22.392 ;
     RECT  28.067 45.552 29.077 46.248 ;
     RECT  29.005 47.424 29.077 47.448 ;
     RECT  28.069 62.16 29.077 62.184 ;
     RECT  29.077 45.552 29.149 47.448 ;
     RECT  28.073 3.024 29.173 4.536 ;
     RECT  28.325 5.616 29.173 16.968 ;
     RECT  28.753 72.144 29.185 73.8 ;
     RECT  28.145 41.952 29.249 42.84 ;
     RECT  27.857 32.016 29.257 32.328 ;
     RECT  29.149 70.656 29.257 70.68 ;
     RECT  27.107 36.96 29.269 37.656 ;
     RECT  28.145 38.736 29.269 39.816 ;
     RECT  28.429 34.464 29.293 35.736 ;
     RECT  29.269 36.96 29.293 39.816 ;
     RECT  29.257 70.368 29.401 70.68 ;
     RECT  29.185 71.904 29.401 73.8 ;
     RECT  29.173 3.024 29.408 16.968 ;
     RECT  28.789 18.144 29.408 21.192 ;
     RECT  29.041 22.224 29.408 22.872 ;
     RECT  28.991 23.904 29.408 25.32 ;
     RECT  28.969 26.832 29.408 30.12 ;
     RECT  29.257 32.016 29.408 32.52 ;
     RECT  29.293 34.464 29.408 39.816 ;
     RECT  29.249 41.568 29.408 42.84 ;
     RECT  29.149 45.168 29.408 47.448 ;
     RECT  28.465 48.96 29.408 48.984 ;
     RECT  28.969 50.112 29.408 51.384 ;
     RECT  27.101 52.992 29.408 53.256 ;
     RECT  28.969 55.248 29.408 55.272 ;
     RECT  28.073 56.256 29.408 56.28 ;
     RECT  28.861 59.04 29.408 59.256 ;
     RECT  29.077 61.2 29.408 62.184 ;
     RECT  28.465 65.232 29.408 65.256 ;
     RECT  28.645 66.72 29.408 68.808 ;
     RECT  29.401 70.368 29.408 73.8 ;
     RECT  28.073 75.84 29.408 75.864 ;
     RECT  29.041 78.096 29.408 78.12 ;
     RECT  28.501 79.68 29.408 81.528 ;
     RECT  28.361 83.184 29.408 83.208 ;
     RECT  29.408 2.148 29.512 84.252 ;
     RECT  29.512 2.418 29.704 83.982 ;
     RECT  29.704 69.936 29.765 74.712 ;
     RECT  29.704 56.256 29.801 57.048 ;
     RECT  29.704 2.784 29.837 3.912 ;
     RECT  29.704 23.904 29.873 27.384 ;
     RECT  29.704 42.24 29.873 42.84 ;
     RECT  29.704 79.44 29.873 80.664 ;
     RECT  29.704 34.896 29.909 40.488 ;
     RECT  29.704 43.92 29.909 45.192 ;
     RECT  29.704 46.32 29.909 47.736 ;
     RECT  29.704 66.336 29.909 67.032 ;
     RECT  29.704 48.912 29.939 55.272 ;
     RECT  29.704 76.368 29.981 78.12 ;
     RECT  29.704 64.368 30.017 65.256 ;
     RECT  29.909 34.896 30.053 39.288 ;
     RECT  29.909 43.92 30.089 45 ;
     RECT  29.765 69.936 30.089 74.664 ;
     RECT  29.873 23.904 30.125 25.56 ;
     RECT  29.981 76.368 30.125 77.544 ;
     RECT  30.017 65.232 30.161 65.256 ;
     RECT  29.704 61.2 30.197 61.896 ;
     RECT  30.053 34.896 30.269 38.328 ;
     RECT  29.939 48.912 30.275 53.112 ;
     RECT  30.089 71.808 30.305 74.664 ;
     RECT  29.704 5.136 30.341 7.656 ;
     RECT  30.089 69.936 30.377 70.824 ;
     RECT  30.305 71.808 30.413 74.472 ;
     RECT  30.341 5.136 30.557 7.224 ;
     RECT  29.704 82.128 30.557 82.728 ;
     RECT  29.837 2.784 30.593 3.48 ;
     RECT  30.413 72.144 30.593 74.472 ;
     RECT  29.704 15.552 30.665 22.776 ;
     RECT  30.665 21.456 30.701 22.776 ;
     RECT  30.557 5.136 30.737 7.176 ;
     RECT  29.704 28.704 30.755 33.72 ;
     RECT  29.704 9.264 30.769 14.472 ;
     RECT  30.665 15.552 30.769 18.408 ;
     RECT  29.704 58.752 30.769 59.88 ;
     RECT  29.909 66.336 30.769 66.36 ;
     RECT  29.873 79.44 30.769 79.752 ;
     RECT  30.755 28.704 30.773 33.624 ;
     RECT  30.269 34.896 30.773 37.992 ;
     RECT  30.197 61.44 30.773 61.896 ;
     RECT  30.125 76.368 30.773 77.352 ;
     RECT  29.801 57.024 30.805 57.048 ;
     RECT  30.557 82.704 30.809 82.728 ;
     RECT  29.873 26.688 30.812 27.384 ;
     RECT  29.909 46.8 30.841 47.736 ;
     RECT  30.275 48.912 30.841 52.728 ;
     RECT  30.701 21.504 30.845 22.776 ;
     RECT  30.769 9.264 30.851 18.408 ;
     RECT  30.845 21.792 30.877 22.776 ;
     RECT  29.909 40.464 30.877 40.488 ;
     RECT  30.773 29.088 30.881 33.624 ;
     RECT  30.805 56.544 30.913 57.048 ;
     RECT  30.769 58.176 30.913 59.88 ;
     RECT  30.877 39.888 30.917 40.488 ;
     RECT  30.841 46.8 30.917 52.728 ;
     RECT  30.917 39.888 31.021 39.912 ;
     RECT  30.125 24.144 31.025 25.56 ;
     RECT  30.913 56.544 31.093 59.88 ;
     RECT  30.851 13.056 31.097 18.408 ;
     RECT  31.057 80.784 31.129 80.808 ;
     RECT  31.021 39.024 31.133 39.912 ;
     RECT  30.877 21.792 31.165 22.92 ;
     RECT  31.097 18.384 31.169 18.408 ;
     RECT  30.769 66.192 31.201 66.36 ;
     RECT  29.939 54.672 31.205 55.272 ;
     RECT  30.089 44.448 31.237 45 ;
     RECT  30.917 46.8 31.237 49.32 ;
     RECT  31.093 56.304 31.237 59.88 ;
     RECT  30.733 63.696 31.237 64.2 ;
     RECT  31.201 65.808 31.237 66.36 ;
     RECT  29.704 68.4 31.273 68.808 ;
     RECT  30.773 76.368 31.277 76.584 ;
     RECT  31.237 63.696 31.283 66.36 ;
     RECT  30.773 36.48 31.285 37.992 ;
     RECT  31.025 25.056 31.309 25.56 ;
     RECT  30.812 26.688 31.309 28.104 ;
     RECT  30.769 79.344 31.309 79.752 ;
     RECT  31.273 68.4 31.313 68.904 ;
     RECT  31.283 65.04 31.321 66.36 ;
     RECT  31.283 63.696 31.381 63.72 ;
     RECT  31.321 65.712 31.381 66.36 ;
     RECT  30.851 9.264 31.417 11.976 ;
     RECT  30.593 73.776 31.417 74.472 ;
     RECT  30.805 4.512 31.421 4.536 ;
     RECT  31.097 13.056 31.421 17.352 ;
     RECT  30.665 19.392 31.421 20.424 ;
     RECT  31.237 44.448 31.457 49.32 ;
     RECT  31.237 56.304 31.457 60.456 ;
     RECT  30.377 69.936 31.457 69.96 ;
     RECT  31.457 45.456 31.493 49.32 ;
     RECT  30.917 50.4 31.525 52.728 ;
     RECT  31.309 25.056 31.529 28.104 ;
     RECT  31.205 54.672 31.561 55.128 ;
     RECT  31.529 25.536 31.601 28.104 ;
     RECT  30.593 72.144 31.601 72.696 ;
     RECT  31.457 57.024 31.619 60.456 ;
     RECT  30.737 5.904 31.741 7.176 ;
     RECT  31.129 80.784 31.772 81.336 ;
     RECT  31.093 82.752 31.772 82.776 ;
     RECT  31.381 62.736 31.781 63.72 ;
     RECT  30.593 2.784 31.813 3.384 ;
     RECT  31.741 5.904 31.849 7.608 ;
     RECT  31.421 19.392 31.849 20.376 ;
     RECT  31.277 76.56 31.849 76.584 ;
     RECT  31.309 78.672 31.849 79.752 ;
     RECT  31.772 80.784 31.859 82.776 ;
     RECT  31.813 2.784 31.861 4.008 ;
     RECT  31.417 9.12 31.861 11.976 ;
     RECT  31.861 2.256 31.917 4.008 ;
     RECT  31.493 46.752 31.921 49.32 ;
     RECT  31.525 50.4 31.921 53.016 ;
     RECT  31.561 54.048 31.921 55.128 ;
     RECT  31.417 73.776 31.921 74.664 ;
     RECT  31.859 82.752 31.925 82.776 ;
     RECT  30.773 34.896 31.957 35.448 ;
     RECT  31.285 36.48 31.957 38.76 ;
     RECT  29.873 42.816 31.957 42.84 ;
     RECT  31.917 2.256 31.961 2.28 ;
     RECT  30.881 29.088 31.961 33.528 ;
     RECT  31.849 76.56 31.961 76.92 ;
     RECT  31.849 5.76 31.993 7.608 ;
     RECT  31.861 8.688 31.993 11.976 ;
     RECT  31.961 33.504 31.993 33.528 ;
     RECT  31.957 34.896 31.993 38.76 ;
     RECT  31.993 5.76 31.997 11.976 ;
     RECT  31.849 78.528 31.997 79.752 ;
     RECT  31.619 60.432 32.033 60.456 ;
     RECT  31.921 46.752 32.069 55.128 ;
     RECT  31.961 76.896 32.101 76.92 ;
     RECT  31.457 44.448 32.141 44.472 ;
     RECT  32.069 47.856 32.141 55.128 ;
     RECT  32.101 76.896 32.141 77.496 ;
     RECT  31.997 5.76 32.173 8.184 ;
     RECT  31.993 33.504 32.173 38.76 ;
     RECT  31.313 68.784 32.177 68.904 ;
     RECT  31.165 21.792 32.281 23.016 ;
     RECT  31.601 25.824 32.317 28.104 ;
     RECT  31.961 29.088 32.317 32.376 ;
     RECT  32.141 77.472 32.317 77.496 ;
     RECT  32.141 54.528 32.429 55.128 ;
     RECT  31.957 42.048 32.437 42.84 ;
     RECT  31.421 13.056 32.461 17.16 ;
     RECT  31.493 45.456 32.465 45.768 ;
     RECT  32.141 47.856 32.465 53.352 ;
     RECT  32.173 33.504 32.483 38.904 ;
     RECT  32.437 41.52 32.483 42.84 ;
     RECT  32.461 0.624 32.485 0.648 ;
     RECT  32.483 33.504 32.537 36.84 ;
     RECT  31.859 80.784 32.537 81.336 ;
     RECT  32.317 77.472 32.573 78.072 ;
     RECT  31.849 18.864 32.581 20.376 ;
     RECT  31.997 9.36 32.605 11.976 ;
     RECT  32.461 13.056 32.605 17.64 ;
     RECT  32.581 18.864 32.605 20.76 ;
     RECT  32.317 25.824 32.645 32.376 ;
     RECT  32.605 9.36 32.668 20.76 ;
     RECT  31.133 39.888 32.681 39.912 ;
     RECT  31.381 65.712 32.681 67.32 ;
     RECT  32.069 46.752 32.717 46.776 ;
     RECT  32.485 0.096 32.723 0.648 ;
     RECT  31.601 72.336 32.753 72.696 ;
     RECT  32.483 37.824 32.789 38.904 ;
     RECT  31.669 70.224 32.789 70.248 ;
     RECT  32.645 25.824 32.819 29.016 ;
     RECT  31.997 79.344 32.819 79.752 ;
     RECT  32.173 5.376 32.825 8.184 ;
     RECT  32.281 21.792 32.825 23.976 ;
     RECT  31.921 73.776 32.825 74.76 ;
     RECT  32.573 77.52 32.825 78.072 ;
     RECT  32.668 9.36 32.861 20.088 ;
     RECT  32.819 25.824 32.861 25.848 ;
     RECT  32.465 47.856 32.861 53.064 ;
     RECT  32.825 21.792 32.867 23.544 ;
     RECT  32.753 72.48 32.867 72.696 ;
     RECT  32.825 77.52 32.867 77.544 ;
     RECT  31.917 3.36 32.893 4.008 ;
     RECT  32.483 41.52 32.897 41.544 ;
     RECT  32.825 74.352 32.897 74.76 ;
     RECT  32.821 71.232 32.933 71.256 ;
     RECT  32.537 81.312 33.005 81.336 ;
     RECT  32.893 3.36 33.011 4.056 ;
     RECT  32.819 26.928 33.041 29.016 ;
     RECT  32.861 49.248 33.041 53.064 ;
     RECT  32.897 74.352 33.041 74.376 ;
     RECT  32.825 5.568 33.073 8.184 ;
     RECT  32.861 9.36 33.073 11.736 ;
     RECT  32.537 36.528 33.077 36.84 ;
     RECT  33.041 26.928 33.113 28.248 ;
     RECT  32.681 65.712 33.145 66.36 ;
     RECT  32.861 13.296 33.149 20.088 ;
     RECT  32.429 54.528 33.149 55.032 ;
     RECT  32.533 2.208 33.157 2.232 ;
     RECT  33.157 1.728 33.289 2.232 ;
     RECT  33.149 19.872 33.329 20.088 ;
     RECT  32.537 33.504 33.401 35.496 ;
     RECT  31.781 62.736 33.433 62.76 ;
     RECT  33.329 19.872 33.437 19.896 ;
     RECT  32.483 42.72 33.469 42.84 ;
     RECT  33.149 54.576 33.469 55.032 ;
     RECT  30.773 61.44 33.505 61.464 ;
     RECT  33.433 62.64 33.505 62.76 ;
     RECT  33.181 44.448 33.577 44.472 ;
     RECT  32.465 45.456 33.577 45.48 ;
     RECT  32.723 0.096 33.587 0.6 ;
     RECT  32.867 21.792 33.613 23.016 ;
     RECT  33.613 21.504 33.617 23.016 ;
     RECT  33.077 36.576 33.649 36.84 ;
     RECT  32.789 37.824 33.649 38.424 ;
     RECT  31.619 57.024 33.649 59.256 ;
     RECT  32.177 68.784 33.649 68.808 ;
     RECT  33.577 44.448 33.653 45.48 ;
     RECT  33.653 44.448 33.661 45.048 ;
     RECT  33.149 13.296 33.761 18.888 ;
     RECT  33.041 49.248 33.761 53.016 ;
     RECT  33.469 54.576 33.761 55.176 ;
     RECT  33.761 13.296 33.779 17.976 ;
     RECT  33.505 62.64 33.829 63.096 ;
     RECT  32.819 79.344 33.865 79.56 ;
     RECT  32.645 30 33.877 32.376 ;
     RECT  33.181 25.44 33.884 25.464 ;
     RECT  33.884 25.056 33.925 25.464 ;
     RECT  33.761 49.248 33.937 52.824 ;
     RECT  32.861 47.856 33.973 47.976 ;
     RECT  33.937 49.2 33.973 52.824 ;
     RECT  33.113 27.072 34.045 28.248 ;
     RECT  33.877 29.376 34.045 32.376 ;
     RECT  33.469 42.192 34.045 42.84 ;
     RECT  33.865 79.2 34.045 79.56 ;
     RECT  33.073 5.568 34.153 11.736 ;
     RECT  33.779 13.296 34.153 13.32 ;
     RECT  33.505 61.392 34.153 61.464 ;
     RECT  32.867 72.672 34.153 72.696 ;
     RECT  34.045 79.2 34.165 80.328 ;
     RECT  33.037 81.408 34.165 82.008 ;
     RECT  33.649 36.576 34.189 38.424 ;
     RECT  34.153 5.568 34.225 13.32 ;
     RECT  34.045 27.072 34.261 32.376 ;
     RECT  34.153 72.432 34.261 72.696 ;
     RECT  33.289 1.728 34.369 2.28 ;
     RECT  33.011 3.36 34.369 4.008 ;
     RECT  34.189 40.032 34.405 40.056 ;
     RECT  34.153 61.152 34.477 61.464 ;
     RECT  33.829 62.544 34.477 63.096 ;
     RECT  34.261 27.072 34.513 32.472 ;
     RECT  33.401 33.6 34.513 35.496 ;
     RECT  34.045 41.76 34.585 42.84 ;
     RECT  33.649 57.024 34.585 59.496 ;
     RECT  33.649 68.64 34.585 68.808 ;
     RECT  34.261 72.432 34.652 73.272 ;
     RECT  34.189 36.528 34.657 38.424 ;
     RECT  34.477 61.152 34.693 63.096 ;
     RECT  33.661 44.448 34.729 44.472 ;
     RECT  33.761 54.96 34.729 55.176 ;
     RECT  34.585 56.256 34.729 59.496 ;
     RECT  33.587 0.144 34.739 0.6 ;
     RECT  34.225 5.28 34.765 13.32 ;
     RECT  33.779 14.352 34.765 17.976 ;
     RECT  34.153 75.408 34.765 75.432 ;
     RECT  34.369 1.728 34.808 4.008 ;
     RECT  34.765 5.28 34.808 17.976 ;
     RECT  34.189 19.776 34.808 19.8 ;
     RECT  33.617 21.504 34.808 21.528 ;
     RECT  33.617 22.992 34.808 23.016 ;
     RECT  33.925 25.056 34.808 25.992 ;
     RECT  34.513 27.072 34.808 35.496 ;
     RECT  34.657 36.528 34.808 39 ;
     RECT  34.405 40.032 34.808 40.584 ;
     RECT  34.585 41.76 34.808 43.032 ;
     RECT  34.729 44.064 34.808 44.472 ;
     RECT  33.973 47.856 34.808 52.824 ;
     RECT  34.333 53.856 34.808 53.928 ;
     RECT  34.729 54.96 34.808 59.496 ;
     RECT  34.693 61.152 34.808 63.288 ;
     RECT  33.145 64.896 34.808 66.36 ;
     RECT  34.585 68.64 34.808 69.24 ;
     RECT  34.652 71.76 34.808 73.272 ;
     RECT  34.765 75.408 34.808 75.48 ;
     RECT  34.801 77.328 34.808 77.352 ;
     RECT  34.165 79.2 34.808 82.008 ;
     RECT  34.739 0.576 34.849 0.6 ;
     RECT  34.808 1.728 34.912 84.252 ;
     RECT  34.912 1.728 35.104 83.982 ;
     RECT  35.104 1.728 35.165 19.8 ;
     RECT  35.104 32.784 35.165 32.808 ;
     RECT  35.104 36.528 35.165 41.64 ;
     RECT  35.104 21.12 35.201 22.728 ;
     RECT  35.165 3.36 35.219 19.8 ;
     RECT  35.104 42.816 35.219 44.472 ;
     RECT  35.104 79.056 35.219 82.488 ;
     RECT  35.219 44.064 35.237 44.424 ;
     RECT  35.219 3.36 35.273 19.512 ;
     RECT  35.201 21.12 35.273 21.528 ;
     RECT  35.104 28.416 35.273 31.512 ;
     RECT  35.219 42.816 35.273 43.032 ;
     RECT  35.165 1.728 35.315 2.28 ;
     RECT  35.201 22.704 35.315 22.728 ;
     RECT  35.165 36.624 35.345 41.64 ;
     RECT  35.104 45.648 35.345 53.112 ;
     RECT  35.345 36.624 35.381 39.384 ;
     RECT  35.104 61.152 35.381 63.288 ;
     RECT  35.104 72.432 35.381 73.272 ;
     RECT  35.273 28.464 35.453 31.512 ;
     RECT  35.104 66.288 35.453 66.6 ;
     RECT  35.315 1.728 35.533 1.8 ;
     RECT  35.104 23.76 35.597 27.336 ;
     RECT  35.104 75.024 35.603 77.976 ;
     RECT  35.597 23.76 35.633 25.752 ;
     RECT  35.104 54.672 35.633 59.208 ;
     RECT  35.345 40.464 35.699 41.64 ;
     RECT  35.633 25.104 35.741 25.752 ;
     RECT  35.104 68.352 35.777 69.96 ;
     RECT  35.273 3.36 35.813 18.792 ;
     RECT  35.533 1.728 35.849 1.752 ;
     RECT  35.633 23.76 35.885 24.12 ;
     RECT  35.813 3.36 35.891 17.688 ;
     RECT  35.891 8.448 35.921 17.688 ;
     RECT  35.699 40.464 35.932 40.824 ;
     RECT  35.921 13.056 35.957 17.688 ;
     RECT  35.453 66.288 35.957 66.312 ;
     RECT  35.381 36.672 35.993 39.384 ;
     RECT  35.219 80.448 35.993 82.488 ;
     RECT  35.921 8.592 36.065 12.072 ;
     RECT  35.813 18.768 36.065 18.792 ;
     RECT  35.932 40.464 36.065 40.632 ;
     RECT  35.104 33.888 36.097 35.304 ;
     RECT  35.957 13.104 36.137 17.688 ;
     RECT  35.273 42.816 36.169 42.84 ;
     RECT  35.633 54.672 36.169 55.32 ;
     RECT  35.381 61.152 36.173 63.048 ;
     RECT  35.453 28.752 36.241 31.512 ;
     RECT  35.777 68.352 36.245 69.528 ;
     RECT  36.169 54.576 36.281 55.32 ;
     RECT  35.891 3.36 36.313 7.464 ;
     RECT  35.603 75.408 36.349 77.976 ;
     RECT  35.219 79.056 36.349 79.08 ;
     RECT  36.065 8.592 36.353 11.928 ;
     RECT  36.313 2.832 36.397 7.464 ;
     RECT  35.993 36.672 36.421 37.08 ;
     RECT  35.104 64.272 36.421 65.304 ;
     RECT  35.345 46.224 36.425 53.112 ;
     RECT  36.241 28.752 36.457 31.896 ;
     RECT  35.885 23.856 36.497 24.12 ;
     RECT  36.425 46.224 36.533 49.896 ;
     RECT  36.425 51.12 36.605 53.112 ;
     RECT  36.097 33.6 36.661 35.304 ;
     RECT  36.421 22.176 36.677 22.2 ;
     RECT  35.993 38.16 36.785 39.384 ;
     RECT  36.457 28.512 36.817 32.424 ;
     RECT  36.169 42.192 36.817 42.84 ;
     RECT  35.237 44.4 36.817 44.424 ;
     RECT  36.281 55.296 36.817 55.32 ;
     RECT  35.633 56.496 36.817 59.208 ;
     RECT  35.273 21.12 36.889 21.144 ;
     RECT  36.661 33.6 36.889 35.496 ;
     RECT  36.421 36.48 36.889 37.08 ;
     RECT  35.993 80.448 36.889 81.384 ;
     RECT  36.173 61.776 36.893 63.048 ;
     RECT  35.597 27.312 36.925 27.336 ;
     RECT  36.817 28.464 36.925 32.424 ;
     RECT  36.353 9.072 36.929 11.928 ;
     RECT  36.605 51.264 36.961 53.112 ;
     RECT  36.817 54.096 36.961 54.12 ;
     RECT  36.421 64.272 36.961 66.024 ;
     RECT  35.741 25.488 36.965 25.752 ;
     RECT  36.925 27.312 36.997 32.424 ;
     RECT  36.889 33.6 36.997 37.08 ;
     RECT  36.961 64.08 36.997 66.024 ;
     RECT  36.929 9.072 37.073 11.832 ;
     RECT  36.817 55.296 37.073 59.208 ;
     RECT  36.997 64.08 37.073 66.696 ;
     RECT  36.137 13.296 37.141 17.688 ;
     RECT  36.961 51.264 37.145 54.12 ;
     RECT  37.073 58.752 37.213 59.208 ;
     RECT  36.245 68.784 37.213 69.528 ;
     RECT  36.065 40.464 37.249 40.488 ;
     RECT  37.073 55.296 37.253 57.624 ;
     RECT  36.893 61.776 37.253 62.568 ;
     RECT  36.397 2.928 37.285 7.464 ;
     RECT  36.497 24.096 37.285 24.12 ;
     RECT  37.249 40.464 37.289 40.824 ;
     RECT  37.253 62.16 37.289 62.568 ;
     RECT  37.213 67.824 37.357 69.528 ;
     RECT  36.097 70.752 37.357 70.776 ;
     RECT  37.213 58.752 37.433 59.256 ;
     RECT  36.533 46.224 37.501 49.848 ;
     RECT  36.349 75.408 37.501 79.08 ;
     RECT  36.889 80.352 37.501 81.384 ;
     RECT  36.965 25.632 37.537 25.752 ;
     RECT  37.501 45.6 37.573 49.848 ;
     RECT  37.145 54.096 37.573 54.12 ;
     RECT  37.253 55.296 37.573 56.232 ;
     RECT  37.141 13.152 37.609 17.688 ;
     RECT  36.817 42.192 37.619 44.424 ;
     RECT  37.609 13.056 37.645 17.688 ;
     RECT  36.889 21.12 37.645 21.48 ;
     RECT  37.537 25.632 37.667 26.232 ;
     RECT  37.645 20.304 37.717 21.48 ;
     RECT  36.997 27.312 37.753 37.08 ;
     RECT  36.785 38.736 37.753 39.384 ;
     RECT  37.573 45.552 37.753 49.848 ;
     RECT  37.145 51.264 37.753 53.064 ;
     RECT  35.381 72.768 37.753 72.792 ;
     RECT  37.667 25.632 37.757 25.656 ;
     RECT  37.619 42.192 37.757 43.752 ;
     RECT  37.289 62.304 37.757 62.568 ;
     RECT  37.717 19.92 37.789 21.48 ;
     RECT  37.073 64.848 37.793 66.696 ;
     RECT  37.789 19.824 37.825 21.48 ;
     RECT  37.753 45.552 37.865 53.064 ;
     RECT  36.817 22.512 37.897 22.824 ;
     RECT  37.433 58.752 37.973 58.824 ;
     RECT  37.825 19.056 38.005 21.48 ;
     RECT  37.897 22.464 38.005 22.824 ;
     RECT  37.285 24.096 38.005 24.504 ;
     RECT  37.753 27.312 38.009 39.384 ;
     RECT  37.793 64.848 38.041 65.304 ;
     RECT  37.645 12.816 38.077 17.688 ;
     RECT  38.005 19.056 38.077 22.824 ;
     RECT  38.005 24 38.077 24.504 ;
     RECT  37.973 58.752 38.081 58.776 ;
     RECT  37.865 52.032 38.113 53.064 ;
     RECT  37.573 54.096 38.113 56.232 ;
     RECT  37.501 75.408 38.113 81.384 ;
     RECT  35.993 82.464 38.113 82.488 ;
     RECT  38.009 27.312 38.117 37.992 ;
     RECT  38.077 12.816 38.149 17.88 ;
     RECT  38.077 19.056 38.149 24.504 ;
     RECT  38.117 27.312 38.153 37.128 ;
     RECT  37.285 2.928 38.156 7.992 ;
     RECT  37.073 9.072 38.156 11.736 ;
     RECT  38.153 34.896 38.189 37.128 ;
     RECT  38.153 27.312 38.221 33.912 ;
     RECT  37.253 57.408 38.221 57.624 ;
     RECT  37.865 45.552 38.225 50.808 ;
     RECT  38.113 52.032 38.225 56.232 ;
     RECT  38.156 2.928 38.243 11.736 ;
     RECT  38.225 52.032 38.261 54.888 ;
     RECT  38.113 75.408 38.261 82.488 ;
     RECT  38.243 2.928 38.293 7.992 ;
     RECT  38.225 45.552 38.293 48.216 ;
     RECT  38.149 12.816 38.297 24.504 ;
     RECT  38.221 26.88 38.297 33.912 ;
     RECT  38.221 57.408 38.329 58.152 ;
     RECT  38.041 64.08 38.369 65.304 ;
     RECT  38.297 26.88 38.405 33.864 ;
     RECT  38.261 79.008 38.405 82.488 ;
     RECT  38.225 55.92 38.437 56.232 ;
     RECT  38.329 57.312 38.437 58.152 ;
     RECT  37.357 67.824 38.437 70.776 ;
     RECT  37.753 72.768 38.437 73.368 ;
     RECT  37.289 40.8 38.441 40.824 ;
     RECT  38.297 22.704 38.483 24.504 ;
     RECT  38.077 41.808 38.483 41.832 ;
     RECT  37.793 66.624 38.483 66.696 ;
     RECT  38.437 67.776 38.483 70.776 ;
     RECT  38.405 79.008 38.513 81.384 ;
     RECT  38.437 72.384 38.524 73.368 ;
     RECT  38.524 72.768 38.549 73.368 ;
     RECT  38.483 66.624 38.593 66.648 ;
     RECT  38.189 36.816 38.657 37.128 ;
     RECT  38.009 39.36 38.657 39.384 ;
     RECT  38.369 64.08 38.729 64.872 ;
     RECT  37.757 62.544 38.761 62.568 ;
     RECT  38.483 67.776 38.761 70.728 ;
     RECT  38.761 67.68 38.771 70.728 ;
     RECT  38.761 61.632 38.773 62.616 ;
     RECT  38.293 45.024 38.797 48.216 ;
     RECT  38.243 9.36 38.833 11.736 ;
     RECT  38.297 12.816 38.833 21.624 ;
     RECT  38.405 26.88 38.833 30.984 ;
     RECT  38.773 61.632 38.86 62.712 ;
     RECT  38.437 55.92 38.873 58.152 ;
     RECT  38.797 44.88 38.905 48.216 ;
     RECT  38.833 9.36 38.909 21.624 ;
     RECT  38.549 72.912 38.977 73.368 ;
     RECT  38.909 9.6 38.981 21.624 ;
     RECT  38.729 64.608 39.017 64.872 ;
     RECT  38.293 2.832 39.049 7.992 ;
     RECT  38.905 44.832 39.089 48.216 ;
     RECT  38.833 26.4 39.161 30.984 ;
     RECT  39.161 26.784 39.197 30.984 ;
     RECT  38.225 49.536 39.229 50.808 ;
     RECT  39.089 46.608 39.301 48.216 ;
     RECT  38.261 52.032 39.301 54.168 ;
     RECT  38.981 10.032 39.445 21.624 ;
     RECT  38.405 31.968 39.481 33.864 ;
     RECT  38.189 34.896 39.481 35.736 ;
     RECT  39.301 46.608 39.589 48.408 ;
     RECT  38.483 22.704 39.596 24.408 ;
     RECT  37.757 42.816 39.625 43.752 ;
     RECT  39.089 44.832 39.625 45.192 ;
     RECT  39.589 46.608 39.625 48.456 ;
     RECT  39.229 49.536 39.625 50.904 ;
     RECT  38.657 37.104 39.769 37.128 ;
     RECT  38.941 40.464 39.781 40.488 ;
     RECT  39.049 2.784 39.805 7.992 ;
     RECT  38.261 75.408 39.805 77.976 ;
     RECT  39.625 46.608 39.925 50.904 ;
     RECT  39.301 51.888 39.925 54.168 ;
     RECT  39.805 75.216 39.985 77.976 ;
     RECT  38.513 79.008 39.985 81.336 ;
     RECT  39.481 31.968 40.069 35.736 ;
     RECT  39.769 37.056 40.069 37.128 ;
     RECT  40.049 59.424 40.129 59.448 ;
     RECT  39.805 2.784 40.208 8.568 ;
     RECT  39.445 10.032 40.208 21.672 ;
     RECT  39.596 22.704 40.208 25.128 ;
     RECT  39.197 26.784 40.208 27.912 ;
     RECT  39.197 29.04 40.208 30.984 ;
     RECT  40.069 31.968 40.208 37.128 ;
     RECT  39.805 38.688 40.208 38.712 ;
     RECT  39.781 40.464 40.208 41.064 ;
     RECT  39.625 42.816 40.208 45.192 ;
     RECT  39.925 46.608 40.208 54.168 ;
     RECT  38.873 56.208 40.208 58.152 ;
     RECT  40.129 59.232 40.208 59.448 ;
     RECT  38.86 61.632 40.208 62.568 ;
     RECT  39.017 64.608 40.208 64.632 ;
     RECT  39.877 66.576 40.208 66.6 ;
     RECT  38.771 67.68 40.208 70.152 ;
     RECT  39.877 71.712 40.208 71.736 ;
     RECT  38.977 72.912 40.208 73.8 ;
     RECT  39.985 75.216 40.208 81.336 ;
     RECT  38.405 82.464 40.208 82.488 ;
     RECT  40.208 2.148 40.312 84.252 ;
     RECT  40.312 2.418 40.504 83.982 ;
     RECT  40.504 2.736 40.637 23.304 ;
     RECT  40.504 45.168 40.637 48.456 ;
     RECT  40.504 65.664 40.673 68.808 ;
     RECT  40.637 15.936 40.717 23.304 ;
     RECT  40.504 61.632 40.781 63.144 ;
     RECT  40.504 38.16 40.817 38.184 ;
     RECT  40.504 73.008 40.817 83.112 ;
     RECT  40.637 2.736 40.924 14.472 ;
     RECT  40.673 65.664 40.997 65.688 ;
     RECT  40.817 73.008 40.997 76.968 ;
     RECT  40.504 32.208 41.02 37.08 ;
     RECT  40.504 52.464 41.033 53.4 ;
     RECT  40.504 71.712 41.033 72.024 ;
     RECT  40.717 16.032 41.105 23.304 ;
     RECT  40.817 77.952 41.116 83.112 ;
     RECT  40.997 74.688 41.141 76.968 ;
     RECT  40.504 24.48 41.177 26.664 ;
     RECT  40.637 45.504 41.177 48.456 ;
     RECT  41.02 33.264 41.213 37.08 ;
     RECT  40.924 10.08 41.249 14.472 ;
     RECT  40.504 59.232 41.321 59.304 ;
     RECT  41.105 16.032 41.393 22.776 ;
     RECT  41.177 46.752 41.429 48.456 ;
     RECT  40.504 64.368 41.429 64.632 ;
     RECT  41.177 24.912 41.497 26.664 ;
     RECT  40.504 27.648 41.497 30.984 ;
     RECT  40.781 63.12 41.497 63.144 ;
     RECT  41.393 16.032 41.501 19.992 ;
     RECT  40.924 2.736 41.537 8.808 ;
     RECT  41.429 47.472 41.537 48.456 ;
     RECT  41.033 72 41.537 72.024 ;
     RECT  40.504 41.568 41.569 41.592 ;
     RECT  40.504 42.816 41.569 43.944 ;
     RECT  41.497 24.912 41.603 30.984 ;
     RECT  41.569 41.568 41.605 43.944 ;
     RECT  41.537 47.904 41.609 48.456 ;
     RECT  41.501 16.656 41.645 19.992 ;
     RECT  41.116 77.952 41.645 77.976 ;
     RECT  41.645 16.656 41.681 19.944 ;
     RECT  41.177 45.504 41.681 45.528 ;
     RECT  40.997 73.008 41.681 73.464 ;
     RECT  41.603 28.176 41.753 30.984 ;
     RECT  41.681 19.296 41.861 19.944 ;
     RECT  41.02 32.208 41.861 32.28 ;
     RECT  41.605 41.328 41.929 43.944 ;
     RECT  41.141 75.12 41.929 76.968 ;
     RECT  41.681 73.056 41.933 73.464 ;
     RECT  40.504 39.264 41.965 40.008 ;
     RECT  40.504 49.488 42.005 51.24 ;
     RECT  41.929 75.12 42.013 77.544 ;
     RECT  41.537 2.88 42.073 8.808 ;
     RECT  41.116 79.008 42.073 83.112 ;
     RECT  41.929 15.552 42.077 15.576 ;
     RECT  41.929 41.328 42.083 44.472 ;
     RECT  41.753 28.464 42.109 30.984 ;
     RECT  41.497 63.12 42.109 63.24 ;
     RECT  41.861 32.256 42.113 32.28 ;
     RECT  42.073 79.008 42.133 83.208 ;
     RECT  40.504 56.496 42.145 57.288 ;
     RECT  41.321 59.232 42.181 59.256 ;
     RECT  41.609 47.904 42.185 47.928 ;
     RECT  41.213 33.264 42.221 35.256 ;
     RECT  41.033 52.464 42.229 53.016 ;
     RECT  42.145 56.352 42.253 57.288 ;
     RECT  41.393 21.024 42.257 22.776 ;
     RECT  42.005 49.728 42.257 50.52 ;
     RECT  42.257 21.264 42.275 22.776 ;
     RECT  42.181 58.608 42.275 59.256 ;
     RECT  41.213 36.288 42.289 37.08 ;
     RECT  41.965 38.4 42.289 40.008 ;
     RECT  40.673 67.248 42.289 68.808 ;
     RECT  42.229 51.504 42.316 53.016 ;
     RECT  41.933 73.296 42.325 73.464 ;
     RECT  42.221 33.36 42.329 35.256 ;
     RECT  42.257 50.496 42.365 50.52 ;
     RECT  42.133 79.008 42.365 83.64 ;
     RECT  42.109 28.464 42.371 31.176 ;
     RECT  42.371 28.944 42.401 31.176 ;
     RECT  42.401 28.944 42.412 29.208 ;
     RECT  42.073 71.856 42.433 71.88 ;
     RECT  42.073 2.88 42.437 9.048 ;
     RECT  42.083 41.328 42.469 42.936 ;
     RECT  42.013 75.12 42.469 76.92 ;
     RECT  42.469 74.592 42.473 76.92 ;
     RECT  42.289 36.288 42.505 40.008 ;
     RECT  42.469 41.136 42.505 42.936 ;
     RECT  42.316 51.648 42.505 53.016 ;
     RECT  42.473 74.592 42.515 76.632 ;
     RECT  41.749 61.584 42.517 61.608 ;
     RECT  42.109 63.12 42.517 63.288 ;
     RECT  42.401 30.384 42.545 31.176 ;
     RECT  41.603 24.912 42.581 26.76 ;
     RECT  41.429 64.368 42.757 64.392 ;
     RECT  42.517 62.592 42.761 63.288 ;
     RECT  42.289 67.248 42.805 68.952 ;
     RECT  42.037 54.624 42.865 54.648 ;
     RECT  42.515 74.592 42.869 76.488 ;
     RECT  42.505 51.648 42.905 53.544 ;
     RECT  42.329 33.36 42.941 34.824 ;
     RECT  42.505 36.288 42.941 42.936 ;
     RECT  42.325 73.296 42.941 73.512 ;
     RECT  41.681 16.656 42.977 17.64 ;
     RECT  42.757 64.368 42.977 64.728 ;
     RECT  42.581 25.248 43.081 26.76 ;
     RECT  42.905 53.52 43.117 53.544 ;
     RECT  42.865 54.624 43.117 55.08 ;
     RECT  42.805 66.672 43.117 68.952 ;
     RECT  42.757 69.984 43.117 70.008 ;
     RECT  42.941 33.36 43.189 33.432 ;
     RECT  42.941 42.336 43.225 42.936 ;
     RECT  42.275 58.608 43.261 58.68 ;
     RECT  42.545 30.384 43.301 30.84 ;
     RECT  41.249 10.08 43.333 13.992 ;
     RECT  42.365 79.2 43.333 83.64 ;
     RECT  42.517 61.536 43.369 61.608 ;
     RECT  43.333 79.008 43.369 83.64 ;
     RECT  43.225 42.336 43.373 43.32 ;
     RECT  42.083 44.448 43.373 44.472 ;
     RECT  42.941 36.288 43.405 41.016 ;
     RECT  42.761 63.264 43.409 63.288 ;
     RECT  43.369 61.536 43.436 62.184 ;
     RECT  42.433 71.808 43.436 71.88 ;
     RECT  43.333 31.968 43.445 31.992 ;
     RECT  42.977 64.704 43.445 64.728 ;
     RECT  43.436 61.2 43.475 62.184 ;
     RECT  43.373 42.528 43.481 43.32 ;
     RECT  43.117 53.52 43.481 55.08 ;
     RECT  42.253 56.352 43.484 57.624 ;
     RECT  42.275 21.264 43.513 21.672 ;
     RECT  42.275 22.752 43.513 22.776 ;
     RECT  42.412 28.944 43.513 29.064 ;
     RECT  43.405 35.904 43.517 41.016 ;
     RECT  43.481 53.52 43.517 54.648 ;
     RECT  43.475 61.2 43.523 61.608 ;
     RECT  43.484 55.68 43.525 57.624 ;
     RECT  43.261 58.608 43.525 58.92 ;
     RECT  42.869 74.976 43.549 76.488 ;
     RECT  43.189 32.976 43.553 33.432 ;
     RECT  43.045 23.904 43.589 23.928 ;
     RECT  41.861 19.92 43.621 19.944 ;
     RECT  43.117 66.672 43.693 70.008 ;
     RECT  43.436 71.04 43.693 71.88 ;
     RECT  42.905 51.648 43.697 52.2 ;
     RECT  43.525 55.68 43.697 58.92 ;
     RECT  42.437 2.88 43.717 8.856 ;
     RECT  43.333 10.08 43.717 14.184 ;
     RECT  43.517 35.904 43.717 40.584 ;
     RECT  43.523 61.44 43.733 61.608 ;
     RECT  43.333 50.064 43.765 50.088 ;
     RECT  43.081 25.248 43.801 27.336 ;
     RECT  43.189 45.936 43.801 45.96 ;
     RECT  43.693 66.672 43.801 71.88 ;
     RECT  42.941 73.296 43.801 73.416 ;
     RECT  43.657 48.624 43.837 48.648 ;
     RECT  43.765 49.632 43.837 50.088 ;
     RECT  43.697 57.168 43.837 58.92 ;
     RECT  43.513 64.944 43.837 64.968 ;
     RECT  43.549 74.976 43.837 77.4 ;
     RECT  43.369 78.768 43.837 83.64 ;
     RECT  43.697 55.68 43.859 55.848 ;
     RECT  43.621 18.96 43.873 19.944 ;
     RECT  43.481 42.72 43.873 43.32 ;
     RECT  43.837 57.168 43.877 59.304 ;
     RECT  43.859 55.68 43.907 55.704 ;
     RECT  43.717 2.88 43.909 14.184 ;
     RECT  43.261 15.648 43.909 15.672 ;
     RECT  43.873 18.768 43.909 19.944 ;
     RECT  43.801 44.928 43.913 45.96 ;
     RECT  43.801 66.672 43.913 73.416 ;
     RECT  43.909 18.768 43.945 20.136 ;
     RECT  43.837 74.976 43.945 83.64 ;
     RECT  42.941 34.8 43.981 34.824 ;
     RECT  43.837 48.624 44.012 50.088 ;
     RECT  43.513 21.264 44.017 22.776 ;
     RECT  43.697 52.176 44.017 52.2 ;
     RECT  43.945 74.688 44.029 83.64 ;
     RECT  43.945 18.72 44.053 20.136 ;
     RECT  44.012 48.336 44.053 50.088 ;
     RECT  44.017 52.176 44.057 52.44 ;
     RECT  44.053 18.144 44.089 20.136 ;
     RECT  44.017 21.264 44.089 23.592 ;
     RECT  43.837 64.944 44.093 65.352 ;
     RECT  43.873 42.72 44.099 43.848 ;
     RECT  43.913 44.928 44.099 44.952 ;
     RECT  43.913 67.2 44.129 73.416 ;
     RECT  43.877 57.6 44.165 59.304 ;
     RECT  43.909 15.36 44.197 15.672 ;
     RECT  42.977 16.656 44.197 17.064 ;
     RECT  44.165 57.648 44.197 59.304 ;
     RECT  43.301 30.384 44.269 30.744 ;
     RECT  44.053 48.336 44.269 50.952 ;
     RECT  44.269 30.384 44.308 31.368 ;
     RECT  43.717 35.856 44.345 40.584 ;
     RECT  43.909 2.832 44.389 14.184 ;
     RECT  44.197 15.36 44.389 17.064 ;
     RECT  43.801 25.104 44.413 27.336 ;
     RECT  43.513 28.464 44.413 29.064 ;
     RECT  44.305 46.128 44.435 46.152 ;
     RECT  43.553 33.312 44.437 33.432 ;
     RECT  44.389 2.832 44.483 17.064 ;
     RECT  44.197 57.648 44.485 59.496 ;
     RECT  44.093 65.328 44.485 65.352 ;
     RECT  43.517 53.568 44.525 54.648 ;
     RECT  44.485 57.648 44.525 59.928 ;
     RECT  44.485 65.328 44.525 65.544 ;
     RECT  43.981 34.752 44.561 34.824 ;
     RECT  44.089 18.144 44.597 23.592 ;
     RECT  44.269 47.376 44.629 50.952 ;
     RECT  44.437 33.312 44.677 33.576 ;
     RECT  44.525 59.184 44.677 59.928 ;
     RECT  44.677 32.928 44.701 33.576 ;
     RECT  44.561 34.752 44.701 34.776 ;
     RECT  44.129 67.248 44.881 73.416 ;
     RECT  44.483 10.176 44.917 17.064 ;
     RECT  44.099 42.72 44.917 43.416 ;
     RECT  44.629 47.232 44.917 50.952 ;
     RECT  44.701 32.928 44.953 34.776 ;
     RECT  44.917 46.512 44.953 50.952 ;
     RECT  44.413 25.104 44.965 29.064 ;
     RECT  44.308 30.336 44.965 31.368 ;
     RECT  44.677 59.184 44.989 60.456 ;
     RECT  43.733 61.44 44.989 61.464 ;
     RECT  44.917 42 45.157 43.416 ;
     RECT  44.525 57.648 45.169 58.152 ;
     RECT  44.989 59.184 45.169 61.464 ;
     RECT  44.881 67.248 45.169 73.56 ;
     RECT  44.029 74.784 45.169 83.64 ;
     RECT  45.169 57.312 45.241 58.152 ;
     RECT  44.345 35.856 45.313 40.104 ;
     RECT  45.313 35.856 45.341 40.68 ;
     RECT  45.157 41.952 45.341 43.416 ;
     RECT  45.277 55.968 45.421 55.992 ;
     RECT  45.341 35.856 45.457 43.416 ;
     RECT  44.773 0.432 45.493 0.456 ;
     RECT  45.457 35.856 45.493 43.608 ;
     RECT  44.525 54.288 45.493 54.648 ;
     RECT  45.421 55.824 45.493 55.992 ;
     RECT  45.241 57.072 45.493 58.152 ;
     RECT  45.169 59.184 45.493 61.608 ;
     RECT  44.525 65.52 45.493 65.544 ;
     RECT  45.169 67.248 45.493 83.64 ;
     RECT  45.493 0.432 45.565 0.504 ;
     RECT  44.483 2.832 45.565 9.096 ;
     RECT  44.917 10.176 45.565 17.208 ;
     RECT  44.597 18.192 45.565 23.592 ;
     RECT  44.965 25.104 45.565 31.368 ;
     RECT  45.097 1.728 45.608 1.752 ;
     RECT  45.565 2.832 45.608 17.208 ;
     RECT  45.565 18.192 45.608 31.368 ;
     RECT  44.953 32.544 45.608 34.776 ;
     RECT  45.493 35.856 45.608 43.848 ;
     RECT  44.953 46.512 45.608 51.336 ;
     RECT  44.057 52.416 45.608 52.44 ;
     RECT  45.493 54.288 45.608 55.992 ;
     RECT  45.493 57.072 45.608 62.232 ;
     RECT  45.116 63.216 45.608 63.24 ;
     RECT  45.493 65.52 45.608 83.64 ;
     RECT  45.565 0.432 45.781 0.552 ;
     RECT  45.608 1.728 45.904 84.252 ;
     RECT  45.904 24.48 46.001 25.752 ;
     RECT  45.904 45.456 46.019 53.112 ;
     RECT  45.904 36.816 46.081 44.472 ;
     RECT  45.904 1.728 46.115 18.264 ;
     RECT  46.019 47.424 46.145 53.112 ;
     RECT  45.904 54.096 46.163 54.12 ;
     RECT  46.115 1.728 46.181 14.376 ;
     RECT  46.145 50.736 46.181 53.112 ;
     RECT  45.904 19.344 46.211 23.112 ;
     RECT  46.181 9.024 46.217 14.376 ;
     RECT  45.904 57.024 46.225 57.336 ;
     RECT  46.211 20.784 46.252 23.112 ;
     RECT  45.904 58.464 46.285 84.252 ;
     RECT  46.181 1.728 46.289 7.992 ;
     RECT  46.001 24.48 46.289 25.608 ;
     RECT  45.781 0.432 46.369 0.6 ;
     RECT  46.115 18.144 46.397 18.264 ;
     RECT  46.397 18.24 46.541 18.264 ;
     RECT  46.285 58.464 46.573 84.36 ;
     RECT  46.369 0.432 46.645 0.552 ;
     RECT  45.904 55.248 46.649 55.992 ;
     RECT  46.289 2.88 46.685 7.992 ;
     RECT  46.081 36.816 46.739 44.04 ;
     RECT  46.181 50.832 46.739 53.112 ;
     RECT  46.285 86.208 46.753 86.232 ;
     RECT  46.685 3.12 46.757 7.992 ;
     RECT  46.739 36.816 46.829 43.944 ;
     RECT  46.757 3.312 46.865 7.992 ;
     RECT  46.217 9.12 46.865 14.376 ;
     RECT  46.573 58.464 46.937 84.408 ;
     RECT  46.211 19.344 46.969 19.512 ;
     RECT  46.645 0.144 46.981 0.552 ;
     RECT  46.019 45.456 47.009 46.008 ;
     RECT  46.649 55.248 47.009 55.848 ;
     RECT  45.904 27.744 47.041 32.472 ;
     RECT  46.739 50.832 47.045 52.44 ;
     RECT  46.753 85.488 47.069 86.232 ;
     RECT  46.225 57.072 47.077 57.336 ;
     RECT  46.937 58.464 47.077 58.68 ;
     RECT  47.077 57.072 47.117 58.68 ;
     RECT  46.865 3.312 47.267 7.464 ;
     RECT  46.865 9.12 47.293 12.36 ;
     RECT  46.145 47.424 47.293 49.608 ;
     RECT  47.045 50.832 47.293 51.288 ;
     RECT  47.293 8.592 47.297 12.36 ;
     RECT  47.297 10.32 47.333 12.36 ;
     RECT  46.981 0.096 47.365 0.552 ;
     RECT  46.969 18.768 47.369 19.512 ;
     RECT  47.009 55.392 47.369 55.848 ;
     RECT  47.117 58.128 47.369 58.68 ;
     RECT  46.865 13.392 47.372 14.376 ;
     RECT  46.115 15.552 47.372 16.872 ;
     RECT  47.293 47.424 47.405 51.288 ;
     RECT  46.252 20.832 47.437 23.112 ;
     RECT  47.437 20.832 47.441 23.352 ;
     RECT  47.405 48.192 47.441 51.288 ;
     RECT  47.372 13.392 47.459 16.872 ;
     RECT  47.009 45.552 47.513 46.008 ;
     RECT  46.937 60.288 47.545 84.408 ;
     RECT  47.069 85.488 47.545 86.28 ;
     RECT  47.041 27.456 47.581 32.472 ;
     RECT  47.441 48.192 47.621 49.608 ;
     RECT  46.289 1.728 47.653 1.8 ;
     RECT  47.581 26.88 47.657 32.472 ;
     RECT  46.289 25.536 47.725 25.608 ;
     RECT  47.657 26.88 47.725 28.44 ;
     RECT  47.441 22.752 47.729 23.352 ;
     RECT  46.829 37.536 47.795 43.944 ;
     RECT  47.333 10.848 47.833 12.36 ;
     RECT  47.459 13.392 47.833 14.376 ;
     RECT  46.289 24.48 47.833 24.504 ;
     RECT  47.725 25.536 47.833 28.44 ;
     RECT  47.833 10.848 47.891 14.376 ;
     RECT  47.267 3.456 47.909 7.464 ;
     RECT  47.909 3.648 47.941 7.464 ;
     RECT  47.297 8.592 47.941 9.336 ;
     RECT  45.904 34.224 47.941 34.776 ;
     RECT  47.045 52.368 47.941 52.44 ;
     RECT  47.657 30.336 48.049 32.472 ;
     RECT  47.941 34.08 48.049 34.776 ;
     RECT  47.545 60.288 48.053 86.28 ;
     RECT  47.621 48.192 48.076 49.56 ;
     RECT  47.369 19.488 48.121 19.512 ;
     RECT  47.441 20.832 48.125 21.576 ;
     RECT  47.833 24.48 48.125 28.44 ;
     RECT  47.117 57.072 48.157 57.096 ;
     RECT  47.441 50.832 48.161 51.288 ;
     RECT  48.053 60.288 48.161 63.192 ;
     RECT  48.161 61.776 48.179 63.192 ;
     RECT  47.369 55.44 48.181 55.848 ;
     RECT  48.157 57.072 48.181 57.624 ;
     RECT  47.437 36.384 48.229 36.408 ;
     RECT  48.181 55.44 48.241 57.624 ;
     RECT  47.581 46.8 48.269 46.824 ;
     RECT  48.229 35.856 48.301 36.408 ;
     RECT  47.795 37.536 48.301 43.512 ;
     RECT  48.161 60.288 48.301 60.744 ;
     RECT  47.941 3.648 48.373 9.336 ;
     RECT  47.941 52.368 48.377 52.488 ;
     RECT  48.161 51.072 48.409 51.288 ;
     RECT  48.121 19.488 48.445 19.8 ;
     RECT  48.125 20.832 48.445 20.856 ;
     RECT  48.179 61.776 48.457 62.904 ;
     RECT  48.301 59.808 48.467 60.744 ;
     RECT  47.653 1.728 48.476 1.896 ;
     RECT  48.076 48.192 48.476 48.984 ;
     RECT  47.369 58.608 48.481 58.68 ;
     RECT  48.125 24.48 48.521 26.904 ;
     RECT  48.049 30.336 48.521 34.776 ;
     RECT  47.459 15.504 48.553 16.872 ;
     RECT  48.553 14.928 48.557 16.872 ;
     RECT  48.265 53.568 48.557 53.592 ;
     RECT  48.476 1.728 48.563 2.28 ;
     RECT  48.476 47.616 48.563 48.984 ;
     RECT  48.521 30.336 48.593 34.488 ;
     RECT  48.053 64.32 48.593 86.28 ;
     RECT  48.563 47.904 48.601 48.984 ;
     RECT  48.373 3.648 48.661 9.768 ;
     RECT  47.891 10.848 48.661 13.848 ;
     RECT  48.593 32.448 48.665 34.488 ;
     RECT  48.445 19.488 48.733 20.856 ;
     RECT  47.365 0.096 48.755 0.6 ;
     RECT  48.733 18.96 48.769 20.856 ;
     RECT  48.769 18.768 48.841 20.856 ;
     RECT  48.841 18.72 48.877 20.856 ;
     RECT  48.457 61.776 48.881 62.76 ;
     RECT  48.557 16.656 48.913 16.872 ;
     RECT  48.877 18.48 48.913 20.856 ;
     RECT  47.513 45.552 48.913 45.576 ;
     RECT  48.409 51.072 48.917 51.336 ;
     RECT  48.301 35.856 48.947 43.512 ;
     RECT  48.661 3.648 48.949 13.848 ;
     RECT  48.557 14.928 48.949 15.528 ;
     RECT  48.241 55.44 48.949 57.096 ;
     RECT  48.481 58.608 48.949 58.728 ;
     RECT  48.467 59.808 48.949 60.408 ;
     RECT  48.913 44.976 48.953 45.576 ;
     RECT  48.949 3.648 48.985 15.528 ;
     RECT  48.947 35.856 48.985 38.232 ;
     RECT  48.913 16.656 48.989 20.856 ;
     RECT  48.521 24.912 48.989 26.904 ;
     RECT  48.563 1.728 49.025 1.8 ;
     RECT  48.989 18.72 49.025 20.856 ;
     RECT  48.665 33.024 49.043 34.488 ;
     RECT  48.985 35.664 49.061 38.232 ;
     RECT  48.949 58.608 49.093 60.408 ;
     RECT  49.025 18.768 49.097 20.856 ;
     RECT  49.043 33.408 49.097 34.488 ;
     RECT  48.917 51.072 49.097 51.288 ;
     RECT  48.755 0.096 49.205 0.216 ;
     RECT  49.097 34.464 49.205 34.488 ;
     RECT  48.949 55.248 49.237 57.096 ;
     RECT  49.093 58.128 49.237 60.408 ;
     RECT  48.601 48.192 49.273 48.984 ;
     RECT  49.061 35.664 49.283 35.688 ;
     RECT  49.205 0.192 49.313 0.216 ;
     RECT  48.593 86.064 49.313 86.28 ;
     RECT  48.593 64.32 49.345 84.984 ;
     RECT  48.947 39.312 49.453 43.512 ;
     RECT  48.953 44.976 49.453 45.24 ;
     RECT  48.125 27.936 49.489 28.44 ;
     RECT  47.729 23.328 49.493 23.352 ;
     RECT  48.985 2.88 49.525 15.528 ;
     RECT  49.025 1.728 49.529 1.752 ;
     RECT  49.061 36.672 49.571 38.232 ;
     RECT  49.345 63.792 49.573 84.984 ;
     RECT  49.313 86.064 49.573 86.184 ;
     RECT  49.097 18.96 49.597 20.856 ;
     RECT  49.489 27.936 49.621 28.728 ;
     RECT  48.593 30.336 49.621 31.32 ;
     RECT  49.597 18.96 49.669 21.096 ;
     RECT  48.661 22.08 49.669 22.104 ;
     RECT  49.571 36.768 49.709 38.232 ;
     RECT  49.573 63.792 49.709 86.184 ;
     RECT  49.237 55.248 49.777 60.408 ;
     RECT  49.309 61.584 49.777 61.608 ;
     RECT  49.525 2.736 49.781 15.528 ;
     RECT  49.525 54.096 49.868 54.12 ;
     RECT  49.777 55.248 49.868 61.608 ;
     RECT  49.868 54.096 50.005 61.608 ;
     RECT  48.881 62.736 50.005 62.76 ;
     RECT  49.621 27.936 50.029 31.368 ;
     RECT  50.005 54.096 50.173 62.76 ;
     RECT  49.709 63.792 50.173 84.984 ;
     RECT  50.173 54.096 50.245 84.984 ;
     RECT  49.597 23.904 50.281 23.928 ;
     RECT  48.989 24.912 50.281 24.936 ;
     RECT  49.709 85.968 50.309 86.184 ;
     RECT  50.309 85.968 50.393 86.28 ;
     RECT  50.393 85.968 50.435 86.184 ;
     RECT  49.669 18.96 50.569 22.104 ;
     RECT  49.781 2.736 50.581 9.816 ;
     RECT  49.417 46.224 50.605 46.248 ;
     RECT  49.273 48.192 50.605 49.032 ;
     RECT  49.097 33.408 50.629 33.432 ;
     RECT  49.849 34.944 50.629 34.968 ;
     RECT  50.281 23.904 50.677 24.936 ;
     RECT  50.029 27.936 50.677 31.752 ;
     RECT  48.377 52.464 50.677 52.488 ;
     RECT  50.245 54.048 50.713 84.984 ;
     RECT  50.435 85.968 50.713 86.136 ;
     RECT  48.989 16.656 50.749 17.736 ;
     RECT  50.569 18.96 50.749 22.536 ;
     RECT  50.749 16.656 50.857 22.536 ;
     RECT  49.709 36.768 50.869 38.184 ;
     RECT  49.453 39.312 50.869 45.24 ;
     RECT  50.869 36.768 50.893 45.24 ;
     RECT  50.605 46.224 50.893 49.032 ;
     RECT  50.713 54.048 50.915 86.136 ;
     RECT  49.781 10.848 50.929 15.528 ;
     RECT  50.857 16.608 50.929 22.536 ;
     RECT  50.915 85.392 50.956 86.136 ;
     RECT  50.581 2.256 51.008 9.816 ;
     RECT  50.929 10.848 51.008 22.536 ;
     RECT  50.677 23.856 51.008 24.936 ;
     RECT  48.989 26.112 51.008 26.904 ;
     RECT  50.677 27.936 51.008 31.944 ;
     RECT  50.629 33.264 51.008 34.968 ;
     RECT  50.893 36.768 51.008 49.032 ;
     RECT  49.097 51.264 51.008 51.288 ;
     RECT  50.677 52.464 51.008 52.872 ;
     RECT  50.915 54.048 51.008 84.408 ;
     RECT  51.008 2.148 51.112 84.408 ;
     RECT  51.112 2.418 51.304 84.408 ;
     RECT  51.304 39.264 51.365 46.248 ;
     RECT  51.304 2.736 51.443 29.496 ;
     RECT  51.304 36.384 51.443 38.184 ;
     RECT  50.956 85.488 51.493 86.136 ;
     RECT  51.304 54.048 51.725 84.408 ;
     RECT  51.493 85.488 51.827 86.232 ;
     RECT  51.304 47.328 51.833 48.984 ;
     RECT  51.725 54.048 51.971 58.728 ;
     RECT  51.833 48.432 52.013 48.984 ;
     RECT  51.827 85.968 52.045 86.232 ;
     RECT  51.725 59.76 52.069 84.408 ;
     RECT  51.443 2.736 52.085 23.112 ;
     RECT  52.085 2.736 52.157 20.712 ;
     RECT  51.443 25.056 52.163 29.496 ;
     RECT  51.971 54.624 52.163 58.728 ;
     RECT  51.365 39.264 52.259 46.008 ;
     RECT  51.304 30.864 52.297 31.896 ;
     RECT  51.443 36.384 52.301 37.512 ;
     RECT  52.259 40.416 52.301 46.008 ;
     RECT  52.157 2.736 52.445 20.136 ;
     RECT  51.304 51.984 52.453 53.064 ;
     RECT  52.297 30.624 52.517 31.896 ;
     RECT  51.304 33.264 52.553 33.72 ;
     RECT  52.163 25.056 52.589 25.08 ;
     RECT  52.163 55.152 52.693 58.728 ;
     RECT  52.069 59.76 52.693 84.936 ;
     RECT  52.445 19.872 52.769 19.896 ;
     RECT  52.693 55.152 52.813 84.936 ;
     RECT  52.517 30.768 52.837 31.896 ;
     RECT  52.553 33.6 52.837 33.72 ;
     RECT  52.813 55.152 52.913 84.36 ;
     RECT  52.045 85.968 52.933 86.28 ;
     RECT  51.833 47.328 52.94 47.448 ;
     RECT  52.013 48.432 52.94 48.504 ;
     RECT  52.085 21.792 52.945 23.112 ;
     RECT  52.301 40.56 52.981 46.008 ;
     RECT  52.94 47.328 52.981 48.504 ;
     RECT  52.981 40.56 53.027 48.504 ;
     RECT  52.913 55.152 53.057 63.816 ;
     RECT  52.163 26.784 53.093 29.496 ;
     RECT  53.027 48.48 53.093 48.504 ;
     RECT  53.093 28.272 53.125 29.496 ;
     RECT  52.453 51.984 53.125 53.592 ;
     RECT  53.057 55.152 53.129 63.288 ;
     RECT  52.259 39.264 53.161 39.336 ;
     RECT  52.445 2.736 53.165 18.888 ;
     RECT  52.837 30.768 53.171 32.088 ;
     RECT  53.165 2.736 53.201 9.384 ;
     RECT  53.027 40.56 53.201 47.352 ;
     RECT  53.125 28.272 53.219 29.688 ;
     RECT  52.945 21.792 53.269 23.16 ;
     RECT  53.161 38.496 53.273 39.336 ;
     RECT  53.273 39.264 53.309 39.336 ;
     RECT  53.201 40.56 53.345 46.824 ;
     RECT  53.053 24.432 53.381 24.456 ;
     RECT  53.161 50.592 53.417 50.616 ;
     RECT  53.093 26.784 53.449 27.144 ;
     RECT  52.837 33.6 53.449 34.2 ;
     RECT  53.125 51.984 53.449 54.072 ;
     RECT  53.129 60.24 53.459 63.288 ;
     RECT  52.301 37.056 53.485 37.512 ;
     RECT  53.345 40.56 53.485 45.48 ;
     RECT  53.345 46.8 53.489 46.824 ;
     RECT  52.933 85.44 53.555 86.28 ;
     RECT  53.269 20.976 53.557 23.16 ;
     RECT  53.449 33.6 53.596 34.536 ;
     RECT  53.449 26.208 53.629 27.144 ;
     RECT  53.219 28.272 53.633 28.488 ;
     RECT  53.449 51.696 53.633 54.072 ;
     RECT  53.485 39.888 53.669 45.48 ;
     RECT  53.633 53.808 53.705 54.072 ;
     RECT  53.129 55.152 53.747 59.256 ;
     RECT  53.485 37.056 53.773 38.184 ;
     RECT  53.459 60.24 53.813 63 ;
     RECT  53.557 20.88 53.845 23.16 ;
     RECT  53.171 30.912 53.957 32.088 ;
     RECT  53.165 10.368 54.061 18.888 ;
     RECT  54.061 10.368 54.097 19.128 ;
     RECT  53.845 20.496 54.097 23.16 ;
     RECT  53.219 29.472 54.133 29.688 ;
     RECT  53.957 30.912 54.133 31.896 ;
     RECT  52.913 65.28 54.133 84.36 ;
     RECT  53.555 86.064 54.145 86.28 ;
     RECT  53.629 26.112 54.277 27.144 ;
     RECT  53.633 28.272 54.277 28.296 ;
     RECT  53.596 34.176 54.277 34.536 ;
     RECT  54.169 35.52 54.277 35.544 ;
     RECT  53.773 37.008 54.277 38.184 ;
     RECT  53.201 2.976 54.313 9.384 ;
     RECT  54.097 10.368 54.313 19.32 ;
     RECT  54.097 20.352 54.313 23.16 ;
     RECT  53.669 40.32 54.313 45.48 ;
     RECT  54.133 64.128 54.371 84.936 ;
     RECT  54.313 2.976 54.385 19.32 ;
     RECT  53.747 57.312 54.493 59.256 ;
     RECT  53.813 60.24 54.493 62.568 ;
     RECT  54.371 64.272 54.497 84.936 ;
     RECT  54.497 64.368 54.533 84.936 ;
     RECT  54.385 2.976 54.601 19.368 ;
     RECT  54.313 20.352 54.601 23.976 ;
     RECT  54.277 34.176 54.637 38.184 ;
     RECT  53.633 51.696 54.673 52.392 ;
     RECT  53.705 53.808 54.673 53.832 ;
     RECT  54.601 2.976 54.677 23.976 ;
     RECT  54.313 40.32 54.713 45.576 ;
     RECT  54.713 41.376 54.749 45.576 ;
     RECT  54.277 26.112 54.757 28.296 ;
     RECT  54.757 25.68 54.781 28.296 ;
     RECT  54.133 29.472 54.781 31.896 ;
     RECT  54.493 57.312 54.817 62.568 ;
     RECT  54.673 50.784 54.821 52.392 ;
     RECT  54.533 64.752 54.853 84.936 ;
     RECT  54.145 86.064 54.853 86.232 ;
     RECT  54.677 3.696 54.929 23.976 ;
     RECT  54.929 9.504 55.001 23.976 ;
     RECT  54.781 25.68 55.037 31.896 ;
     RECT  54.821 50.784 55.037 52.296 ;
     RECT  54.749 41.952 55.069 45.576 ;
     RECT  54.637 34.128 55.073 38.184 ;
     RECT  55.037 51.216 55.073 52.296 ;
     RECT  54.853 64.752 55.145 86.232 ;
     RECT  55.037 25.68 55.177 25.704 ;
     RECT  55.073 51.456 55.181 52.296 ;
     RECT  54.673 53.76 55.181 53.832 ;
     RECT  55.073 35.52 55.213 38.184 ;
     RECT  55.037 26.736 55.283 31.896 ;
     RECT  55.177 25.056 55.285 25.704 ;
     RECT  55.213 35.52 55.285 38.52 ;
     RECT  53.747 55.152 55.285 56.088 ;
     RECT  55.285 24.48 55.325 25.704 ;
     RECT  55.285 35.52 55.388 38.568 ;
     RECT  55.069 41.952 55.397 46.152 ;
     RECT  54.817 57.312 55.397 63.096 ;
     RECT  55.073 34.128 55.433 34.152 ;
     RECT  55.501 33.84 55.537 33.864 ;
     RECT  54.929 3.696 55.645 8.184 ;
     RECT  55.145 85.92 55.676 86.232 ;
     RECT  55.397 58.608 55.813 63.096 ;
     RECT  55.145 64.752 55.813 84.936 ;
     RECT  54.713 40.32 55.969 40.344 ;
     RECT  55.676 85.92 55.973 86.28 ;
     RECT  55.325 25.68 56.077 25.704 ;
     RECT  55.283 26.736 56.077 29.544 ;
     RECT  55.388 35.52 56.185 38.664 ;
     RECT  55.001 9.504 56.221 23.304 ;
     RECT  55.325 24.48 56.221 24.504 ;
     RECT  55.181 51.456 56.257 52.2 ;
     RECT  55.283 30.816 56.365 31.896 ;
     RECT  55.537 33.552 56.365 33.864 ;
     RECT  55.645 2.832 56.408 8.184 ;
     RECT  56.221 9.504 56.408 24.504 ;
     RECT  56.077 25.68 56.408 29.544 ;
     RECT  56.365 30.816 56.408 33.864 ;
     RECT  56.185 35.52 56.408 39 ;
     RECT  55.969 40.32 56.408 40.584 ;
     RECT  55.397 41.952 56.408 44.76 ;
     RECT  55.397 46.128 56.408 46.152 ;
     RECT  56.257 49.872 56.408 49.896 ;
     RECT  56.257 51.456 56.408 52.248 ;
     RECT  55.181 53.808 56.408 53.832 ;
     RECT  55.285 55.152 56.408 56.28 ;
     RECT  55.397 57.312 56.408 57.576 ;
     RECT  55.813 58.608 56.408 84.936 ;
     RECT  56.408 2.148 56.512 84.936 ;
     RECT  56.512 2.418 56.704 84.936 ;
     RECT  56.704 26.832 56.819 34.2 ;
     RECT  56.704 35.28 56.819 39.384 ;
     RECT  56.704 49.056 56.837 49.08 ;
     RECT  56.704 55.152 56.867 56.28 ;
     RECT  56.704 61.872 56.869 84.936 ;
     RECT  55.973 85.92 56.869 86.184 ;
     RECT  56.704 3.072 56.981 24.216 ;
     RECT  56.869 61.872 57.011 86.184 ;
     RECT  56.704 47.664 57.017 47.688 ;
     RECT  56.819 26.832 57.053 31.416 ;
     RECT  56.704 51.456 57.125 53.928 ;
     RECT  56.704 58.416 57.148 60.84 ;
     RECT  56.819 35.376 57.197 39.24 ;
     RECT  56.704 44.352 57.233 44.376 ;
     RECT  56.704 57.312 57.233 57.336 ;
     RECT  57.011 61.872 57.233 84.36 ;
     RECT  57.125 51.984 57.269 53.928 ;
     RECT  57.053 26.832 57.341 31.128 ;
     RECT  57.011 85.536 57.349 86.184 ;
     RECT  56.819 32.688 57.532 34.2 ;
     RECT  57.532 34.176 57.601 34.2 ;
     RECT  57.233 61.872 57.629 83.928 ;
     RECT  57.629 63.216 57.665 83.928 ;
     RECT  57.197 35.52 57.731 39.24 ;
     RECT  57.148 60.336 57.769 60.84 ;
     RECT  57.629 61.872 57.769 61.992 ;
     RECT  56.981 22.8 57.773 24.216 ;
     RECT  57.269 52.032 57.845 53.928 ;
     RECT  56.981 3.072 57.881 21.528 ;
     RECT  57.731 35.52 57.881 36.696 ;
     RECT  56.704 41.088 57.913 43.32 ;
     RECT  57.881 3.12 57.917 21.528 ;
     RECT  57.917 19.248 57.923 21.528 ;
     RECT  57.349 85.536 57.925 86.232 ;
     RECT  57.845 53.664 57.953 53.928 ;
     RECT  57.913 40.608 57.98 43.32 ;
     RECT  57.665 64.32 57.989 83.928 ;
     RECT  57.148 58.416 58.021 58.728 ;
     RECT  57.925 85.536 58.021 86.28 ;
     RECT  57.773 22.8 58.025 23.832 ;
     RECT  58.021 85.488 58.025 86.28 ;
     RECT  57.341 29.472 58.057 31.128 ;
     RECT  58.057 29.472 58.097 31.56 ;
     RECT  58.021 58.128 58.105 58.728 ;
     RECT  57.769 60.336 58.117 61.992 ;
     RECT  57.697 25.68 58.129 25.704 ;
     RECT  57.98 40.608 58.204 43.752 ;
     RECT  57.917 3.12 58.241 17.688 ;
     RECT  57.341 26.832 58.241 28.488 ;
     RECT  58.241 3.168 58.277 17.688 ;
     RECT  58.105 58.656 58.309 58.728 ;
     RECT  57.953 53.904 58.313 53.928 ;
     RECT  58.097 30.912 58.345 31.56 ;
     RECT  57.532 32.688 58.345 33.192 ;
     RECT  58.277 3.168 58.349 8.808 ;
     RECT  58.129 25.056 58.381 25.704 ;
     RECT  58.241 26.832 58.381 26.904 ;
     RECT  57.665 63.216 58.421 63.24 ;
     RECT  57.881 35.52 58.453 36.312 ;
     RECT  58.204 40.56 58.453 43.752 ;
     RECT  58.381 25.056 58.493 26.904 ;
     RECT  58.025 85.488 58.501 86.232 ;
     RECT  57.697 34.368 58.525 34.392 ;
     RECT  58.453 35.472 58.525 36.312 ;
     RECT  56.867 55.152 58.525 56.088 ;
     RECT  58.241 28.368 58.561 28.488 ;
     RECT  58.097 29.472 58.561 29.544 ;
     RECT  58.117 60.288 58.561 61.992 ;
     RECT  57.845 52.032 58.633 52.392 ;
     RECT  58.309 58.656 58.633 59.112 ;
     RECT  58.561 60.096 58.633 61.992 ;
     RECT  58.633 51.984 58.705 52.392 ;
     RECT  57.989 64.944 58.709 83.928 ;
     RECT  58.345 30.912 58.721 33.192 ;
     RECT  58.633 58.656 58.741 61.992 ;
     RECT  58.025 23.808 58.777 23.832 ;
     RECT  58.493 25.056 58.777 26.376 ;
     RECT  58.025 22.8 58.781 22.824 ;
     RECT  58.525 34.368 58.781 36.312 ;
     RECT  58.709 65.376 58.809 83.928 ;
     RECT  58.705 51.888 58.817 52.392 ;
     RECT  58.561 28.368 58.853 29.544 ;
     RECT  58.349 3.168 58.889 7.128 ;
     RECT  57.949 49.536 58.889 49.56 ;
     RECT  58.721 30.912 58.931 33.24 ;
     RECT  58.501 85.44 58.931 86.232 ;
     RECT  58.453 40.56 58.961 43.848 ;
     RECT  58.809 65.952 58.981 83.928 ;
     RECT  57.923 19.248 58.993 21.384 ;
     RECT  58.981 65.952 58.997 84.36 ;
     RECT  58.931 86.016 59.036 86.232 ;
     RECT  58.277 10.08 59.101 17.688 ;
     RECT  58.961 42.816 59.105 43.848 ;
     RECT  59.101 10.08 59.137 18.024 ;
     RECT  58.993 19.248 59.137 21.96 ;
     RECT  58.931 31.68 59.141 33.24 ;
     RECT  58.525 55.152 59.209 56.904 ;
     RECT  59.036 86.016 59.219 86.28 ;
     RECT  58.349 8.16 59.281 8.808 ;
     RECT  59.137 10.08 59.281 21.96 ;
     RECT  58.817 51.888 59.357 52.344 ;
     RECT  59.173 30.576 59.497 30.6 ;
     RECT  59.105 42.816 59.555 43.512 ;
     RECT  59.281 8.16 59.573 21.96 ;
     RECT  59.209 55.152 59.573 57.576 ;
     RECT  58.777 23.808 59.605 26.376 ;
     RECT  59.555 42.96 59.651 43.512 ;
     RECT  58.781 34.368 59.677 35.496 ;
     RECT  59.573 57.168 59.717 57.576 ;
     RECT  59.573 13.536 59.825 21.96 ;
     RECT  58.889 3.408 59.857 7.128 ;
     RECT  59.605 23.808 59.857 26.52 ;
     RECT  59.857 2.736 59.893 7.128 ;
     RECT  59.573 8.16 59.893 12.456 ;
     RECT  59.357 51.888 59.893 52.2 ;
     RECT  59.825 13.584 59.897 21.96 ;
     RECT  59.497 30.192 59.941 30.6 ;
     RECT  59.141 31.68 59.941 33.048 ;
     RECT  59.509 64.08 60.001 64.104 ;
     RECT  59.941 30.192 60.028 33.048 ;
     RECT  57.731 37.728 60.037 39.24 ;
     RECT  58.961 40.56 60.037 41.784 ;
     RECT  59.677 34.032 60.073 35.496 ;
     RECT  58.741 58.656 60.077 62.712 ;
     RECT  60.073 34.032 60.173 36.12 ;
     RECT  59.573 55.152 60.179 56.088 ;
     RECT  60.077 58.656 60.179 62.472 ;
     RECT  59.897 13.68 60.221 21.96 ;
     RECT  58.853 28.368 60.236 28.968 ;
     RECT  60.173 34.032 60.257 36.456 ;
     RECT  60.257 34.032 60.275 36.12 ;
     RECT  60.037 37.728 60.275 41.784 ;
     RECT  59.857 23.808 60.293 26.856 ;
     RECT  60.236 28.368 60.323 29.496 ;
     RECT  59.651 43.056 60.325 43.512 ;
     RECT  60.028 30.576 60.329 33.048 ;
     RECT  60.329 33.024 60.397 33.048 ;
     RECT  60.275 34.032 60.397 35.496 ;
     RECT  60.289 54.096 60.397 54.12 ;
     RECT  60.293 23.808 60.467 24.552 ;
     RECT  58.997 66 60.467 84.36 ;
     RECT  60.421 22.752 60.469 22.776 ;
     RECT  60.221 13.68 60.473 21.624 ;
     RECT  60.397 33.024 60.473 35.496 ;
     RECT  59.219 86.16 60.509 86.28 ;
     RECT  60.397 54.096 60.577 54.36 ;
     RECT  60.179 56.016 60.649 56.088 ;
     RECT  59.717 57.168 60.649 57.192 ;
     RECT  60.467 24.528 60.689 24.552 ;
     RECT  60.293 25.728 60.812 26.856 ;
     RECT  59.893 2.736 60.833 12.456 ;
     RECT  60.812 25.728 60.853 26.952 ;
     RECT  60.323 28.368 60.853 29.208 ;
     RECT  60.275 37.968 60.865 41.784 ;
     RECT  60.325 43.056 60.865 43.944 ;
     RECT  59.893 51.648 60.937 52.2 ;
     RECT  60.509 86.16 60.941 86.232 ;
     RECT  60.467 66.816 61.013 84.36 ;
     RECT  60.001 64.08 61.045 64.872 ;
     RECT  61.013 66.816 61.049 84.264 ;
     RECT  60.865 37.968 61.081 43.944 ;
     RECT  61.052 44.976 61.081 45 ;
     RECT  61.045 64.08 61.189 64.968 ;
     RECT  61.081 37.968 61.292 45 ;
     RECT  60.941 86.16 61.301 86.184 ;
     RECT  60.853 25.728 61.441 29.208 ;
     RECT  60.329 30.576 61.441 31.8 ;
     RECT  60.469 22.752 61.513 23.544 ;
     RECT  60.973 48.96 61.513 48.984 ;
     RECT  61.513 48.384 61.549 48.984 ;
     RECT  61.292 37.248 61.628 45 ;
     RECT  61.513 22.464 61.657 23.544 ;
     RECT  60.833 2.832 61.669 12.456 ;
     RECT  60.473 13.68 61.669 21.24 ;
     RECT  60.973 46.464 61.693 46.488 ;
     RECT  61.549 48.384 61.729 49.032 ;
     RECT  60.721 50.112 61.729 50.136 ;
     RECT  61.628 36.72 61.765 45 ;
     RECT  61.189 63.6 61.801 64.968 ;
     RECT  61.693 1.728 61.808 1.752 ;
     RECT  61.669 2.832 61.808 21.24 ;
     RECT  61.657 22.464 61.808 24.12 ;
     RECT  61.441 25.728 61.808 31.8 ;
     RECT  60.473 33.024 61.808 35.448 ;
     RECT  61.765 36.72 61.808 45.192 ;
     RECT  61.693 46.464 61.808 47.16 ;
     RECT  61.729 48.384 61.808 50.136 ;
     RECT  60.937 51.648 61.808 52.296 ;
     RECT  60.577 53.328 61.808 54.36 ;
     RECT  60.649 56.016 61.808 57.192 ;
     RECT  60.179 58.704 61.808 62.472 ;
     RECT  61.801 63.6 61.808 65.16 ;
     RECT  61.049 66.816 61.808 84.252 ;
     RECT  61.808 1.728 62.045 84.252 ;
     RECT  62.045 1.728 62.099 84.36 ;
     RECT  62.099 2.304 62.104 84.36 ;
     RECT  62.104 84.336 62.129 84.36 ;
     RECT  62.104 44.736 62.165 52.296 ;
     RECT  62.104 76.944 62.165 83.016 ;
     RECT  62.165 44.736 62.201 52.056 ;
     RECT  62.104 53.328 62.201 53.352 ;
     RECT  62.104 67.68 62.237 71.112 ;
     RECT  62.104 74.352 62.237 75.72 ;
     RECT  62.165 76.944 62.237 82.536 ;
     RECT  62.237 74.4 62.243 75.72 ;
     RECT  62.237 76.944 62.243 81.624 ;
     RECT  62.243 76.944 62.245 77.928 ;
     RECT  62.104 8.16 62.273 17.448 ;
     RECT  62.243 78.96 62.273 81.624 ;
     RECT  62.245 77.04 62.309 77.928 ;
     RECT  62.104 58.128 62.345 63.624 ;
     RECT  62.201 45.168 62.524 52.056 ;
     RECT  62.524 51.648 62.525 52.056 ;
     RECT  62.237 69.504 62.525 71.112 ;
     RECT  62.243 74.4 62.525 74.424 ;
     RECT  62.104 24.096 62.561 27.624 ;
     RECT  62.524 45.168 62.561 50.376 ;
     RECT  62.345 58.128 62.561 63.24 ;
     RECT  62.243 75.696 62.561 75.72 ;
     RECT  62.273 78.96 62.561 81.48 ;
     RECT  62.104 42.192 62.669 43.32 ;
     RECT  62.104 65.136 62.675 65.16 ;
     RECT  62.561 24.096 62.705 26.856 ;
     RECT  62.104 55.968 62.705 56.28 ;
     RECT  62.309 77.04 62.705 77.4 ;
     RECT  62.705 24.096 62.741 26.808 ;
     RECT  62.104 2.304 62.777 6.84 ;
     RECT  62.561 45.552 62.777 50.376 ;
     RECT  62.705 77.136 62.813 77.4 ;
     RECT  62.525 69.984 62.885 71.112 ;
     RECT  62.561 78.96 62.885 80.568 ;
     RECT  62.104 28.656 62.921 36.936 ;
     RECT  62.669 42.192 62.921 43.08 ;
     RECT  62.561 58.752 62.921 63.24 ;
     RECT  62.885 71.088 62.957 71.112 ;
     RECT  62.921 33.12 62.993 35.88 ;
     RECT  62.885 69.984 63.065 70.008 ;
     RECT  62.885 79.2 63.065 80.568 ;
     RECT  62.104 40.032 63.068 40.056 ;
     RECT  62.705 55.968 63.097 56.136 ;
     RECT  62.777 2.64 63.101 6.84 ;
     RECT  62.104 18.96 63.101 22.776 ;
     RECT  62.921 62.4 63.137 63.24 ;
     RECT  62.921 28.656 63.155 31.704 ;
     RECT  63.068 39.072 63.155 40.056 ;
     RECT  63.155 40.032 63.173 40.056 ;
     RECT  62.813 77.376 63.173 77.4 ;
     RECT  62.921 36.912 63.205 36.936 ;
     RECT  63.101 18.96 63.245 20.664 ;
     RECT  63.155 28.656 63.245 28.968 ;
     RECT  62.777 45.744 63.245 50.376 ;
     RECT  63.205 36.912 63.289 37.656 ;
     RECT  62.273 8.16 63.317 14.52 ;
     RECT  63.317 11.76 63.353 14.52 ;
     RECT  63.101 21.648 63.353 22.776 ;
     RECT  62.993 34.896 63.353 35.88 ;
     RECT  63.245 46.032 63.353 50.376 ;
     RECT  63.137 62.448 63.389 63.24 ;
     RECT  63.353 46.032 63.425 50.136 ;
     RECT  63.065 80.544 63.425 80.568 ;
     RECT  63.425 46.224 63.461 50.136 ;
     RECT  63.317 8.16 63.491 10.632 ;
     RECT  63.289 36.912 63.497 36.936 ;
     RECT  63.065 79.2 63.533 79.224 ;
     RECT  63.245 19.536 63.569 20.664 ;
     RECT  63.155 30.24 63.569 31.704 ;
     RECT  63.353 34.896 63.569 34.92 ;
     RECT  63.097 55.248 63.569 56.136 ;
     RECT  63.101 6.144 63.637 6.84 ;
     RECT  63.491 8.16 63.637 10.152 ;
     RECT  63.245 28.656 63.637 28.68 ;
     RECT  62.237 67.68 63.637 68.184 ;
     RECT  63.101 2.64 63.641 5.112 ;
     RECT  62.741 24.48 63.673 26.808 ;
     RECT  63.353 21.648 63.677 22.488 ;
     RECT  63.569 30.816 63.677 31.704 ;
     RECT  63.673 24.48 63.683 26.904 ;
     RECT  63.637 27.888 63.683 28.68 ;
     RECT  62.525 51.648 63.709 51.912 ;
     RECT  63.683 26.784 63.745 26.904 ;
     RECT  63.683 27.888 63.745 27.912 ;
     RECT  63.709 51.648 63.781 52.44 ;
     RECT  62.921 58.752 63.781 61.08 ;
     RECT  63.745 26.784 63.785 27.912 ;
     RECT  63.461 46.224 63.857 50.088 ;
     RECT  63.857 46.224 63.893 47.16 ;
     RECT  63.817 69.552 63.901 69.576 ;
     RECT  63.637 67.68 63.965 68.376 ;
     RECT  63.641 2.64 63.997 5.016 ;
     RECT  63.997 1.776 64.001 5.016 ;
     RECT  63.785 26.88 64.001 27.912 ;
     RECT  62.273 15.6 64.033 17.448 ;
     RECT  64.001 1.776 64.069 1.8 ;
     RECT  63.677 21.648 64.109 21.672 ;
     RECT  63.389 62.448 64.109 62.472 ;
     RECT  64.033 15.312 64.141 17.448 ;
     RECT  63.353 11.76 64.145 13.752 ;
     RECT  62.104 66.192 64.145 66.216 ;
     RECT  64.069 1.728 64.211 1.8 ;
     RECT  63.683 24.48 64.217 25.224 ;
     RECT  63.965 67.68 64.217 67.848 ;
     RECT  63.677 30.864 64.249 31.704 ;
     RECT  64.001 2.832 64.253 5.016 ;
     RECT  63.569 20.304 64.285 20.664 ;
     RECT  62.993 33.12 64.285 33.144 ;
     RECT  64.285 33.12 64.289 33.48 ;
     RECT  63.853 0.576 64.307 0.6 ;
     RECT  63.781 51.168 64.325 52.44 ;
     RECT  64.249 30.864 64.429 31.8 ;
     RECT  64.217 67.68 64.429 67.704 ;
     RECT  64.253 2.88 64.433 5.016 ;
     RECT  64.217 24.48 64.433 25.032 ;
     RECT  64.211 1.728 64.441 1.752 ;
     RECT  63.781 58.464 64.465 61.08 ;
     RECT  64.465 57.648 64.501 61.08 ;
     RECT  64.105 63.648 64.537 63.672 ;
     RECT  64.285 20.304 64.577 21.432 ;
     RECT  64.429 30.864 64.645 32.376 ;
     RECT  64.501 54.72 64.649 54.744 ;
     RECT  63.637 6.144 64.717 10.152 ;
     RECT  64.145 13.68 64.741 13.752 ;
     RECT  64.141 15.312 64.741 17.88 ;
     RECT  64.145 11.76 64.787 12.552 ;
     RECT  64.741 13.68 64.789 14.088 ;
     RECT  64.741 15.072 64.789 17.88 ;
     RECT  64.001 26.88 64.789 27.384 ;
     RECT  63.857 48.672 64.789 50.088 ;
     RECT  64.325 51.168 64.789 51.336 ;
     RECT  64.789 13.68 64.825 17.88 ;
     RECT  64.645 34.752 64.825 34.92 ;
     RECT  64.825 13.68 64.861 18.264 ;
     RECT  64.285 37.536 64.897 37.56 ;
     RECT  63.569 56.016 64.897 56.136 ;
     RECT  64.501 57.168 64.901 61.08 ;
     RECT  64.537 40.992 64.933 41.928 ;
     RECT  64.897 55.152 64.933 56.136 ;
     RECT  64.789 48.672 64.937 51.336 ;
     RECT  64.901 57.168 64.937 57.192 ;
     RECT  64.901 58.368 64.937 61.08 ;
     RECT  64.789 26.688 64.969 27.384 ;
     RECT  64.937 58.368 64.979 58.392 ;
     RECT  64.969 26.64 64.981 28.008 ;
     RECT  64.717 6.144 65.009 10.728 ;
     RECT  64.861 13.68 65.027 19.176 ;
     RECT  64.645 30.192 65.027 32.376 ;
     RECT  64.289 33.456 65.081 33.48 ;
     RECT  64.433 2.88 65.117 4.776 ;
     RECT  64.937 60.288 65.153 61.08 ;
     RECT  64.933 55.152 65.185 56.184 ;
     RECT  65.117 2.88 65.189 4.296 ;
     RECT  64.897 37.536 65.189 38.424 ;
     RECT  64.937 48.672 65.221 50.088 ;
     RECT  64.577 20.304 65.225 21.288 ;
     RECT  65.221 48.288 65.257 50.088 ;
     RECT  63.925 70.752 65.269 70.776 ;
     RECT  64.933 40.992 65.297 42.024 ;
     RECT  65.269 70.464 65.297 70.776 ;
     RECT  63.709 72.144 65.297 72.168 ;
     RECT  65.189 2.88 65.329 4.248 ;
     RECT  65.297 70.464 65.356 70.488 ;
     RECT  62.921 43.056 65.365 43.08 ;
     RECT  64.325 52.416 65.365 52.44 ;
     RECT  64.357 44.448 65.372 44.472 ;
     RECT  64.937 51.168 65.401 51.336 ;
     RECT  65.365 52.416 65.401 52.488 ;
     RECT  65.372 44.352 65.459 44.472 ;
     RECT  65.009 8.4 65.473 10.728 ;
     RECT  64.787 11.76 65.473 12.216 ;
     RECT  65.401 51.168 65.507 52.488 ;
     RECT  65.221 46.128 65.513 46.152 ;
     RECT  64.501 69.312 65.513 69.336 ;
     RECT  65.185 55.152 65.555 57.096 ;
     RECT  63.893 47.136 65.617 47.16 ;
     RECT  64.981 26.64 65.621 28.824 ;
     RECT  65.473 8.4 65.657 12.216 ;
     RECT  65.555 57.072 65.693 57.096 ;
     RECT  65.027 30.72 65.729 32.376 ;
     RECT  65.257 48.192 65.729 50.088 ;
     RECT  64.177 39.792 65.761 39.816 ;
     RECT  65.729 48.96 65.765 50.088 ;
     RECT  65.555 55.152 65.797 56.088 ;
     RECT  65.459 44.448 65.801 44.472 ;
     RECT  65.297 41.664 65.804 42.024 ;
     RECT  65.365 43.056 65.804 43.368 ;
     RECT  64.433 25.008 65.825 25.032 ;
     RECT  64.861 35.952 65.825 35.976 ;
     RECT  65.825 35.952 65.833 36.504 ;
     RECT  65.189 37.536 65.833 37.56 ;
     RECT  65.797 54.672 65.833 56.088 ;
     RECT  65.833 35.952 65.837 37.56 ;
     RECT  65.765 48.96 65.873 49.464 ;
     RECT  65.804 41.664 65.891 43.368 ;
     RECT  65.657 10.656 65.905 12.216 ;
     RECT  65.825 25.008 65.909 25.08 ;
     RECT  65.225 20.64 65.941 21.288 ;
     RECT  65.729 31.776 65.945 32.376 ;
     RECT  65.617 46.176 65.945 47.16 ;
     RECT  65.948 58.512 65.977 58.536 ;
     RECT  65.977 57.888 66.035 58.536 ;
     RECT  65.941 20.64 66.049 22.056 ;
     RECT  66.035 57.888 66.061 57.912 ;
     RECT  65.507 51.168 66.083 51.912 ;
     RECT  65.945 46.464 66.085 47.16 ;
     RECT  66.085 46.464 66.089 47.592 ;
     RECT  65.153 61.056 66.121 61.08 ;
     RECT  66.121 61.056 66.149 61.416 ;
     RECT  65.581 71.808 66.161 71.832 ;
     RECT  66.149 60.48 66.181 61.416 ;
     RECT  66.049 20.64 66.197 22.104 ;
     RECT  66.301 33.072 66.325 33.096 ;
     RECT  64.825 34.656 66.325 34.92 ;
     RECT  65.329 2.784 66.373 4.248 ;
     RECT  66.197 20.64 66.373 22.056 ;
     RECT  65.891 42.768 66.481 43.368 ;
     RECT  66.373 20.352 66.517 22.056 ;
     RECT  64.537 63.456 66.517 64.056 ;
     RECT  66.121 73.344 66.517 73.368 ;
     RECT  66.373 2.256 66.553 4.248 ;
     RECT  65.009 6.144 66.553 7.368 ;
     RECT  66.181 60.48 66.553 61.464 ;
     RECT  66.553 60.384 66.589 61.464 ;
     RECT  65.941 24.432 66.625 24.456 ;
     RECT  65.621 26.64 66.625 28.536 ;
     RECT  66.589 59.76 66.625 61.464 ;
     RECT  66.517 73.344 66.661 73.944 ;
     RECT  66.553 2.256 66.697 4.584 ;
     RECT  66.553 6.144 66.697 7.416 ;
     RECT  66.697 5.808 66.709 7.416 ;
     RECT  65.657 8.4 66.709 9.672 ;
     RECT  65.891 41.664 66.733 41.688 ;
     RECT  65.729 30.72 66.769 30.792 ;
     RECT  66.089 47.568 66.841 47.592 ;
     RECT  65.873 48.96 66.841 48.984 ;
     RECT  66.517 70.128 66.841 70.152 ;
     RECT  66.709 5.808 66.885 9.672 ;
     RECT  65.905 10.656 66.885 12.552 ;
     RECT  65.761 38.928 66.913 39.816 ;
     RECT  66.625 26.64 66.985 28.728 ;
     RECT  66.913 38.256 67.021 39.816 ;
     RECT  65.509 53.568 67.045 53.592 ;
     RECT  66.841 69.984 67.057 70.152 ;
     RECT  66.661 0.096 67.093 0.12 ;
     RECT  66.697 1.728 67.093 4.584 ;
     RECT  66.885 5.808 67.093 12.552 ;
     RECT  65.027 13.68 67.093 18.552 ;
     RECT  66.517 19.968 67.093 22.056 ;
     RECT  66.481 42.768 67.093 43.848 ;
     RECT  67.045 53.088 67.093 53.592 ;
     RECT  65.837 35.952 67.129 36.936 ;
     RECT  67.021 37.968 67.129 39.816 ;
     RECT  66.089 46.464 67.129 46.488 ;
     RECT  66.908 65.904 67.165 65.928 ;
     RECT  64.429 67.392 67.165 67.704 ;
     RECT  66.661 72.432 67.165 73.944 ;
     RECT  67.057 75.12 67.165 75.144 ;
     RECT  67.093 1.728 67.208 18.552 ;
     RECT  67.093 19.872 67.208 22.056 ;
     RECT  66.625 23.568 67.208 24.456 ;
     RECT  66.409 25.44 67.208 25.464 ;
     RECT  66.985 26.64 67.208 28.776 ;
     RECT  66.769 30.672 67.208 30.792 ;
     RECT  65.945 31.776 67.208 31.896 ;
     RECT  66.325 33.072 67.208 34.92 ;
     RECT  67.129 35.952 67.208 39.816 ;
     RECT  66.733 41.328 67.208 41.688 ;
     RECT  67.093 42.768 67.208 44.76 ;
     RECT  67.129 46.032 67.208 46.488 ;
     RECT  66.841 47.568 67.208 48.984 ;
     RECT  66.083 51.168 67.208 51.24 ;
     RECT  67.093 52.992 67.208 53.592 ;
     RECT  65.833 54.576 67.208 56.088 ;
     RECT  66.625 59.184 67.208 61.464 ;
     RECT  66.517 63.456 67.208 64.392 ;
     RECT  67.165 65.904 67.208 67.704 ;
     RECT  66.517 68.928 67.208 68.952 ;
     RECT  67.057 69.984 67.208 71.112 ;
     RECT  67.165 72.432 67.208 75.144 ;
     RECT  67.093 0.096 67.237 0.168 ;
     RECT  67.208 1.728 67.237 84.252 ;
     RECT  67.237 0.096 67.312 84.252 ;
     RECT  67.312 0.096 67.385 83.982 ;
     RECT  67.385 1.728 67.504 83.982 ;
     RECT  67.504 54.96 67.601 56.088 ;
     RECT  67.385 0.096 67.619 0.216 ;
     RECT  67.504 3.6 67.619 8.04 ;
     RECT  67.504 51.072 67.619 51.384 ;
     RECT  67.504 60 67.619 61.128 ;
     RECT  67.504 49.488 67.667 49.512 ;
     RECT  67.504 10.176 67.673 26.808 ;
     RECT  67.619 4.848 67.709 8.04 ;
     RECT  67.619 51.072 67.709 51.24 ;
     RECT  67.504 33.264 67.715 43.848 ;
     RECT  67.715 33.264 67.717 40.392 ;
     RECT  67.717 35.328 67.745 40.392 ;
     RECT  67.504 58.272 67.763 59.016 ;
     RECT  67.619 60 67.781 60.408 ;
     RECT  67.673 12.96 67.811 26.808 ;
     RECT  67.715 41.52 67.811 43.848 ;
     RECT  67.504 45.168 67.852 46.2 ;
     RECT  67.781 60 67.853 60.312 ;
     RECT  67.504 66.576 67.859 75.672 ;
     RECT  67.601 55.152 67.925 56.088 ;
     RECT  67.859 71.088 67.925 75.672 ;
     RECT  67.619 0.096 67.961 0.12 ;
     RECT  67.745 39.792 67.961 40.392 ;
     RECT  67.811 12.96 67.997 25.464 ;
     RECT  67.504 48.384 67.997 48.408 ;
     RECT  67.853 60 67.997 60.024 ;
     RECT  67.852 46.032 68.105 46.2 ;
     RECT  67.763 58.656 68.141 59.016 ;
     RECT  67.811 26.64 68.147 26.808 ;
     RECT  67.925 55.872 68.285 56.088 ;
     RECT  67.745 35.328 68.321 38.808 ;
     RECT  67.504 1.728 68.357 2.28 ;
     RECT  67.997 12.96 68.357 25.128 ;
     RECT  68.357 1.728 68.393 2.232 ;
     RECT  67.859 66.576 68.393 70.104 ;
     RECT  68.393 1.776 68.429 2.232 ;
     RECT  67.504 52.704 68.429 53.592 ;
     RECT  68.429 1.776 68.465 1.8 ;
     RECT  67.709 5.136 68.465 8.04 ;
     RECT  68.321 38.112 68.465 38.808 ;
     RECT  68.429 52.704 68.497 52.968 ;
     RECT  67.925 71.808 68.497 75.672 ;
     RECT  67.619 3.6 68.533 3.72 ;
     RECT  68.357 16.08 68.537 25.128 ;
     RECT  68.285 56.016 68.537 56.088 ;
     RECT  67.717 33.264 68.588 34.344 ;
     RECT  68.105 46.128 68.609 46.2 ;
     RECT  68.537 23.76 68.627 25.128 ;
     RECT  67.504 27.984 68.675 32.232 ;
     RECT  68.321 35.328 68.675 36.936 ;
     RECT  67.673 10.176 68.677 11.976 ;
     RECT  68.357 12.96 68.677 14.952 ;
     RECT  68.141 58.704 68.677 59.016 ;
     RECT  68.675 35.328 68.681 36.552 ;
     RECT  68.588 33.216 68.725 34.344 ;
     RECT  68.681 35.328 68.725 36.264 ;
     RECT  68.609 46.176 68.749 46.2 ;
     RECT  68.393 66.72 68.761 70.104 ;
     RECT  68.725 33.216 68.771 36.264 ;
     RECT  68.761 66.72 68.771 69.144 ;
     RECT  67.811 41.664 68.785 43.08 ;
     RECT  68.677 10.176 68.789 14.952 ;
     RECT  68.749 45.024 68.833 45.048 ;
     RECT  68.533 3.408 68.857 3.72 ;
     RECT  68.537 16.08 68.861 22.488 ;
     RECT  68.497 71.808 68.861 76.056 ;
     RECT  68.675 27.984 68.897 31.08 ;
     RECT  68.537 56.016 68.897 56.04 ;
     RECT  68.897 29.808 68.915 31.08 ;
     RECT  68.465 5.712 68.917 8.04 ;
     RECT  68.857 3.36 68.929 3.72 ;
     RECT  68.861 21.744 68.963 22.488 ;
     RECT  68.861 16.08 68.969 20.376 ;
     RECT  68.963 22.32 68.969 22.488 ;
     RECT  68.497 52.416 68.969 52.968 ;
     RECT  68.897 27.984 69.077 28.728 ;
     RECT  68.861 71.808 69.113 74.712 ;
     RECT  68.675 32.208 69.181 32.232 ;
     RECT  68.771 33.216 69.181 34.392 ;
     RECT  68.785 41.376 69.185 43.08 ;
     RECT  68.785 49.008 69.185 49.032 ;
     RECT  67.709 51.072 69.217 51.096 ;
     RECT  69.113 71.808 69.217 74.616 ;
     RECT  68.929 3.36 69.221 4.68 ;
     RECT  68.749 46.176 69.253 47.064 ;
     RECT  67.961 39.792 69.293 40.2 ;
     RECT  69.217 51.072 69.325 51.336 ;
     RECT  68.969 52.416 69.325 52.44 ;
     RECT  68.917 5.712 69.437 8.856 ;
     RECT  68.915 29.808 69.437 30.84 ;
     RECT  68.627 24.48 69.469 25.128 ;
     RECT  69.437 6.144 69.541 8.856 ;
     RECT  68.789 10.176 69.541 11.208 ;
     RECT  68.771 66.72 69.581 68.904 ;
     RECT  68.861 76.032 69.581 76.056 ;
     RECT  69.289 62.592 69.613 62.616 ;
     RECT  68.465 38.112 69.617 38.136 ;
     RECT  69.581 67.392 69.617 68.904 ;
     RECT  69.253 46.176 69.649 47.736 ;
     RECT  69.613 62.592 69.649 62.76 ;
     RECT  69.541 6.144 69.653 11.208 ;
     RECT  69.437 30.672 69.653 30.84 ;
     RECT  68.789 12.24 69.689 14.952 ;
     RECT  68.677 58.704 69.761 59.208 ;
     RECT  69.649 62.256 69.761 62.76 ;
     RECT  69.649 46.176 69.793 48.36 ;
     RECT  69.325 51.072 69.793 52.44 ;
     RECT  68.969 22.464 69.829 22.488 ;
     RECT  69.221 3.696 69.833 4.68 ;
     RECT  69.181 32.208 69.869 34.392 ;
     RECT  69.793 45.312 69.869 48.36 ;
     RECT  69.761 58.704 69.973 58.728 ;
     RECT  69.653 6.144 69.977 10.008 ;
     RECT  68.969 16.08 69.977 19.272 ;
     RECT  69.793 50.88 69.977 52.44 ;
     RECT  69.869 33.648 70.009 34.392 ;
     RECT  69.973 58.656 70.009 58.728 ;
     RECT  69.761 62.592 70.013 62.76 ;
     RECT  69.617 67.392 70.019 68.28 ;
     RECT  69.689 12.72 70.045 14.952 ;
     RECT  69.977 16.08 70.045 18.984 ;
     RECT  69.469 24.48 70.045 25.8 ;
     RECT  68.147 26.784 70.045 26.808 ;
     RECT  69.077 28.032 70.045 28.728 ;
     RECT  68.821 64.608 70.045 64.632 ;
     RECT  69.653 11.184 70.081 11.208 ;
     RECT  70.045 12.72 70.085 18.984 ;
     RECT  70.019 67.584 70.121 68.28 ;
     RECT  69.185 42.192 70.163 43.08 ;
     RECT  68.771 36.096 70.261 36.264 ;
     RECT  69.469 53.52 70.265 53.544 ;
     RECT  69.829 22.464 70.297 22.728 ;
     RECT  69.977 51.072 70.301 52.44 ;
     RECT  69.977 6.144 70.373 8.856 ;
     RECT  70.357 75.936 70.481 75.96 ;
     RECT  70.297 22.176 70.549 22.728 ;
     RECT  70.261 35.856 70.549 36.264 ;
     RECT  70.009 33.648 70.585 34.44 ;
     RECT  69.293 40.176 70.589 40.2 ;
     RECT  70.045 24.48 70.621 26.808 ;
     RECT  70.045 28.032 70.621 29.16 ;
     RECT  69.361 49.536 70.621 49.56 ;
     RECT  70.621 24.48 70.657 29.16 ;
     RECT  70.477 69.792 70.657 69.816 ;
     RECT  69.217 71.568 70.693 74.616 ;
     RECT  70.585 33.648 70.697 34.488 ;
     RECT  70.549 35.856 70.697 36.792 ;
     RECT  70.693 71.52 70.697 74.616 ;
     RECT  70.549 75.744 70.697 75.768 ;
     RECT  70.621 49.536 70.733 49.608 ;
     RECT  70.081 11.184 70.765 11.544 ;
     RECT  70.085 12.72 70.765 12.744 ;
     RECT  70.013 62.592 70.769 62.712 ;
     RECT  69.973 5.04 70.837 5.064 ;
     RECT  69.977 9.984 70.837 10.008 ;
     RECT  70.765 11.184 70.837 12.744 ;
     RECT  70.301 52.416 70.837 52.44 ;
     RECT  70.549 22.176 70.873 23.016 ;
     RECT  70.765 41.184 70.877 41.208 ;
     RECT  70.657 69.456 70.909 69.816 ;
     RECT  70.837 9.984 70.913 12.744 ;
     RECT  70.913 11.52 70.949 12.744 ;
     RECT  70.733 49.584 70.949 49.608 ;
     RECT  69.721 38.16 70.981 38.184 ;
     RECT  69.973 66.096 70.981 66.12 ;
     RECT  70.121 67.584 70.981 67.608 ;
     RECT  70.657 24.48 70.985 29.352 ;
     RECT  69.653 30.816 71.017 30.84 ;
     RECT  69.869 32.208 71.017 32.616 ;
     RECT  70.045 64.608 71.017 64.776 ;
     RECT  70.981 66.096 71.017 67.608 ;
     RECT  70.909 69.456 71.021 70.008 ;
     RECT  70.837 5.04 71.053 5.16 ;
     RECT  70.373 6.144 71.053 8.28 ;
     RECT  70.085 14.112 71.053 18.984 ;
     RECT  70.985 24.48 71.057 28.536 ;
     RECT  69.869 47.712 71.093 48.36 ;
     RECT  70.585 60.96 71.125 60.984 ;
     RECT  71.125 60.96 71.129 61.896 ;
     RECT  70.913 9.984 71.161 10.44 ;
     RECT  69.869 45.312 71.197 46.728 ;
     RECT  70.873 39.888 71.221 39.912 ;
     RECT  70.837 52.416 71.228 52.488 ;
     RECT  71.221 39.312 71.267 39.912 ;
     RECT  69.833 3.696 71.269 3.72 ;
     RECT  71.053 5.04 71.269 8.28 ;
     RECT  70.301 51.072 71.269 51.096 ;
     RECT  70.729 55.44 71.269 55.464 ;
     RECT  70.009 57.84 71.269 58.728 ;
     RECT  71.057 28.416 71.273 28.536 ;
     RECT  71.267 39.312 71.308 39.336 ;
     RECT  70.873 22.176 71.309 23.352 ;
     RECT  71.057 24.48 71.309 27.432 ;
     RECT  71.269 57.84 71.333 59.256 ;
     RECT  71.333 57.6 71.353 59.256 ;
     RECT  71.269 3.696 71.377 8.28 ;
     RECT  71.017 64.608 71.42 67.608 ;
     RECT  70.697 36.768 71.453 36.792 ;
     RECT  71.017 30.816 71.485 32.616 ;
     RECT  71.129 61.872 71.507 61.896 ;
     RECT  71.42 63.984 71.507 67.608 ;
     RECT  71.053 14.112 71.509 19.32 ;
     RECT  71.485 20.4 71.509 20.424 ;
     RECT  71.309 23.328 71.525 23.352 ;
     RECT  71.377 3.696 71.561 8.328 ;
     RECT  71.509 14.112 71.596 20.424 ;
     RECT  71.485 30.336 71.629 32.616 ;
     RECT  70.697 33.648 71.629 34.44 ;
     RECT  70.163 42.192 71.629 42.216 ;
     RECT  70.981 38.112 71.653 38.184 ;
     RECT  71.629 30.24 71.737 34.44 ;
     RECT  71.561 5.136 71.773 8.328 ;
     RECT  71.228 52.416 71.948 53.4 ;
     RECT  71.273 28.512 71.953 28.536 ;
     RECT  71.737 30.24 71.953 35.304 ;
     RECT  71.629 42.192 71.989 42.264 ;
     RECT  71.269 51.072 71.989 51.288 ;
     RECT  71.021 69.984 72.025 70.008 ;
     RECT  71.948 52.416 72.061 53.976 ;
     RECT  71.269 55.392 72.061 55.464 ;
     RECT  72.025 69.312 72.061 70.008 ;
     RECT  70.697 71.52 72.061 74.472 ;
     RECT  70.949 11.952 72.097 12.744 ;
     RECT  71.773 5.136 72.133 8.52 ;
     RECT  71.353 57.6 72.133 59.064 ;
     RECT  72.133 5.136 72.169 8.568 ;
     RECT  71.161 9.84 72.169 10.44 ;
     RECT  72.097 11.952 72.169 12.84 ;
     RECT  72.061 52.416 72.169 55.464 ;
     RECT  71.989 50.976 72.181 51.288 ;
     RECT  72.169 52.416 72.181 55.512 ;
     RECT  72.181 50.976 72.236 55.512 ;
     RECT  71.197 45.264 72.277 47.352 ;
     RECT  71.989 60.432 72.277 60.456 ;
     RECT  71.653 38.112 72.349 38.712 ;
     RECT  71.989 42.192 72.373 42.744 ;
     RECT  72.169 11.952 72.385 12.888 ;
     RECT  71.596 14.112 72.385 19.368 ;
     RECT  72.236 50.688 72.421 55.512 ;
     RECT  71.309 25.68 72.457 27.432 ;
     RECT  71.953 28.512 72.457 35.304 ;
     RECT  72.373 41.28 72.457 42.84 ;
     RECT  72.349 49.008 72.457 49.032 ;
     RECT  72.421 50.016 72.457 55.512 ;
     RECT  71.701 56.544 72.469 56.568 ;
     RECT  71.309 22.176 72.493 22.2 ;
     RECT  72.457 49.008 72.493 55.512 ;
     RECT  72.469 56.496 72.493 56.568 ;
     RECT  72.277 60.288 72.529 60.456 ;
     RECT  71.9 23.808 72.565 23.976 ;
     RECT  72.349 38.112 72.565 39.24 ;
     RECT  72.457 40.32 72.565 42.84 ;
     RECT  71.561 3.696 72.608 3.72 ;
     RECT  72.169 5.136 72.608 10.44 ;
     RECT  72.385 11.952 72.608 19.368 ;
     RECT  71.596 20.4 72.608 20.424 ;
     RECT  72.493 21.792 72.608 22.2 ;
     RECT  72.565 23.808 72.608 24.504 ;
     RECT  72.457 25.68 72.608 35.304 ;
     RECT  72.565 38.112 72.608 42.84 ;
     RECT  72.277 44.976 72.608 47.88 ;
     RECT  72.493 49.008 72.608 56.568 ;
     RECT  72.133 57.552 72.608 59.064 ;
     RECT  72.529 60.288 72.608 60.6 ;
     RECT  71.507 64.368 72.608 67.608 ;
     RECT  72.061 69.312 72.608 74.472 ;
     RECT  72.608 2.148 72.712 84.252 ;
     RECT  72.712 2.418 72.904 83.982 ;
     RECT  72.904 26.784 72.929 42.84 ;
     RECT  72.929 34.896 73.037 42.84 ;
     RECT  72.904 52.464 73.073 52.488 ;
     RECT  72.904 17.472 73.081 25.8 ;
     RECT  72.904 5.664 73.109 9.912 ;
     RECT  73.081 17.472 73.109 17.736 ;
     RECT  72.904 60.288 73.145 60.312 ;
     RECT  72.904 69.312 73.145 69.336 ;
     RECT  72.904 44.976 73.181 47.304 ;
     RECT  72.904 66.576 73.187 67.704 ;
     RECT  72.904 11.952 73.217 16.44 ;
     RECT  73.109 17.472 73.217 17.496 ;
     RECT  73.187 66.72 73.225 67.704 ;
     RECT  73.037 34.896 73.253 39.528 ;
     RECT  72.904 49.104 73.253 49.224 ;
     RECT  73.109 9.072 73.469 9.912 ;
     RECT  73.037 40.656 73.469 42.84 ;
     RECT  73.109 5.664 73.613 7.752 ;
     RECT  73.081 18.816 73.613 25.8 ;
     RECT  73.181 45.552 73.613 47.304 ;
     RECT  72.904 54.096 73.619 55.56 ;
     RECT  72.904 57.024 73.619 59.304 ;
     RECT  73.613 19.296 73.649 25.8 ;
     RECT  73.469 40.8 73.667 42.84 ;
     RECT  73.613 46.752 73.685 47.304 ;
     RECT  73.619 58.656 73.721 59.304 ;
     RECT  73.667 41.616 73.757 42.84 ;
     RECT  73.253 49.104 73.757 49.128 ;
     RECT  72.929 26.784 73.793 33.336 ;
     RECT  73.217 12.528 73.829 16.44 ;
     RECT  73.649 19.296 73.865 23.928 ;
     RECT  73.619 57.024 73.897 57.144 ;
     RECT  73.619 54.576 73.933 55.56 ;
     RECT  73.897 56.688 73.933 57.144 ;
     RECT  72.904 64.368 73.933 65.352 ;
     RECT  72.904 75.792 73.964 75.816 ;
     RECT  73.225 67.68 73.973 67.704 ;
     RECT  73.757 41.856 74.041 42.84 ;
     RECT  73.964 75.792 74.051 75.912 ;
     RECT  72.904 72.432 74.077 74.04 ;
     RECT  73.685 46.752 74.099 46.872 ;
     RECT  74.041 41.856 74.113 43.32 ;
     RECT  74.077 71.184 74.149 74.04 ;
     RECT  73.613 45.552 74.153 45.576 ;
     RECT  74.099 46.752 74.153 46.776 ;
     RECT  73.933 54.576 74.153 57.144 ;
     RECT  74.149 70.8 74.204 74.04 ;
     RECT  73.793 26.784 74.261 32.952 ;
     RECT  74.113 41.856 74.261 43.944 ;
     RECT  74.261 41.856 74.291 42.84 ;
     RECT  74.204 70.416 74.291 74.04 ;
     RECT  74.261 29.616 74.333 32.952 ;
     RECT  74.291 70.8 74.369 74.04 ;
     RECT  74.329 48.432 74.401 48.456 ;
     RECT  74.185 60.288 74.401 60.312 ;
     RECT  73.829 12.528 74.405 14.28 ;
     RECT  74.153 55.392 74.405 57.144 ;
     RECT  73.933 64.32 74.405 65.352 ;
     RECT  74.329 0.576 74.413 0.6 ;
     RECT  72.904 3.696 74.441 3.72 ;
     RECT  74.291 41.856 74.477 42.6 ;
     RECT  74.405 55.392 74.477 56.712 ;
     RECT  74.369 70.8 74.477 71.304 ;
     RECT  74.369 72.432 74.477 74.04 ;
     RECT  73.469 9.888 74.509 9.912 ;
     RECT  73.649 25.056 74.509 25.8 ;
     RECT  74.261 26.784 74.509 28.44 ;
     RECT  74.401 48.192 74.549 48.456 ;
     RECT  74.477 70.8 74.549 71.208 ;
     RECT  73.613 6.144 74.581 7.752 ;
     RECT  74.365 50.928 74.581 50.952 ;
     RECT  74.509 25.056 74.629 28.44 ;
     RECT  73.721 59.28 74.629 59.304 ;
     RECT  74.401 60.288 74.629 61.224 ;
     RECT  74.581 6.144 74.653 7.8 ;
     RECT  74.509 9.648 74.677 9.912 ;
     RECT  74.549 48.432 74.693 48.456 ;
     RECT  74.677 9.648 74.723 10.296 ;
     RECT  74.333 29.616 74.729 29.784 ;
     RECT  74.549 71.184 74.801 71.208 ;
     RECT  74.245 34.08 74.977 34.104 ;
     RECT  73.253 35.136 74.977 39.528 ;
     RECT  74.477 41.856 74.977 42.552 ;
     RECT  73.829 15.36 75.013 16.44 ;
     RECT  74.581 50.112 75.013 50.952 ;
     RECT  74.723 10.272 75.017 10.296 ;
     RECT  74.405 12.528 75.017 14.136 ;
     RECT  73.865 19.296 75.017 23.544 ;
     RECT  74.629 59.28 75.017 61.224 ;
     RECT  75.013 15.36 75.049 17.064 ;
     RECT  74.185 18.24 75.049 18.264 ;
     RECT  74.477 72.72 75.197 74.04 ;
     RECT  74.477 55.392 75.229 56.328 ;
     RECT  75.085 53.568 75.253 53.592 ;
     RECT  75.229 55.152 75.253 56.328 ;
     RECT  75.017 19.488 75.269 23.544 ;
     RECT  74.629 24.864 75.269 28.44 ;
     RECT  74.977 34.08 75.269 39.528 ;
     RECT  74.869 69.456 75.373 69.48 ;
     RECT  75.017 12.528 75.409 13.08 ;
     RECT  74.653 6.144 75.449 8.424 ;
     RECT  75.269 21.12 75.449 23.544 ;
     RECT  74.405 64.608 75.481 65.352 ;
     RECT  75.013 50.112 75.485 51.192 ;
     RECT  75.485 50.832 75.521 51.192 ;
     RECT  75.017 59.28 75.521 60.408 ;
     RECT  74.333 30.768 75.553 32.952 ;
     RECT  75.049 15.36 75.557 18.264 ;
     RECT  75.449 23.136 75.557 23.544 ;
     RECT  74.653 58.128 75.557 58.152 ;
     RECT  75.269 36.48 75.589 39.528 ;
     RECT  74.261 43.824 75.593 43.944 ;
     RECT  75.521 59.28 75.625 59.592 ;
     RECT  75.253 53.568 75.661 56.328 ;
     RECT  75.269 26.064 75.733 28.44 ;
     RECT  74.729 29.76 75.733 29.784 ;
     RECT  75.017 14.112 75.769 14.136 ;
     RECT  75.481 64.608 75.773 65.544 ;
     RECT  75.769 14.112 75.781 14.28 ;
     RECT  75.557 15.36 75.781 16.008 ;
     RECT  75.661 53.568 75.781 56.52 ;
     RECT  75.557 17.04 75.805 18.264 ;
     RECT  75.773 64.752 75.805 65.544 ;
     RECT  74.077 67.824 75.805 67.848 ;
     RECT  75.805 67.728 75.845 67.848 ;
     RECT  75.373 68.928 75.845 69.48 ;
     RECT  75.845 67.728 75.913 67.752 ;
     RECT  75.449 8.4 75.917 8.424 ;
     RECT  75.409 24.672 75.917 24.696 ;
     RECT  75.449 6.144 75.949 7.368 ;
     RECT  75.197 73.344 75.953 74.04 ;
     RECT  74.977 41.616 75.985 42.552 ;
     RECT  75.781 53.568 75.989 57.48 ;
     RECT  75.781 14.112 76.025 16.008 ;
     RECT  75.449 21.12 76.025 21.672 ;
     RECT  75.557 23.136 76.025 23.16 ;
     RECT  75.553 30.768 76.025 33.048 ;
     RECT  75.913 66.816 76.025 67.752 ;
     RECT  75.517 71.808 76.025 71.832 ;
     RECT  75.989 53.568 76.061 57.288 ;
     RECT  76.061 54.432 76.067 57.288 ;
     RECT  75.805 64.752 76.093 65.592 ;
     RECT  75.953 74.016 76.133 74.04 ;
     RECT  75.805 17.04 76.169 18.504 ;
     RECT  75.985 41.616 76.201 43.176 ;
     RECT  76.201 40.992 76.273 43.176 ;
     RECT  75.949 5.184 76.313 7.368 ;
     RECT  75.985 70.656 76.345 70.68 ;
     RECT  75.733 26.064 76.381 29.784 ;
     RECT  75.269 35.136 76.417 35.256 ;
     RECT  75.589 36.48 76.417 39.72 ;
     RECT  76.381 25.728 76.421 29.784 ;
     RECT  75.625 58.656 76.501 59.592 ;
     RECT  76.46 60.768 76.501 60.792 ;
     RECT  76.025 21.12 76.529 21.528 ;
     RECT  76.345 69.84 76.529 70.68 ;
     RECT  76.501 58.656 76.547 60.792 ;
     RECT  75.269 19.488 76.561 20.136 ;
     RECT  76.421 27.12 76.565 29.784 ;
     RECT  76.273 40.8 76.705 43.176 ;
     RECT  76.021 44.256 76.705 44.28 ;
     RECT  75.521 50.832 76.741 50.856 ;
     RECT  76.561 19.344 76.777 20.136 ;
     RECT  76.529 21.12 76.777 21.48 ;
     RECT  76.057 24.624 76.777 24.648 ;
     RECT  76.705 40.8 76.781 44.28 ;
     RECT  76.093 64.752 76.787 65.976 ;
     RECT  76.741 50.784 76.853 50.856 ;
     RECT  76.313 6.816 76.876 7.368 ;
     RECT  76.025 30.816 76.889 33.048 ;
     RECT  76.853 50.832 76.925 50.856 ;
     RECT  76.025 15.504 76.961 15.528 ;
     RECT  76.169 17.04 76.961 18.168 ;
     RECT  75.269 34.08 76.993 34.104 ;
     RECT  76.417 35.136 76.993 39.72 ;
     RECT  76.025 67.728 76.993 67.752 ;
     RECT  76.777 19.344 76.997 21.48 ;
     RECT  76.565 27.12 76.997 27.24 ;
     RECT  76.067 54.432 77.029 56.664 ;
     RECT  76.781 42.528 77.033 44.28 ;
     RECT  76.129 10.608 77.137 10.632 ;
     RECT  75.409 11.856 77.137 13.08 ;
     RECT  77.029 54.432 77.137 56.76 ;
     RECT  76.777 23.904 77.173 24.648 ;
     RECT  76.421 25.728 77.173 25.752 ;
     RECT  76.889 32.928 77.173 33.048 ;
     RECT  76.993 34.08 77.173 39.72 ;
     RECT  76.813 52.944 77.209 52.968 ;
     RECT  76.025 14.112 77.245 14.28 ;
     RECT  77.137 54.432 77.245 56.856 ;
     RECT  76.547 58.656 77.245 59.832 ;
     RECT  77.137 10.608 77.281 13.08 ;
     RECT  77.245 14.112 77.281 14.472 ;
     RECT  77.101 71.664 77.461 71.688 ;
     RECT  76.993 67.728 77.557 67.8 ;
     RECT  76.885 63.36 77.605 63.384 ;
     RECT  77.173 23.904 77.677 25.752 ;
     RECT  76.961 17.04 77.749 17.688 ;
     RECT  77.677 23.424 77.749 25.752 ;
     RECT  76.529 69.84 77.749 69.864 ;
     RECT  77.209 52.944 77.785 53.016 ;
     RECT  76.787 65.28 77.785 65.976 ;
     RECT  77.749 69.792 77.785 69.864 ;
     RECT  76.565 28.224 77.893 29.784 ;
     RECT  77.173 32.928 77.893 39.72 ;
     RECT  76.781 40.8 77.893 41.016 ;
     RECT  77.821 47.856 77.893 47.88 ;
     RECT  77.785 64.656 77.893 65.976 ;
     RECT  76.889 30.816 77.929 31.944 ;
     RECT  77.893 32.928 77.929 41.016 ;
     RECT  77.029 72.96 77.965 72.984 ;
     RECT  76.313 5.184 78.008 5.208 ;
     RECT  76.876 7.344 78.008 7.368 ;
     RECT  77.029 9.408 78.008 9.432 ;
     RECT  77.281 10.608 78.008 14.472 ;
     RECT  77.749 16.656 78.008 17.688 ;
     RECT  76.997 19.344 78.008 21.144 ;
     RECT  77.893 22.224 78.008 22.248 ;
     RECT  77.749 23.424 78.008 26.616 ;
     RECT  77.893 27.6 78.008 29.784 ;
     RECT  77.929 30.816 78.008 41.016 ;
     RECT  77.033 42.528 78.008 43.848 ;
     RECT  76.021 45.264 78.008 45.288 ;
     RECT  77.893 47.856 78.008 47.928 ;
     RECT  77.749 51.168 78.008 51.192 ;
     RECT  77.785 52.944 78.008 53.064 ;
     RECT  77.245 54.432 78.008 59.832 ;
     RECT  77.605 63.024 78.008 63.384 ;
     RECT  77.893 64.656 78.008 66.024 ;
     RECT  77.557 67.488 78.008 67.8 ;
     RECT  77.785 69.312 78.008 69.864 ;
     RECT  77.461 71.664 78.008 71.784 ;
     RECT  77.965 72.96 78.008 73.272 ;
     RECT  78.008 2.148 78.112 84.252 ;
     RECT  78.112 2.418 78.304 83.982 ;
     RECT  78.304 34.08 78.329 39.096 ;
     RECT  78.304 64.656 78.329 69.816 ;
     RECT  78.304 54.432 78.365 58.68 ;
     RECT  78.304 59.712 78.401 59.832 ;
     RECT  78.329 34.08 78.437 39.048 ;
     RECT  78.304 47.856 78.437 47.88 ;
     RECT  78.304 49.008 78.437 49.032 ;
     RECT  78.329 64.992 78.437 69.816 ;
     RECT  78.304 23.856 78.473 26.232 ;
     RECT  78.365 54.432 78.473 58.152 ;
     RECT  78.304 61.968 78.473 61.992 ;
     RECT  78.304 40.848 78.545 45.048 ;
     RECT  78.304 12.528 78.581 22.248 ;
     RECT  78.473 23.904 78.581 26.232 ;
     RECT  78.581 23.904 78.653 25.032 ;
     RECT  78.545 40.992 78.653 45.048 ;
     RECT  78.581 16.128 78.689 22.248 ;
     RECT  78.304 27.312 78.725 32.76 ;
     RECT  78.473 54.432 78.755 57.624 ;
     RECT  78.725 30.624 78.797 31.896 ;
     RECT  78.755 54.432 78.797 56.232 ;
     RECT  78.437 34.08 78.833 38.76 ;
     RECT  78.653 41.712 78.833 45.048 ;
     RECT  78.304 50.832 78.833 51.336 ;
     RECT  78.304 63.024 78.833 63.384 ;
     RECT  78.833 41.712 78.869 42.552 ;
     RECT  78.797 54.912 78.941 56.232 ;
     RECT  78.833 63.36 78.941 63.384 ;
     RECT  78.833 50.832 78.977 51 ;
     RECT  78.653 24.096 79.013 25.032 ;
     RECT  78.725 27.312 79.013 29.352 ;
     RECT  78.941 55.968 79.013 56.232 ;
     RECT  78.581 13.536 79.049 14.808 ;
     RECT  78.869 42.192 79.049 42.552 ;
     RECT  78.833 43.68 79.085 45.048 ;
     RECT  78.304 7.344 79.091 7.368 ;
     RECT  78.304 10.272 79.132 10.824 ;
     RECT  78.581 12.528 79.157 12.552 ;
     RECT  79.132 10.752 79.165 10.824 ;
     RECT  79.013 28.464 79.229 29.352 ;
     RECT  79.049 13.536 79.265 14.712 ;
     RECT  78.304 71.664 79.333 71.688 ;
     RECT  78.304 72.912 79.333 73.272 ;
     RECT  78.689 16.128 79.337 21.768 ;
     RECT  79.013 27.312 79.337 27.432 ;
     RECT  79.085 44.448 79.337 45.048 ;
     RECT  78.833 34.08 79.405 38.28 ;
     RECT  79.013 24.096 79.409 24.648 ;
     RECT  78.437 65.136 79.441 69.816 ;
     RECT  79.337 27.408 79.445 27.432 ;
     RECT  78.755 57.312 79.445 57.624 ;
     RECT  79.333 71.664 79.445 73.272 ;
     RECT  79.441 64.992 79.513 69.816 ;
     RECT  79.513 64.992 79.589 70.296 ;
     RECT  79.445 71.664 79.589 72.936 ;
     RECT  78.941 54.912 79.625 54.936 ;
     RECT  78.401 59.712 79.657 59.736 ;
     RECT  79.513 61.008 79.657 61.032 ;
     RECT  79.589 65.136 79.661 70.296 ;
     RECT  78.581 26.064 79.693 26.232 ;
     RECT  79.337 17.328 79.729 21.768 ;
     RECT  79.729 17.328 79.733 22.248 ;
     RECT  79.405 33.648 79.733 38.28 ;
     RECT  79.733 19.344 79.813 22.248 ;
     RECT  79.657 59.712 79.985 61.032 ;
     RECT  79.661 65.424 79.985 70.296 ;
     RECT  79.265 13.632 80.017 14.712 ;
     RECT  79.733 36.816 80.021 38.28 ;
     RECT  79.549 47.808 80.057 47.832 ;
     RECT  79.049 42.192 80.089 42.216 ;
     RECT  79.733 33.648 80.129 35.784 ;
     RECT  80.017 13.632 80.149 14.904 ;
     RECT  79.337 16.128 80.149 16.152 ;
     RECT  80.089 42.192 80.161 42.792 ;
     RECT  80.149 13.632 80.195 16.152 ;
     RECT  79.985 65.424 80.201 68.376 ;
     RECT  80.161 42.144 80.233 42.792 ;
     RECT  80.195 13.632 80.236 16.008 ;
     RECT  79.229 29.232 80.305 29.352 ;
     RECT  78.304 53.04 80.305 53.304 ;
     RECT  80.305 52.32 80.309 53.304 ;
     RECT  79.985 59.712 80.309 60.264 ;
     RECT  79.733 17.328 80.341 18.168 ;
     RECT  80.233 42.144 80.341 43.32 ;
     RECT  79.337 45.024 80.341 45.048 ;
     RECT  79.693 50.784 80.417 50.808 ;
     RECT  80.309 52.32 80.453 52.344 ;
     RECT  80.236 13.632 80.485 14.904 ;
     RECT  80.201 65.808 80.489 68.376 ;
     RECT  80.485 13.584 80.525 14.904 ;
     RECT  79.985 69.792 80.525 70.296 ;
     RECT  80.341 41.952 80.597 45.048 ;
     RECT  79.165 10.752 80.633 10.776 ;
     RECT  80.485 27.312 80.633 27.336 ;
     RECT  80.597 41.952 80.633 42.888 ;
     RECT  80.197 39.504 80.669 39.528 ;
     RECT  80.341 17.136 80.773 18.168 ;
     RECT  79.813 19.344 80.773 21.288 ;
     RECT  80.269 62.64 80.773 62.664 ;
     RECT  80.773 17.136 80.813 21.288 ;
     RECT  80.489 66.528 80.813 68.376 ;
     RECT  79.729 23.376 80.821 23.4 ;
     RECT  79.409 24.624 80.821 24.648 ;
     RECT  79.693 25.68 80.821 26.232 ;
     RECT  80.813 19.488 80.849 21.288 ;
     RECT  78.797 30.912 80.849 31.896 ;
     RECT  79.477 57.984 80.881 58.008 ;
     RECT  79.589 71.664 80.881 72.408 ;
     RECT  80.813 17.136 80.915 18.408 ;
     RECT  80.849 30.912 80.917 30.936 ;
     RECT  80.129 33.648 80.921 35.736 ;
     RECT  79.909 40.56 80.921 40.584 ;
     RECT  80.633 42.144 80.957 42.84 ;
     RECT  79.013 55.968 80.957 55.992 ;
     RECT  80.821 23.376 80.963 26.232 ;
     RECT  80.021 36.816 80.993 38.232 ;
     RECT  80.917 30.816 81.029 30.936 ;
     RECT  81.029 30.912 81.037 30.936 ;
     RECT  80.921 34.128 81.065 35.736 ;
     RECT  80.963 23.376 81.101 24.648 ;
     RECT  80.849 21.12 81.133 21.288 ;
     RECT  80.993 38.016 81.157 38.232 ;
     RECT  80.597 44.064 81.203 45.048 ;
     RECT  81.101 23.376 81.205 23.784 ;
     RECT  80.773 62.64 81.205 62.856 ;
     RECT  80.305 29.232 81.209 29.832 ;
     RECT  80.525 69.792 81.209 69.816 ;
     RECT  81.209 29.376 81.245 29.832 ;
     RECT  81.205 62.64 81.245 63.24 ;
     RECT  81.205 22.8 81.251 23.784 ;
     RECT  80.881 57.024 81.277 58.008 ;
     RECT  80.309 59.712 81.277 59.736 ;
     RECT  80.813 67.776 81.353 68.376 ;
     RECT  80.963 25.68 81.389 26.232 ;
     RECT  81.277 57.024 81.389 59.736 ;
     RECT  80.881 71.616 81.5 72.408 ;
     RECT  81.133 21.12 81.533 21.528 ;
     RECT  81.5 71.616 81.541 72.648 ;
     RECT  81.541 70.656 81.587 72.648 ;
     RECT  80.525 13.584 81.605 13.608 ;
     RECT  81.245 63.216 81.605 63.24 ;
     RECT  81.587 70.656 81.605 71.688 ;
     RECT  81.389 25.68 81.641 25.992 ;
     RECT  80.525 14.88 81.677 14.904 ;
     RECT  80.849 19.488 81.781 19.608 ;
     RECT  80.236 15.984 81.788 16.008 ;
     RECT  81.781 19.392 81.829 19.608 ;
     RECT  81.533 21.12 81.829 21.288 ;
     RECT  81.788 15.312 81.875 16.008 ;
     RECT  81.529 64.944 81.884 64.968 ;
     RECT  81.025 50.88 81.893 50.904 ;
     RECT  81.829 19.392 81.916 21.288 ;
     RECT  81.884 64.944 81.925 65.064 ;
     RECT  81.875 15.984 81.929 16.008 ;
     RECT  81.845 33.024 81.929 33.048 ;
     RECT  81.601 61.968 81.929 61.992 ;
     RECT  81.925 64.656 81.971 65.064 ;
     RECT  81.971 64.656 82.009 64.68 ;
     RECT  81.853 63.456 82.033 63.48 ;
     RECT  81.157 38.016 82.069 38.664 ;
     RECT  80.813 66.528 82.069 66.744 ;
     RECT  81.389 57.024 82.073 58.968 ;
     RECT  81.457 69.504 82.073 69.528 ;
     RECT  80.993 36.816 82.105 36.84 ;
     RECT  82.073 57.552 82.109 58.968 ;
     RECT  81.203 44.064 82.145 44.472 ;
     RECT  81.605 70.656 82.145 70.68 ;
     RECT  81.997 52.896 82.177 52.92 ;
     RECT  82.105 36.816 82.181 36.984 ;
     RECT  82.033 63.456 82.181 64.056 ;
     RECT  82.181 36.96 82.213 36.984 ;
     RECT  82.069 38.016 82.213 39.048 ;
     RECT  80.915 17.136 82.217 17.688 ;
     RECT  81.457 49.008 82.253 49.032 ;
     RECT  81.605 71.664 82.325 71.688 ;
     RECT  82.177 52.848 82.393 52.92 ;
     RECT  82.181 63.456 82.433 63.48 ;
     RECT  82.357 47.856 82.501 47.88 ;
     RECT  82.501 47.664 82.681 47.88 ;
     RECT  82.069 66 82.681 66.744 ;
     RECT  81.353 67.776 82.681 67.8 ;
     RECT  81.251 22.8 82.753 22.824 ;
     RECT  82.717 50.928 82.825 50.952 ;
     RECT  81.916 19.392 82.897 19.56 ;
     RECT  82.753 22.8 82.933 23.352 ;
     RECT  82.825 50.928 82.969 51.192 ;
     RECT  82.609 61.872 82.969 61.896 ;
     RECT  82.105 60.432 83.084 60.456 ;
     RECT  82.969 61.872 83.18 62.232 ;
     RECT  83.084 60.384 83.257 60.456 ;
     RECT  80.957 42.144 83.329 42.168 ;
     RECT  83.329 42.144 83.365 43.128 ;
     RECT  82.217 17.136 83.408 17.16 ;
     RECT  82.897 19.056 83.408 19.56 ;
     RECT  81.916 21.264 83.408 21.288 ;
     RECT  82.933 22.752 83.408 23.352 ;
     RECT  82.501 24.384 83.408 24.408 ;
     RECT  81.641 25.968 83.408 25.992 ;
     RECT  81.245 29.376 83.408 29.448 ;
     RECT  82.681 30.96 83.408 30.984 ;
     RECT  81.065 34.128 83.408 35.352 ;
     RECT  82.213 36.96 83.408 39.048 ;
     RECT  83.365 41.952 83.408 43.128 ;
     RECT  82.681 46.8 83.408 47.88 ;
     RECT  82.969 50.688 83.408 51.192 ;
     RECT  82.393 52.848 83.408 52.968 ;
     RECT  82.109 57.552 83.408 57.576 ;
     RECT  83.257 59.472 83.408 60.456 ;
     RECT  83.18 61.488 83.408 62.232 ;
     RECT  82.681 66 83.408 67.8 ;
     RECT  83.408 2.148 83.512 84.252 ;
     RECT  83.512 2.418 83.704 83.982 ;
     RECT  83.704 41.952 83.729 41.976 ;
    LAYER M5 ;
     RECT  19.44 0.016 26.28 0.131 ;
     RECT  32.496 0.016 35.496 0.131 ;
     RECT  19.536 0.131 26.28 0.179 ;
     RECT  32.592 0.131 35.496 0.611 ;
     RECT  32.688 0.611 35.496 0.659 ;
     RECT  19.728 0.179 26.28 1.187 ;
     RECT  19.824 1.187 26.28 1.763 ;
     RECT  45.552 0.016 49.512 1.763 ;
     RECT  64.08 0.016 64.392 1.763 ;
     RECT  67.056 0.016 68.424 1.763 ;
     RECT  20.208 1.763 21.864 1.811 ;
     RECT  32.784 0.659 35.496 1.811 ;
     RECT  64.176 1.763 64.2 1.811 ;
     RECT  67.2 1.763 68.424 1.811 ;
     RECT  23.472 1.763 26.28 1.859 ;
     RECT  45.6 1.763 49.416 1.907 ;
     RECT  2.4 2.137 2.52 2.151 ;
     RECT  7.8 2.137 7.92 2.151 ;
     RECT  13.2 2.137 13.32 2.151 ;
     RECT  18.6 2.137 18.72 2.151 ;
     RECT  29.4 2.137 29.52 2.151 ;
     RECT  40.2 2.137 40.32 2.151 ;
     RECT  51 2.137 51.12 2.151 ;
     RECT  56.4 2.137 56.52 2.151 ;
     RECT  61.8 2.137 62.088 2.151 ;
     RECT  72.6 2.137 72.72 2.151 ;
     RECT  78 2.137 78.12 2.151 ;
     RECT  83.4 2.137 83.52 2.151 ;
     RECT  23.472 1.859 24.504 2.243 ;
     RECT  67.2 1.811 68.232 2.243 ;
     RECT  13.2 2.151 13.512 2.245 ;
     RECT  32.784 1.811 33.384 2.245 ;
     RECT  51 2.151 51.312 2.245 ;
     RECT  31.872 2.245 33.384 2.291 ;
     RECT  34.512 1.811 35.304 2.291 ;
     RECT  31.872 2.291 33 2.819 ;
     RECT  67.2 2.243 67.608 2.821 ;
     RECT  15.456 2.677 15.96 2.915 ;
     RECT  40.2 2.151 40.512 3.109 ;
     RECT  66.144 2.821 67.608 3.299 ;
     RECT  23.568 2.243 24.504 3.301 ;
     RECT  26.064 1.859 26.088 3.301 ;
     RECT  45.6 1.907 46.92 3.301 ;
     RECT  47.952 1.907 49.416 3.301 ;
     RECT  39.792 3.109 40.512 3.395 ;
     RECT  7.8 2.151 8.112 3.397 ;
     RECT  66.624 3.299 67.608 3.397 ;
     RECT  9.504 2.677 9.528 3.443 ;
     RECT  43.92 2.821 43.944 3.443 ;
     RECT  50.592 2.245 51.312 3.443 ;
     RECT  45.6 3.301 49.416 3.491 ;
     RECT  29.4 2.151 29.712 3.685 ;
     RECT  40.2 3.395 40.512 3.733 ;
     RECT  61.8 2.151 62.112 3.925 ;
     RECT  18.6 2.151 19.08 4.019 ;
     RECT  23.568 3.301 26.088 4.019 ;
     RECT  45.6 3.491 49.32 4.019 ;
     RECT  32.784 2.819 33 4.067 ;
     RECT  7.8 3.397 8.232 4.115 ;
     RECT  18.6 4.019 19.032 4.115 ;
     RECT  37.632 2.917 37.656 4.115 ;
     RECT  42.72 3.109 42.744 4.115 ;
     RECT  66.624 3.397 68.568 4.163 ;
     RECT  15.456 2.915 15.48 4.355 ;
     RECT  29.184 3.685 29.712 4.501 ;
     RECT  56.4 2.151 56.712 4.501 ;
     RECT  40.2 3.733 41.016 4.547 ;
     RECT  52.56 3.925 52.584 4.547 ;
     RECT  45.6 4.019 48.648 4.595 ;
     RECT  61.68 3.925 62.112 4.595 ;
     RECT  45.6 4.595 47.256 4.643 ;
     RECT  12.912 2.245 13.512 4.645 ;
     RECT  12.912 4.645 14.328 4.691 ;
     RECT  34.8 2.291 35.112 4.741 ;
     RECT  36.336 2.821 36.36 4.741 ;
     RECT  34.8 4.741 36.36 4.787 ;
     RECT  40.2 4.547 40.512 4.933 ;
     RECT  20.208 1.811 21.576 4.981 ;
     RECT  7.8 4.115 8.112 5.077 ;
     RECT  24 4.019 25.128 5.077 ;
     RECT  71.28 4.501 71.304 5.125 ;
     RECT  72.6 2.151 72.912 5.125 ;
     RECT  48.624 4.595 48.648 5.171 ;
     RECT  71.28 5.125 72.912 5.171 ;
     RECT  59.04 4.261 59.064 5.363 ;
     RECT  32.784 4.067 32.808 5.557 ;
     RECT  28.464 4.501 29.712 5.605 ;
     RECT  40.08 4.933 40.512 5.605 ;
     RECT  7.68 5.077 8.112 5.651 ;
     RECT  56.304 4.501 56.712 5.651 ;
     RECT  40.08 5.605 41.208 5.653 ;
     RECT  11.376 2.677 11.4 5.747 ;
     RECT  13.104 4.691 14.328 5.747 ;
     RECT  17.136 5.077 17.16 5.747 ;
     RECT  32.784 5.557 33.144 5.747 ;
     RECT  71.952 5.171 72.912 5.747 ;
     RECT  49.728 4.501 49.752 5.749 ;
     RECT  50.88 3.443 51.312 5.749 ;
     RECT  32.784 5.747 32.808 5.843 ;
     RECT  37.584 5.029 37.608 5.843 ;
     RECT  19.92 4.981 21.576 5.891 ;
     RECT  45.6 4.643 45.912 5.893 ;
     RECT  46.896 4.643 47.256 5.893 ;
     RECT  49.728 5.749 51.312 6.037 ;
     RECT  45.6 5.893 47.256 6.131 ;
     RECT  39.792 5.653 41.208 6.133 ;
     RECT  39.792 6.133 41.64 6.179 ;
     RECT  39.792 6.179 40.512 6.229 ;
     RECT  43.44 5.317 43.464 6.373 ;
     RECT  44.592 4.981 44.616 6.373 ;
     RECT  28.368 5.605 29.712 6.419 ;
     RECT  7.8 5.651 8.112 6.421 ;
     RECT  18.6 4.115 18.912 6.421 ;
     RECT  19.92 5.891 21.048 6.421 ;
     RECT  43.44 6.373 44.616 6.611 ;
     RECT  18.6 6.421 21.048 6.803 ;
     RECT  68.544 4.163 68.568 6.805 ;
     RECT  41.616 6.179 41.64 6.851 ;
     RECT  76.8 5.173 76.824 6.851 ;
     RECT  29.28 6.419 29.712 7.045 ;
     RECT  45.6 6.131 47.208 7.331 ;
     RECT  78 2.151 78.312 7.333 ;
     RECT  49.584 6.037 51.312 7.379 ;
     RECT  22.704 7.285 22.728 7.381 ;
     RECT  24 5.077 26.04 7.381 ;
     RECT  68.544 6.805 68.952 7.381 ;
     RECT  18.6 6.803 19.032 7.429 ;
     RECT  64.8 4.549 64.824 7.619 ;
     RECT  34.8 4.787 35.592 7.717 ;
     RECT  72.6 5.747 72.912 7.765 ;
     RECT  43.44 6.611 44.472 7.813 ;
     RECT  43.344 7.813 44.472 7.859 ;
     RECT  49.584 7.379 49.608 7.861 ;
     RECT  39.408 6.229 40.512 7.909 ;
     RECT  7.8 6.421 8.568 8.003 ;
     RECT  39.408 7.909 40.872 8.003 ;
     RECT  68.544 7.381 69.72 8.195 ;
     RECT  29.28 7.045 30.504 8.293 ;
     RECT  17.664 7.429 19.032 8.435 ;
     RECT  42.144 7.861 42.168 8.483 ;
     RECT  13.104 5.747 13.512 8.485 ;
     RECT  58.656 5.605 58.68 8.485 ;
     RECT  58.656 8.485 59.352 8.531 ;
     RECT  13.104 8.485 13.608 8.579 ;
     RECT  59.328 8.531 59.352 8.677 ;
     RECT  43.344 7.859 43.368 8.821 ;
     RECT  44.448 7.859 44.472 8.821 ;
     RECT  43.344 8.821 44.472 8.867 ;
     RECT  52.656 5.845 52.68 8.869 ;
     RECT  22.704 7.381 26.04 9.011 ;
     RECT  48.72 7.861 49.608 9.013 ;
     RECT  50.88 7.379 51.312 9.013 ;
     RECT  52.512 8.869 52.68 9.059 ;
     RECT  24 9.011 26.04 9.061 ;
     RECT  64.944 8.485 64.968 9.061 ;
     RECT  64.704 9.061 64.968 9.107 ;
     RECT  72.336 7.765 72.912 9.107 ;
     RECT  10.272 7.765 10.296 9.155 ;
     RECT  48.72 9.013 51.312 9.251 ;
     RECT  7.8 8.003 8.112 9.349 ;
     RECT  20.448 6.803 21.048 9.349 ;
     RECT  24 9.061 26.472 9.395 ;
     RECT  39.792 8.003 40.872 9.539 ;
     RECT  38.208 8.773 38.232 9.589 ;
     RECT  38.208 9.589 38.808 9.635 ;
     RECT  45.6 7.331 46.872 9.731 ;
     RECT  64.704 9.107 64.728 9.731 ;
     RECT  17.664 8.435 18.912 9.779 ;
     RECT  63.264 9.013 63.288 9.875 ;
     RECT  60.72 4.837 60.744 9.973 ;
     RECT  61.8 4.595 62.112 9.973 ;
     RECT  7.68 9.349 8.112 10.019 ;
     RECT  60.72 9.973 62.112 10.019 ;
     RECT  29.184 8.293 30.504 10.069 ;
     RECT  13.2 8.579 13.608 10.165 ;
     RECT  68.544 8.195 68.952 10.211 ;
     RECT  56.4 5.651 56.712 10.213 ;
     RECT  16.224 9.109 16.248 10.259 ;
     RECT  74.688 9.637 74.712 10.307 ;
     RECT  26.448 9.395 26.472 10.309 ;
     RECT  48.72 9.251 49.56 10.355 ;
     RECT  22.704 9.011 22.728 10.403 ;
     RECT  52.656 9.059 52.68 10.403 ;
     RECT  59.328 8.677 59.448 10.501 ;
     RECT  26.448 10.309 27.24 10.547 ;
     RECT  48.72 10.355 48.744 10.595 ;
     RECT  63.456 10.117 63.48 10.643 ;
     RECT  38.784 9.635 38.808 10.741 ;
     RECT  39.792 9.539 40.512 10.741 ;
     RECT  78 7.333 79.08 10.789 ;
     RECT  24 9.395 25.128 10.837 ;
     RECT  50.88 9.251 51.312 10.837 ;
     RECT  24 10.837 25.56 10.883 ;
     RECT  37.728 9.925 37.752 10.883 ;
     RECT  38.784 10.741 40.512 10.883 ;
     RECT  43.728 8.867 44.472 10.883 ;
     RECT  55.776 10.213 56.712 10.883 ;
     RECT  58.128 10.069 58.152 10.883 ;
     RECT  7.8 10.019 8.112 10.885 ;
     RECT  44.208 10.883 44.472 10.931 ;
     RECT  56.4 10.883 56.712 10.933 ;
     RECT  39.648 10.883 40.512 10.981 ;
     RECT  31.872 8.677 31.896 11.123 ;
     RECT  33.408 10.453 33.432 11.123 ;
     RECT  6.672 5.701 6.696 11.125 ;
     RECT  12.576 10.165 13.608 11.171 ;
     RECT  44.352 10.931 44.472 11.171 ;
     RECT  45.6 9.731 46.488 11.173 ;
     RECT  44.448 11.171 44.472 11.219 ;
     RECT  28.752 10.069 30.504 11.269 ;
     RECT  13.2 11.171 13.608 11.317 ;
     RECT  18.6 9.779 18.912 11.317 ;
     RECT  7.8 10.885 8.232 11.365 ;
     RECT  59.328 10.501 59.544 11.413 ;
     RECT  61.008 10.019 62.112 11.413 ;
     RECT  20.304 9.349 21.048 11.843 ;
     RECT  78 10.789 79.128 11.845 ;
     RECT  68.544 10.211 68.568 11.941 ;
     RECT  28.752 11.269 30.84 11.987 ;
     RECT  39.648 10.981 41.256 11.987 ;
     RECT  68.544 11.941 68.712 11.987 ;
     RECT  6.048 11.125 6.696 12.179 ;
     RECT  50.544 10.837 51.312 12.179 ;
     RECT  59.328 11.413 62.112 12.227 ;
     RECT  59.328 12.227 59.544 12.229 ;
     RECT  61.008 12.227 62.112 12.275 ;
     RECT  77.136 11.845 79.128 12.275 ;
     RECT  58.656 12.229 59.544 12.277 ;
     RECT  27.216 10.547 27.24 12.517 ;
     RECT  29.4 11.987 30.84 12.563 ;
     RECT  68.688 11.987 68.712 12.709 ;
     RECT  71.424 11.941 71.448 12.755 ;
     RECT  6.672 12.179 6.696 12.803 ;
     RECT  61.68 12.275 62.112 12.899 ;
     RECT  66.624 4.163 67.512 12.949 ;
     RECT  68.688 12.709 69.624 12.949 ;
     RECT  29.4 12.563 30.744 13.043 ;
     RECT  53.568 11.749 53.592 13.045 ;
     RECT  58.128 12.277 59.544 13.045 ;
     RECT  50.736 12.179 51.312 13.091 ;
     RECT  13.2 11.317 14.28 13.139 ;
     RECT  45.6 11.173 46.68 13.379 ;
     RECT  39.792 11.987 41.256 13.427 ;
     RECT  2.4 2.151 2.712 13.621 ;
     RECT  53.568 13.045 54.024 13.621 ;
     RECT  13.2 13.139 13.512 13.669 ;
     RECT  66.624 12.949 69.624 13.715 ;
     RECT  78 12.275 79.128 13.715 ;
     RECT  78 13.715 78.312 13.717 ;
     RECT  66.624 13.715 68.808 14.147 ;
     RECT  58.08 13.045 59.544 14.197 ;
     RECT  47.856 12.997 47.88 14.341 ;
     RECT  47.424 14.341 47.88 14.387 ;
     RECT  21.024 11.843 21.048 14.389 ;
     RECT  56.4 10.933 56.808 14.389 ;
     RECT  58.08 14.197 59.832 14.389 ;
     RECT  12.336 13.669 13.512 14.675 ;
     RECT  51 13.091 51.312 14.773 ;
     RECT  2.4 13.621 3.096 14.819 ;
     RECT  53.136 13.621 54.024 14.821 ;
     RECT  25.536 10.883 25.56 14.867 ;
     RECT  27.216 12.517 28.2 14.867 ;
     RECT  80.208 14.245 80.232 14.867 ;
     RECT  18.6 11.317 19.032 14.869 ;
     RECT  47.424 14.387 47.448 14.915 ;
     RECT  53.136 14.821 54.36 14.915 ;
     RECT  29.4 13.043 30.648 15.061 ;
     RECT  34.8 7.717 35.88 15.061 ;
     RECT  64.752 12.517 64.776 15.061 ;
     RECT  64.752 15.061 64.872 15.107 ;
     RECT  56.4 14.389 59.832 15.203 ;
     RECT  45.6 13.379 46.104 15.251 ;
     RECT  66.624 14.147 68.136 15.349 ;
     RECT  74.256 13.429 74.28 15.395 ;
     RECT  75.792 14.773 75.816 15.395 ;
     RECT  21.024 14.389 21.144 15.443 ;
     RECT  48.96 14.629 48.984 15.443 ;
     RECT  56.4 15.203 56.808 15.443 ;
     RECT  58.08 15.203 59.832 15.443 ;
     RECT  54 14.915 54.36 15.491 ;
     RECT  29.4 15.061 31.272 15.683 ;
     RECT  44.4 13.573 44.424 15.683 ;
     RECT  64.848 15.107 64.872 15.923 ;
     RECT  39.792 13.427 40.512 15.925 ;
     RECT  45.6 15.251 46.008 15.925 ;
     RECT  80.16 15.301 80.184 15.973 ;
     RECT  81.84 15.301 81.864 15.973 ;
     RECT  80.16 15.973 81.864 16.019 ;
     RECT  10.752 15.061 10.776 16.163 ;
     RECT  80.16 16.019 80.904 16.163 ;
     RECT  58.08 15.443 58.728 16.259 ;
     RECT  66.624 15.349 68.28 16.261 ;
     RECT  61.8 12.899 62.112 16.309 ;
     RECT  72.6 9.107 72.912 16.405 ;
     RECT  33.744 14.245 33.768 16.547 ;
     RECT  54.096 15.491 54.36 16.693 ;
     RECT  66.384 16.261 68.28 16.741 ;
     RECT  51 14.773 51.72 16.789 ;
     RECT  66.144 16.741 68.28 16.883 ;
     RECT  66.864 16.883 68.28 16.885 ;
     RECT  58.08 16.259 58.344 16.933 ;
     RECT  59.808 15.443 59.832 16.933 ;
     RECT  51 16.789 51.816 16.979 ;
     RECT  13.2 14.675 13.512 16.981 ;
     RECT  51 16.979 51.624 17.027 ;
     RECT  56.4 15.443 56.712 17.029 ;
     RECT  57.888 16.933 58.344 17.029 ;
     RECT  16.08 16.789 16.104 17.077 ;
     RECT  24 10.883 24.312 17.077 ;
     RECT  45.024 15.925 46.008 17.123 ;
     RECT  49.056 16.885 49.08 17.123 ;
     RECT  66.864 16.885 69 17.123 ;
     RECT  39.792 15.925 40.68 17.173 ;
     RECT  41.904 17.125 41.928 17.173 ;
     RECT  16.08 17.077 17.064 17.219 ;
     RECT  51 17.027 51.432 17.219 ;
     RECT  66.864 17.123 68.904 17.219 ;
     RECT  26.112 16.549 26.136 17.315 ;
     RECT  18.6 14.869 19.368 17.317 ;
     RECT  21.024 15.443 21.048 17.317 ;
     RECT  77.616 13.717 78.312 17.365 ;
     RECT  61.68 16.309 62.112 17.411 ;
     RECT  45.6 17.123 46.008 17.605 ;
     RECT  72.48 16.405 72.912 17.605 ;
     RECT  38.736 16.069 38.76 17.651 ;
     RECT  39.792 17.173 41.928 17.651 ;
     RECT  72.48 17.605 73.032 17.651 ;
     RECT  3.792 17.077 3.816 17.699 ;
     RECT  18.6 17.317 21.048 17.699 ;
     RECT  66.864 17.219 68.28 17.699 ;
     RECT  59.808 16.933 60.168 18.035 ;
     RECT  24 17.077 24.984 18.131 ;
     RECT  7.8 11.365 8.52 18.179 ;
     RECT  76.896 17.365 78.312 18.179 ;
     RECT  77.616 18.179 78.312 18.181 ;
     RECT  13.2 16.981 14.28 18.419 ;
     RECT  20.304 17.699 21.048 18.419 ;
     RECT  80.88 16.163 80.904 18.419 ;
     RECT  39.792 17.651 40.68 18.515 ;
     RECT  67.2 17.699 68.28 18.757 ;
     RECT  29.4 15.683 30.648 18.805 ;
     RECT  17.472 18.181 17.496 19.379 ;
     RECT  28.8 18.805 30.648 19.379 ;
     RECT  67.2 18.757 68.52 19.523 ;
     RECT  54.096 16.693 54.6 19.861 ;
     RECT  45.6 17.605 46.104 19.909 ;
     RECT  22.752 19.909 22.776 19.957 ;
     RECT  22.464 19.957 22.776 20.051 ;
     RECT  29.4 19.379 30.648 20.099 ;
     RECT  7.8 18.179 8.232 20.149 ;
     RECT  72.6 17.651 73.032 20.197 ;
     RECT  64.992 17.077 65.016 20.339 ;
     RECT  13.2 18.419 13.512 20.389 ;
     RECT  54.096 19.861 54.744 20.531 ;
     RECT  18.6 17.699 18.912 20.533 ;
     RECT  16.08 17.219 16.104 20.579 ;
     RECT  22.464 20.051 22.488 20.579 ;
     RECT  59.808 18.035 59.832 20.579 ;
     RECT  77.616 18.181 79.272 20.579 ;
     RECT  61.8 17.411 62.112 20.725 ;
     RECT  45.6 19.909 46.2 20.819 ;
     RECT  20.352 18.419 21.048 20.867 ;
     RECT  45.6 20.819 46.008 20.867 ;
     RECT  72.6 20.197 73.896 21.059 ;
     RECT  27.216 14.867 27.24 21.061 ;
     RECT  7.8 20.149 9.096 21.155 ;
     RECT  47.856 20.821 47.88 21.155 ;
     RECT  56.4 17.029 58.344 21.155 ;
     RECT  13.2 20.389 14.232 21.251 ;
     RECT  81.84 19.525 81.864 21.299 ;
     RECT  10.8 19.765 10.824 21.587 ;
     RECT  6.144 18.133 6.168 21.683 ;
     RECT  26.352 21.061 27.24 21.683 ;
     RECT  61.8 20.725 62.808 21.683 ;
     RECT  67.2 19.523 68.28 21.733 ;
     RECT  32.592 19.621 32.616 21.827 ;
     RECT  54.096 20.531 54.6 21.973 ;
     RECT  17.712 20.533 18.912 22.163 ;
     RECT  4.32 21.061 4.344 22.211 ;
     RECT  71.52 20.149 71.544 22.211 ;
     RECT  21.024 20.867 21.048 22.259 ;
     RECT  42.24 21.541 42.264 22.259 ;
     RECT  78 20.579 78.408 22.259 ;
     RECT  79.776 21.253 79.8 22.259 ;
     RECT  31.104 21.781 31.128 22.451 ;
     RECT  39.792 18.515 40.512 22.693 ;
     RECT  51 17.219 51.312 22.741 ;
     RECT  53.568 21.973 54.6 22.835 ;
     RECT  2.4 14.819 2.712 23.125 ;
     RECT  72.6 21.059 72.912 23.125 ;
     RECT  78 22.259 78.312 23.413 ;
     RECT  32.832 22.741 32.856 23.555 ;
     RECT  81.216 22.789 81.24 23.749 ;
     RECT  80.832 23.749 81.24 23.795 ;
     RECT  72.6 23.125 73.032 23.797 ;
     RECT  39.36 22.693 40.512 23.843 ;
     RECT  60.432 22.741 60.456 23.843 ;
     RECT  29.4 20.099 29.712 23.893 ;
     RECT  7.8 21.155 8.112 24.325 ;
     RECT  24 18.131 24.312 24.469 ;
     RECT  38.304 21.061 38.328 24.469 ;
     RECT  57.744 21.155 58.344 24.469 ;
     RECT  38.304 24.469 38.472 24.515 ;
     RECT  71.952 23.797 73.032 24.515 ;
     RECT  18.6 22.163 18.912 24.613 ;
     RECT  77.904 23.413 78.312 24.613 ;
     RECT  67.2 21.733 68.952 24.803 ;
     RECT  2.4 23.125 3.528 24.947 ;
     RECT  13.2 21.251 13.512 24.997 ;
     RECT  34.8 15.061 36.024 25.045 ;
     RECT  51 22.741 51.432 25.045 ;
     RECT  80.832 23.795 80.856 25.045 ;
     RECT  18.288 24.613 18.912 25.091 ;
     RECT  29.04 23.893 29.712 25.091 ;
     RECT  80.832 25.045 80.952 25.091 ;
     RECT  39.648 23.843 40.512 25.139 ;
     RECT  80.928 25.091 80.952 25.187 ;
     RECT  63.312 24.469 63.336 25.189 ;
     RECT  63.312 25.189 63.672 25.235 ;
     RECT  27.216 21.683 27.24 25.285 ;
     RECT  25.776 23.893 25.8 25.331 ;
     RECT  7.8 24.325 8.232 25.525 ;
     RECT  38.448 24.515 38.472 25.621 ;
     RECT  54.096 22.835 54.6 25.669 ;
     RECT  16.752 24.757 16.776 25.715 ;
     RECT  23.376 24.469 24.312 25.715 ;
     RECT  57.744 24.469 58.824 25.715 ;
     RECT  71.952 24.515 72.912 25.715 ;
     RECT  33.936 25.045 36.024 26.003 ;
     RECT  51 25.045 52.152 26.003 ;
     RECT  13.104 24.997 13.512 26.101 ;
     RECT  24 25.715 24.312 26.197 ;
     RECT  3.792 25.045 3.816 26.243 ;
     RECT  10.368 25.045 10.392 26.243 ;
     RECT  37.632 25.621 38.472 26.243 ;
     RECT  7.68 25.525 8.232 26.245 ;
     RECT  54.096 25.669 54.792 26.437 ;
     RECT  41.568 26.197 41.592 26.485 ;
     RECT  7.68 26.245 8.808 26.531 ;
     RECT  18.48 25.091 18.912 26.629 ;
     RECT  2.4 24.947 2.712 26.725 ;
     RECT  27.216 25.285 27.576 26.771 ;
     RECT  63.648 25.235 63.672 26.819 ;
     RECT  61.8 21.683 62.112 26.917 ;
     RECT  54.096 26.437 54.84 27.347 ;
     RECT  65.856 25.045 65.88 27.349 ;
     RECT  41.52 26.485 41.592 27.491 ;
     RECT  34.416 26.003 36.024 27.587 ;
     RECT  7.8 26.531 8.808 27.589 ;
     RECT  2.4 26.725 3.528 27.635 ;
     RECT  24 26.197 24.408 27.731 ;
     RECT  72.6 25.715 72.912 27.733 ;
     RECT  45.6 20.867 45.912 27.781 ;
     RECT  18.48 26.629 19.368 27.829 ;
     RECT  74.64 23.125 74.664 27.875 ;
     RECT  21.648 25.957 21.672 27.877 ;
     RECT  17.664 27.829 19.368 27.923 ;
     RECT  21.216 27.877 21.672 27.923 ;
     RECT  30.864 24.997 30.888 28.069 ;
     RECT  30.864 28.069 31.032 28.115 ;
     RECT  32.784 26.629 32.808 28.115 ;
     RECT  54.096 27.347 54.744 28.115 ;
     RECT  51 26.003 51.48 28.261 ;
     RECT  7.8 27.589 8.904 28.451 ;
     RECT  41.52 27.491 41.544 28.453 ;
     RECT  56.4 21.155 56.712 28.453 ;
     RECT  58.32 25.715 58.824 28.453 ;
     RECT  65.52 27.349 65.88 28.453 ;
     RECT  44.736 27.781 45.912 28.499 ;
     RECT  72.6 27.733 73.08 28.499 ;
     RECT  72.6 28.499 72.912 28.501 ;
     RECT  41.52 28.453 42.36 28.595 ;
     RECT  12.336 26.101 13.512 28.691 ;
     RECT  63.648 27.877 63.672 28.691 ;
     RECT  29.4 25.091 29.712 28.693 ;
     RECT  49.92 28.261 51.48 28.739 ;
     RECT  54.096 28.115 54.12 28.789 ;
     RECT  50.688 28.739 51.48 28.835 ;
     RECT  77.52 24.613 78.312 28.933 ;
     RECT  21.216 27.923 21.24 28.979 ;
     RECT  38.448 26.243 38.472 29.123 ;
     RECT  17.664 27.923 18.912 29.219 ;
     RECT  42.336 28.595 42.36 29.219 ;
     RECT  60.864 26.917 62.112 29.219 ;
     RECT  24 27.731 24.312 29.269 ;
     RECT  31.008 28.115 31.032 29.317 ;
     RECT  3.936 28.453 3.96 29.363 ;
     RECT  27.216 26.771 27.24 29.363 ;
     RECT  72.336 28.501 72.912 29.363 ;
     RECT  34.8 27.587 36.024 29.365 ;
     RECT  80.496 27.301 80.52 29.459 ;
     RECT  25.344 29.509 25.368 29.605 ;
     RECT  67.2 24.803 68.28 29.605 ;
     RECT  31.008 29.317 31.608 29.653 ;
     RECT  53.184 28.789 54.12 29.653 ;
     RECT  50.688 28.835 51.432 29.699 ;
     RECT  77.52 28.933 78.648 29.795 ;
     RECT  47.184 29.365 47.208 30.035 ;
     RECT  55.248 28.789 55.272 30.083 ;
     RECT  60.288 29.461 60.312 30.181 ;
     RECT  25.344 29.605 25.848 30.275 ;
     RECT  50.832 29.699 51.432 30.371 ;
     RECT  29.4 28.693 29.976 30.373 ;
     RECT  31.008 29.653 31.896 30.373 ;
     RECT  61.8 29.219 62.112 30.373 ;
     RECT  63.12 29.365 63.144 30.373 ;
     RECT  61.8 30.373 63.144 30.419 ;
     RECT  7.8 28.451 8.808 30.709 ;
     RECT  72.6 29.363 72.912 30.709 ;
     RECT  42.24 29.989 42.264 30.803 ;
     RECT  53.136 29.653 54.12 30.803 ;
     RECT  56.4 28.453 58.824 30.805 ;
     RECT  67.2 29.605 68.424 30.805 ;
     RECT  23.376 29.269 24.312 30.851 ;
     RECT  33.888 29.365 36.024 30.851 ;
     RECT  51 30.371 51.432 30.899 ;
     RECT  29.4 30.373 31.896 30.947 ;
     RECT  56.304 30.805 58.824 30.947 ;
     RECT  67.2 30.805 68.664 31.045 ;
     RECT  37.632 30.901 37.656 31.091 ;
     RECT  29.4 30.947 31.608 31.139 ;
     RECT  61.8 30.419 62.808 31.139 ;
     RECT  49.632 29.605 49.656 31.285 ;
     RECT  3.984 30.757 4.008 31.379 ;
     RECT  19.968 27.925 19.992 31.379 ;
     RECT  30.72 31.139 31.608 31.379 ;
     RECT  44.976 28.499 45.912 31.379 ;
     RECT  48.912 31.285 49.656 31.379 ;
     RECT  64.992 28.453 65.88 31.379 ;
     RECT  67.2 31.045 68.904 31.379 ;
     RECT  77.616 29.795 78.648 31.379 ;
     RECT  58.704 30.947 58.824 31.525 ;
     RECT  71.76 30.709 72.912 31.525 ;
     RECT  71.376 31.525 72.912 31.571 ;
     RECT  58.704 31.525 58.92 31.765 ;
     RECT  59.952 30.181 60.312 31.765 ;
     RECT  21.12 30.613 21.144 31.907 ;
     RECT  61.8 31.139 62.76 31.907 ;
     RECT  16.944 31.813 16.968 31.955 ;
     RECT  77.616 31.379 78.408 31.955 ;
     RECT  53.184 30.803 54.12 32.099 ;
     RECT  7.8 30.709 9.672 32.195 ;
     RECT  72.6 31.571 72.912 32.197 ;
     RECT  30.72 31.379 31.032 32.339 ;
     RECT  72.6 32.197 73.128 32.435 ;
     RECT  18 29.219 18.912 32.437 ;
     RECT  34.8 30.851 36.024 32.437 ;
     RECT  71.376 31.571 71.4 32.531 ;
     RECT  11.472 32.149 11.496 32.771 ;
     RECT  24 30.851 24.312 32.869 ;
     RECT  25.344 30.275 25.368 32.869 ;
     RECT  45.6 31.379 45.912 32.917 ;
     RECT  7.8 32.195 9.144 33.013 ;
     RECT  17.952 32.437 18.912 33.013 ;
     RECT  39.792 25.139 40.512 33.013 ;
     RECT  48.912 31.379 48.936 33.013 ;
     RECT  80.976 30.901 81 33.013 ;
     RECT  48.912 33.013 49.032 33.059 ;
     RECT  76.32 31.813 76.344 33.059 ;
     RECT  2.4 27.635 2.712 33.061 ;
     RECT  58.704 31.765 60.312 33.107 ;
     RECT  49.008 33.059 49.032 33.155 ;
     RECT  58.752 33.107 60.312 33.251 ;
     RECT  68.64 31.379 68.904 33.251 ;
     RECT  51 30.899 51.312 33.253 ;
     RECT  67.2 31.379 67.512 33.253 ;
     RECT  68.64 33.251 68.76 33.253 ;
     RECT  65.856 31.379 65.88 33.301 ;
     RECT  67.2 33.253 68.76 33.301 ;
     RECT  13.2 28.691 13.512 33.397 ;
     RECT  14.976 32.437 15 33.445 ;
     RECT  72.6 32.435 72.912 33.445 ;
     RECT  14.832 33.445 15 33.491 ;
     RECT  44.688 32.917 45.912 33.541 ;
     RECT  44.448 33.541 45.912 33.587 ;
     RECT  24 32.869 25.368 33.589 ;
     RECT  34.704 32.437 36.024 33.589 ;
     RECT  54.096 32.099 54.12 33.589 ;
     RECT  30.72 32.339 30.744 33.731 ;
     RECT  17.952 33.013 19.848 33.971 ;
     RECT  83.4 2.151 83.712 34.117 ;
     RECT  80.976 33.013 81.912 34.163 ;
     RECT  17.952 33.971 18.912 34.165 ;
     RECT  56.4 30.947 57.48 34.165 ;
     RECT  53.52 33.589 54.12 34.211 ;
     RECT  12.48 33.397 13.512 34.259 ;
     RECT  14.832 33.491 14.856 34.259 ;
     RECT  24 33.589 25.752 34.259 ;
     RECT  50.64 33.253 51.312 34.355 ;
     RECT  34.704 33.589 36.504 34.405 ;
     RECT  61.8 31.907 62.112 34.501 ;
     RECT  7.68 33.013 9.144 34.643 ;
     RECT  33.744 34.405 36.504 34.739 ;
     RECT  61.8 34.501 62.232 34.741 ;
     RECT  34.032 34.739 36.504 34.789 ;
     RECT  7.68 34.643 8.856 34.835 ;
     RECT  44.448 33.587 44.472 34.835 ;
     RECT  59.52 33.251 60.312 34.835 ;
     RECT  2.4 33.061 2.904 34.931 ;
     RECT  83.184 34.117 83.712 35.077 ;
     RECT  34.032 34.789 36.696 35.269 ;
     RECT  78 31.955 78.312 35.269 ;
     RECT  13.104 34.259 13.512 35.315 ;
     RECT  29.4 31.139 29.712 35.317 ;
     RECT  65.856 33.301 68.76 35.363 ;
     RECT  34.032 35.269 37.032 35.507 ;
     RECT  25.344 34.259 25.752 35.603 ;
     RECT  27.168 32.437 27.192 35.701 ;
     RECT  39.792 33.013 40.968 35.795 ;
     RECT  7.68 34.835 8.808 35.843 ;
     RECT  49.248 35.653 49.272 35.845 ;
     RECT  54.096 34.211 54.12 35.845 ;
     RECT  61.344 34.741 62.232 35.893 ;
     RECT  65.856 35.363 68.664 35.987 ;
     RECT  61.344 35.893 62.808 36.083 ;
     RECT  43.728 35.845 43.752 36.277 ;
     RECT  43.488 36.277 43.752 36.323 ;
     RECT  67.2 35.987 68.664 36.323 ;
     RECT  2.4 34.931 2.712 36.325 ;
     RECT  7.8 35.843 8.808 36.469 ;
     RECT  17.616 34.165 18.912 36.515 ;
     RECT  27.072 35.701 27.192 36.515 ;
     RECT  29.4 35.317 30.696 36.515 ;
     RECT  37.008 35.507 37.032 36.515 ;
     RECT  54.096 35.845 54.744 36.515 ;
     RECT  65.856 35.987 65.88 36.515 ;
     RECT  48.48 35.845 49.272 36.661 ;
     RECT  34.032 35.507 36.024 36.755 ;
     RECT  56.4 34.165 57.576 36.757 ;
     RECT  74.256 34.069 74.28 36.851 ;
     RECT  77.76 35.269 78.312 36.899 ;
     RECT  7.8 36.469 9.384 37.043 ;
     RECT  48.48 36.661 49.56 37.043 ;
     RECT  56.4 36.757 57.72 37.093 ;
     RECT  2.4 36.325 2.808 37.283 ;
     RECT  11.472 37.189 11.496 37.331 ;
     RECT  71.76 33.445 72.912 37.333 ;
     RECT  55.44 37.093 57.72 37.477 ;
     RECT  45.6 33.587 45.912 37.573 ;
     RECT  49.248 37.043 49.56 37.573 ;
     RECT  7.8 37.043 8.808 37.667 ;
     RECT  27.168 36.515 27.192 37.667 ;
     RECT  63.216 36.901 63.24 37.667 ;
     RECT  32.448 34.165 32.472 37.859 ;
     RECT  54.096 36.515 54.12 37.861 ;
     RECT  67.2 36.323 67.512 37.861 ;
     RECT  68.64 36.323 68.664 37.861 ;
     RECT  18.48 36.515 18.912 38.005 ;
     RECT  22.992 32.917 23.016 38.005 ;
     RECT  24 34.259 24.312 38.005 ;
     RECT  45.6 37.573 46.008 38.101 ;
     RECT  7.8 37.667 8.112 38.149 ;
     RECT  13.2 35.315 13.512 38.149 ;
     RECT  51 34.355 51.312 38.149 ;
     RECT  83.136 35.077 83.712 38.149 ;
     RECT  53.904 37.861 54.12 38.195 ;
     RECT  80.976 34.163 81 38.197 ;
     RECT  80.976 38.197 81.192 38.243 ;
     RECT  31.296 37.621 31.32 38.435 ;
     RECT  29.4 36.515 29.712 38.485 ;
     RECT  49.248 37.573 49.992 38.581 ;
     RECT  51 38.149 51.432 38.581 ;
     RECT  55.392 37.477 57.72 38.675 ;
     RECT  7.584 38.149 8.112 38.677 ;
     RECT  71.76 37.333 73.176 38.677 ;
     RECT  4.272 37.861 4.296 38.723 ;
     RECT  7.584 38.677 8.472 38.723 ;
     RECT  49.248 38.581 51.432 38.725 ;
     RECT  82.512 38.149 83.712 39.059 ;
     RECT  45.6 38.101 46.296 39.061 ;
     RECT  48.912 38.725 51.432 39.205 ;
     RECT  45.6 39.061 47.256 39.301 ;
     RECT  71.664 38.677 73.176 39.301 ;
     RECT  78 36.899 78.312 39.301 ;
     RECT  29.28 38.485 29.712 39.347 ;
     RECT  56.4 38.675 57.72 39.395 ;
     RECT  71.232 39.301 73.176 39.493 ;
     RECT  18.48 38.005 19.752 39.637 ;
     RECT  44.976 39.301 47.256 39.637 ;
     RECT  44.976 39.637 47.64 39.733 ;
     RECT  48.768 39.205 51.432 39.733 ;
     RECT  44.976 39.733 51.432 39.781 ;
     RECT  11.28 39.061 11.304 39.875 ;
     RECT  67.2 37.861 68.664 39.877 ;
     RECT  43.488 36.323 43.512 39.923 ;
     RECT  71.232 39.493 73.656 39.923 ;
     RECT  13.2 38.149 14.232 40.019 ;
     RECT  41.568 39.349 41.592 40.019 ;
     RECT  63.12 39.061 63.144 40.067 ;
     RECT  77.904 39.301 78.312 40.067 ;
     RECT  44.688 39.781 51.432 40.117 ;
     RECT  7.8 38.723 8.472 40.163 ;
     RECT  59.52 34.835 60.264 40.259 ;
     RECT  61.344 36.083 62.112 40.451 ;
     RECT  27.456 38.725 27.48 40.549 ;
     RECT  53.904 38.195 53.928 40.549 ;
     RECT  27.456 40.549 28.008 40.595 ;
     RECT  34.8 36.755 36.024 40.643 ;
     RECT  59.52 40.259 60.216 40.739 ;
     RECT  34.8 40.643 35.88 40.835 ;
     RECT  44.688 40.117 52.248 40.837 ;
     RECT  44.688 40.837 52.632 40.981 ;
     RECT  53.904 40.549 54.12 40.981 ;
     RECT  39.792 35.795 40.512 41.075 ;
     RECT  61.536 40.451 62.112 41.123 ;
     RECT  29.4 39.347 29.712 41.557 ;
     RECT  17.904 39.637 19.752 41.605 ;
     RECT  21.168 38.149 21.192 41.605 ;
     RECT  5.904 36.421 5.928 41.651 ;
     RECT  34.8 40.835 35.688 41.651 ;
     RECT  71.664 39.923 73.656 41.651 ;
     RECT  67.2 39.877 68.808 41.699 ;
     RECT  32.448 41.509 32.472 42.083 ;
     RECT  71.664 41.651 72.912 42.275 ;
     RECT  27.984 40.595 28.008 42.467 ;
     RECT  44.688 40.981 54.12 42.467 ;
     RECT  49.2 42.467 54.12 42.755 ;
     RECT  50.688 42.755 54.12 42.851 ;
     RECT  72.384 42.275 72.912 42.851 ;
     RECT  74.256 42.133 74.28 42.851 ;
     RECT  22.992 38.005 24.312 42.949 ;
     RECT  25.344 35.603 25.368 42.949 ;
     RECT  59.52 40.739 59.544 42.949 ;
     RECT  22.992 42.949 25.368 42.995 ;
     RECT  59.52 42.949 59.64 42.995 ;
     RECT  44.688 42.467 48.072 43.235 ;
     RECT  34.8 41.651 35.112 43.285 ;
     RECT  38.448 41.797 38.472 43.285 ;
     RECT  52.848 42.851 54.12 43.333 ;
     RECT  44.688 43.235 47.928 43.379 ;
     RECT  49.2 42.755 49.224 43.379 ;
     RECT  50.688 42.851 51.864 43.379 ;
     RECT  52.848 43.333 54.216 43.475 ;
     RECT  42.048 42.469 42.072 43.523 ;
     RECT  50.688 43.379 51.432 43.523 ;
     RECT  57.696 39.395 57.72 43.717 ;
     RECT  43.44 40.981 43.464 43.813 ;
     RECT  44.688 43.379 47.784 43.813 ;
     RECT  43.44 43.813 47.784 43.955 ;
     RECT  52.848 43.475 53.928 44.053 ;
     RECT  17.904 41.605 21.192 44.099 ;
     RECT  51 43.523 51.432 44.099 ;
     RECT  6.288 43.717 6.312 44.197 ;
     RECT  7.8 40.163 8.112 44.197 ;
     RECT  15.12 43.333 15.144 44.339 ;
     RECT  65.856 42.085 65.88 44.341 ;
     RECT  13.2 40.019 13.512 44.437 ;
     RECT  28.032 43.285 28.056 44.627 ;
     RECT  6.288 44.197 8.112 44.723 ;
     RECT  67.2 41.699 67.8 44.725 ;
     RECT  52.752 44.053 53.928 44.821 ;
     RECT  21.168 44.099 21.192 44.965 ;
     RECT  61.8 41.123 62.112 44.965 ;
     RECT  22.992 42.995 25.224 45.013 ;
     RECT  33.6 44.437 33.624 45.059 ;
     RECT  68.784 41.699 68.808 45.059 ;
     RECT  81.168 38.243 81.192 45.059 ;
     RECT  17.904 44.099 19.752 45.203 ;
     RECT  67.104 44.725 67.8 45.203 ;
     RECT  22.752 45.013 25.224 45.253 ;
     RECT  22.752 45.253 26.04 45.397 ;
     RECT  21.168 44.965 21.672 45.541 ;
     RECT  22.752 45.397 26.664 45.541 ;
     RECT  18.192 45.203 19.752 45.587 ;
     RECT  27.984 44.965 28.008 45.587 ;
     RECT  6.288 44.723 6.312 45.635 ;
     RECT  11.808 44.677 11.832 45.635 ;
     RECT  21.168 45.541 26.664 45.635 ;
     RECT  34.8 43.285 35.208 45.683 ;
     RECT  52.416 44.821 53.928 45.683 ;
     RECT  13.104 44.437 13.512 46.117 ;
     RECT  65.424 44.341 65.88 46.117 ;
     RECT  22.32 45.635 26.664 46.211 ;
     RECT  29.28 41.557 29.712 46.213 ;
     RECT  37.584 43.285 38.472 46.309 ;
     RECT  61.104 44.965 62.112 46.499 ;
     RECT  72.6 42.851 72.912 46.501 ;
     RECT  12.528 46.117 13.512 46.645 ;
     RECT  20.496 46.021 20.52 46.645 ;
     RECT  65.232 46.117 65.88 46.693 ;
     RECT  18.192 45.587 19.512 46.787 ;
     RECT  37.584 46.309 38.568 46.787 ;
     RECT  29.088 46.213 29.712 46.835 ;
     RECT  63.552 46.645 63.576 46.883 ;
     RECT  74.064 45.541 74.088 46.883 ;
     RECT  38.544 46.787 38.568 46.981 ;
     RECT  40.2 41.075 40.512 46.981 ;
     RECT  10.224 45.877 10.248 47.269 ;
     RECT  20.496 46.645 21.096 47.315 ;
     RECT  38.544 46.981 40.512 47.411 ;
     RECT  11.664 46.645 13.512 47.459 ;
     RECT  10.128 47.269 10.248 47.699 ;
     RECT  13.2 47.459 13.512 47.701 ;
     RECT  30.72 46.789 30.744 47.701 ;
     RECT  10.128 47.699 10.152 47.845 ;
     RECT  22.32 46.211 26.04 47.845 ;
     RECT  72.48 46.501 72.912 47.845 ;
     RECT  37.056 47.701 37.08 47.891 ;
     RECT  48.528 47.605 48.552 47.939 ;
     RECT  52.992 45.683 53.928 47.939 ;
     RECT  38.544 47.411 38.856 48.421 ;
     RECT  40.08 47.411 40.512 48.421 ;
     RECT  51 44.099 51.312 48.421 ;
     RECT  43.44 43.955 47.256 48.515 ;
     RECT  7.8 44.723 8.112 48.613 ;
     RECT  18.6 46.787 19.512 48.613 ;
     RECT  20.496 47.315 20.52 48.613 ;
     RECT  18.6 48.613 20.52 48.659 ;
     RECT  7.68 48.613 8.112 48.661 ;
     RECT  11.664 47.459 11.88 48.901 ;
     RECT  13.2 47.701 14.376 48.901 ;
     RECT  67.104 45.203 67.608 48.901 ;
     RECT  29.4 46.835 29.712 48.949 ;
     RECT  30.72 47.701 30.888 48.949 ;
     RECT  61.8 46.499 62.112 48.949 ;
     RECT  10.032 47.845 10.152 48.997 ;
     RECT  37.056 48.901 37.08 48.997 ;
     RECT  36.96 48.997 37.08 49.043 ;
     RECT  9.12 48.997 10.152 49.139 ;
     RECT  36.96 49.043 36.984 49.139 ;
     RECT  7.584 48.661 8.112 49.189 ;
     RECT  10.032 49.139 10.152 49.237 ;
     RECT  7.584 49.189 8.952 49.283 ;
     RECT  22.32 47.845 26.136 49.283 ;
     RECT  7.8 49.283 8.952 49.331 ;
     RECT  23.28 49.283 26.136 49.379 ;
     RECT  67.056 48.901 67.608 49.477 ;
     RECT  45.216 48.515 47.256 49.525 ;
     RECT  29.4 48.949 30.888 49.571 ;
     RECT  36.096 49.285 36.12 49.571 ;
     RECT  11.664 48.901 14.376 49.619 ;
     RECT  34.8 45.683 35.112 49.621 ;
     RECT  13.104 49.619 14.376 49.763 ;
     RECT  42.144 47.893 42.168 49.763 ;
     RECT  18.6 48.659 20.376 49.861 ;
     RECT  43.44 48.515 44.088 49.861 ;
     RECT  45.216 49.525 48.024 49.861 ;
     RECT  61.008 48.949 62.112 50.101 ;
     RECT  61.008 50.101 62.472 50.147 ;
     RECT  11.664 49.619 12.024 50.387 ;
     RECT  17.616 49.861 20.376 50.437 ;
     RECT  11.856 50.387 12.024 50.531 ;
     RECT  17.088 50.437 20.376 50.579 ;
     RECT  38.544 48.421 40.512 50.579 ;
     RECT  23.28 49.379 25.224 50.581 ;
     RECT  29.4 49.571 30.792 50.629 ;
     RECT  12 50.531 12.024 50.771 ;
     RECT  29.4 50.629 31.32 50.821 ;
     RECT  27.312 48.421 27.336 50.867 ;
     RECT  10.032 49.237 10.248 50.915 ;
     RECT  43.44 49.861 48.024 50.963 ;
     RECT  72.288 47.845 72.912 50.965 ;
     RECT  17.232 50.579 20.376 51.011 ;
     RECT  17.616 51.011 20.376 51.157 ;
     RECT  44.976 50.963 48.024 51.253 ;
     RECT  72.192 50.965 72.912 51.253 ;
     RECT  13.2 49.763 14.376 51.347 ;
     RECT  23.28 50.581 25.368 51.347 ;
     RECT  44.976 51.253 48.84 51.347 ;
     RECT  65.232 46.693 66.072 51.347 ;
     RECT  23.328 51.347 25.368 51.491 ;
     RECT  24 51.491 25.368 51.637 ;
     RECT  59.616 42.995 59.64 51.637 ;
     RECT  33.648 50.773 33.672 51.875 ;
     RECT  17.616 51.157 20.952 51.923 ;
     RECT  61.8 50.147 62.472 51.923 ;
     RECT  65.472 51.347 66.072 51.923 ;
     RECT  29.4 50.821 31.608 51.971 ;
     RECT  45.216 51.347 48.84 52.403 ;
     RECT  21.936 51.253 21.96 52.451 ;
     RECT  34.8 49.621 35.976 52.499 ;
     RECT  42.24 51.493 42.264 52.499 ;
     RECT  65.472 51.923 65.544 52.499 ;
     RECT  18.192 51.923 20.952 52.547 ;
     RECT  50.736 48.421 51.312 52.549 ;
     RECT  18.6 52.547 20.952 52.739 ;
     RECT  67.056 49.477 67.656 52.739 ;
     RECT  24 51.637 26.328 52.979 ;
     RECT  24 52.979 25.224 53.075 ;
     RECT  29.4 51.971 30.264 53.123 ;
     RECT  67.056 52.739 67.608 53.123 ;
     RECT  56.4 39.395 56.712 53.221 ;
     RECT  57.696 43.717 58.056 53.221 ;
     RECT  20.352 52.739 20.952 53.269 ;
     RECT  20.352 53.269 21.384 53.557 ;
     RECT  50.736 52.549 52.152 53.557 ;
     RECT  38.832 50.579 40.512 53.603 ;
     RECT  20.352 53.557 21.816 53.795 ;
     RECT  56.4 53.221 58.056 53.939 ;
     RECT  50.736 53.557 52.488 54.037 ;
     RECT  48.816 52.403 48.84 54.085 ;
     RECT  50.256 54.037 52.488 54.085 ;
     RECT  61.8 51.923 62.112 54.085 ;
     RECT  71.28 51.253 72.912 54.085 ;
     RECT  39.936 53.603 40.512 54.131 ;
     RECT  24 53.075 24.312 54.133 ;
     RECT  38.832 53.603 38.856 54.179 ;
     RECT  10.224 50.915 10.248 54.371 ;
     RECT  75.84 53.557 75.864 54.421 ;
     RECT  71.28 54.085 73.608 54.565 ;
     RECT  43.44 50.963 43.464 54.613 ;
     RECT  78 40.067 78.312 54.613 ;
     RECT  20.928 53.795 21.816 54.661 ;
     RECT  78 54.613 78.456 54.661 ;
     RECT  24 54.133 24.456 54.707 ;
     RECT  26.304 52.979 26.328 54.853 ;
     RECT  65.52 52.499 65.544 55.141 ;
     RECT  29.4 53.123 29.928 55.187 ;
     RECT  29.4 55.187 29.832 55.283 ;
     RECT  59.616 51.637 59.928 55.285 ;
     RECT  57.696 53.939 58.056 55.331 ;
     RECT  59.616 55.285 60.168 55.379 ;
     RECT  71.28 54.565 74.088 55.427 ;
     RECT  55.392 38.675 55.416 55.429 ;
     RECT  55.296 55.429 55.416 55.475 ;
     RECT  43.44 54.613 43.896 55.715 ;
     RECT  78 54.661 78.696 55.763 ;
     RECT  67.104 53.123 67.608 55.907 ;
     RECT  75.264 54.421 75.864 55.955 ;
     RECT  56.4 53.939 56.712 56.053 ;
     RECT  71.376 55.427 74.088 56.099 ;
     RECT  65.04 55.141 65.544 56.147 ;
     RECT  65.04 56.147 65.064 56.149 ;
     RECT  64.944 56.149 65.064 56.195 ;
     RECT  55.296 55.475 55.32 56.291 ;
     RECT  56.4 56.053 56.856 56.291 ;
     RECT  45.216 52.403 47.256 56.389 ;
     RECT  48.816 54.085 52.488 56.389 ;
     RECT  40.08 54.131 40.512 56.485 ;
     RECT  75.84 55.955 75.864 56.485 ;
     RECT  40.08 56.485 41.304 56.531 ;
     RECT  53.904 47.939 53.928 56.869 ;
     RECT  45.216 56.389 52.488 56.965 ;
     RECT  53.712 56.869 53.928 56.965 ;
     RECT  34.8 52.499 35.112 57.013 ;
     RECT  78 55.763 78.456 57.013 ;
     RECT  27.408 56.101 27.432 57.059 ;
     RECT  45.216 56.965 53.928 57.059 ;
     RECT  52.464 57.059 53.928 57.107 ;
     RECT  7.8 49.331 8.856 57.155 ;
     RECT  60.144 55.379 60.168 57.157 ;
     RECT  61.248 54.085 62.112 57.157 ;
     RECT  25.392 54.853 26.328 57.205 ;
     RECT  75.84 56.485 76.056 57.299 ;
     RECT  20.928 54.661 22.728 57.347 ;
     RECT  25.392 57.205 26.376 57.347 ;
     RECT  16.224 51.301 16.248 57.541 ;
     RECT  45.216 57.059 51.312 57.635 ;
     RECT  71.376 56.099 73.608 57.635 ;
     RECT  78 57.013 78.744 57.635 ;
     RECT  78 57.635 78.456 57.685 ;
     RECT  43.44 55.715 43.848 57.731 ;
     RECT  45.216 57.635 47.256 58.021 ;
     RECT  45.168 58.021 47.256 58.069 ;
     RECT  40.2 56.531 41.304 58.117 ;
     RECT  5.52 57.541 5.544 58.163 ;
     RECT  26.304 57.347 26.376 58.163 ;
     RECT  57.84 55.331 58.056 58.163 ;
     RECT  72.192 57.635 73.608 58.163 ;
     RECT  77.472 57.685 78.456 58.163 ;
     RECT  67.2 55.907 67.608 58.261 ;
     RECT  64.944 56.195 64.968 58.403 ;
     RECT  56.4 56.291 56.712 58.405 ;
     RECT  57.84 58.163 57.864 58.405 ;
     RECT  66 57.877 66.024 58.547 ;
     RECT  52.512 57.107 53.928 58.549 ;
     RECT  52.464 58.549 53.928 58.597 ;
     RECT  56.4 58.405 57.864 58.597 ;
     RECT  27.936 57.541 27.96 58.645 ;
     RECT  40.08 58.117 41.304 58.645 ;
     RECT  16.224 57.541 16.968 58.691 ;
     RECT  72.24 58.163 73.608 58.691 ;
     RECT  16.416 58.691 16.968 58.739 ;
     RECT  22.032 57.347 22.728 58.739 ;
     RECT  24 54.707 24.408 58.739 ;
     RECT  75.792 57.445 75.816 58.739 ;
     RECT  34.8 57.013 35.208 58.883 ;
     RECT  67.2 58.261 67.752 59.027 ;
     RECT  26.352 58.163 26.376 59.077 ;
     RECT  27.504 58.645 27.96 59.077 ;
     RECT  52.32 58.597 53.928 59.221 ;
     RECT  60.144 57.157 62.112 59.221 ;
     RECT  72.24 58.691 72.912 59.221 ;
     RECT  26.352 59.077 27.96 59.267 ;
     RECT  40.08 58.645 42.264 59.267 ;
     RECT  40.08 59.267 41.304 59.315 ;
     RECT  40.08 59.315 40.512 59.459 ;
     RECT  55.584 58.597 57.864 59.459 ;
     RECT  77.472 58.163 78.312 59.459 ;
     RECT  74.64 59.269 74.664 59.603 ;
     RECT  24 58.739 24.312 59.701 ;
     RECT  16.416 58.739 16.44 59.891 ;
     RECT  31.584 51.971 31.608 59.891 ;
     RECT  44.496 58.069 47.256 59.939 ;
     RECT  67.2 59.027 67.608 59.989 ;
     RECT  52.32 59.221 54.12 60.229 ;
     RECT  57.84 59.459 57.864 60.277 ;
     RECT  58.848 59.221 62.112 60.277 ;
     RECT  44.688 59.939 47.256 60.373 ;
     RECT  48.816 57.635 51.312 60.373 ;
     RECT  52.32 60.229 54.216 60.373 ;
     RECT  83.4 39.059 83.712 60.373 ;
     RECT  6.24 58.453 6.264 60.467 ;
     RECT  44.688 60.373 47.304 60.467 ;
     RECT  71.28 59.221 72.912 60.467 ;
     RECT  66.96 59.989 67.608 60.469 ;
     RECT  26.352 59.267 27.528 60.563 ;
     RECT  48.384 60.373 54.216 60.565 ;
     RECT  57.84 60.277 62.112 60.661 ;
     RECT  57.84 60.661 62.328 61.043 ;
     RECT  45.168 60.467 47.304 61.139 ;
     RECT  66.192 60.469 67.608 61.139 ;
     RECT  43.44 57.731 43.464 61.189 ;
     RECT  58.848 61.043 62.328 61.331 ;
     RECT  24 59.701 24.84 61.429 ;
     RECT  66.192 61.139 67.512 61.475 ;
     RECT  23.856 61.429 24.84 61.477 ;
     RECT  26.352 60.563 27 61.477 ;
     RECT  29.4 55.283 29.712 61.477 ;
     RECT  45.216 61.139 47.304 61.477 ;
     RECT  48.384 60.565 54.36 61.477 ;
     RECT  43.44 61.189 43.512 61.525 ;
     RECT  22.032 58.739 22.056 61.619 ;
     RECT  45.216 61.477 54.36 61.619 ;
     RECT  58.848 61.331 62.112 61.619 ;
     RECT  20.928 57.347 20.952 61.765 ;
     RECT  71.28 60.467 71.304 61.861 ;
     RECT  45.504 61.619 54.36 62.053 ;
     RECT  55.584 59.459 56.712 62.053 ;
     RECT  45.504 62.053 56.712 62.099 ;
     RECT  29.184 61.477 29.712 62.195 ;
     RECT  83.136 60.373 83.712 62.195 ;
     RECT  45.504 62.099 55.272 62.243 ;
     RECT  59.52 61.619 62.112 62.483 ;
     RECT  18.6 52.739 18.912 62.533 ;
     RECT  70.128 43.045 70.152 62.581 ;
     RECT  71.28 61.861 71.496 62.581 ;
     RECT  34.8 58.883 35.112 62.677 ;
     RECT  56.4 62.099 56.712 62.677 ;
     RECT  57.84 61.043 57.864 62.677 ;
     RECT  38.784 62.581 38.808 62.723 ;
     RECT  70.128 62.581 71.496 62.723 ;
     RECT  20.928 61.765 21.096 62.819 ;
     RECT  34.704 62.677 35.112 62.819 ;
     RECT  45.6 62.243 55.272 63.205 ;
     RECT  61.8 62.483 62.112 63.205 ;
     RECT  42.528 61.525 43.512 63.251 ;
     RECT  45.168 63.205 55.272 63.781 ;
     RECT  56.4 62.677 57.864 63.781 ;
     RECT  71.472 62.723 71.496 64.019 ;
     RECT  59.52 62.483 60.168 64.115 ;
     RECT  23.856 61.477 27 64.357 ;
     RECT  76.512 59.557 76.536 64.741 ;
     RECT  76.512 64.741 76.776 64.787 ;
     RECT  23.424 64.357 27 64.933 ;
     RECT  45.168 63.781 57.864 64.933 ;
     RECT  31.248 64.117 31.272 65.075 ;
     RECT  81.936 64.645 81.96 65.075 ;
     RECT  15.936 63.781 15.96 65.125 ;
     RECT  45.168 64.933 58.008 65.125 ;
     RECT  15.696 65.125 15.96 65.171 ;
     RECT  45.168 65.125 58.248 65.365 ;
     RECT  20.928 62.819 20.952 65.509 ;
     RECT  33.456 65.653 33.48 65.795 ;
     RECT  7.8 57.155 8.112 65.845 ;
     RECT  23.424 64.933 27.096 65.845 ;
     RECT  76.752 64.787 76.776 65.941 ;
     RECT  78 59.459 78.312 65.941 ;
     RECT  20.544 65.509 20.952 65.987 ;
     RECT  76.752 65.941 78.312 65.987 ;
     RECT  60.144 64.115 60.168 65.989 ;
     RECT  20.928 65.987 20.952 66.085 ;
     RECT  70.128 62.723 70.152 66.085 ;
     RECT  15.696 65.171 15.72 66.227 ;
     RECT  23.424 65.845 27.336 66.227 ;
     RECT  61.8 63.205 62.664 66.227 ;
     RECT  13.2 51.347 13.512 66.565 ;
     RECT  72.6 60.467 72.912 66.565 ;
     RECT  38.544 64.597 38.568 66.661 ;
     RECT  43.488 63.251 43.512 66.661 ;
     RECT  83.4 62.195 83.712 66.709 ;
     RECT  72.6 66.565 73.176 66.755 ;
     RECT  29.4 62.195 29.712 66.901 ;
     RECT  42.816 66.661 43.512 66.901 ;
     RECT  20.928 66.085 21.096 67.187 ;
     RECT  45.168 65.365 58.776 67.189 ;
     RECT  60.144 65.989 60.456 67.189 ;
     RECT  42.816 66.901 43.608 67.237 ;
     RECT  82.704 66.709 83.712 67.283 ;
     RECT  31.392 67.189 31.416 67.331 ;
     RECT  68.832 64.597 68.856 67.381 ;
     RECT  66.96 61.475 67.512 67.427 ;
     RECT  69.984 66.085 70.152 67.427 ;
     RECT  42.816 67.237 43.752 67.477 ;
     RECT  61.8 66.227 62.112 67.477 ;
     RECT  77.568 65.987 78.312 67.523 ;
     RECT  42.192 67.477 43.752 67.525 ;
     RECT  23.424 66.227 25.272 67.573 ;
     RECT  45.168 67.189 60.456 67.669 ;
     RECT  61.536 67.477 62.112 67.669 ;
     RECT  68.736 67.381 68.856 67.715 ;
     RECT  42.192 67.525 43.8 67.765 ;
     RECT  38.448 66.661 38.568 67.859 ;
     RECT  42.192 67.765 43.848 67.859 ;
     RECT  43.2 67.859 43.848 68.293 ;
     RECT  45.168 67.669 62.112 68.293 ;
     RECT  20.928 67.187 20.952 68.341 ;
     RECT  34.8 62.819 35.112 68.341 ;
     RECT  38.448 67.859 38.472 68.341 ;
     RECT  23.328 67.573 25.272 68.435 ;
     RECT  28.656 66.901 29.712 68.435 ;
     RECT  42.192 67.859 42.216 68.675 ;
     RECT  23.616 68.435 25.272 68.773 ;
     RECT  26.352 66.227 27.336 68.773 ;
     RECT  43.2 68.293 62.112 68.917 ;
     RECT  67.2 67.427 67.512 68.917 ;
     RECT  68.736 67.715 68.76 69.155 ;
     RECT  18.48 62.533 18.912 69.253 ;
     RECT  12.24 66.565 13.512 69.301 ;
     RECT  18.336 69.253 18.912 69.395 ;
     RECT  20.928 68.341 21.864 69.397 ;
     RECT  38.352 68.341 38.472 69.397 ;
     RECT  6.864 65.845 8.112 69.491 ;
     RECT  38.352 69.397 38.76 69.493 ;
     RECT  66.528 68.917 67.512 69.493 ;
     RECT  63.84 68.341 63.864 69.587 ;
     RECT  34.8 68.341 35.352 69.971 ;
     RECT  42.768 68.917 62.112 69.973 ;
     RECT  42.768 69.973 62.856 70.019 ;
     RECT  11.472 69.301 13.512 70.069 ;
     RECT  23.616 68.773 27.336 70.069 ;
     RECT  72.6 66.755 72.912 70.069 ;
     RECT  66.528 69.493 68.712 70.163 ;
     RECT  20.16 69.397 21.864 70.259 ;
     RECT  37.632 69.493 38.76 70.259 ;
     RECT  65.28 67.381 65.304 70.499 ;
     RECT  18.432 69.395 18.912 70.645 ;
     RECT  72.48 70.069 72.912 70.691 ;
     RECT  23.616 70.069 27.912 70.739 ;
     RECT  38.448 70.259 38.76 70.739 ;
     RECT  43.488 70.019 62.856 70.739 ;
     RECT  23.616 70.739 24.504 70.835 ;
     RECT  43.488 70.739 62.112 71.075 ;
     RECT  25.584 70.739 27.912 71.123 ;
     RECT  67.2 70.163 68.712 71.123 ;
     RECT  11.472 70.069 13.848 71.315 ;
     RECT  74.256 70.405 74.28 71.315 ;
     RECT  15.408 70.645 15.432 71.363 ;
     RECT  43.68 71.075 62.112 71.363 ;
     RECT  7.8 69.491 8.112 71.413 ;
     RECT  40.2 59.459 40.512 71.701 ;
     RECT  34.8 69.971 35.112 71.749 ;
     RECT  29.136 68.435 29.712 71.797 ;
     RECT  18.432 70.645 19.416 71.843 ;
     RECT  43.68 71.363 59.832 71.843 ;
     RECT  18.432 71.843 19.32 71.845 ;
     RECT  23.616 70.835 24.312 71.939 ;
     RECT  72.6 70.691 72.912 71.989 ;
     RECT  70.128 67.427 70.152 72.325 ;
     RECT  29.136 71.797 29.88 72.373 ;
     RECT  20.928 70.259 21.864 72.419 ;
     RECT  38.448 70.739 38.472 72.419 ;
     RECT  34.704 71.749 35.112 72.467 ;
     RECT  70.128 72.325 71.064 72.659 ;
     RECT  81.552 70.645 81.576 72.659 ;
     RECT  20.928 72.419 20.952 72.661 ;
     RECT  43.728 71.843 59.832 72.661 ;
     RECT  11.472 71.315 13.512 72.707 ;
     RECT  20.784 72.661 20.952 72.707 ;
     RECT  29.088 72.373 29.88 72.755 ;
     RECT  16.8 70.933 16.824 72.851 ;
     RECT  18.336 71.845 19.32 72.853 ;
     RECT  29.184 72.755 29.88 72.899 ;
     RECT  18.336 72.853 19.704 72.901 ;
     RECT  20.784 72.707 20.808 72.901 ;
     RECT  29.4 72.899 29.88 72.901 ;
     RECT  7.8 71.413 9.096 72.947 ;
     RECT  77.76 67.523 78.312 72.995 ;
     RECT  61.056 71.363 62.112 73.045 ;
     RECT  72.48 71.989 72.912 73.139 ;
     RECT  12.48 72.707 13.512 73.331 ;
     RECT  18.336 72.901 20.808 73.379 ;
     RECT  18.336 73.379 20.52 73.475 ;
     RECT  41.952 73.333 41.976 73.477 ;
     RECT  43.728 72.661 59.976 73.477 ;
     RECT  60.96 73.045 62.112 73.477 ;
     RECT  11.376 72.805 11.4 73.571 ;
     RECT  18.336 73.475 19.704 73.571 ;
     RECT  12.528 73.331 13.512 73.763 ;
     RECT  25.584 71.123 27.768 73.763 ;
     RECT  24 71.939 24.312 73.909 ;
     RECT  18.336 73.571 18.912 74.053 ;
     RECT  25.584 73.763 26.568 74.291 ;
     RECT  25.68 74.291 26.568 74.339 ;
     RECT  70.128 72.659 70.152 74.581 ;
     RECT  27.744 73.763 27.768 74.675 ;
     RECT  17.376 74.053 18.912 74.723 ;
     RECT  24 73.909 24.408 74.723 ;
     RECT  26.208 74.339 26.568 74.723 ;
     RECT  17.376 74.723 17.4 74.915 ;
     RECT  34.8 72.467 35.112 75.013 ;
     RECT  7.8 72.947 8.472 75.109 ;
     RECT  43.728 73.477 62.112 75.205 ;
     RECT  68.688 71.123 68.712 75.299 ;
     RECT  39.888 71.701 40.512 75.397 ;
     RECT  34.8 75.013 35.592 75.443 ;
     RECT  7.8 75.109 8.52 75.493 ;
     RECT  74.016 74.005 74.04 75.923 ;
     RECT  70.128 74.581 70.392 75.971 ;
     RECT  26.256 74.723 26.568 76.021 ;
     RECT  18.432 74.723 18.912 76.165 ;
     RECT  6.864 75.493 8.52 76.403 ;
     RECT  43.728 75.205 62.232 76.403 ;
     RECT  38.976 75.397 40.512 76.499 ;
     RECT  18.288 76.165 18.912 76.597 ;
     RECT  39.888 76.499 40.512 76.597 ;
     RECT  41.952 73.477 42.504 76.597 ;
     RECT  39.888 76.597 42.504 76.643 ;
     RECT  17.616 76.597 18.912 76.835 ;
     RECT  26.256 76.021 27.432 76.837 ;
     RECT  39.888 76.643 41.976 76.931 ;
     RECT  44.688 76.403 62.232 76.979 ;
     RECT  7.8 76.403 8.52 77.555 ;
     RECT  29.4 72.901 30.024 77.555 ;
     RECT  32.832 71.221 32.856 77.555 ;
     RECT  40.032 76.931 41.976 77.555 ;
     RECT  26.208 76.837 27.432 78.227 ;
     RECT  44.688 76.979 62.112 78.421 ;
     RECT  32.784 78.037 32.808 78.613 ;
     RECT  44.688 78.421 62.232 78.707 ;
     RECT  31.92 78.613 32.808 78.803 ;
     RECT  40.032 77.555 41.064 78.899 ;
     RECT  45.12 78.707 62.232 78.995 ;
     RECT  34.8 75.443 35.112 79.189 ;
     RECT  26.208 78.227 26.568 79.237 ;
     RECT  19.92 78.613 19.944 79.283 ;
     RECT  40.032 78.899 40.512 79.283 ;
     RECT  34.176 79.189 35.112 79.525 ;
     RECT  29.4 77.555 29.712 79.717 ;
     RECT  45.12 78.995 62.112 79.717 ;
     RECT  32.784 78.803 32.808 79.763 ;
     RECT  25.968 79.237 26.568 79.811 ;
     RECT  26.544 79.811 26.568 80.435 ;
     RECT  34.176 79.525 35.208 80.869 ;
     RECT  45.024 79.717 62.112 81.157 ;
     RECT  18.432 76.835 18.912 81.203 ;
     RECT  44.88 81.157 62.112 81.349 ;
     RECT  25.68 80.917 25.704 81.445 ;
     RECT  29.04 79.717 29.712 81.539 ;
     RECT  34.176 80.869 35.256 81.539 ;
     RECT  43.536 81.493 43.56 82.021 ;
     RECT  27.936 81.493 27.96 82.211 ;
     RECT  31.824 81.301 31.848 82.211 ;
     RECT  42.72 82.021 43.56 82.213 ;
     RECT  44.688 81.349 62.112 82.213 ;
     RECT  34.8 81.539 35.256 82.499 ;
     RECT  41.664 81.925 41.688 82.499 ;
     RECT  42.72 82.213 62.112 82.547 ;
     RECT  25.68 81.445 25.8 82.691 ;
     RECT  43.536 82.547 62.112 82.691 ;
     RECT  44.88 82.691 62.112 82.739 ;
     RECT  43.536 82.691 43.56 82.787 ;
     RECT  25.776 82.691 25.8 82.979 ;
     RECT  45.6 82.739 62.112 82.979 ;
     RECT  45.6 82.979 60.552 83.267 ;
     RECT  42.144 83.173 42.168 83.651 ;
     RECT  46.896 83.267 60.552 83.891 ;
     RECT  2.4 37.283 2.712 84.249 ;
     RECT  7.8 77.555 8.112 84.249 ;
     RECT  13.2 73.763 13.512 84.249 ;
     RECT  18.6 81.203 18.912 84.249 ;
     RECT  24 74.723 24.312 84.249 ;
     RECT  29.4 81.539 29.712 84.249 ;
     RECT  34.8 82.499 35.112 84.249 ;
     RECT  40.2 79.283 40.512 84.249 ;
     RECT  45.6 83.267 45.912 84.249 ;
     RECT  61.8 82.979 62.112 84.249 ;
     RECT  67.2 71.123 67.512 84.249 ;
     RECT  72.6 73.139 72.912 84.249 ;
     RECT  78 72.995 78.312 84.249 ;
     RECT  83.4 67.283 83.712 84.249 ;
     RECT  2.4 84.249 2.52 84.263 ;
     RECT  7.8 84.249 7.92 84.263 ;
     RECT  13.2 84.249 13.32 84.263 ;
     RECT  18.6 84.249 18.72 84.263 ;
     RECT  24 84.249 24.12 84.263 ;
     RECT  29.4 84.249 29.52 84.263 ;
     RECT  34.8 84.249 34.92 84.263 ;
     RECT  40.2 84.249 40.32 84.263 ;
     RECT  45.6 84.249 45.72 84.263 ;
     RECT  61.8 84.249 62.088 84.263 ;
     RECT  67.2 84.249 67.32 84.263 ;
     RECT  72.6 84.249 72.72 84.263 ;
     RECT  78 84.249 78.12 84.263 ;
     RECT  83.4 84.249 83.52 84.263 ;
     RECT  46.896 83.891 59.976 84.325 ;
     RECT  46.8 84.325 59.976 86.352 ;
     RECT  19.728 1.187 19.824 1.763 ;
     RECT  19.728 1.763 20.208 2.137 ;
     RECT  49.416 1.763 49.512 2.137 ;
     RECT  67.056 1.763 67.2 2.821 ;
     RECT  33.384 1.811 34.512 2.291 ;
     RECT  35.304 1.811 35.496 2.291 ;
     RECT  24.504 1.859 26.064 3.301 ;
     RECT  46.92 1.907 47.952 3.301 ;
     RECT  18.72 2.137 20.208 2.151 ;
     RECT  49.416 2.137 51 2.245 ;
     RECT  19.08 2.151 20.208 4.019 ;
     RECT  67.608 2.243 68.232 3.397 ;
     RECT  49.416 2.245 50.592 3.443 ;
     RECT  35.112 2.291 35.496 2.821 ;
     RECT  8.112 2.677 9.504 3.397 ;
     RECT  11.4 2.677 12.912 4.691 ;
     RECT  35.112 2.821 36.336 4.741 ;
     RECT  36.36 2.917 37.632 4.115 ;
     RECT  42.744 3.109 43.92 3.443 ;
     RECT  8.232 3.397 9.504 3.443 ;
     RECT  49.416 3.443 50.88 3.491 ;
     RECT  49.32 3.491 50.88 4.019 ;
     RECT  51.312 3.925 52.56 4.547 ;
     RECT  19.032 4.019 20.208 4.115 ;
     RECT  25.128 4.019 26.04 5.077 ;
     RECT  48.648 4.019 50.88 4.501 ;
     RECT  32.808 4.067 33 5.557 ;
     RECT  18.912 4.115 20.208 4.981 ;
     RECT  36.36 4.115 37.608 4.787 ;
     RECT  67.512 4.163 68.544 11.987 ;
     RECT  48.648 4.501 49.728 5.171 ;
     RECT  49.752 4.501 50.88 5.749 ;
     RECT  71.304 4.501 72.6 5.125 ;
     RECT  40.512 4.547 41.016 5.605 ;
     RECT  51.312 4.547 52.584 5.845 ;
     RECT  47.256 4.595 48.624 5.171 ;
     RECT  61.68 4.595 61.8 4.837 ;
     RECT  45.912 4.643 46.896 5.893 ;
     RECT  37.584 4.787 37.608 5.029 ;
     RECT  60.744 4.837 61.8 9.973 ;
     RECT  18.912 4.981 19.92 6.421 ;
     RECT  44.616 4.981 45.6 6.611 ;
     RECT  17.16 5.077 18.6 5.747 ;
     RECT  49.584 5.171 49.728 6.037 ;
     RECT  76.824 5.173 78 6.851 ;
     RECT  43.464 5.317 44.592 6.373 ;
     RECT  7.68 5.651 7.8 5.701 ;
     RECT  6.696 5.701 7.8 9.349 ;
     RECT  51.312 5.845 52.656 8.869 ;
     RECT  40.512 6.179 41.616 6.851 ;
     RECT  44.472 6.611 45.6 11.219 ;
     RECT  19.032 6.803 20.448 8.435 ;
     RECT  40.512 6.851 41.64 7.861 ;
     RECT  22.728 7.285 24 7.381 ;
     RECT  49.608 7.379 50.88 9.013 ;
     RECT  64.8 7.619 64.824 8.485 ;
     RECT  43.368 7.859 44.448 8.821 ;
     RECT  40.512 7.861 42.144 7.909 ;
     RECT  42.168 7.861 43.344 8.483 ;
     RECT  40.872 7.909 42.144 8.483 ;
     RECT  18.912 8.435 20.448 9.349 ;
     RECT  59.352 8.485 60.72 8.677 ;
     RECT  64.8 8.485 64.944 9.013 ;
     RECT  30.504 8.677 31.872 11.123 ;
     RECT  59.448 8.677 60.72 10.019 ;
     RECT  51.312 8.869 52.512 9.059 ;
     RECT  22.728 9.011 24 10.403 ;
     RECT  62.112 9.013 63.264 9.875 ;
     RECT  63.288 9.013 64.944 9.061 ;
     RECT  51.312 9.059 52.656 10.403 ;
     RECT  63.288 9.061 64.704 9.731 ;
     RECT  16.248 9.109 17.664 9.779 ;
     RECT  49.56 9.251 50.88 10.355 ;
     RECT  6.696 9.349 7.68 10.019 ;
     RECT  18.912 9.349 20.304 11.317 ;
     RECT  25.128 9.395 26.448 10.547 ;
     RECT  40.512 9.539 40.872 10.981 ;
     RECT  38.808 9.589 39.792 10.741 ;
     RECT  38.208 9.635 38.784 9.925 ;
     RECT  46.488 9.731 46.68 11.173 ;
     RECT  63.288 9.731 63.48 9.875 ;
     RECT  62.112 9.875 63.48 10.117 ;
     RECT  37.752 9.925 38.784 10.883 ;
     RECT  6.696 10.019 7.8 12.803 ;
     RECT  59.448 10.019 61.008 10.501 ;
     RECT  56.712 10.069 58.128 10.883 ;
     RECT  58.152 10.069 59.328 10.883 ;
     RECT  62.112 10.117 63.456 10.643 ;
     RECT  27.24 10.309 28.752 11.987 ;
     RECT  50.544 10.355 50.88 10.837 ;
     RECT  31.896 10.453 33.408 11.123 ;
     RECT  33.432 10.453 34.8 11.123 ;
     RECT  59.544 10.501 61.008 11.413 ;
     RECT  25.128 10.547 25.56 10.837 ;
     RECT  24.312 10.883 25.536 14.867 ;
     RECT  56.712 10.883 59.328 10.933 ;
     RECT  56.808 10.933 59.328 12.229 ;
     RECT  30.504 11.123 30.84 11.269 ;
     RECT  19.032 11.317 20.304 11.843 ;
     RECT  71.448 11.941 72.6 12.755 ;
     RECT  27.24 11.987 29.4 12.517 ;
     RECT  67.512 11.987 68.688 12.949 ;
     RECT  59.544 12.227 61.008 12.275 ;
     RECT  56.808 12.229 58.656 12.277 ;
     RECT  77.616 12.275 78 13.717 ;
     RECT  56.808 12.277 58.128 13.045 ;
     RECT  28.2 12.517 29.4 14.867 ;
     RECT  46.68 12.997 47.856 13.379 ;
     RECT  56.808 13.045 58.08 14.389 ;
     RECT  46.104 13.379 47.856 14.341 ;
     RECT  72.912 13.429 74.256 15.395 ;
     RECT  44.424 13.573 45.6 15.683 ;
     RECT  68.136 14.147 68.28 15.349 ;
     RECT  33.768 14.245 34.8 16.547 ;
     RECT  46.104 14.341 47.424 14.915 ;
     RECT  47.448 14.387 47.88 14.629 ;
     RECT  47.448 14.629 48.96 14.915 ;
     RECT  51.72 14.773 53.136 14.915 ;
     RECT  74.28 14.773 75.792 15.395 ;
     RECT  80.208 14.867 80.232 15.301 ;
     RECT  56.808 15.203 58.08 15.443 ;
     RECT  80.184 15.301 80.232 15.973 ;
     RECT  56.712 15.443 58.08 16.933 ;
     RECT  58.728 15.443 59.808 16.259 ;
     RECT  45.024 15.683 45.6 15.925 ;
     RECT  38.76 16.069 39.792 17.651 ;
     RECT  58.344 16.259 59.808 20.579 ;
     RECT  26.136 16.549 27.216 17.315 ;
     RECT  56.712 16.933 57.888 17.029 ;
     RECT  60.168 16.933 61.68 17.411 ;
     RECT  2.712 17.077 3.792 17.699 ;
     RECT  24.984 17.077 26.112 17.315 ;
     RECT  40.68 17.125 41.904 17.173 ;
     RECT  16.104 17.219 17.064 18.181 ;
     RECT  18.912 17.699 20.304 18.419 ;
     RECT  16.104 18.181 17.472 19.379 ;
     RECT  17.496 18.181 18.6 19.379 ;
     RECT  18.912 18.419 20.352 20.867 ;
     RECT  17.712 19.379 18.6 20.533 ;
     RECT  22.776 19.909 24 20.051 ;
     RECT  21.048 19.957 22.464 20.579 ;
     RECT  22.488 20.051 24 20.579 ;
     RECT  71.544 20.149 72.6 22.211 ;
     RECT  78.408 20.579 79.272 21.253 ;
     RECT  38.328 21.061 39.792 22.693 ;
     RECT  56.712 21.155 57.744 25.715 ;
     RECT  78.408 21.253 79.776 22.259 ;
     RECT  29.712 21.781 31.104 22.451 ;
     RECT  31.128 21.781 32.592 21.827 ;
     RECT  38.328 22.693 39.36 23.843 ;
     RECT  60.456 22.741 61.8 23.843 ;
     RECT  80.856 23.795 80.952 25.045 ;
     RECT  38.328 23.843 39.648 24.469 ;
     RECT  24.312 23.893 25.776 25.331 ;
     RECT  25.8 23.893 27.216 25.331 ;
     RECT  38.472 24.469 39.648 25.139 ;
     RECT  62.112 24.469 63.312 25.235 ;
     RECT  38.304 24.515 38.448 25.621 ;
     RECT  16.776 24.757 18.288 25.091 ;
     RECT  2.712 24.947 3.528 25.045 ;
     RECT  29.712 24.997 30.864 28.115 ;
     RECT  2.712 25.045 3.792 26.243 ;
     RECT  65.88 25.045 67.2 33.301 ;
     RECT  38.472 25.139 39.792 29.123 ;
     RECT  24.312 25.331 24.408 26.197 ;
     RECT  40.512 26.197 41.568 26.485 ;
     RECT  2.712 26.243 3.528 26.725 ;
     RECT  40.512 26.485 41.52 28.595 ;
     RECT  63.648 26.819 63.672 27.877 ;
     RECT  54.744 27.347 54.84 28.115 ;
     RECT  41.544 27.491 41.592 28.453 ;
     RECT  2.712 27.635 3.528 28.453 ;
     RECT  18.912 27.923 19.368 27.925 ;
     RECT  18.912 27.925 19.968 31.379 ;
     RECT  19.992 27.925 21.216 28.979 ;
     RECT  29.712 28.115 31.008 28.693 ;
     RECT  54.12 28.115 54.84 28.789 ;
     RECT  2.712 28.453 3.936 29.363 ;
     RECT  63.672 28.453 64.992 28.691 ;
     RECT  42.24 28.595 42.336 29.219 ;
     RECT  29.976 28.693 31.008 30.373 ;
     RECT  49.92 28.739 50.688 29.605 ;
     RECT  54.12 28.789 55.248 30.083 ;
     RECT  55.272 28.789 56.4 30.083 ;
     RECT  42.24 29.219 42.264 29.989 ;
     RECT  60.864 29.219 61.8 29.461 ;
     RECT  2.712 29.363 3.96 30.757 ;
     RECT  72.336 29.363 72.6 30.709 ;
     RECT  45.912 29.365 47.184 30.035 ;
     RECT  62.112 29.365 63.12 30.373 ;
     RECT  58.824 29.461 60.288 30.181 ;
     RECT  60.312 29.461 61.8 34.741 ;
     RECT  24.312 29.509 25.344 32.869 ;
     RECT  49.656 29.605 50.688 29.699 ;
     RECT  49.656 29.699 50.832 30.371 ;
     RECT  56.304 30.083 56.4 30.805 ;
     RECT  58.824 30.181 59.952 31.525 ;
     RECT  49.656 30.371 51 31.379 ;
     RECT  19.992 30.613 21.12 31.379 ;
     RECT  2.712 30.757 3.984 31.379 ;
     RECT  57.48 30.947 58.704 33.107 ;
     RECT  29.712 31.139 30.72 33.731 ;
     RECT  67.512 31.379 68.64 33.253 ;
     RECT  58.92 31.525 59.952 31.765 ;
     RECT  71.4 31.571 72.6 32.531 ;
     RECT  16.968 31.813 18 31.955 ;
     RECT  76.344 31.813 77.616 31.955 ;
     RECT  17.952 31.955 18 32.437 ;
     RECT  53.52 32.099 54.096 33.589 ;
     RECT  13.512 32.437 14.976 33.445 ;
     RECT  71.76 32.531 72.6 33.445 ;
     RECT  23.016 32.917 24 38.005 ;
     RECT  81.912 33.013 83.4 34.117 ;
     RECT  57.48 33.107 58.752 33.251 ;
     RECT  57.48 33.251 57.576 34.165 ;
     RECT  13.512 33.445 14.832 34.259 ;
     RECT  44.472 33.587 45.6 34.835 ;
     RECT  25.752 33.589 27.168 35.603 ;
     RECT  72.912 34.069 74.256 36.851 ;
     RECT  81.912 34.117 83.184 34.163 ;
     RECT  83.136 34.163 83.184 35.077 ;
     RECT  24.312 34.259 25.344 42.949 ;
     RECT  32.472 34.405 33.744 34.739 ;
     RECT  60.312 34.741 61.344 34.835 ;
     RECT  60.264 34.835 61.344 40.259 ;
     RECT  2.712 34.931 2.808 36.325 ;
     RECT  36.024 35.507 37.008 36.515 ;
     RECT  27.072 35.603 27.168 35.701 ;
     RECT  65.88 35.987 67.2 36.515 ;
     RECT  62.112 36.083 62.808 36.901 ;
     RECT  67.512 36.323 68.64 37.861 ;
     RECT  54.12 36.515 54.744 37.093 ;
     RECT  49.56 36.661 51 37.573 ;
     RECT  72.912 36.851 73.176 37.333 ;
     RECT  62.112 36.901 63.216 37.667 ;
     RECT  54.12 37.093 55.44 37.477 ;
     RECT  54.12 37.477 55.392 38.195 ;
     RECT  49.992 37.573 51 38.581 ;
     RECT  31.32 37.621 32.448 37.859 ;
     RECT  8.112 37.667 8.472 38.677 ;
     RECT  62.112 37.667 63.144 39.061 ;
     RECT  19.752 38.149 21.168 41.605 ;
     RECT  81 38.149 82.512 38.197 ;
     RECT  53.928 38.195 55.392 40.549 ;
     RECT  81.192 38.197 82.512 39.059 ;
     RECT  55.416 38.675 56.4 55.475 ;
     RECT  62.112 39.061 63.12 40.067 ;
     RECT  47.256 39.205 48.768 39.637 ;
     RECT  43.512 39.301 44.976 39.781 ;
     RECT  29.28 39.347 29.4 40.549 ;
     RECT  40.512 39.349 41.568 40.019 ;
     RECT  56.712 39.395 57.696 53.221 ;
     RECT  47.64 39.637 48.768 39.733 ;
     RECT  43.512 39.781 44.688 39.923 ;
     RECT  43.488 39.923 44.688 40.981 ;
     RECT  60.216 40.259 61.344 40.451 ;
     RECT  60.216 40.451 61.536 40.739 ;
     RECT  28.008 40.549 29.4 41.557 ;
     RECT  54.12 40.549 55.392 43.333 ;
     RECT  52.632 40.837 53.904 40.981 ;
     RECT  43.464 40.981 44.688 43.813 ;
     RECT  28.008 41.557 29.28 42.467 ;
     RECT  72.912 41.651 73.656 42.133 ;
     RECT  67.8 41.699 68.784 45.059 ;
     RECT  65.88 42.085 67.2 44.725 ;
     RECT  72.912 42.133 74.256 42.851 ;
     RECT  28.032 42.467 29.28 43.285 ;
     RECT  48.072 42.467 49.2 43.235 ;
     RECT  42.072 42.469 43.44 43.523 ;
     RECT  49.224 42.755 50.688 43.379 ;
     RECT  51.864 42.851 52.848 43.379 ;
     RECT  68.808 43.045 70.128 45.059 ;
     RECT  47.928 43.235 49.2 43.379 ;
     RECT  28.056 43.285 29.28 44.627 ;
     RECT  54.216 43.333 55.392 43.475 ;
     RECT  51.432 43.379 52.848 44.053 ;
     RECT  53.928 43.475 55.392 55.429 ;
     RECT  6.312 43.717 7.8 44.197 ;
     RECT  51.432 44.053 52.752 44.099 ;
     RECT  19.752 44.099 21.168 45.587 ;
     RECT  51.312 44.099 52.752 44.821 ;
     RECT  33.624 44.437 34.8 45.059 ;
     RECT  28.032 44.627 29.28 44.965 ;
     RECT  11.832 44.677 13.104 45.635 ;
     RECT  6.312 44.723 7.8 45.635 ;
     RECT  65.88 44.725 67.104 46.693 ;
     RECT  51.312 44.821 52.416 45.683 ;
     RECT  21.672 44.965 22.992 45.013 ;
     RECT  28.008 44.965 29.28 45.587 ;
     RECT  59.64 44.965 61.104 46.499 ;
     RECT  21.672 45.013 22.752 45.541 ;
     RECT  26.664 45.397 27.984 45.587 ;
     RECT  72.912 45.541 74.064 46.883 ;
     RECT  19.512 45.587 21.168 45.635 ;
     RECT  29.088 45.587 29.28 46.213 ;
     RECT  11.808 45.635 13.104 46.117 ;
     RECT  19.512 45.635 22.32 46.021 ;
     RECT  19.512 46.021 20.496 48.613 ;
     RECT  20.52 46.021 22.32 46.645 ;
     RECT  11.808 46.117 12.528 46.645 ;
     RECT  10.248 46.645 11.664 47.699 ;
     RECT  21.096 46.645 22.32 47.315 ;
     RECT  62.112 46.645 63.552 46.883 ;
     RECT  66.072 46.693 67.104 48.901 ;
     RECT  37.584 46.787 38.544 47.701 ;
     RECT  29.712 46.789 30.72 48.949 ;
     RECT  38.856 47.411 40.08 48.421 ;
     RECT  11.88 47.459 13.2 48.901 ;
     RECT  47.256 47.605 48.528 47.939 ;
     RECT  10.152 47.699 11.664 49.237 ;
     RECT  37.08 47.701 38.544 47.891 ;
     RECT  37.056 47.891 38.544 48.901 ;
     RECT  42.168 47.893 43.44 49.763 ;
     RECT  26.136 48.421 27.312 49.379 ;
     RECT  44.088 48.515 45.216 49.861 ;
     RECT  37.08 48.901 38.544 49.043 ;
     RECT  66.072 48.901 67.056 51.923 ;
     RECT  59.64 48.949 61.008 50.147 ;
     RECT  8.112 48.997 9.12 49.139 ;
     RECT  8.112 49.139 10.032 49.189 ;
     RECT  8.952 49.189 10.032 49.331 ;
     RECT  10.248 49.237 11.664 50.387 ;
     RECT  35.112 49.285 36.096 49.571 ;
     RECT  8.856 49.331 10.032 50.915 ;
     RECT  25.224 49.379 25.368 50.581 ;
     RECT  30.792 49.571 30.888 50.629 ;
     RECT  35.112 49.571 35.976 49.621 ;
     RECT  12.024 49.619 13.104 49.763 ;
     RECT  12.024 49.763 13.2 50.771 ;
     RECT  59.64 50.147 59.928 51.637 ;
     RECT  17.088 50.579 17.232 51.011 ;
     RECT  33.672 50.773 34.8 51.875 ;
     RECT  8.856 50.915 10.224 54.371 ;
     RECT  43.464 50.963 44.976 51.347 ;
     RECT  17.088 51.011 17.616 51.301 ;
     RECT  20.952 51.253 21.936 52.451 ;
     RECT  21.96 51.253 23.28 51.347 ;
     RECT  70.152 51.253 71.28 55.427 ;
     RECT  16.248 51.301 17.616 51.923 ;
     RECT  21.96 51.347 23.328 51.491 ;
     RECT  42.264 51.493 43.44 52.499 ;
     RECT  65.544 51.923 67.056 53.123 ;
     RECT  30.264 51.971 31.584 53.123 ;
     RECT  20.952 52.451 21.816 53.269 ;
     RECT  18.912 52.739 20.352 53.795 ;
     RECT  25.224 52.979 26.304 53.075 ;
     RECT  24.312 53.075 24.456 54.133 ;
     RECT  21.384 53.269 21.816 53.557 ;
     RECT  52.488 53.557 53.904 56.869 ;
     RECT  38.856 53.603 39.936 54.131 ;
     RECT  56.712 53.939 57.696 55.331 ;
     RECT  48.84 54.037 50.256 54.085 ;
     RECT  59.928 54.085 61.248 55.285 ;
     RECT  38.856 54.131 40.08 54.179 ;
     RECT  74.088 54.565 75.264 55.955 ;
     RECT  43.896 54.613 45.216 55.715 ;
     RECT  22.728 54.661 24 58.739 ;
     RECT  24.408 54.707 24.456 54.853 ;
     RECT  24.408 54.853 25.392 57.347 ;
     RECT  60.168 55.285 61.248 57.157 ;
     RECT  56.712 55.331 57.84 56.053 ;
     RECT  70.152 55.427 71.376 57.635 ;
     RECT  53.928 55.429 55.296 56.291 ;
     RECT  55.32 55.475 56.4 56.291 ;
     RECT  43.848 55.715 45.216 57.731 ;
     RECT  78.456 55.763 78.696 57.013 ;
     RECT  75.792 55.955 75.84 57.299 ;
     RECT  56.856 56.053 57.84 56.291 ;
     RECT  26.328 56.101 27.408 57.059 ;
     RECT  56.712 56.291 57.84 58.405 ;
     RECT  52.488 56.869 53.712 56.965 ;
     RECT  26.328 57.059 26.376 57.205 ;
     RECT  51.312 57.059 52.464 57.107 ;
     RECT  51.312 57.107 52.512 58.549 ;
     RECT  75.792 57.299 75.816 57.445 ;
     RECT  20.952 57.347 22.032 61.619 ;
     RECT  27.96 57.541 29.4 59.267 ;
     RECT  43.464 57.731 45.216 58.021 ;
     RECT  64.968 57.877 66 58.403 ;
     RECT  66.024 57.877 67.2 58.547 ;
     RECT  43.464 58.021 45.168 58.069 ;
     RECT  43.464 58.069 44.496 59.939 ;
     RECT  57.864 58.163 58.056 59.221 ;
     RECT  72.192 58.163 72.24 59.221 ;
     RECT  66.96 58.547 67.2 59.989 ;
     RECT  51.312 58.549 52.464 58.597 ;
     RECT  51.312 58.597 52.32 60.373 ;
     RECT  26.376 58.645 27.504 59.077 ;
     RECT  42.264 58.645 43.44 59.267 ;
     RECT  24.312 58.739 24.408 59.701 ;
     RECT  54.12 59.221 55.584 60.229 ;
     RECT  57.864 59.221 58.848 60.277 ;
     RECT  70.152 59.221 71.28 62.581 ;
     RECT  56.712 59.459 57.84 62.677 ;
     RECT  77.472 59.459 78 59.557 ;
     RECT  76.536 59.557 78 64.741 ;
     RECT  24.84 59.701 26.352 61.477 ;
     RECT  43.464 59.939 44.688 60.467 ;
     RECT  54.216 60.229 55.584 60.565 ;
     RECT  47.304 60.373 48.384 61.477 ;
     RECT  43.464 60.467 43.512 61.189 ;
     RECT  71.304 60.467 72.6 61.861 ;
     RECT  54.36 60.565 55.584 62.053 ;
     RECT  57.864 61.043 58.848 61.619 ;
     RECT  20.952 61.619 21.096 61.765 ;
     RECT  71.496 61.861 72.6 64.019 ;
     RECT  55.272 62.099 56.4 63.781 ;
     RECT  45.504 62.243 45.6 63.205 ;
     RECT  38.808 62.581 40.2 62.723 ;
     RECT  70.152 62.723 71.472 64.019 ;
     RECT  59.52 64.115 60.144 64.933 ;
     RECT  67.512 64.597 68.832 67.381 ;
     RECT  68.856 64.597 70.128 66.085 ;
     RECT  81.96 64.645 83.4 65.075 ;
     RECT  76.776 64.741 78 65.941 ;
     RECT  58.008 64.933 60.144 65.125 ;
     RECT  58.248 65.125 60.144 65.365 ;
     RECT  58.776 65.365 60.144 67.189 ;
     RECT  33.48 65.653 34.8 65.795 ;
     RECT  60.456 65.989 61.8 67.477 ;
     RECT  68.856 66.085 69.984 67.427 ;
     RECT  25.272 66.227 26.352 68.773 ;
     RECT  27.336 66.901 28.656 68.435 ;
     RECT  20.952 67.187 21.096 68.341 ;
     RECT  43.752 67.237 45.168 67.525 ;
     RECT  67.512 67.381 68.736 69.155 ;
     RECT  66.96 67.427 67.2 68.917 ;
     RECT  68.856 67.427 70.128 67.715 ;
     RECT  60.456 67.477 61.536 67.669 ;
     RECT  43.8 67.525 45.168 67.765 ;
     RECT  68.76 67.715 70.128 69.155 ;
     RECT  43.848 67.765 45.168 68.293 ;
     RECT  42.216 67.859 43.2 68.675 ;
     RECT  21.864 68.341 23.328 68.435 ;
     RECT  63.864 68.341 65.28 69.587 ;
     RECT  42.768 68.675 43.2 68.917 ;
     RECT  65.304 68.917 66.528 70.163 ;
     RECT  67.512 69.155 70.128 69.493 ;
     RECT  18.912 69.397 20.16 70.259 ;
     RECT  38.76 69.397 40.2 70.739 ;
     RECT  68.712 69.493 70.128 75.299 ;
     RECT  27.912 70.069 29.136 71.123 ;
     RECT  18.912 70.259 20.928 70.645 ;
     RECT  72.912 70.405 74.256 71.315 ;
     RECT  19.416 70.645 20.928 71.843 ;
     RECT  72.48 70.691 72.6 71.989 ;
     RECT  24.504 70.739 25.584 70.835 ;
     RECT  38.472 70.739 40.2 71.701 ;
     RECT  24.312 70.835 25.584 73.909 ;
     RECT  15.432 70.933 16.8 71.363 ;
     RECT  27.768 71.123 29.136 72.373 ;
     RECT  67.512 71.123 68.688 75.299 ;
     RECT  59.832 71.363 61.056 72.661 ;
     RECT  38.472 71.701 39.888 72.419 ;
     RECT  19.32 71.843 20.928 72.661 ;
     RECT  16.824 71.845 18.336 72.851 ;
     RECT  71.064 72.325 72.48 72.659 ;
     RECT  27.768 72.373 29.088 72.755 ;
     RECT  19.32 72.661 20.784 72.853 ;
     RECT  59.976 72.661 61.056 73.045 ;
     RECT  11.472 72.707 12.48 72.805 ;
     RECT  27.768 72.755 29.184 72.899 ;
     RECT  11.4 72.805 12.48 73.331 ;
     RECT  17.376 72.851 18.336 74.053 ;
     RECT  19.704 72.853 20.784 72.901 ;
     RECT  59.976 73.045 60.96 73.477 ;
     RECT  11.4 73.331 12.528 73.571 ;
     RECT  40.512 73.333 41.952 76.597 ;
     RECT  42.504 73.477 43.728 76.403 ;
     RECT  26.568 73.763 27.744 74.675 ;
     RECT  24.408 73.909 25.584 74.291 ;
     RECT  72.912 74.005 74.016 75.923 ;
     RECT  24.408 74.291 25.68 74.339 ;
     RECT  26.568 74.675 27.432 76.021 ;
     RECT  17.4 74.723 18.432 74.915 ;
     RECT  18.288 74.915 18.432 76.165 ;
     RECT  62.112 76.979 62.232 78.421 ;
     RECT  18.912 78.613 19.92 79.283 ;
     RECT  45.024 78.707 45.12 79.717 ;
     RECT  32.808 79.189 34.176 79.763 ;
     RECT  24.312 80.917 25.68 82.691 ;
     RECT  27.96 81.493 29.04 81.539 ;
     RECT  43.56 81.493 44.688 82.213 ;
     RECT  27.96 81.539 29.4 82.211 ;
     RECT  40.512 81.925 41.664 82.499 ;
     RECT  41.688 82.021 42.72 82.499 ;
     RECT  42.144 82.499 42.72 82.547 ;
     RECT  42.144 82.547 43.536 82.787 ;
     RECT  24.312 82.691 25.776 82.979 ;
     RECT  43.56 82.691 44.88 82.739 ;
     RECT  42.144 82.787 42.168 83.173 ;
     RECT  60.552 82.979 61.8 83.891 ;
     RECT  45.912 83.267 46.896 84.249 ;
     RECT  45.72 84.249 46.896 84.263 ;
     RECT  46.8 84.263 46.896 84.325 ;
  END
END qkd_astk_zn
END LIBRARY
